# MODELED licensed PHY: geometry/timing assumptions, not silicon signoff
VERSION 5.8 ;
BUSBITCHARS "[]" ;
DIVIDERCHAR "/" ;
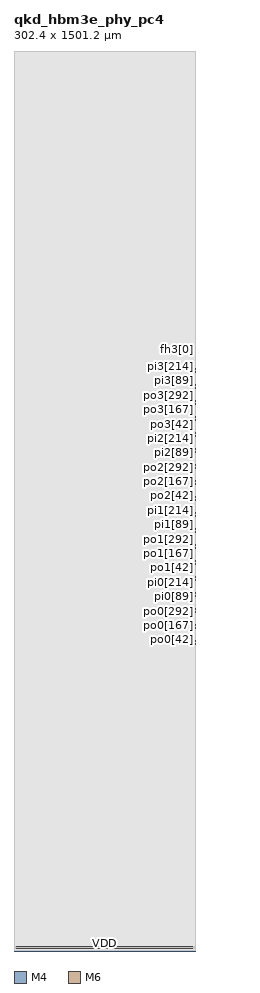
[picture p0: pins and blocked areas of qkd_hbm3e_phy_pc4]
MACRO qkd_hbm3e_phy_pc4
 CLASS BLOCK ;
 ORIGIN 0 0 ;
 SYMMETRY X Y ;
 SIZE 302.4 BY 1501.2 ;
 PIN clk
  DIRECTION INPUT ;
  USE CLOCK ;
  PORT
   LAYER M4 ;
   RECT 302.208000 510.540000 302.400000 510.564000 ;
  END
 END clk
 PIN rst_n
  DIRECTION INPUT ;
  USE SIGNAL ;
  PORT
   LAYER M4 ;
   RECT 302.208000 510.732000 302.400000 510.756000 ;
  END
 END rst_n
 PIN po0[0]
  DIRECTION INPUT ;
  USE SIGNAL ;
  PORT
   LAYER M4 ;
   RECT 302.208000 510.924000 302.400000 510.948000 ;
  END
 END po0[0]
 PIN po0[1]
  DIRECTION INPUT ;
  USE SIGNAL ;
  PORT
   LAYER M4 ;
   RECT 302.208000 511.116000 302.400000 511.140000 ;
  END
 END po0[1]
 PIN po0[2]
  DIRECTION INPUT ;
  USE SIGNAL ;
  PORT
   LAYER M4 ;
   RECT 302.208000 511.308000 302.400000 511.332000 ;
  END
 END po0[2]
 PIN po0[3]
  DIRECTION INPUT ;
  USE SIGNAL ;
  PORT
   LAYER M4 ;
   RECT 302.208000 511.500000 302.400000 511.524000 ;
  END
 END po0[3]
 PIN po0[4]
  DIRECTION INPUT ;
  USE SIGNAL ;
  PORT
   LAYER M4 ;
   RECT 302.208000 511.692000 302.400000 511.716000 ;
  END
 END po0[4]
 PIN po0[5]
  DIRECTION INPUT ;
  USE SIGNAL ;
  PORT
   LAYER M4 ;
   RECT 302.208000 511.884000 302.400000 511.908000 ;
  END
 END po0[5]
 PIN po0[6]
  DIRECTION INPUT ;
  USE SIGNAL ;
  PORT
   LAYER M4 ;
   RECT 302.208000 512.076000 302.400000 512.100000 ;
  END
 END po0[6]
 PIN po0[7]
  DIRECTION INPUT ;
  USE SIGNAL ;
  PORT
   LAYER M4 ;
   RECT 302.208000 512.268000 302.400000 512.292000 ;
  END
 END po0[7]
 PIN po0[8]
  DIRECTION INPUT ;
  USE SIGNAL ;
  PORT
   LAYER M4 ;
   RECT 302.208000 512.460000 302.400000 512.484000 ;
  END
 END po0[8]
 PIN po0[9]
  DIRECTION INPUT ;
  USE SIGNAL ;
  PORT
   LAYER M4 ;
   RECT 302.208000 512.652000 302.400000 512.676000 ;
  END
 END po0[9]
 PIN po0[10]
  DIRECTION INPUT ;
  USE SIGNAL ;
  PORT
   LAYER M4 ;
   RECT 302.208000 512.844000 302.400000 512.868000 ;
  END
 END po0[10]
 PIN po0[11]
  DIRECTION INPUT ;
  USE SIGNAL ;
  PORT
   LAYER M4 ;
   RECT 302.208000 513.036000 302.400000 513.060000 ;
  END
 END po0[11]
 PIN po0[12]
  DIRECTION INPUT ;
  USE SIGNAL ;
  PORT
   LAYER M4 ;
   RECT 302.208000 513.228000 302.400000 513.252000 ;
  END
 END po0[12]
 PIN po0[13]
  DIRECTION INPUT ;
  USE SIGNAL ;
  PORT
   LAYER M4 ;
   RECT 302.208000 513.420000 302.400000 513.444000 ;
  END
 END po0[13]
 PIN po0[14]
  DIRECTION INPUT ;
  USE SIGNAL ;
  PORT
   LAYER M4 ;
   RECT 302.208000 513.612000 302.400000 513.636000 ;
  END
 END po0[14]
 PIN po0[15]
  DIRECTION INPUT ;
  USE SIGNAL ;
  PORT
   LAYER M4 ;
   RECT 302.208000 513.804000 302.400000 513.828000 ;
  END
 END po0[15]
 PIN po0[16]
  DIRECTION INPUT ;
  USE SIGNAL ;
  PORT
   LAYER M4 ;
   RECT 302.208000 513.996000 302.400000 514.020000 ;
  END
 END po0[16]
 PIN po0[17]
  DIRECTION INPUT ;
  USE SIGNAL ;
  PORT
   LAYER M4 ;
   RECT 302.208000 514.188000 302.400000 514.212000 ;
  END
 END po0[17]
 PIN po0[18]
  DIRECTION INPUT ;
  USE SIGNAL ;
  PORT
   LAYER M4 ;
   RECT 302.208000 514.380000 302.400000 514.404000 ;
  END
 END po0[18]
 PIN po0[19]
  DIRECTION INPUT ;
  USE SIGNAL ;
  PORT
   LAYER M4 ;
   RECT 302.208000 514.572000 302.400000 514.596000 ;
  END
 END po0[19]
 PIN po0[20]
  DIRECTION INPUT ;
  USE SIGNAL ;
  PORT
   LAYER M4 ;
   RECT 302.208000 514.764000 302.400000 514.788000 ;
  END
 END po0[20]
 PIN po0[21]
  DIRECTION INPUT ;
  USE SIGNAL ;
  PORT
   LAYER M4 ;
   RECT 302.208000 514.956000 302.400000 514.980000 ;
  END
 END po0[21]
 PIN po0[22]
  DIRECTION INPUT ;
  USE SIGNAL ;
  PORT
   LAYER M4 ;
   RECT 302.208000 515.148000 302.400000 515.172000 ;
  END
 END po0[22]
 PIN po0[23]
  DIRECTION INPUT ;
  USE SIGNAL ;
  PORT
   LAYER M4 ;
   RECT 302.208000 515.340000 302.400000 515.364000 ;
  END
 END po0[23]
 PIN po0[24]
  DIRECTION INPUT ;
  USE SIGNAL ;
  PORT
   LAYER M4 ;
   RECT 302.208000 515.532000 302.400000 515.556000 ;
  END
 END po0[24]
 PIN po0[25]
  DIRECTION INPUT ;
  USE SIGNAL ;
  PORT
   LAYER M4 ;
   RECT 302.208000 515.724000 302.400000 515.748000 ;
  END
 END po0[25]
 PIN po0[26]
  DIRECTION INPUT ;
  USE SIGNAL ;
  PORT
   LAYER M4 ;
   RECT 302.208000 515.916000 302.400000 515.940000 ;
  END
 END po0[26]
 PIN po0[27]
  DIRECTION INPUT ;
  USE SIGNAL ;
  PORT
   LAYER M4 ;
   RECT 302.208000 516.108000 302.400000 516.132000 ;
  END
 END po0[27]
 PIN po0[28]
  DIRECTION INPUT ;
  USE SIGNAL ;
  PORT
   LAYER M4 ;
   RECT 302.208000 516.300000 302.400000 516.324000 ;
  END
 END po0[28]
 PIN po0[29]
  DIRECTION INPUT ;
  USE SIGNAL ;
  PORT
   LAYER M4 ;
   RECT 302.208000 516.492000 302.400000 516.516000 ;
  END
 END po0[29]
 PIN po0[30]
  DIRECTION INPUT ;
  USE SIGNAL ;
  PORT
   LAYER M4 ;
   RECT 302.208000 516.684000 302.400000 516.708000 ;
  END
 END po0[30]
 PIN po0[31]
  DIRECTION INPUT ;
  USE SIGNAL ;
  PORT
   LAYER M4 ;
   RECT 302.208000 516.876000 302.400000 516.900000 ;
  END
 END po0[31]
 PIN po0[32]
  DIRECTION INPUT ;
  USE SIGNAL ;
  PORT
   LAYER M4 ;
   RECT 302.208000 517.068000 302.400000 517.092000 ;
  END
 END po0[32]
 PIN po0[33]
  DIRECTION INPUT ;
  USE SIGNAL ;
  PORT
   LAYER M4 ;
   RECT 302.208000 517.260000 302.400000 517.284000 ;
  END
 END po0[33]
 PIN po0[34]
  DIRECTION INPUT ;
  USE SIGNAL ;
  PORT
   LAYER M4 ;
   RECT 302.208000 517.452000 302.400000 517.476000 ;
  END
 END po0[34]
 PIN po0[35]
  DIRECTION INPUT ;
  USE SIGNAL ;
  PORT
   LAYER M4 ;
   RECT 302.208000 517.644000 302.400000 517.668000 ;
  END
 END po0[35]
 PIN po0[36]
  DIRECTION INPUT ;
  USE SIGNAL ;
  PORT
   LAYER M4 ;
   RECT 302.208000 517.836000 302.400000 517.860000 ;
  END
 END po0[36]
 PIN po0[37]
  DIRECTION INPUT ;
  USE SIGNAL ;
  PORT
   LAYER M4 ;
   RECT 302.208000 518.028000 302.400000 518.052000 ;
  END
 END po0[37]
 PIN po0[38]
  DIRECTION INPUT ;
  USE SIGNAL ;
  PORT
   LAYER M4 ;
   RECT 302.208000 518.220000 302.400000 518.244000 ;
  END
 END po0[38]
 PIN po0[39]
  DIRECTION INPUT ;
  USE SIGNAL ;
  PORT
   LAYER M4 ;
   RECT 302.208000 518.412000 302.400000 518.436000 ;
  END
 END po0[39]
 PIN po0[40]
  DIRECTION INPUT ;
  USE SIGNAL ;
  PORT
   LAYER M4 ;
   RECT 302.208000 518.604000 302.400000 518.628000 ;
  END
 END po0[40]
 PIN po0[41]
  DIRECTION INPUT ;
  USE SIGNAL ;
  PORT
   LAYER M4 ;
   RECT 302.208000 518.796000 302.400000 518.820000 ;
  END
 END po0[41]
 PIN po0[42]
  DIRECTION INPUT ;
  USE SIGNAL ;
  PORT
   LAYER M4 ;
   RECT 302.208000 518.988000 302.400000 519.012000 ;
  END
 END po0[42]
 PIN po0[43]
  DIRECTION INPUT ;
  USE SIGNAL ;
  PORT
   LAYER M4 ;
   RECT 302.208000 519.180000 302.400000 519.204000 ;
  END
 END po0[43]
 PIN po0[44]
  DIRECTION INPUT ;
  USE SIGNAL ;
  PORT
   LAYER M4 ;
   RECT 302.208000 519.372000 302.400000 519.396000 ;
  END
 END po0[44]
 PIN po0[45]
  DIRECTION INPUT ;
  USE SIGNAL ;
  PORT
   LAYER M4 ;
   RECT 302.208000 519.564000 302.400000 519.588000 ;
  END
 END po0[45]
 PIN po0[46]
  DIRECTION INPUT ;
  USE SIGNAL ;
  PORT
   LAYER M4 ;
   RECT 302.208000 519.756000 302.400000 519.780000 ;
  END
 END po0[46]
 PIN po0[47]
  DIRECTION INPUT ;
  USE SIGNAL ;
  PORT
   LAYER M4 ;
   RECT 302.208000 519.948000 302.400000 519.972000 ;
  END
 END po0[47]
 PIN po0[48]
  DIRECTION INPUT ;
  USE SIGNAL ;
  PORT
   LAYER M4 ;
   RECT 302.208000 520.140000 302.400000 520.164000 ;
  END
 END po0[48]
 PIN po0[49]
  DIRECTION INPUT ;
  USE SIGNAL ;
  PORT
   LAYER M4 ;
   RECT 302.208000 520.332000 302.400000 520.356000 ;
  END
 END po0[49]
 PIN po0[50]
  DIRECTION INPUT ;
  USE SIGNAL ;
  PORT
   LAYER M4 ;
   RECT 302.208000 520.524000 302.400000 520.548000 ;
  END
 END po0[50]
 PIN po0[51]
  DIRECTION INPUT ;
  USE SIGNAL ;
  PORT
   LAYER M4 ;
   RECT 302.208000 520.716000 302.400000 520.740000 ;
  END
 END po0[51]
 PIN po0[52]
  DIRECTION INPUT ;
  USE SIGNAL ;
  PORT
   LAYER M4 ;
   RECT 302.208000 520.908000 302.400000 520.932000 ;
  END
 END po0[52]
 PIN po0[53]
  DIRECTION INPUT ;
  USE SIGNAL ;
  PORT
   LAYER M4 ;
   RECT 302.208000 521.100000 302.400000 521.124000 ;
  END
 END po0[53]
 PIN po0[54]
  DIRECTION INPUT ;
  USE SIGNAL ;
  PORT
   LAYER M4 ;
   RECT 302.208000 521.292000 302.400000 521.316000 ;
  END
 END po0[54]
 PIN po0[55]
  DIRECTION INPUT ;
  USE SIGNAL ;
  PORT
   LAYER M4 ;
   RECT 302.208000 521.484000 302.400000 521.508000 ;
  END
 END po0[55]
 PIN po0[56]
  DIRECTION INPUT ;
  USE SIGNAL ;
  PORT
   LAYER M4 ;
   RECT 302.208000 521.676000 302.400000 521.700000 ;
  END
 END po0[56]
 PIN po0[57]
  DIRECTION INPUT ;
  USE SIGNAL ;
  PORT
   LAYER M4 ;
   RECT 302.208000 521.868000 302.400000 521.892000 ;
  END
 END po0[57]
 PIN po0[58]
  DIRECTION INPUT ;
  USE SIGNAL ;
  PORT
   LAYER M4 ;
   RECT 302.208000 522.060000 302.400000 522.084000 ;
  END
 END po0[58]
 PIN po0[59]
  DIRECTION INPUT ;
  USE SIGNAL ;
  PORT
   LAYER M4 ;
   RECT 302.208000 522.252000 302.400000 522.276000 ;
  END
 END po0[59]
 PIN po0[60]
  DIRECTION INPUT ;
  USE SIGNAL ;
  PORT
   LAYER M4 ;
   RECT 302.208000 522.444000 302.400000 522.468000 ;
  END
 END po0[60]
 PIN po0[61]
  DIRECTION INPUT ;
  USE SIGNAL ;
  PORT
   LAYER M4 ;
   RECT 302.208000 522.636000 302.400000 522.660000 ;
  END
 END po0[61]
 PIN po0[62]
  DIRECTION INPUT ;
  USE SIGNAL ;
  PORT
   LAYER M4 ;
   RECT 302.208000 522.828000 302.400000 522.852000 ;
  END
 END po0[62]
 PIN po0[63]
  DIRECTION INPUT ;
  USE SIGNAL ;
  PORT
   LAYER M4 ;
   RECT 302.208000 523.020000 302.400000 523.044000 ;
  END
 END po0[63]
 PIN po0[64]
  DIRECTION INPUT ;
  USE SIGNAL ;
  PORT
   LAYER M4 ;
   RECT 302.208000 523.212000 302.400000 523.236000 ;
  END
 END po0[64]
 PIN po0[65]
  DIRECTION INPUT ;
  USE SIGNAL ;
  PORT
   LAYER M4 ;
   RECT 302.208000 523.404000 302.400000 523.428000 ;
  END
 END po0[65]
 PIN po0[66]
  DIRECTION INPUT ;
  USE SIGNAL ;
  PORT
   LAYER M4 ;
   RECT 302.208000 523.596000 302.400000 523.620000 ;
  END
 END po0[66]
 PIN po0[67]
  DIRECTION INPUT ;
  USE SIGNAL ;
  PORT
   LAYER M4 ;
   RECT 302.208000 523.788000 302.400000 523.812000 ;
  END
 END po0[67]
 PIN po0[68]
  DIRECTION INPUT ;
  USE SIGNAL ;
  PORT
   LAYER M4 ;
   RECT 302.208000 523.980000 302.400000 524.004000 ;
  END
 END po0[68]
 PIN po0[69]
  DIRECTION INPUT ;
  USE SIGNAL ;
  PORT
   LAYER M4 ;
   RECT 302.208000 524.172000 302.400000 524.196000 ;
  END
 END po0[69]
 PIN po0[70]
  DIRECTION INPUT ;
  USE SIGNAL ;
  PORT
   LAYER M4 ;
   RECT 302.208000 524.364000 302.400000 524.388000 ;
  END
 END po0[70]
 PIN po0[71]
  DIRECTION INPUT ;
  USE SIGNAL ;
  PORT
   LAYER M4 ;
   RECT 302.208000 524.556000 302.400000 524.580000 ;
  END
 END po0[71]
 PIN po0[72]
  DIRECTION INPUT ;
  USE SIGNAL ;
  PORT
   LAYER M4 ;
   RECT 302.208000 524.748000 302.400000 524.772000 ;
  END
 END po0[72]
 PIN po0[73]
  DIRECTION INPUT ;
  USE SIGNAL ;
  PORT
   LAYER M4 ;
   RECT 302.208000 524.940000 302.400000 524.964000 ;
  END
 END po0[73]
 PIN po0[74]
  DIRECTION INPUT ;
  USE SIGNAL ;
  PORT
   LAYER M4 ;
   RECT 302.208000 525.132000 302.400000 525.156000 ;
  END
 END po0[74]
 PIN po0[75]
  DIRECTION INPUT ;
  USE SIGNAL ;
  PORT
   LAYER M4 ;
   RECT 302.208000 525.324000 302.400000 525.348000 ;
  END
 END po0[75]
 PIN po0[76]
  DIRECTION INPUT ;
  USE SIGNAL ;
  PORT
   LAYER M4 ;
   RECT 302.208000 525.516000 302.400000 525.540000 ;
  END
 END po0[76]
 PIN po0[77]
  DIRECTION INPUT ;
  USE SIGNAL ;
  PORT
   LAYER M4 ;
   RECT 302.208000 525.708000 302.400000 525.732000 ;
  END
 END po0[77]
 PIN po0[78]
  DIRECTION INPUT ;
  USE SIGNAL ;
  PORT
   LAYER M4 ;
   RECT 302.208000 525.900000 302.400000 525.924000 ;
  END
 END po0[78]
 PIN po0[79]
  DIRECTION INPUT ;
  USE SIGNAL ;
  PORT
   LAYER M4 ;
   RECT 302.208000 526.092000 302.400000 526.116000 ;
  END
 END po0[79]
 PIN po0[80]
  DIRECTION INPUT ;
  USE SIGNAL ;
  PORT
   LAYER M4 ;
   RECT 302.208000 526.284000 302.400000 526.308000 ;
  END
 END po0[80]
 PIN po0[81]
  DIRECTION INPUT ;
  USE SIGNAL ;
  PORT
   LAYER M4 ;
   RECT 302.208000 526.476000 302.400000 526.500000 ;
  END
 END po0[81]
 PIN po0[82]
  DIRECTION INPUT ;
  USE SIGNAL ;
  PORT
   LAYER M4 ;
   RECT 302.208000 526.668000 302.400000 526.692000 ;
  END
 END po0[82]
 PIN po0[83]
  DIRECTION INPUT ;
  USE SIGNAL ;
  PORT
   LAYER M4 ;
   RECT 302.208000 526.860000 302.400000 526.884000 ;
  END
 END po0[83]
 PIN po0[84]
  DIRECTION INPUT ;
  USE SIGNAL ;
  PORT
   LAYER M4 ;
   RECT 302.208000 527.052000 302.400000 527.076000 ;
  END
 END po0[84]
 PIN po0[85]
  DIRECTION INPUT ;
  USE SIGNAL ;
  PORT
   LAYER M4 ;
   RECT 302.208000 527.244000 302.400000 527.268000 ;
  END
 END po0[85]
 PIN po0[86]
  DIRECTION INPUT ;
  USE SIGNAL ;
  PORT
   LAYER M4 ;
   RECT 302.208000 527.436000 302.400000 527.460000 ;
  END
 END po0[86]
 PIN po0[87]
  DIRECTION INPUT ;
  USE SIGNAL ;
  PORT
   LAYER M4 ;
   RECT 302.208000 527.628000 302.400000 527.652000 ;
  END
 END po0[87]
 PIN po0[88]
  DIRECTION INPUT ;
  USE SIGNAL ;
  PORT
   LAYER M4 ;
   RECT 302.208000 527.820000 302.400000 527.844000 ;
  END
 END po0[88]
 PIN po0[89]
  DIRECTION INPUT ;
  USE SIGNAL ;
  PORT
   LAYER M4 ;
   RECT 302.208000 528.012000 302.400000 528.036000 ;
  END
 END po0[89]
 PIN po0[90]
  DIRECTION INPUT ;
  USE SIGNAL ;
  PORT
   LAYER M4 ;
   RECT 302.208000 528.204000 302.400000 528.228000 ;
  END
 END po0[90]
 PIN po0[91]
  DIRECTION INPUT ;
  USE SIGNAL ;
  PORT
   LAYER M4 ;
   RECT 302.208000 528.396000 302.400000 528.420000 ;
  END
 END po0[91]
 PIN po0[92]
  DIRECTION INPUT ;
  USE SIGNAL ;
  PORT
   LAYER M4 ;
   RECT 302.208000 528.588000 302.400000 528.612000 ;
  END
 END po0[92]
 PIN po0[93]
  DIRECTION INPUT ;
  USE SIGNAL ;
  PORT
   LAYER M4 ;
   RECT 302.208000 528.780000 302.400000 528.804000 ;
  END
 END po0[93]
 PIN po0[94]
  DIRECTION INPUT ;
  USE SIGNAL ;
  PORT
   LAYER M4 ;
   RECT 302.208000 528.972000 302.400000 528.996000 ;
  END
 END po0[94]
 PIN po0[95]
  DIRECTION INPUT ;
  USE SIGNAL ;
  PORT
   LAYER M4 ;
   RECT 302.208000 529.164000 302.400000 529.188000 ;
  END
 END po0[95]
 PIN po0[96]
  DIRECTION INPUT ;
  USE SIGNAL ;
  PORT
   LAYER M4 ;
   RECT 302.208000 529.356000 302.400000 529.380000 ;
  END
 END po0[96]
 PIN po0[97]
  DIRECTION INPUT ;
  USE SIGNAL ;
  PORT
   LAYER M4 ;
   RECT 302.208000 529.548000 302.400000 529.572000 ;
  END
 END po0[97]
 PIN po0[98]
  DIRECTION INPUT ;
  USE SIGNAL ;
  PORT
   LAYER M4 ;
   RECT 302.208000 529.740000 302.400000 529.764000 ;
  END
 END po0[98]
 PIN po0[99]
  DIRECTION INPUT ;
  USE SIGNAL ;
  PORT
   LAYER M4 ;
   RECT 302.208000 529.932000 302.400000 529.956000 ;
  END
 END po0[99]
 PIN po0[100]
  DIRECTION INPUT ;
  USE SIGNAL ;
  PORT
   LAYER M4 ;
   RECT 302.208000 530.124000 302.400000 530.148000 ;
  END
 END po0[100]
 PIN po0[101]
  DIRECTION INPUT ;
  USE SIGNAL ;
  PORT
   LAYER M4 ;
   RECT 302.208000 530.316000 302.400000 530.340000 ;
  END
 END po0[101]
 PIN po0[102]
  DIRECTION INPUT ;
  USE SIGNAL ;
  PORT
   LAYER M4 ;
   RECT 302.208000 530.508000 302.400000 530.532000 ;
  END
 END po0[102]
 PIN po0[103]
  DIRECTION INPUT ;
  USE SIGNAL ;
  PORT
   LAYER M4 ;
   RECT 302.208000 530.700000 302.400000 530.724000 ;
  END
 END po0[103]
 PIN po0[104]
  DIRECTION INPUT ;
  USE SIGNAL ;
  PORT
   LAYER M4 ;
   RECT 302.208000 530.892000 302.400000 530.916000 ;
  END
 END po0[104]
 PIN po0[105]
  DIRECTION INPUT ;
  USE SIGNAL ;
  PORT
   LAYER M4 ;
   RECT 302.208000 531.084000 302.400000 531.108000 ;
  END
 END po0[105]
 PIN po0[106]
  DIRECTION INPUT ;
  USE SIGNAL ;
  PORT
   LAYER M4 ;
   RECT 302.208000 531.276000 302.400000 531.300000 ;
  END
 END po0[106]
 PIN po0[107]
  DIRECTION INPUT ;
  USE SIGNAL ;
  PORT
   LAYER M4 ;
   RECT 302.208000 531.468000 302.400000 531.492000 ;
  END
 END po0[107]
 PIN po0[108]
  DIRECTION INPUT ;
  USE SIGNAL ;
  PORT
   LAYER M4 ;
   RECT 302.208000 531.660000 302.400000 531.684000 ;
  END
 END po0[108]
 PIN po0[109]
  DIRECTION INPUT ;
  USE SIGNAL ;
  PORT
   LAYER M4 ;
   RECT 302.208000 531.852000 302.400000 531.876000 ;
  END
 END po0[109]
 PIN po0[110]
  DIRECTION INPUT ;
  USE SIGNAL ;
  PORT
   LAYER M4 ;
   RECT 302.208000 532.044000 302.400000 532.068000 ;
  END
 END po0[110]
 PIN po0[111]
  DIRECTION INPUT ;
  USE SIGNAL ;
  PORT
   LAYER M4 ;
   RECT 302.208000 532.236000 302.400000 532.260000 ;
  END
 END po0[111]
 PIN po0[112]
  DIRECTION INPUT ;
  USE SIGNAL ;
  PORT
   LAYER M4 ;
   RECT 302.208000 532.428000 302.400000 532.452000 ;
  END
 END po0[112]
 PIN po0[113]
  DIRECTION INPUT ;
  USE SIGNAL ;
  PORT
   LAYER M4 ;
   RECT 302.208000 532.620000 302.400000 532.644000 ;
  END
 END po0[113]
 PIN po0[114]
  DIRECTION INPUT ;
  USE SIGNAL ;
  PORT
   LAYER M4 ;
   RECT 302.208000 532.812000 302.400000 532.836000 ;
  END
 END po0[114]
 PIN po0[115]
  DIRECTION INPUT ;
  USE SIGNAL ;
  PORT
   LAYER M4 ;
   RECT 302.208000 533.004000 302.400000 533.028000 ;
  END
 END po0[115]
 PIN po0[116]
  DIRECTION INPUT ;
  USE SIGNAL ;
  PORT
   LAYER M4 ;
   RECT 302.208000 533.196000 302.400000 533.220000 ;
  END
 END po0[116]
 PIN po0[117]
  DIRECTION INPUT ;
  USE SIGNAL ;
  PORT
   LAYER M4 ;
   RECT 302.208000 533.388000 302.400000 533.412000 ;
  END
 END po0[117]
 PIN po0[118]
  DIRECTION INPUT ;
  USE SIGNAL ;
  PORT
   LAYER M4 ;
   RECT 302.208000 533.580000 302.400000 533.604000 ;
  END
 END po0[118]
 PIN po0[119]
  DIRECTION INPUT ;
  USE SIGNAL ;
  PORT
   LAYER M4 ;
   RECT 302.208000 533.772000 302.400000 533.796000 ;
  END
 END po0[119]
 PIN po0[120]
  DIRECTION INPUT ;
  USE SIGNAL ;
  PORT
   LAYER M4 ;
   RECT 302.208000 533.964000 302.400000 533.988000 ;
  END
 END po0[120]
 PIN po0[121]
  DIRECTION INPUT ;
  USE SIGNAL ;
  PORT
   LAYER M4 ;
   RECT 302.208000 534.156000 302.400000 534.180000 ;
  END
 END po0[121]
 PIN po0[122]
  DIRECTION INPUT ;
  USE SIGNAL ;
  PORT
   LAYER M4 ;
   RECT 302.208000 534.348000 302.400000 534.372000 ;
  END
 END po0[122]
 PIN po0[123]
  DIRECTION INPUT ;
  USE SIGNAL ;
  PORT
   LAYER M4 ;
   RECT 302.208000 534.540000 302.400000 534.564000 ;
  END
 END po0[123]
 PIN po0[124]
  DIRECTION INPUT ;
  USE SIGNAL ;
  PORT
   LAYER M4 ;
   RECT 302.208000 534.732000 302.400000 534.756000 ;
  END
 END po0[124]
 PIN po0[125]
  DIRECTION INPUT ;
  USE SIGNAL ;
  PORT
   LAYER M4 ;
   RECT 302.208000 534.924000 302.400000 534.948000 ;
  END
 END po0[125]
 PIN po0[126]
  DIRECTION INPUT ;
  USE SIGNAL ;
  PORT
   LAYER M4 ;
   RECT 302.208000 535.116000 302.400000 535.140000 ;
  END
 END po0[126]
 PIN po0[127]
  DIRECTION INPUT ;
  USE SIGNAL ;
  PORT
   LAYER M4 ;
   RECT 302.208000 535.308000 302.400000 535.332000 ;
  END
 END po0[127]
 PIN po0[128]
  DIRECTION INPUT ;
  USE SIGNAL ;
  PORT
   LAYER M4 ;
   RECT 302.208000 535.500000 302.400000 535.524000 ;
  END
 END po0[128]
 PIN po0[129]
  DIRECTION INPUT ;
  USE SIGNAL ;
  PORT
   LAYER M4 ;
   RECT 302.208000 535.692000 302.400000 535.716000 ;
  END
 END po0[129]
 PIN po0[130]
  DIRECTION INPUT ;
  USE SIGNAL ;
  PORT
   LAYER M4 ;
   RECT 302.208000 535.884000 302.400000 535.908000 ;
  END
 END po0[130]
 PIN po0[131]
  DIRECTION INPUT ;
  USE SIGNAL ;
  PORT
   LAYER M4 ;
   RECT 302.208000 536.076000 302.400000 536.100000 ;
  END
 END po0[131]
 PIN po0[132]
  DIRECTION INPUT ;
  USE SIGNAL ;
  PORT
   LAYER M4 ;
   RECT 302.208000 536.268000 302.400000 536.292000 ;
  END
 END po0[132]
 PIN po0[133]
  DIRECTION INPUT ;
  USE SIGNAL ;
  PORT
   LAYER M4 ;
   RECT 302.208000 536.460000 302.400000 536.484000 ;
  END
 END po0[133]
 PIN po0[134]
  DIRECTION INPUT ;
  USE SIGNAL ;
  PORT
   LAYER M4 ;
   RECT 302.208000 536.652000 302.400000 536.676000 ;
  END
 END po0[134]
 PIN po0[135]
  DIRECTION INPUT ;
  USE SIGNAL ;
  PORT
   LAYER M4 ;
   RECT 302.208000 536.844000 302.400000 536.868000 ;
  END
 END po0[135]
 PIN po0[136]
  DIRECTION INPUT ;
  USE SIGNAL ;
  PORT
   LAYER M4 ;
   RECT 302.208000 537.036000 302.400000 537.060000 ;
  END
 END po0[136]
 PIN po0[137]
  DIRECTION INPUT ;
  USE SIGNAL ;
  PORT
   LAYER M4 ;
   RECT 302.208000 537.228000 302.400000 537.252000 ;
  END
 END po0[137]
 PIN po0[138]
  DIRECTION INPUT ;
  USE SIGNAL ;
  PORT
   LAYER M4 ;
   RECT 302.208000 537.420000 302.400000 537.444000 ;
  END
 END po0[138]
 PIN po0[139]
  DIRECTION INPUT ;
  USE SIGNAL ;
  PORT
   LAYER M4 ;
   RECT 302.208000 537.612000 302.400000 537.636000 ;
  END
 END po0[139]
 PIN po0[140]
  DIRECTION INPUT ;
  USE SIGNAL ;
  PORT
   LAYER M4 ;
   RECT 302.208000 537.804000 302.400000 537.828000 ;
  END
 END po0[140]
 PIN po0[141]
  DIRECTION INPUT ;
  USE SIGNAL ;
  PORT
   LAYER M4 ;
   RECT 302.208000 537.996000 302.400000 538.020000 ;
  END
 END po0[141]
 PIN po0[142]
  DIRECTION INPUT ;
  USE SIGNAL ;
  PORT
   LAYER M4 ;
   RECT 302.208000 538.188000 302.400000 538.212000 ;
  END
 END po0[142]
 PIN po0[143]
  DIRECTION INPUT ;
  USE SIGNAL ;
  PORT
   LAYER M4 ;
   RECT 302.208000 538.380000 302.400000 538.404000 ;
  END
 END po0[143]
 PIN po0[144]
  DIRECTION INPUT ;
  USE SIGNAL ;
  PORT
   LAYER M4 ;
   RECT 302.208000 538.572000 302.400000 538.596000 ;
  END
 END po0[144]
 PIN po0[145]
  DIRECTION INPUT ;
  USE SIGNAL ;
  PORT
   LAYER M4 ;
   RECT 302.208000 538.764000 302.400000 538.788000 ;
  END
 END po0[145]
 PIN po0[146]
  DIRECTION INPUT ;
  USE SIGNAL ;
  PORT
   LAYER M4 ;
   RECT 302.208000 538.956000 302.400000 538.980000 ;
  END
 END po0[146]
 PIN po0[147]
  DIRECTION INPUT ;
  USE SIGNAL ;
  PORT
   LAYER M4 ;
   RECT 302.208000 539.148000 302.400000 539.172000 ;
  END
 END po0[147]
 PIN po0[148]
  DIRECTION INPUT ;
  USE SIGNAL ;
  PORT
   LAYER M4 ;
   RECT 302.208000 539.340000 302.400000 539.364000 ;
  END
 END po0[148]
 PIN po0[149]
  DIRECTION INPUT ;
  USE SIGNAL ;
  PORT
   LAYER M4 ;
   RECT 302.208000 539.532000 302.400000 539.556000 ;
  END
 END po0[149]
 PIN po0[150]
  DIRECTION INPUT ;
  USE SIGNAL ;
  PORT
   LAYER M4 ;
   RECT 302.208000 539.724000 302.400000 539.748000 ;
  END
 END po0[150]
 PIN po0[151]
  DIRECTION INPUT ;
  USE SIGNAL ;
  PORT
   LAYER M4 ;
   RECT 302.208000 539.916000 302.400000 539.940000 ;
  END
 END po0[151]
 PIN po0[152]
  DIRECTION INPUT ;
  USE SIGNAL ;
  PORT
   LAYER M4 ;
   RECT 302.208000 540.108000 302.400000 540.132000 ;
  END
 END po0[152]
 PIN po0[153]
  DIRECTION INPUT ;
  USE SIGNAL ;
  PORT
   LAYER M4 ;
   RECT 302.208000 540.300000 302.400000 540.324000 ;
  END
 END po0[153]
 PIN po0[154]
  DIRECTION INPUT ;
  USE SIGNAL ;
  PORT
   LAYER M4 ;
   RECT 302.208000 540.492000 302.400000 540.516000 ;
  END
 END po0[154]
 PIN po0[155]
  DIRECTION INPUT ;
  USE SIGNAL ;
  PORT
   LAYER M4 ;
   RECT 302.208000 540.684000 302.400000 540.708000 ;
  END
 END po0[155]
 PIN po0[156]
  DIRECTION INPUT ;
  USE SIGNAL ;
  PORT
   LAYER M4 ;
   RECT 302.208000 540.876000 302.400000 540.900000 ;
  END
 END po0[156]
 PIN po0[157]
  DIRECTION INPUT ;
  USE SIGNAL ;
  PORT
   LAYER M4 ;
   RECT 302.208000 541.068000 302.400000 541.092000 ;
  END
 END po0[157]
 PIN po0[158]
  DIRECTION INPUT ;
  USE SIGNAL ;
  PORT
   LAYER M4 ;
   RECT 302.208000 541.260000 302.400000 541.284000 ;
  END
 END po0[158]
 PIN po0[159]
  DIRECTION INPUT ;
  USE SIGNAL ;
  PORT
   LAYER M4 ;
   RECT 302.208000 541.452000 302.400000 541.476000 ;
  END
 END po0[159]
 PIN po0[160]
  DIRECTION INPUT ;
  USE SIGNAL ;
  PORT
   LAYER M4 ;
   RECT 302.208000 541.644000 302.400000 541.668000 ;
  END
 END po0[160]
 PIN po0[161]
  DIRECTION INPUT ;
  USE SIGNAL ;
  PORT
   LAYER M4 ;
   RECT 302.208000 541.836000 302.400000 541.860000 ;
  END
 END po0[161]
 PIN po0[162]
  DIRECTION INPUT ;
  USE SIGNAL ;
  PORT
   LAYER M4 ;
   RECT 302.208000 542.028000 302.400000 542.052000 ;
  END
 END po0[162]
 PIN po0[163]
  DIRECTION INPUT ;
  USE SIGNAL ;
  PORT
   LAYER M4 ;
   RECT 302.208000 542.220000 302.400000 542.244000 ;
  END
 END po0[163]
 PIN po0[164]
  DIRECTION INPUT ;
  USE SIGNAL ;
  PORT
   LAYER M4 ;
   RECT 302.208000 542.412000 302.400000 542.436000 ;
  END
 END po0[164]
 PIN po0[165]
  DIRECTION INPUT ;
  USE SIGNAL ;
  PORT
   LAYER M4 ;
   RECT 302.208000 542.604000 302.400000 542.628000 ;
  END
 END po0[165]
 PIN po0[166]
  DIRECTION INPUT ;
  USE SIGNAL ;
  PORT
   LAYER M4 ;
   RECT 302.208000 542.796000 302.400000 542.820000 ;
  END
 END po0[166]
 PIN po0[167]
  DIRECTION INPUT ;
  USE SIGNAL ;
  PORT
   LAYER M4 ;
   RECT 302.208000 542.988000 302.400000 543.012000 ;
  END
 END po0[167]
 PIN po0[168]
  DIRECTION INPUT ;
  USE SIGNAL ;
  PORT
   LAYER M4 ;
   RECT 302.208000 543.180000 302.400000 543.204000 ;
  END
 END po0[168]
 PIN po0[169]
  DIRECTION INPUT ;
  USE SIGNAL ;
  PORT
   LAYER M4 ;
   RECT 302.208000 543.372000 302.400000 543.396000 ;
  END
 END po0[169]
 PIN po0[170]
  DIRECTION INPUT ;
  USE SIGNAL ;
  PORT
   LAYER M4 ;
   RECT 302.208000 543.564000 302.400000 543.588000 ;
  END
 END po0[170]
 PIN po0[171]
  DIRECTION INPUT ;
  USE SIGNAL ;
  PORT
   LAYER M4 ;
   RECT 302.208000 543.756000 302.400000 543.780000 ;
  END
 END po0[171]
 PIN po0[172]
  DIRECTION INPUT ;
  USE SIGNAL ;
  PORT
   LAYER M4 ;
   RECT 302.208000 543.948000 302.400000 543.972000 ;
  END
 END po0[172]
 PIN po0[173]
  DIRECTION INPUT ;
  USE SIGNAL ;
  PORT
   LAYER M4 ;
   RECT 302.208000 544.140000 302.400000 544.164000 ;
  END
 END po0[173]
 PIN po0[174]
  DIRECTION INPUT ;
  USE SIGNAL ;
  PORT
   LAYER M4 ;
   RECT 302.208000 544.332000 302.400000 544.356000 ;
  END
 END po0[174]
 PIN po0[175]
  DIRECTION INPUT ;
  USE SIGNAL ;
  PORT
   LAYER M4 ;
   RECT 302.208000 544.524000 302.400000 544.548000 ;
  END
 END po0[175]
 PIN po0[176]
  DIRECTION INPUT ;
  USE SIGNAL ;
  PORT
   LAYER M4 ;
   RECT 302.208000 544.716000 302.400000 544.740000 ;
  END
 END po0[176]
 PIN po0[177]
  DIRECTION INPUT ;
  USE SIGNAL ;
  PORT
   LAYER M4 ;
   RECT 302.208000 544.908000 302.400000 544.932000 ;
  END
 END po0[177]
 PIN po0[178]
  DIRECTION INPUT ;
  USE SIGNAL ;
  PORT
   LAYER M4 ;
   RECT 302.208000 545.100000 302.400000 545.124000 ;
  END
 END po0[178]
 PIN po0[179]
  DIRECTION INPUT ;
  USE SIGNAL ;
  PORT
   LAYER M4 ;
   RECT 302.208000 545.292000 302.400000 545.316000 ;
  END
 END po0[179]
 PIN po0[180]
  DIRECTION INPUT ;
  USE SIGNAL ;
  PORT
   LAYER M4 ;
   RECT 302.208000 545.484000 302.400000 545.508000 ;
  END
 END po0[180]
 PIN po0[181]
  DIRECTION INPUT ;
  USE SIGNAL ;
  PORT
   LAYER M4 ;
   RECT 302.208000 545.676000 302.400000 545.700000 ;
  END
 END po0[181]
 PIN po0[182]
  DIRECTION INPUT ;
  USE SIGNAL ;
  PORT
   LAYER M4 ;
   RECT 302.208000 545.868000 302.400000 545.892000 ;
  END
 END po0[182]
 PIN po0[183]
  DIRECTION INPUT ;
  USE SIGNAL ;
  PORT
   LAYER M4 ;
   RECT 302.208000 546.060000 302.400000 546.084000 ;
  END
 END po0[183]
 PIN po0[184]
  DIRECTION INPUT ;
  USE SIGNAL ;
  PORT
   LAYER M4 ;
   RECT 302.208000 546.252000 302.400000 546.276000 ;
  END
 END po0[184]
 PIN po0[185]
  DIRECTION INPUT ;
  USE SIGNAL ;
  PORT
   LAYER M4 ;
   RECT 302.208000 546.444000 302.400000 546.468000 ;
  END
 END po0[185]
 PIN po0[186]
  DIRECTION INPUT ;
  USE SIGNAL ;
  PORT
   LAYER M4 ;
   RECT 302.208000 546.636000 302.400000 546.660000 ;
  END
 END po0[186]
 PIN po0[187]
  DIRECTION INPUT ;
  USE SIGNAL ;
  PORT
   LAYER M4 ;
   RECT 302.208000 546.828000 302.400000 546.852000 ;
  END
 END po0[187]
 PIN po0[188]
  DIRECTION INPUT ;
  USE SIGNAL ;
  PORT
   LAYER M4 ;
   RECT 302.208000 547.020000 302.400000 547.044000 ;
  END
 END po0[188]
 PIN po0[189]
  DIRECTION INPUT ;
  USE SIGNAL ;
  PORT
   LAYER M4 ;
   RECT 302.208000 547.212000 302.400000 547.236000 ;
  END
 END po0[189]
 PIN po0[190]
  DIRECTION INPUT ;
  USE SIGNAL ;
  PORT
   LAYER M4 ;
   RECT 302.208000 547.404000 302.400000 547.428000 ;
  END
 END po0[190]
 PIN po0[191]
  DIRECTION INPUT ;
  USE SIGNAL ;
  PORT
   LAYER M4 ;
   RECT 302.208000 547.596000 302.400000 547.620000 ;
  END
 END po0[191]
 PIN po0[192]
  DIRECTION INPUT ;
  USE SIGNAL ;
  PORT
   LAYER M4 ;
   RECT 302.208000 547.788000 302.400000 547.812000 ;
  END
 END po0[192]
 PIN po0[193]
  DIRECTION INPUT ;
  USE SIGNAL ;
  PORT
   LAYER M4 ;
   RECT 302.208000 547.980000 302.400000 548.004000 ;
  END
 END po0[193]
 PIN po0[194]
  DIRECTION INPUT ;
  USE SIGNAL ;
  PORT
   LAYER M4 ;
   RECT 302.208000 548.172000 302.400000 548.196000 ;
  END
 END po0[194]
 PIN po0[195]
  DIRECTION INPUT ;
  USE SIGNAL ;
  PORT
   LAYER M4 ;
   RECT 302.208000 548.364000 302.400000 548.388000 ;
  END
 END po0[195]
 PIN po0[196]
  DIRECTION INPUT ;
  USE SIGNAL ;
  PORT
   LAYER M4 ;
   RECT 302.208000 548.556000 302.400000 548.580000 ;
  END
 END po0[196]
 PIN po0[197]
  DIRECTION INPUT ;
  USE SIGNAL ;
  PORT
   LAYER M4 ;
   RECT 302.208000 548.748000 302.400000 548.772000 ;
  END
 END po0[197]
 PIN po0[198]
  DIRECTION INPUT ;
  USE SIGNAL ;
  PORT
   LAYER M4 ;
   RECT 302.208000 548.940000 302.400000 548.964000 ;
  END
 END po0[198]
 PIN po0[199]
  DIRECTION INPUT ;
  USE SIGNAL ;
  PORT
   LAYER M4 ;
   RECT 302.208000 549.132000 302.400000 549.156000 ;
  END
 END po0[199]
 PIN po0[200]
  DIRECTION INPUT ;
  USE SIGNAL ;
  PORT
   LAYER M4 ;
   RECT 302.208000 549.324000 302.400000 549.348000 ;
  END
 END po0[200]
 PIN po0[201]
  DIRECTION INPUT ;
  USE SIGNAL ;
  PORT
   LAYER M4 ;
   RECT 302.208000 549.516000 302.400000 549.540000 ;
  END
 END po0[201]
 PIN po0[202]
  DIRECTION INPUT ;
  USE SIGNAL ;
  PORT
   LAYER M4 ;
   RECT 302.208000 549.708000 302.400000 549.732000 ;
  END
 END po0[202]
 PIN po0[203]
  DIRECTION INPUT ;
  USE SIGNAL ;
  PORT
   LAYER M4 ;
   RECT 302.208000 549.900000 302.400000 549.924000 ;
  END
 END po0[203]
 PIN po0[204]
  DIRECTION INPUT ;
  USE SIGNAL ;
  PORT
   LAYER M4 ;
   RECT 302.208000 550.092000 302.400000 550.116000 ;
  END
 END po0[204]
 PIN po0[205]
  DIRECTION INPUT ;
  USE SIGNAL ;
  PORT
   LAYER M4 ;
   RECT 302.208000 550.284000 302.400000 550.308000 ;
  END
 END po0[205]
 PIN po0[206]
  DIRECTION INPUT ;
  USE SIGNAL ;
  PORT
   LAYER M4 ;
   RECT 302.208000 550.476000 302.400000 550.500000 ;
  END
 END po0[206]
 PIN po0[207]
  DIRECTION INPUT ;
  USE SIGNAL ;
  PORT
   LAYER M4 ;
   RECT 302.208000 550.668000 302.400000 550.692000 ;
  END
 END po0[207]
 PIN po0[208]
  DIRECTION INPUT ;
  USE SIGNAL ;
  PORT
   LAYER M4 ;
   RECT 302.208000 550.860000 302.400000 550.884000 ;
  END
 END po0[208]
 PIN po0[209]
  DIRECTION INPUT ;
  USE SIGNAL ;
  PORT
   LAYER M4 ;
   RECT 302.208000 551.052000 302.400000 551.076000 ;
  END
 END po0[209]
 PIN po0[210]
  DIRECTION INPUT ;
  USE SIGNAL ;
  PORT
   LAYER M4 ;
   RECT 302.208000 551.244000 302.400000 551.268000 ;
  END
 END po0[210]
 PIN po0[211]
  DIRECTION INPUT ;
  USE SIGNAL ;
  PORT
   LAYER M4 ;
   RECT 302.208000 551.436000 302.400000 551.460000 ;
  END
 END po0[211]
 PIN po0[212]
  DIRECTION INPUT ;
  USE SIGNAL ;
  PORT
   LAYER M4 ;
   RECT 302.208000 551.628000 302.400000 551.652000 ;
  END
 END po0[212]
 PIN po0[213]
  DIRECTION INPUT ;
  USE SIGNAL ;
  PORT
   LAYER M4 ;
   RECT 302.208000 551.820000 302.400000 551.844000 ;
  END
 END po0[213]
 PIN po0[214]
  DIRECTION INPUT ;
  USE SIGNAL ;
  PORT
   LAYER M4 ;
   RECT 302.208000 552.012000 302.400000 552.036000 ;
  END
 END po0[214]
 PIN po0[215]
  DIRECTION INPUT ;
  USE SIGNAL ;
  PORT
   LAYER M4 ;
   RECT 302.208000 552.204000 302.400000 552.228000 ;
  END
 END po0[215]
 PIN po0[216]
  DIRECTION INPUT ;
  USE SIGNAL ;
  PORT
   LAYER M4 ;
   RECT 302.208000 552.396000 302.400000 552.420000 ;
  END
 END po0[216]
 PIN po0[217]
  DIRECTION INPUT ;
  USE SIGNAL ;
  PORT
   LAYER M4 ;
   RECT 302.208000 552.588000 302.400000 552.612000 ;
  END
 END po0[217]
 PIN po0[218]
  DIRECTION INPUT ;
  USE SIGNAL ;
  PORT
   LAYER M4 ;
   RECT 302.208000 552.780000 302.400000 552.804000 ;
  END
 END po0[218]
 PIN po0[219]
  DIRECTION INPUT ;
  USE SIGNAL ;
  PORT
   LAYER M4 ;
   RECT 302.208000 552.972000 302.400000 552.996000 ;
  END
 END po0[219]
 PIN po0[220]
  DIRECTION INPUT ;
  USE SIGNAL ;
  PORT
   LAYER M4 ;
   RECT 302.208000 553.164000 302.400000 553.188000 ;
  END
 END po0[220]
 PIN po0[221]
  DIRECTION INPUT ;
  USE SIGNAL ;
  PORT
   LAYER M4 ;
   RECT 302.208000 553.356000 302.400000 553.380000 ;
  END
 END po0[221]
 PIN po0[222]
  DIRECTION INPUT ;
  USE SIGNAL ;
  PORT
   LAYER M4 ;
   RECT 302.208000 553.548000 302.400000 553.572000 ;
  END
 END po0[222]
 PIN po0[223]
  DIRECTION INPUT ;
  USE SIGNAL ;
  PORT
   LAYER M4 ;
   RECT 302.208000 553.740000 302.400000 553.764000 ;
  END
 END po0[223]
 PIN po0[224]
  DIRECTION INPUT ;
  USE SIGNAL ;
  PORT
   LAYER M4 ;
   RECT 302.208000 553.932000 302.400000 553.956000 ;
  END
 END po0[224]
 PIN po0[225]
  DIRECTION INPUT ;
  USE SIGNAL ;
  PORT
   LAYER M4 ;
   RECT 302.208000 554.124000 302.400000 554.148000 ;
  END
 END po0[225]
 PIN po0[226]
  DIRECTION INPUT ;
  USE SIGNAL ;
  PORT
   LAYER M4 ;
   RECT 302.208000 554.316000 302.400000 554.340000 ;
  END
 END po0[226]
 PIN po0[227]
  DIRECTION INPUT ;
  USE SIGNAL ;
  PORT
   LAYER M4 ;
   RECT 302.208000 554.508000 302.400000 554.532000 ;
  END
 END po0[227]
 PIN po0[228]
  DIRECTION INPUT ;
  USE SIGNAL ;
  PORT
   LAYER M4 ;
   RECT 302.208000 554.700000 302.400000 554.724000 ;
  END
 END po0[228]
 PIN po0[229]
  DIRECTION INPUT ;
  USE SIGNAL ;
  PORT
   LAYER M4 ;
   RECT 302.208000 554.892000 302.400000 554.916000 ;
  END
 END po0[229]
 PIN po0[230]
  DIRECTION INPUT ;
  USE SIGNAL ;
  PORT
   LAYER M4 ;
   RECT 302.208000 555.084000 302.400000 555.108000 ;
  END
 END po0[230]
 PIN po0[231]
  DIRECTION INPUT ;
  USE SIGNAL ;
  PORT
   LAYER M4 ;
   RECT 302.208000 555.276000 302.400000 555.300000 ;
  END
 END po0[231]
 PIN po0[232]
  DIRECTION INPUT ;
  USE SIGNAL ;
  PORT
   LAYER M4 ;
   RECT 302.208000 555.468000 302.400000 555.492000 ;
  END
 END po0[232]
 PIN po0[233]
  DIRECTION INPUT ;
  USE SIGNAL ;
  PORT
   LAYER M4 ;
   RECT 302.208000 555.660000 302.400000 555.684000 ;
  END
 END po0[233]
 PIN po0[234]
  DIRECTION INPUT ;
  USE SIGNAL ;
  PORT
   LAYER M4 ;
   RECT 302.208000 555.852000 302.400000 555.876000 ;
  END
 END po0[234]
 PIN po0[235]
  DIRECTION INPUT ;
  USE SIGNAL ;
  PORT
   LAYER M4 ;
   RECT 302.208000 556.044000 302.400000 556.068000 ;
  END
 END po0[235]
 PIN po0[236]
  DIRECTION INPUT ;
  USE SIGNAL ;
  PORT
   LAYER M4 ;
   RECT 302.208000 556.236000 302.400000 556.260000 ;
  END
 END po0[236]
 PIN po0[237]
  DIRECTION INPUT ;
  USE SIGNAL ;
  PORT
   LAYER M4 ;
   RECT 302.208000 556.428000 302.400000 556.452000 ;
  END
 END po0[237]
 PIN po0[238]
  DIRECTION INPUT ;
  USE SIGNAL ;
  PORT
   LAYER M4 ;
   RECT 302.208000 556.620000 302.400000 556.644000 ;
  END
 END po0[238]
 PIN po0[239]
  DIRECTION INPUT ;
  USE SIGNAL ;
  PORT
   LAYER M4 ;
   RECT 302.208000 556.812000 302.400000 556.836000 ;
  END
 END po0[239]
 PIN po0[240]
  DIRECTION INPUT ;
  USE SIGNAL ;
  PORT
   LAYER M4 ;
   RECT 302.208000 557.004000 302.400000 557.028000 ;
  END
 END po0[240]
 PIN po0[241]
  DIRECTION INPUT ;
  USE SIGNAL ;
  PORT
   LAYER M4 ;
   RECT 302.208000 557.196000 302.400000 557.220000 ;
  END
 END po0[241]
 PIN po0[242]
  DIRECTION INPUT ;
  USE SIGNAL ;
  PORT
   LAYER M4 ;
   RECT 302.208000 557.388000 302.400000 557.412000 ;
  END
 END po0[242]
 PIN po0[243]
  DIRECTION INPUT ;
  USE SIGNAL ;
  PORT
   LAYER M4 ;
   RECT 302.208000 557.580000 302.400000 557.604000 ;
  END
 END po0[243]
 PIN po0[244]
  DIRECTION INPUT ;
  USE SIGNAL ;
  PORT
   LAYER M4 ;
   RECT 302.208000 557.772000 302.400000 557.796000 ;
  END
 END po0[244]
 PIN po0[245]
  DIRECTION INPUT ;
  USE SIGNAL ;
  PORT
   LAYER M4 ;
   RECT 302.208000 557.964000 302.400000 557.988000 ;
  END
 END po0[245]
 PIN po0[246]
  DIRECTION INPUT ;
  USE SIGNAL ;
  PORT
   LAYER M4 ;
   RECT 302.208000 558.156000 302.400000 558.180000 ;
  END
 END po0[246]
 PIN po0[247]
  DIRECTION INPUT ;
  USE SIGNAL ;
  PORT
   LAYER M4 ;
   RECT 302.208000 558.348000 302.400000 558.372000 ;
  END
 END po0[247]
 PIN po0[248]
  DIRECTION INPUT ;
  USE SIGNAL ;
  PORT
   LAYER M4 ;
   RECT 302.208000 558.540000 302.400000 558.564000 ;
  END
 END po0[248]
 PIN po0[249]
  DIRECTION INPUT ;
  USE SIGNAL ;
  PORT
   LAYER M4 ;
   RECT 302.208000 558.732000 302.400000 558.756000 ;
  END
 END po0[249]
 PIN po0[250]
  DIRECTION INPUT ;
  USE SIGNAL ;
  PORT
   LAYER M4 ;
   RECT 302.208000 558.924000 302.400000 558.948000 ;
  END
 END po0[250]
 PIN po0[251]
  DIRECTION INPUT ;
  USE SIGNAL ;
  PORT
   LAYER M4 ;
   RECT 302.208000 559.116000 302.400000 559.140000 ;
  END
 END po0[251]
 PIN po0[252]
  DIRECTION INPUT ;
  USE SIGNAL ;
  PORT
   LAYER M4 ;
   RECT 302.208000 559.308000 302.400000 559.332000 ;
  END
 END po0[252]
 PIN po0[253]
  DIRECTION INPUT ;
  USE SIGNAL ;
  PORT
   LAYER M4 ;
   RECT 302.208000 559.500000 302.400000 559.524000 ;
  END
 END po0[253]
 PIN po0[254]
  DIRECTION INPUT ;
  USE SIGNAL ;
  PORT
   LAYER M4 ;
   RECT 302.208000 559.692000 302.400000 559.716000 ;
  END
 END po0[254]
 PIN po0[255]
  DIRECTION INPUT ;
  USE SIGNAL ;
  PORT
   LAYER M4 ;
   RECT 302.208000 559.884000 302.400000 559.908000 ;
  END
 END po0[255]
 PIN po0[256]
  DIRECTION INPUT ;
  USE SIGNAL ;
  PORT
   LAYER M4 ;
   RECT 302.208000 560.076000 302.400000 560.100000 ;
  END
 END po0[256]
 PIN po0[257]
  DIRECTION INPUT ;
  USE SIGNAL ;
  PORT
   LAYER M4 ;
   RECT 302.208000 560.268000 302.400000 560.292000 ;
  END
 END po0[257]
 PIN po0[258]
  DIRECTION INPUT ;
  USE SIGNAL ;
  PORT
   LAYER M4 ;
   RECT 302.208000 560.460000 302.400000 560.484000 ;
  END
 END po0[258]
 PIN po0[259]
  DIRECTION INPUT ;
  USE SIGNAL ;
  PORT
   LAYER M4 ;
   RECT 302.208000 560.652000 302.400000 560.676000 ;
  END
 END po0[259]
 PIN po0[260]
  DIRECTION INPUT ;
  USE SIGNAL ;
  PORT
   LAYER M4 ;
   RECT 302.208000 560.844000 302.400000 560.868000 ;
  END
 END po0[260]
 PIN po0[261]
  DIRECTION INPUT ;
  USE SIGNAL ;
  PORT
   LAYER M4 ;
   RECT 302.208000 561.036000 302.400000 561.060000 ;
  END
 END po0[261]
 PIN po0[262]
  DIRECTION INPUT ;
  USE SIGNAL ;
  PORT
   LAYER M4 ;
   RECT 302.208000 561.228000 302.400000 561.252000 ;
  END
 END po0[262]
 PIN po0[263]
  DIRECTION INPUT ;
  USE SIGNAL ;
  PORT
   LAYER M4 ;
   RECT 302.208000 561.420000 302.400000 561.444000 ;
  END
 END po0[263]
 PIN po0[264]
  DIRECTION INPUT ;
  USE SIGNAL ;
  PORT
   LAYER M4 ;
   RECT 302.208000 561.612000 302.400000 561.636000 ;
  END
 END po0[264]
 PIN po0[265]
  DIRECTION INPUT ;
  USE SIGNAL ;
  PORT
   LAYER M4 ;
   RECT 302.208000 561.804000 302.400000 561.828000 ;
  END
 END po0[265]
 PIN po0[266]
  DIRECTION INPUT ;
  USE SIGNAL ;
  PORT
   LAYER M4 ;
   RECT 302.208000 561.996000 302.400000 562.020000 ;
  END
 END po0[266]
 PIN po0[267]
  DIRECTION INPUT ;
  USE SIGNAL ;
  PORT
   LAYER M4 ;
   RECT 302.208000 562.188000 302.400000 562.212000 ;
  END
 END po0[267]
 PIN po0[268]
  DIRECTION INPUT ;
  USE SIGNAL ;
  PORT
   LAYER M4 ;
   RECT 302.208000 562.380000 302.400000 562.404000 ;
  END
 END po0[268]
 PIN po0[269]
  DIRECTION INPUT ;
  USE SIGNAL ;
  PORT
   LAYER M4 ;
   RECT 302.208000 562.572000 302.400000 562.596000 ;
  END
 END po0[269]
 PIN po0[270]
  DIRECTION INPUT ;
  USE SIGNAL ;
  PORT
   LAYER M4 ;
   RECT 302.208000 562.764000 302.400000 562.788000 ;
  END
 END po0[270]
 PIN po0[271]
  DIRECTION INPUT ;
  USE SIGNAL ;
  PORT
   LAYER M4 ;
   RECT 302.208000 562.956000 302.400000 562.980000 ;
  END
 END po0[271]
 PIN po0[272]
  DIRECTION INPUT ;
  USE SIGNAL ;
  PORT
   LAYER M4 ;
   RECT 302.208000 563.148000 302.400000 563.172000 ;
  END
 END po0[272]
 PIN po0[273]
  DIRECTION INPUT ;
  USE SIGNAL ;
  PORT
   LAYER M4 ;
   RECT 302.208000 563.340000 302.400000 563.364000 ;
  END
 END po0[273]
 PIN po0[274]
  DIRECTION INPUT ;
  USE SIGNAL ;
  PORT
   LAYER M4 ;
   RECT 302.208000 563.532000 302.400000 563.556000 ;
  END
 END po0[274]
 PIN po0[275]
  DIRECTION INPUT ;
  USE SIGNAL ;
  PORT
   LAYER M4 ;
   RECT 302.208000 563.724000 302.400000 563.748000 ;
  END
 END po0[275]
 PIN po0[276]
  DIRECTION INPUT ;
  USE SIGNAL ;
  PORT
   LAYER M4 ;
   RECT 302.208000 563.916000 302.400000 563.940000 ;
  END
 END po0[276]
 PIN po0[277]
  DIRECTION INPUT ;
  USE SIGNAL ;
  PORT
   LAYER M4 ;
   RECT 302.208000 564.108000 302.400000 564.132000 ;
  END
 END po0[277]
 PIN po0[278]
  DIRECTION INPUT ;
  USE SIGNAL ;
  PORT
   LAYER M4 ;
   RECT 302.208000 564.300000 302.400000 564.324000 ;
  END
 END po0[278]
 PIN po0[279]
  DIRECTION INPUT ;
  USE SIGNAL ;
  PORT
   LAYER M4 ;
   RECT 302.208000 564.492000 302.400000 564.516000 ;
  END
 END po0[279]
 PIN po0[280]
  DIRECTION INPUT ;
  USE SIGNAL ;
  PORT
   LAYER M4 ;
   RECT 302.208000 564.684000 302.400000 564.708000 ;
  END
 END po0[280]
 PIN po0[281]
  DIRECTION INPUT ;
  USE SIGNAL ;
  PORT
   LAYER M4 ;
   RECT 302.208000 564.876000 302.400000 564.900000 ;
  END
 END po0[281]
 PIN po0[282]
  DIRECTION INPUT ;
  USE SIGNAL ;
  PORT
   LAYER M4 ;
   RECT 302.208000 565.068000 302.400000 565.092000 ;
  END
 END po0[282]
 PIN po0[283]
  DIRECTION INPUT ;
  USE SIGNAL ;
  PORT
   LAYER M4 ;
   RECT 302.208000 565.260000 302.400000 565.284000 ;
  END
 END po0[283]
 PIN po0[284]
  DIRECTION INPUT ;
  USE SIGNAL ;
  PORT
   LAYER M4 ;
   RECT 302.208000 565.452000 302.400000 565.476000 ;
  END
 END po0[284]
 PIN po0[285]
  DIRECTION INPUT ;
  USE SIGNAL ;
  PORT
   LAYER M4 ;
   RECT 302.208000 565.644000 302.400000 565.668000 ;
  END
 END po0[285]
 PIN po0[286]
  DIRECTION INPUT ;
  USE SIGNAL ;
  PORT
   LAYER M4 ;
   RECT 302.208000 565.836000 302.400000 565.860000 ;
  END
 END po0[286]
 PIN po0[287]
  DIRECTION INPUT ;
  USE SIGNAL ;
  PORT
   LAYER M4 ;
   RECT 302.208000 566.028000 302.400000 566.052000 ;
  END
 END po0[287]
 PIN po0[288]
  DIRECTION INPUT ;
  USE SIGNAL ;
  PORT
   LAYER M4 ;
   RECT 302.208000 566.220000 302.400000 566.244000 ;
  END
 END po0[288]
 PIN po0[289]
  DIRECTION INPUT ;
  USE SIGNAL ;
  PORT
   LAYER M4 ;
   RECT 302.208000 566.412000 302.400000 566.436000 ;
  END
 END po0[289]
 PIN po0[290]
  DIRECTION INPUT ;
  USE SIGNAL ;
  PORT
   LAYER M4 ;
   RECT 302.208000 566.604000 302.400000 566.628000 ;
  END
 END po0[290]
 PIN po0[291]
  DIRECTION INPUT ;
  USE SIGNAL ;
  PORT
   LAYER M4 ;
   RECT 302.208000 566.796000 302.400000 566.820000 ;
  END
 END po0[291]
 PIN po0[292]
  DIRECTION INPUT ;
  USE SIGNAL ;
  PORT
   LAYER M4 ;
   RECT 302.208000 566.988000 302.400000 567.012000 ;
  END
 END po0[292]
 PIN po0[293]
  DIRECTION INPUT ;
  USE SIGNAL ;
  PORT
   LAYER M4 ;
   RECT 302.208000 567.180000 302.400000 567.204000 ;
  END
 END po0[293]
 PIN po0[294]
  DIRECTION INPUT ;
  USE SIGNAL ;
  PORT
   LAYER M4 ;
   RECT 302.208000 567.372000 302.400000 567.396000 ;
  END
 END po0[294]
 PIN po0[295]
  DIRECTION INPUT ;
  USE SIGNAL ;
  PORT
   LAYER M4 ;
   RECT 302.208000 567.564000 302.400000 567.588000 ;
  END
 END po0[295]
 PIN po0[296]
  DIRECTION INPUT ;
  USE SIGNAL ;
  PORT
   LAYER M4 ;
   RECT 302.208000 567.756000 302.400000 567.780000 ;
  END
 END po0[296]
 PIN po0[297]
  DIRECTION INPUT ;
  USE SIGNAL ;
  PORT
   LAYER M4 ;
   RECT 302.208000 567.948000 302.400000 567.972000 ;
  END
 END po0[297]
 PIN po0[298]
  DIRECTION INPUT ;
  USE SIGNAL ;
  PORT
   LAYER M4 ;
   RECT 302.208000 568.140000 302.400000 568.164000 ;
  END
 END po0[298]
 PIN po0[299]
  DIRECTION INPUT ;
  USE SIGNAL ;
  PORT
   LAYER M4 ;
   RECT 302.208000 568.332000 302.400000 568.356000 ;
  END
 END po0[299]
 PIN po0[300]
  DIRECTION INPUT ;
  USE SIGNAL ;
  PORT
   LAYER M4 ;
   RECT 302.208000 568.524000 302.400000 568.548000 ;
  END
 END po0[300]
 PIN po0[301]
  DIRECTION INPUT ;
  USE SIGNAL ;
  PORT
   LAYER M4 ;
   RECT 302.208000 568.716000 302.400000 568.740000 ;
  END
 END po0[301]
 PIN po0[302]
  DIRECTION INPUT ;
  USE SIGNAL ;
  PORT
   LAYER M4 ;
   RECT 302.208000 568.908000 302.400000 568.932000 ;
  END
 END po0[302]
 PIN po0[303]
  DIRECTION INPUT ;
  USE SIGNAL ;
  PORT
   LAYER M4 ;
   RECT 302.208000 569.100000 302.400000 569.124000 ;
  END
 END po0[303]
 PIN po0[304]
  DIRECTION INPUT ;
  USE SIGNAL ;
  PORT
   LAYER M4 ;
   RECT 302.208000 569.292000 302.400000 569.316000 ;
  END
 END po0[304]
 PIN po0[305]
  DIRECTION INPUT ;
  USE SIGNAL ;
  PORT
   LAYER M4 ;
   RECT 302.208000 569.484000 302.400000 569.508000 ;
  END
 END po0[305]
 PIN po0[306]
  DIRECTION INPUT ;
  USE SIGNAL ;
  PORT
   LAYER M4 ;
   RECT 302.208000 569.676000 302.400000 569.700000 ;
  END
 END po0[306]
 PIN po0[307]
  DIRECTION INPUT ;
  USE SIGNAL ;
  PORT
   LAYER M4 ;
   RECT 302.208000 569.868000 302.400000 569.892000 ;
  END
 END po0[307]
 PIN po0[308]
  DIRECTION INPUT ;
  USE SIGNAL ;
  PORT
   LAYER M4 ;
   RECT 302.208000 570.060000 302.400000 570.084000 ;
  END
 END po0[308]
 PIN po0[309]
  DIRECTION INPUT ;
  USE SIGNAL ;
  PORT
   LAYER M4 ;
   RECT 302.208000 570.252000 302.400000 570.276000 ;
  END
 END po0[309]
 PIN po0[310]
  DIRECTION INPUT ;
  USE SIGNAL ;
  PORT
   LAYER M4 ;
   RECT 302.208000 570.444000 302.400000 570.468000 ;
  END
 END po0[310]
 PIN po0[311]
  DIRECTION INPUT ;
  USE SIGNAL ;
  PORT
   LAYER M4 ;
   RECT 302.208000 570.636000 302.400000 570.660000 ;
  END
 END po0[311]
 PIN po0[312]
  DIRECTION INPUT ;
  USE SIGNAL ;
  PORT
   LAYER M4 ;
   RECT 302.208000 570.828000 302.400000 570.852000 ;
  END
 END po0[312]
 PIN po0[313]
  DIRECTION INPUT ;
  USE SIGNAL ;
  PORT
   LAYER M4 ;
   RECT 302.208000 571.020000 302.400000 571.044000 ;
  END
 END po0[313]
 PIN po0[314]
  DIRECTION INPUT ;
  USE SIGNAL ;
  PORT
   LAYER M4 ;
   RECT 302.208000 571.212000 302.400000 571.236000 ;
  END
 END po0[314]
 PIN po0[315]
  DIRECTION INPUT ;
  USE SIGNAL ;
  PORT
   LAYER M4 ;
   RECT 302.208000 571.404000 302.400000 571.428000 ;
  END
 END po0[315]
 PIN po0[316]
  DIRECTION INPUT ;
  USE SIGNAL ;
  PORT
   LAYER M4 ;
   RECT 302.208000 571.596000 302.400000 571.620000 ;
  END
 END po0[316]
 PIN po0[317]
  DIRECTION INPUT ;
  USE SIGNAL ;
  PORT
   LAYER M4 ;
   RECT 302.208000 571.788000 302.400000 571.812000 ;
  END
 END po0[317]
 PIN po0[318]
  DIRECTION INPUT ;
  USE SIGNAL ;
  PORT
   LAYER M4 ;
   RECT 302.208000 571.980000 302.400000 572.004000 ;
  END
 END po0[318]
 PIN po0[319]
  DIRECTION INPUT ;
  USE SIGNAL ;
  PORT
   LAYER M4 ;
   RECT 302.208000 572.172000 302.400000 572.196000 ;
  END
 END po0[319]
 PIN po0[320]
  DIRECTION INPUT ;
  USE SIGNAL ;
  PORT
   LAYER M4 ;
   RECT 302.208000 572.364000 302.400000 572.388000 ;
  END
 END po0[320]
 PIN po0[321]
  DIRECTION INPUT ;
  USE SIGNAL ;
  PORT
   LAYER M4 ;
   RECT 302.208000 572.556000 302.400000 572.580000 ;
  END
 END po0[321]
 PIN po0[322]
  DIRECTION INPUT ;
  USE SIGNAL ;
  PORT
   LAYER M4 ;
   RECT 302.208000 572.748000 302.400000 572.772000 ;
  END
 END po0[322]
 PIN po0[323]
  DIRECTION INPUT ;
  USE SIGNAL ;
  PORT
   LAYER M4 ;
   RECT 302.208000 572.940000 302.400000 572.964000 ;
  END
 END po0[323]
 PIN po0[324]
  DIRECTION INPUT ;
  USE SIGNAL ;
  PORT
   LAYER M4 ;
   RECT 302.208000 573.132000 302.400000 573.156000 ;
  END
 END po0[324]
 PIN po0[325]
  DIRECTION INPUT ;
  USE SIGNAL ;
  PORT
   LAYER M4 ;
   RECT 302.208000 573.324000 302.400000 573.348000 ;
  END
 END po0[325]
 PIN po0[326]
  DIRECTION INPUT ;
  USE SIGNAL ;
  PORT
   LAYER M4 ;
   RECT 302.208000 573.516000 302.400000 573.540000 ;
  END
 END po0[326]
 PIN po0[327]
  DIRECTION INPUT ;
  USE SIGNAL ;
  PORT
   LAYER M4 ;
   RECT 302.208000 573.708000 302.400000 573.732000 ;
  END
 END po0[327]
 PIN pi0[0]
  DIRECTION OUTPUT ;
  USE SIGNAL ;
  PORT
   LAYER M4 ;
   RECT 302.208000 573.900000 302.400000 573.924000 ;
  END
 END pi0[0]
 PIN pi0[1]
  DIRECTION OUTPUT ;
  USE SIGNAL ;
  PORT
   LAYER M4 ;
   RECT 302.208000 574.092000 302.400000 574.116000 ;
  END
 END pi0[1]
 PIN pi0[2]
  DIRECTION OUTPUT ;
  USE SIGNAL ;
  PORT
   LAYER M4 ;
   RECT 302.208000 574.284000 302.400000 574.308000 ;
  END
 END pi0[2]
 PIN pi0[3]
  DIRECTION OUTPUT ;
  USE SIGNAL ;
  PORT
   LAYER M4 ;
   RECT 302.208000 574.476000 302.400000 574.500000 ;
  END
 END pi0[3]
 PIN pi0[4]
  DIRECTION OUTPUT ;
  USE SIGNAL ;
  PORT
   LAYER M4 ;
   RECT 302.208000 574.668000 302.400000 574.692000 ;
  END
 END pi0[4]
 PIN pi0[5]
  DIRECTION OUTPUT ;
  USE SIGNAL ;
  PORT
   LAYER M4 ;
   RECT 302.208000 574.860000 302.400000 574.884000 ;
  END
 END pi0[5]
 PIN pi0[6]
  DIRECTION OUTPUT ;
  USE SIGNAL ;
  PORT
   LAYER M4 ;
   RECT 302.208000 575.052000 302.400000 575.076000 ;
  END
 END pi0[6]
 PIN pi0[7]
  DIRECTION OUTPUT ;
  USE SIGNAL ;
  PORT
   LAYER M4 ;
   RECT 302.208000 575.244000 302.400000 575.268000 ;
  END
 END pi0[7]
 PIN pi0[8]
  DIRECTION OUTPUT ;
  USE SIGNAL ;
  PORT
   LAYER M4 ;
   RECT 302.208000 575.436000 302.400000 575.460000 ;
  END
 END pi0[8]
 PIN pi0[9]
  DIRECTION OUTPUT ;
  USE SIGNAL ;
  PORT
   LAYER M4 ;
   RECT 302.208000 575.628000 302.400000 575.652000 ;
  END
 END pi0[9]
 PIN pi0[10]
  DIRECTION OUTPUT ;
  USE SIGNAL ;
  PORT
   LAYER M4 ;
   RECT 302.208000 575.820000 302.400000 575.844000 ;
  END
 END pi0[10]
 PIN pi0[11]
  DIRECTION OUTPUT ;
  USE SIGNAL ;
  PORT
   LAYER M4 ;
   RECT 302.208000 576.012000 302.400000 576.036000 ;
  END
 END pi0[11]
 PIN pi0[12]
  DIRECTION OUTPUT ;
  USE SIGNAL ;
  PORT
   LAYER M4 ;
   RECT 302.208000 576.204000 302.400000 576.228000 ;
  END
 END pi0[12]
 PIN pi0[13]
  DIRECTION OUTPUT ;
  USE SIGNAL ;
  PORT
   LAYER M4 ;
   RECT 302.208000 576.396000 302.400000 576.420000 ;
  END
 END pi0[13]
 PIN pi0[14]
  DIRECTION OUTPUT ;
  USE SIGNAL ;
  PORT
   LAYER M4 ;
   RECT 302.208000 576.588000 302.400000 576.612000 ;
  END
 END pi0[14]
 PIN pi0[15]
  DIRECTION OUTPUT ;
  USE SIGNAL ;
  PORT
   LAYER M4 ;
   RECT 302.208000 576.780000 302.400000 576.804000 ;
  END
 END pi0[15]
 PIN pi0[16]
  DIRECTION OUTPUT ;
  USE SIGNAL ;
  PORT
   LAYER M4 ;
   RECT 302.208000 576.972000 302.400000 576.996000 ;
  END
 END pi0[16]
 PIN pi0[17]
  DIRECTION OUTPUT ;
  USE SIGNAL ;
  PORT
   LAYER M4 ;
   RECT 302.208000 577.164000 302.400000 577.188000 ;
  END
 END pi0[17]
 PIN pi0[18]
  DIRECTION OUTPUT ;
  USE SIGNAL ;
  PORT
   LAYER M4 ;
   RECT 302.208000 577.356000 302.400000 577.380000 ;
  END
 END pi0[18]
 PIN pi0[19]
  DIRECTION OUTPUT ;
  USE SIGNAL ;
  PORT
   LAYER M4 ;
   RECT 302.208000 577.548000 302.400000 577.572000 ;
  END
 END pi0[19]
 PIN pi0[20]
  DIRECTION OUTPUT ;
  USE SIGNAL ;
  PORT
   LAYER M4 ;
   RECT 302.208000 577.740000 302.400000 577.764000 ;
  END
 END pi0[20]
 PIN pi0[21]
  DIRECTION OUTPUT ;
  USE SIGNAL ;
  PORT
   LAYER M4 ;
   RECT 302.208000 577.932000 302.400000 577.956000 ;
  END
 END pi0[21]
 PIN pi0[22]
  DIRECTION OUTPUT ;
  USE SIGNAL ;
  PORT
   LAYER M4 ;
   RECT 302.208000 578.124000 302.400000 578.148000 ;
  END
 END pi0[22]
 PIN pi0[23]
  DIRECTION OUTPUT ;
  USE SIGNAL ;
  PORT
   LAYER M4 ;
   RECT 302.208000 578.316000 302.400000 578.340000 ;
  END
 END pi0[23]
 PIN pi0[24]
  DIRECTION OUTPUT ;
  USE SIGNAL ;
  PORT
   LAYER M4 ;
   RECT 302.208000 578.508000 302.400000 578.532000 ;
  END
 END pi0[24]
 PIN pi0[25]
  DIRECTION OUTPUT ;
  USE SIGNAL ;
  PORT
   LAYER M4 ;
   RECT 302.208000 578.700000 302.400000 578.724000 ;
  END
 END pi0[25]
 PIN pi0[26]
  DIRECTION OUTPUT ;
  USE SIGNAL ;
  PORT
   LAYER M4 ;
   RECT 302.208000 578.892000 302.400000 578.916000 ;
  END
 END pi0[26]
 PIN pi0[27]
  DIRECTION OUTPUT ;
  USE SIGNAL ;
  PORT
   LAYER M4 ;
   RECT 302.208000 579.084000 302.400000 579.108000 ;
  END
 END pi0[27]
 PIN pi0[28]
  DIRECTION OUTPUT ;
  USE SIGNAL ;
  PORT
   LAYER M4 ;
   RECT 302.208000 579.276000 302.400000 579.300000 ;
  END
 END pi0[28]
 PIN pi0[29]
  DIRECTION OUTPUT ;
  USE SIGNAL ;
  PORT
   LAYER M4 ;
   RECT 302.208000 579.468000 302.400000 579.492000 ;
  END
 END pi0[29]
 PIN pi0[30]
  DIRECTION OUTPUT ;
  USE SIGNAL ;
  PORT
   LAYER M4 ;
   RECT 302.208000 579.660000 302.400000 579.684000 ;
  END
 END pi0[30]
 PIN pi0[31]
  DIRECTION OUTPUT ;
  USE SIGNAL ;
  PORT
   LAYER M4 ;
   RECT 302.208000 579.852000 302.400000 579.876000 ;
  END
 END pi0[31]
 PIN pi0[32]
  DIRECTION OUTPUT ;
  USE SIGNAL ;
  PORT
   LAYER M4 ;
   RECT 302.208000 580.044000 302.400000 580.068000 ;
  END
 END pi0[32]
 PIN pi0[33]
  DIRECTION OUTPUT ;
  USE SIGNAL ;
  PORT
   LAYER M4 ;
   RECT 302.208000 580.236000 302.400000 580.260000 ;
  END
 END pi0[33]
 PIN pi0[34]
  DIRECTION OUTPUT ;
  USE SIGNAL ;
  PORT
   LAYER M4 ;
   RECT 302.208000 580.428000 302.400000 580.452000 ;
  END
 END pi0[34]
 PIN pi0[35]
  DIRECTION OUTPUT ;
  USE SIGNAL ;
  PORT
   LAYER M4 ;
   RECT 302.208000 580.620000 302.400000 580.644000 ;
  END
 END pi0[35]
 PIN pi0[36]
  DIRECTION OUTPUT ;
  USE SIGNAL ;
  PORT
   LAYER M4 ;
   RECT 302.208000 580.812000 302.400000 580.836000 ;
  END
 END pi0[36]
 PIN pi0[37]
  DIRECTION OUTPUT ;
  USE SIGNAL ;
  PORT
   LAYER M4 ;
   RECT 302.208000 581.004000 302.400000 581.028000 ;
  END
 END pi0[37]
 PIN pi0[38]
  DIRECTION OUTPUT ;
  USE SIGNAL ;
  PORT
   LAYER M4 ;
   RECT 302.208000 581.196000 302.400000 581.220000 ;
  END
 END pi0[38]
 PIN pi0[39]
  DIRECTION OUTPUT ;
  USE SIGNAL ;
  PORT
   LAYER M4 ;
   RECT 302.208000 581.388000 302.400000 581.412000 ;
  END
 END pi0[39]
 PIN pi0[40]
  DIRECTION OUTPUT ;
  USE SIGNAL ;
  PORT
   LAYER M4 ;
   RECT 302.208000 581.580000 302.400000 581.604000 ;
  END
 END pi0[40]
 PIN pi0[41]
  DIRECTION OUTPUT ;
  USE SIGNAL ;
  PORT
   LAYER M4 ;
   RECT 302.208000 581.772000 302.400000 581.796000 ;
  END
 END pi0[41]
 PIN pi0[42]
  DIRECTION OUTPUT ;
  USE SIGNAL ;
  PORT
   LAYER M4 ;
   RECT 302.208000 581.964000 302.400000 581.988000 ;
  END
 END pi0[42]
 PIN pi0[43]
  DIRECTION OUTPUT ;
  USE SIGNAL ;
  PORT
   LAYER M4 ;
   RECT 302.208000 582.156000 302.400000 582.180000 ;
  END
 END pi0[43]
 PIN pi0[44]
  DIRECTION OUTPUT ;
  USE SIGNAL ;
  PORT
   LAYER M4 ;
   RECT 302.208000 582.348000 302.400000 582.372000 ;
  END
 END pi0[44]
 PIN pi0[45]
  DIRECTION OUTPUT ;
  USE SIGNAL ;
  PORT
   LAYER M4 ;
   RECT 302.208000 582.540000 302.400000 582.564000 ;
  END
 END pi0[45]
 PIN pi0[46]
  DIRECTION OUTPUT ;
  USE SIGNAL ;
  PORT
   LAYER M4 ;
   RECT 302.208000 582.732000 302.400000 582.756000 ;
  END
 END pi0[46]
 PIN pi0[47]
  DIRECTION OUTPUT ;
  USE SIGNAL ;
  PORT
   LAYER M4 ;
   RECT 302.208000 582.924000 302.400000 582.948000 ;
  END
 END pi0[47]
 PIN pi0[48]
  DIRECTION OUTPUT ;
  USE SIGNAL ;
  PORT
   LAYER M4 ;
   RECT 302.208000 583.116000 302.400000 583.140000 ;
  END
 END pi0[48]
 PIN pi0[49]
  DIRECTION OUTPUT ;
  USE SIGNAL ;
  PORT
   LAYER M4 ;
   RECT 302.208000 583.308000 302.400000 583.332000 ;
  END
 END pi0[49]
 PIN pi0[50]
  DIRECTION OUTPUT ;
  USE SIGNAL ;
  PORT
   LAYER M4 ;
   RECT 302.208000 583.500000 302.400000 583.524000 ;
  END
 END pi0[50]
 PIN pi0[51]
  DIRECTION OUTPUT ;
  USE SIGNAL ;
  PORT
   LAYER M4 ;
   RECT 302.208000 583.692000 302.400000 583.716000 ;
  END
 END pi0[51]
 PIN pi0[52]
  DIRECTION OUTPUT ;
  USE SIGNAL ;
  PORT
   LAYER M4 ;
   RECT 302.208000 583.884000 302.400000 583.908000 ;
  END
 END pi0[52]
 PIN pi0[53]
  DIRECTION OUTPUT ;
  USE SIGNAL ;
  PORT
   LAYER M4 ;
   RECT 302.208000 584.076000 302.400000 584.100000 ;
  END
 END pi0[53]
 PIN pi0[54]
  DIRECTION OUTPUT ;
  USE SIGNAL ;
  PORT
   LAYER M4 ;
   RECT 302.208000 584.268000 302.400000 584.292000 ;
  END
 END pi0[54]
 PIN pi0[55]
  DIRECTION OUTPUT ;
  USE SIGNAL ;
  PORT
   LAYER M4 ;
   RECT 302.208000 584.460000 302.400000 584.484000 ;
  END
 END pi0[55]
 PIN pi0[56]
  DIRECTION OUTPUT ;
  USE SIGNAL ;
  PORT
   LAYER M4 ;
   RECT 302.208000 584.652000 302.400000 584.676000 ;
  END
 END pi0[56]
 PIN pi0[57]
  DIRECTION OUTPUT ;
  USE SIGNAL ;
  PORT
   LAYER M4 ;
   RECT 302.208000 584.844000 302.400000 584.868000 ;
  END
 END pi0[57]
 PIN pi0[58]
  DIRECTION OUTPUT ;
  USE SIGNAL ;
  PORT
   LAYER M4 ;
   RECT 302.208000 585.036000 302.400000 585.060000 ;
  END
 END pi0[58]
 PIN pi0[59]
  DIRECTION OUTPUT ;
  USE SIGNAL ;
  PORT
   LAYER M4 ;
   RECT 302.208000 585.228000 302.400000 585.252000 ;
  END
 END pi0[59]
 PIN pi0[60]
  DIRECTION OUTPUT ;
  USE SIGNAL ;
  PORT
   LAYER M4 ;
   RECT 302.208000 585.420000 302.400000 585.444000 ;
  END
 END pi0[60]
 PIN pi0[61]
  DIRECTION OUTPUT ;
  USE SIGNAL ;
  PORT
   LAYER M4 ;
   RECT 302.208000 585.612000 302.400000 585.636000 ;
  END
 END pi0[61]
 PIN pi0[62]
  DIRECTION OUTPUT ;
  USE SIGNAL ;
  PORT
   LAYER M4 ;
   RECT 302.208000 585.804000 302.400000 585.828000 ;
  END
 END pi0[62]
 PIN pi0[63]
  DIRECTION OUTPUT ;
  USE SIGNAL ;
  PORT
   LAYER M4 ;
   RECT 302.208000 585.996000 302.400000 586.020000 ;
  END
 END pi0[63]
 PIN pi0[64]
  DIRECTION OUTPUT ;
  USE SIGNAL ;
  PORT
   LAYER M4 ;
   RECT 302.208000 586.188000 302.400000 586.212000 ;
  END
 END pi0[64]
 PIN pi0[65]
  DIRECTION OUTPUT ;
  USE SIGNAL ;
  PORT
   LAYER M4 ;
   RECT 302.208000 586.380000 302.400000 586.404000 ;
  END
 END pi0[65]
 PIN pi0[66]
  DIRECTION OUTPUT ;
  USE SIGNAL ;
  PORT
   LAYER M4 ;
   RECT 302.208000 586.572000 302.400000 586.596000 ;
  END
 END pi0[66]
 PIN pi0[67]
  DIRECTION OUTPUT ;
  USE SIGNAL ;
  PORT
   LAYER M4 ;
   RECT 302.208000 586.764000 302.400000 586.788000 ;
  END
 END pi0[67]
 PIN pi0[68]
  DIRECTION OUTPUT ;
  USE SIGNAL ;
  PORT
   LAYER M4 ;
   RECT 302.208000 586.956000 302.400000 586.980000 ;
  END
 END pi0[68]
 PIN pi0[69]
  DIRECTION OUTPUT ;
  USE SIGNAL ;
  PORT
   LAYER M4 ;
   RECT 302.208000 587.148000 302.400000 587.172000 ;
  END
 END pi0[69]
 PIN pi0[70]
  DIRECTION OUTPUT ;
  USE SIGNAL ;
  PORT
   LAYER M4 ;
   RECT 302.208000 587.340000 302.400000 587.364000 ;
  END
 END pi0[70]
 PIN pi0[71]
  DIRECTION OUTPUT ;
  USE SIGNAL ;
  PORT
   LAYER M4 ;
   RECT 302.208000 587.532000 302.400000 587.556000 ;
  END
 END pi0[71]
 PIN pi0[72]
  DIRECTION OUTPUT ;
  USE SIGNAL ;
  PORT
   LAYER M4 ;
   RECT 302.208000 587.724000 302.400000 587.748000 ;
  END
 END pi0[72]
 PIN pi0[73]
  DIRECTION OUTPUT ;
  USE SIGNAL ;
  PORT
   LAYER M4 ;
   RECT 302.208000 587.916000 302.400000 587.940000 ;
  END
 END pi0[73]
 PIN pi0[74]
  DIRECTION OUTPUT ;
  USE SIGNAL ;
  PORT
   LAYER M4 ;
   RECT 302.208000 588.108000 302.400000 588.132000 ;
  END
 END pi0[74]
 PIN pi0[75]
  DIRECTION OUTPUT ;
  USE SIGNAL ;
  PORT
   LAYER M4 ;
   RECT 302.208000 588.300000 302.400000 588.324000 ;
  END
 END pi0[75]
 PIN pi0[76]
  DIRECTION OUTPUT ;
  USE SIGNAL ;
  PORT
   LAYER M4 ;
   RECT 302.208000 588.492000 302.400000 588.516000 ;
  END
 END pi0[76]
 PIN pi0[77]
  DIRECTION OUTPUT ;
  USE SIGNAL ;
  PORT
   LAYER M4 ;
   RECT 302.208000 588.684000 302.400000 588.708000 ;
  END
 END pi0[77]
 PIN pi0[78]
  DIRECTION OUTPUT ;
  USE SIGNAL ;
  PORT
   LAYER M4 ;
   RECT 302.208000 588.876000 302.400000 588.900000 ;
  END
 END pi0[78]
 PIN pi0[79]
  DIRECTION OUTPUT ;
  USE SIGNAL ;
  PORT
   LAYER M4 ;
   RECT 302.208000 589.068000 302.400000 589.092000 ;
  END
 END pi0[79]
 PIN pi0[80]
  DIRECTION OUTPUT ;
  USE SIGNAL ;
  PORT
   LAYER M4 ;
   RECT 302.208000 589.260000 302.400000 589.284000 ;
  END
 END pi0[80]
 PIN pi0[81]
  DIRECTION OUTPUT ;
  USE SIGNAL ;
  PORT
   LAYER M4 ;
   RECT 302.208000 589.452000 302.400000 589.476000 ;
  END
 END pi0[81]
 PIN pi0[82]
  DIRECTION OUTPUT ;
  USE SIGNAL ;
  PORT
   LAYER M4 ;
   RECT 302.208000 589.644000 302.400000 589.668000 ;
  END
 END pi0[82]
 PIN pi0[83]
  DIRECTION OUTPUT ;
  USE SIGNAL ;
  PORT
   LAYER M4 ;
   RECT 302.208000 589.836000 302.400000 589.860000 ;
  END
 END pi0[83]
 PIN pi0[84]
  DIRECTION OUTPUT ;
  USE SIGNAL ;
  PORT
   LAYER M4 ;
   RECT 302.208000 590.028000 302.400000 590.052000 ;
  END
 END pi0[84]
 PIN pi0[85]
  DIRECTION OUTPUT ;
  USE SIGNAL ;
  PORT
   LAYER M4 ;
   RECT 302.208000 590.220000 302.400000 590.244000 ;
  END
 END pi0[85]
 PIN pi0[86]
  DIRECTION OUTPUT ;
  USE SIGNAL ;
  PORT
   LAYER M4 ;
   RECT 302.208000 590.412000 302.400000 590.436000 ;
  END
 END pi0[86]
 PIN pi0[87]
  DIRECTION OUTPUT ;
  USE SIGNAL ;
  PORT
   LAYER M4 ;
   RECT 302.208000 590.604000 302.400000 590.628000 ;
  END
 END pi0[87]
 PIN pi0[88]
  DIRECTION OUTPUT ;
  USE SIGNAL ;
  PORT
   LAYER M4 ;
   RECT 302.208000 590.796000 302.400000 590.820000 ;
  END
 END pi0[88]
 PIN pi0[89]
  DIRECTION OUTPUT ;
  USE SIGNAL ;
  PORT
   LAYER M4 ;
   RECT 302.208000 590.988000 302.400000 591.012000 ;
  END
 END pi0[89]
 PIN pi0[90]
  DIRECTION OUTPUT ;
  USE SIGNAL ;
  PORT
   LAYER M4 ;
   RECT 302.208000 591.180000 302.400000 591.204000 ;
  END
 END pi0[90]
 PIN pi0[91]
  DIRECTION OUTPUT ;
  USE SIGNAL ;
  PORT
   LAYER M4 ;
   RECT 302.208000 591.372000 302.400000 591.396000 ;
  END
 END pi0[91]
 PIN pi0[92]
  DIRECTION OUTPUT ;
  USE SIGNAL ;
  PORT
   LAYER M4 ;
   RECT 302.208000 591.564000 302.400000 591.588000 ;
  END
 END pi0[92]
 PIN pi0[93]
  DIRECTION OUTPUT ;
  USE SIGNAL ;
  PORT
   LAYER M4 ;
   RECT 302.208000 591.756000 302.400000 591.780000 ;
  END
 END pi0[93]
 PIN pi0[94]
  DIRECTION OUTPUT ;
  USE SIGNAL ;
  PORT
   LAYER M4 ;
   RECT 302.208000 591.948000 302.400000 591.972000 ;
  END
 END pi0[94]
 PIN pi0[95]
  DIRECTION OUTPUT ;
  USE SIGNAL ;
  PORT
   LAYER M4 ;
   RECT 302.208000 592.140000 302.400000 592.164000 ;
  END
 END pi0[95]
 PIN pi0[96]
  DIRECTION OUTPUT ;
  USE SIGNAL ;
  PORT
   LAYER M4 ;
   RECT 302.208000 592.332000 302.400000 592.356000 ;
  END
 END pi0[96]
 PIN pi0[97]
  DIRECTION OUTPUT ;
  USE SIGNAL ;
  PORT
   LAYER M4 ;
   RECT 302.208000 592.524000 302.400000 592.548000 ;
  END
 END pi0[97]
 PIN pi0[98]
  DIRECTION OUTPUT ;
  USE SIGNAL ;
  PORT
   LAYER M4 ;
   RECT 302.208000 592.716000 302.400000 592.740000 ;
  END
 END pi0[98]
 PIN pi0[99]
  DIRECTION OUTPUT ;
  USE SIGNAL ;
  PORT
   LAYER M4 ;
   RECT 302.208000 592.908000 302.400000 592.932000 ;
  END
 END pi0[99]
 PIN pi0[100]
  DIRECTION OUTPUT ;
  USE SIGNAL ;
  PORT
   LAYER M4 ;
   RECT 302.208000 593.100000 302.400000 593.124000 ;
  END
 END pi0[100]
 PIN pi0[101]
  DIRECTION OUTPUT ;
  USE SIGNAL ;
  PORT
   LAYER M4 ;
   RECT 302.208000 593.292000 302.400000 593.316000 ;
  END
 END pi0[101]
 PIN pi0[102]
  DIRECTION OUTPUT ;
  USE SIGNAL ;
  PORT
   LAYER M4 ;
   RECT 302.208000 593.484000 302.400000 593.508000 ;
  END
 END pi0[102]
 PIN pi0[103]
  DIRECTION OUTPUT ;
  USE SIGNAL ;
  PORT
   LAYER M4 ;
   RECT 302.208000 593.676000 302.400000 593.700000 ;
  END
 END pi0[103]
 PIN pi0[104]
  DIRECTION OUTPUT ;
  USE SIGNAL ;
  PORT
   LAYER M4 ;
   RECT 302.208000 593.868000 302.400000 593.892000 ;
  END
 END pi0[104]
 PIN pi0[105]
  DIRECTION OUTPUT ;
  USE SIGNAL ;
  PORT
   LAYER M4 ;
   RECT 302.208000 594.060000 302.400000 594.084000 ;
  END
 END pi0[105]
 PIN pi0[106]
  DIRECTION OUTPUT ;
  USE SIGNAL ;
  PORT
   LAYER M4 ;
   RECT 302.208000 594.252000 302.400000 594.276000 ;
  END
 END pi0[106]
 PIN pi0[107]
  DIRECTION OUTPUT ;
  USE SIGNAL ;
  PORT
   LAYER M4 ;
   RECT 302.208000 594.444000 302.400000 594.468000 ;
  END
 END pi0[107]
 PIN pi0[108]
  DIRECTION OUTPUT ;
  USE SIGNAL ;
  PORT
   LAYER M4 ;
   RECT 302.208000 594.636000 302.400000 594.660000 ;
  END
 END pi0[108]
 PIN pi0[109]
  DIRECTION OUTPUT ;
  USE SIGNAL ;
  PORT
   LAYER M4 ;
   RECT 302.208000 594.828000 302.400000 594.852000 ;
  END
 END pi0[109]
 PIN pi0[110]
  DIRECTION OUTPUT ;
  USE SIGNAL ;
  PORT
   LAYER M4 ;
   RECT 302.208000 595.020000 302.400000 595.044000 ;
  END
 END pi0[110]
 PIN pi0[111]
  DIRECTION OUTPUT ;
  USE SIGNAL ;
  PORT
   LAYER M4 ;
   RECT 302.208000 595.212000 302.400000 595.236000 ;
  END
 END pi0[111]
 PIN pi0[112]
  DIRECTION OUTPUT ;
  USE SIGNAL ;
  PORT
   LAYER M4 ;
   RECT 302.208000 595.404000 302.400000 595.428000 ;
  END
 END pi0[112]
 PIN pi0[113]
  DIRECTION OUTPUT ;
  USE SIGNAL ;
  PORT
   LAYER M4 ;
   RECT 302.208000 595.596000 302.400000 595.620000 ;
  END
 END pi0[113]
 PIN pi0[114]
  DIRECTION OUTPUT ;
  USE SIGNAL ;
  PORT
   LAYER M4 ;
   RECT 302.208000 595.788000 302.400000 595.812000 ;
  END
 END pi0[114]
 PIN pi0[115]
  DIRECTION OUTPUT ;
  USE SIGNAL ;
  PORT
   LAYER M4 ;
   RECT 302.208000 595.980000 302.400000 596.004000 ;
  END
 END pi0[115]
 PIN pi0[116]
  DIRECTION OUTPUT ;
  USE SIGNAL ;
  PORT
   LAYER M4 ;
   RECT 302.208000 596.172000 302.400000 596.196000 ;
  END
 END pi0[116]
 PIN pi0[117]
  DIRECTION OUTPUT ;
  USE SIGNAL ;
  PORT
   LAYER M4 ;
   RECT 302.208000 596.364000 302.400000 596.388000 ;
  END
 END pi0[117]
 PIN pi0[118]
  DIRECTION OUTPUT ;
  USE SIGNAL ;
  PORT
   LAYER M4 ;
   RECT 302.208000 596.556000 302.400000 596.580000 ;
  END
 END pi0[118]
 PIN pi0[119]
  DIRECTION OUTPUT ;
  USE SIGNAL ;
  PORT
   LAYER M4 ;
   RECT 302.208000 596.748000 302.400000 596.772000 ;
  END
 END pi0[119]
 PIN pi0[120]
  DIRECTION OUTPUT ;
  USE SIGNAL ;
  PORT
   LAYER M4 ;
   RECT 302.208000 596.940000 302.400000 596.964000 ;
  END
 END pi0[120]
 PIN pi0[121]
  DIRECTION OUTPUT ;
  USE SIGNAL ;
  PORT
   LAYER M4 ;
   RECT 302.208000 597.132000 302.400000 597.156000 ;
  END
 END pi0[121]
 PIN pi0[122]
  DIRECTION OUTPUT ;
  USE SIGNAL ;
  PORT
   LAYER M4 ;
   RECT 302.208000 597.324000 302.400000 597.348000 ;
  END
 END pi0[122]
 PIN pi0[123]
  DIRECTION OUTPUT ;
  USE SIGNAL ;
  PORT
   LAYER M4 ;
   RECT 302.208000 597.516000 302.400000 597.540000 ;
  END
 END pi0[123]
 PIN pi0[124]
  DIRECTION OUTPUT ;
  USE SIGNAL ;
  PORT
   LAYER M4 ;
   RECT 302.208000 597.708000 302.400000 597.732000 ;
  END
 END pi0[124]
 PIN pi0[125]
  DIRECTION OUTPUT ;
  USE SIGNAL ;
  PORT
   LAYER M4 ;
   RECT 302.208000 597.900000 302.400000 597.924000 ;
  END
 END pi0[125]
 PIN pi0[126]
  DIRECTION OUTPUT ;
  USE SIGNAL ;
  PORT
   LAYER M4 ;
   RECT 302.208000 598.092000 302.400000 598.116000 ;
  END
 END pi0[126]
 PIN pi0[127]
  DIRECTION OUTPUT ;
  USE SIGNAL ;
  PORT
   LAYER M4 ;
   RECT 302.208000 598.284000 302.400000 598.308000 ;
  END
 END pi0[127]
 PIN pi0[128]
  DIRECTION OUTPUT ;
  USE SIGNAL ;
  PORT
   LAYER M4 ;
   RECT 302.208000 598.476000 302.400000 598.500000 ;
  END
 END pi0[128]
 PIN pi0[129]
  DIRECTION OUTPUT ;
  USE SIGNAL ;
  PORT
   LAYER M4 ;
   RECT 302.208000 598.668000 302.400000 598.692000 ;
  END
 END pi0[129]
 PIN pi0[130]
  DIRECTION OUTPUT ;
  USE SIGNAL ;
  PORT
   LAYER M4 ;
   RECT 302.208000 598.860000 302.400000 598.884000 ;
  END
 END pi0[130]
 PIN pi0[131]
  DIRECTION OUTPUT ;
  USE SIGNAL ;
  PORT
   LAYER M4 ;
   RECT 302.208000 599.052000 302.400000 599.076000 ;
  END
 END pi0[131]
 PIN pi0[132]
  DIRECTION OUTPUT ;
  USE SIGNAL ;
  PORT
   LAYER M4 ;
   RECT 302.208000 599.244000 302.400000 599.268000 ;
  END
 END pi0[132]
 PIN pi0[133]
  DIRECTION OUTPUT ;
  USE SIGNAL ;
  PORT
   LAYER M4 ;
   RECT 302.208000 599.436000 302.400000 599.460000 ;
  END
 END pi0[133]
 PIN pi0[134]
  DIRECTION OUTPUT ;
  USE SIGNAL ;
  PORT
   LAYER M4 ;
   RECT 302.208000 599.628000 302.400000 599.652000 ;
  END
 END pi0[134]
 PIN pi0[135]
  DIRECTION OUTPUT ;
  USE SIGNAL ;
  PORT
   LAYER M4 ;
   RECT 302.208000 599.820000 302.400000 599.844000 ;
  END
 END pi0[135]
 PIN pi0[136]
  DIRECTION OUTPUT ;
  USE SIGNAL ;
  PORT
   LAYER M4 ;
   RECT 302.208000 600.012000 302.400000 600.036000 ;
  END
 END pi0[136]
 PIN pi0[137]
  DIRECTION OUTPUT ;
  USE SIGNAL ;
  PORT
   LAYER M4 ;
   RECT 302.208000 600.204000 302.400000 600.228000 ;
  END
 END pi0[137]
 PIN pi0[138]
  DIRECTION OUTPUT ;
  USE SIGNAL ;
  PORT
   LAYER M4 ;
   RECT 302.208000 600.396000 302.400000 600.420000 ;
  END
 END pi0[138]
 PIN pi0[139]
  DIRECTION OUTPUT ;
  USE SIGNAL ;
  PORT
   LAYER M4 ;
   RECT 302.208000 600.588000 302.400000 600.612000 ;
  END
 END pi0[139]
 PIN pi0[140]
  DIRECTION OUTPUT ;
  USE SIGNAL ;
  PORT
   LAYER M4 ;
   RECT 302.208000 600.780000 302.400000 600.804000 ;
  END
 END pi0[140]
 PIN pi0[141]
  DIRECTION OUTPUT ;
  USE SIGNAL ;
  PORT
   LAYER M4 ;
   RECT 302.208000 600.972000 302.400000 600.996000 ;
  END
 END pi0[141]
 PIN pi0[142]
  DIRECTION OUTPUT ;
  USE SIGNAL ;
  PORT
   LAYER M4 ;
   RECT 302.208000 601.164000 302.400000 601.188000 ;
  END
 END pi0[142]
 PIN pi0[143]
  DIRECTION OUTPUT ;
  USE SIGNAL ;
  PORT
   LAYER M4 ;
   RECT 302.208000 601.356000 302.400000 601.380000 ;
  END
 END pi0[143]
 PIN pi0[144]
  DIRECTION OUTPUT ;
  USE SIGNAL ;
  PORT
   LAYER M4 ;
   RECT 302.208000 601.548000 302.400000 601.572000 ;
  END
 END pi0[144]
 PIN pi0[145]
  DIRECTION OUTPUT ;
  USE SIGNAL ;
  PORT
   LAYER M4 ;
   RECT 302.208000 601.740000 302.400000 601.764000 ;
  END
 END pi0[145]
 PIN pi0[146]
  DIRECTION OUTPUT ;
  USE SIGNAL ;
  PORT
   LAYER M4 ;
   RECT 302.208000 601.932000 302.400000 601.956000 ;
  END
 END pi0[146]
 PIN pi0[147]
  DIRECTION OUTPUT ;
  USE SIGNAL ;
  PORT
   LAYER M4 ;
   RECT 302.208000 602.124000 302.400000 602.148000 ;
  END
 END pi0[147]
 PIN pi0[148]
  DIRECTION OUTPUT ;
  USE SIGNAL ;
  PORT
   LAYER M4 ;
   RECT 302.208000 602.316000 302.400000 602.340000 ;
  END
 END pi0[148]
 PIN pi0[149]
  DIRECTION OUTPUT ;
  USE SIGNAL ;
  PORT
   LAYER M4 ;
   RECT 302.208000 602.508000 302.400000 602.532000 ;
  END
 END pi0[149]
 PIN pi0[150]
  DIRECTION OUTPUT ;
  USE SIGNAL ;
  PORT
   LAYER M4 ;
   RECT 302.208000 602.700000 302.400000 602.724000 ;
  END
 END pi0[150]
 PIN pi0[151]
  DIRECTION OUTPUT ;
  USE SIGNAL ;
  PORT
   LAYER M4 ;
   RECT 302.208000 602.892000 302.400000 602.916000 ;
  END
 END pi0[151]
 PIN pi0[152]
  DIRECTION OUTPUT ;
  USE SIGNAL ;
  PORT
   LAYER M4 ;
   RECT 302.208000 603.084000 302.400000 603.108000 ;
  END
 END pi0[152]
 PIN pi0[153]
  DIRECTION OUTPUT ;
  USE SIGNAL ;
  PORT
   LAYER M4 ;
   RECT 302.208000 603.276000 302.400000 603.300000 ;
  END
 END pi0[153]
 PIN pi0[154]
  DIRECTION OUTPUT ;
  USE SIGNAL ;
  PORT
   LAYER M4 ;
   RECT 302.208000 603.468000 302.400000 603.492000 ;
  END
 END pi0[154]
 PIN pi0[155]
  DIRECTION OUTPUT ;
  USE SIGNAL ;
  PORT
   LAYER M4 ;
   RECT 302.208000 603.660000 302.400000 603.684000 ;
  END
 END pi0[155]
 PIN pi0[156]
  DIRECTION OUTPUT ;
  USE SIGNAL ;
  PORT
   LAYER M4 ;
   RECT 302.208000 603.852000 302.400000 603.876000 ;
  END
 END pi0[156]
 PIN pi0[157]
  DIRECTION OUTPUT ;
  USE SIGNAL ;
  PORT
   LAYER M4 ;
   RECT 302.208000 604.044000 302.400000 604.068000 ;
  END
 END pi0[157]
 PIN pi0[158]
  DIRECTION OUTPUT ;
  USE SIGNAL ;
  PORT
   LAYER M4 ;
   RECT 302.208000 604.236000 302.400000 604.260000 ;
  END
 END pi0[158]
 PIN pi0[159]
  DIRECTION OUTPUT ;
  USE SIGNAL ;
  PORT
   LAYER M4 ;
   RECT 302.208000 604.428000 302.400000 604.452000 ;
  END
 END pi0[159]
 PIN pi0[160]
  DIRECTION OUTPUT ;
  USE SIGNAL ;
  PORT
   LAYER M4 ;
   RECT 302.208000 604.620000 302.400000 604.644000 ;
  END
 END pi0[160]
 PIN pi0[161]
  DIRECTION OUTPUT ;
  USE SIGNAL ;
  PORT
   LAYER M4 ;
   RECT 302.208000 604.812000 302.400000 604.836000 ;
  END
 END pi0[161]
 PIN pi0[162]
  DIRECTION OUTPUT ;
  USE SIGNAL ;
  PORT
   LAYER M4 ;
   RECT 302.208000 605.004000 302.400000 605.028000 ;
  END
 END pi0[162]
 PIN pi0[163]
  DIRECTION OUTPUT ;
  USE SIGNAL ;
  PORT
   LAYER M4 ;
   RECT 302.208000 605.196000 302.400000 605.220000 ;
  END
 END pi0[163]
 PIN pi0[164]
  DIRECTION OUTPUT ;
  USE SIGNAL ;
  PORT
   LAYER M4 ;
   RECT 302.208000 605.388000 302.400000 605.412000 ;
  END
 END pi0[164]
 PIN pi0[165]
  DIRECTION OUTPUT ;
  USE SIGNAL ;
  PORT
   LAYER M4 ;
   RECT 302.208000 605.580000 302.400000 605.604000 ;
  END
 END pi0[165]
 PIN pi0[166]
  DIRECTION OUTPUT ;
  USE SIGNAL ;
  PORT
   LAYER M4 ;
   RECT 302.208000 605.772000 302.400000 605.796000 ;
  END
 END pi0[166]
 PIN pi0[167]
  DIRECTION OUTPUT ;
  USE SIGNAL ;
  PORT
   LAYER M4 ;
   RECT 302.208000 605.964000 302.400000 605.988000 ;
  END
 END pi0[167]
 PIN pi0[168]
  DIRECTION OUTPUT ;
  USE SIGNAL ;
  PORT
   LAYER M4 ;
   RECT 302.208000 606.156000 302.400000 606.180000 ;
  END
 END pi0[168]
 PIN pi0[169]
  DIRECTION OUTPUT ;
  USE SIGNAL ;
  PORT
   LAYER M4 ;
   RECT 302.208000 606.348000 302.400000 606.372000 ;
  END
 END pi0[169]
 PIN pi0[170]
  DIRECTION OUTPUT ;
  USE SIGNAL ;
  PORT
   LAYER M4 ;
   RECT 302.208000 606.540000 302.400000 606.564000 ;
  END
 END pi0[170]
 PIN pi0[171]
  DIRECTION OUTPUT ;
  USE SIGNAL ;
  PORT
   LAYER M4 ;
   RECT 302.208000 606.732000 302.400000 606.756000 ;
  END
 END pi0[171]
 PIN pi0[172]
  DIRECTION OUTPUT ;
  USE SIGNAL ;
  PORT
   LAYER M4 ;
   RECT 302.208000 606.924000 302.400000 606.948000 ;
  END
 END pi0[172]
 PIN pi0[173]
  DIRECTION OUTPUT ;
  USE SIGNAL ;
  PORT
   LAYER M4 ;
   RECT 302.208000 607.116000 302.400000 607.140000 ;
  END
 END pi0[173]
 PIN pi0[174]
  DIRECTION OUTPUT ;
  USE SIGNAL ;
  PORT
   LAYER M4 ;
   RECT 302.208000 607.308000 302.400000 607.332000 ;
  END
 END pi0[174]
 PIN pi0[175]
  DIRECTION OUTPUT ;
  USE SIGNAL ;
  PORT
   LAYER M4 ;
   RECT 302.208000 607.500000 302.400000 607.524000 ;
  END
 END pi0[175]
 PIN pi0[176]
  DIRECTION OUTPUT ;
  USE SIGNAL ;
  PORT
   LAYER M4 ;
   RECT 302.208000 607.692000 302.400000 607.716000 ;
  END
 END pi0[176]
 PIN pi0[177]
  DIRECTION OUTPUT ;
  USE SIGNAL ;
  PORT
   LAYER M4 ;
   RECT 302.208000 607.884000 302.400000 607.908000 ;
  END
 END pi0[177]
 PIN pi0[178]
  DIRECTION OUTPUT ;
  USE SIGNAL ;
  PORT
   LAYER M4 ;
   RECT 302.208000 608.076000 302.400000 608.100000 ;
  END
 END pi0[178]
 PIN pi0[179]
  DIRECTION OUTPUT ;
  USE SIGNAL ;
  PORT
   LAYER M4 ;
   RECT 302.208000 608.268000 302.400000 608.292000 ;
  END
 END pi0[179]
 PIN pi0[180]
  DIRECTION OUTPUT ;
  USE SIGNAL ;
  PORT
   LAYER M4 ;
   RECT 302.208000 608.460000 302.400000 608.484000 ;
  END
 END pi0[180]
 PIN pi0[181]
  DIRECTION OUTPUT ;
  USE SIGNAL ;
  PORT
   LAYER M4 ;
   RECT 302.208000 608.652000 302.400000 608.676000 ;
  END
 END pi0[181]
 PIN pi0[182]
  DIRECTION OUTPUT ;
  USE SIGNAL ;
  PORT
   LAYER M4 ;
   RECT 302.208000 608.844000 302.400000 608.868000 ;
  END
 END pi0[182]
 PIN pi0[183]
  DIRECTION OUTPUT ;
  USE SIGNAL ;
  PORT
   LAYER M4 ;
   RECT 302.208000 609.036000 302.400000 609.060000 ;
  END
 END pi0[183]
 PIN pi0[184]
  DIRECTION OUTPUT ;
  USE SIGNAL ;
  PORT
   LAYER M4 ;
   RECT 302.208000 609.228000 302.400000 609.252000 ;
  END
 END pi0[184]
 PIN pi0[185]
  DIRECTION OUTPUT ;
  USE SIGNAL ;
  PORT
   LAYER M4 ;
   RECT 302.208000 609.420000 302.400000 609.444000 ;
  END
 END pi0[185]
 PIN pi0[186]
  DIRECTION OUTPUT ;
  USE SIGNAL ;
  PORT
   LAYER M4 ;
   RECT 302.208000 609.612000 302.400000 609.636000 ;
  END
 END pi0[186]
 PIN pi0[187]
  DIRECTION OUTPUT ;
  USE SIGNAL ;
  PORT
   LAYER M4 ;
   RECT 302.208000 609.804000 302.400000 609.828000 ;
  END
 END pi0[187]
 PIN pi0[188]
  DIRECTION OUTPUT ;
  USE SIGNAL ;
  PORT
   LAYER M4 ;
   RECT 302.208000 609.996000 302.400000 610.020000 ;
  END
 END pi0[188]
 PIN pi0[189]
  DIRECTION OUTPUT ;
  USE SIGNAL ;
  PORT
   LAYER M4 ;
   RECT 302.208000 610.188000 302.400000 610.212000 ;
  END
 END pi0[189]
 PIN pi0[190]
  DIRECTION OUTPUT ;
  USE SIGNAL ;
  PORT
   LAYER M4 ;
   RECT 302.208000 610.380000 302.400000 610.404000 ;
  END
 END pi0[190]
 PIN pi0[191]
  DIRECTION OUTPUT ;
  USE SIGNAL ;
  PORT
   LAYER M4 ;
   RECT 302.208000 610.572000 302.400000 610.596000 ;
  END
 END pi0[191]
 PIN pi0[192]
  DIRECTION OUTPUT ;
  USE SIGNAL ;
  PORT
   LAYER M4 ;
   RECT 302.208000 610.764000 302.400000 610.788000 ;
  END
 END pi0[192]
 PIN pi0[193]
  DIRECTION OUTPUT ;
  USE SIGNAL ;
  PORT
   LAYER M4 ;
   RECT 302.208000 610.956000 302.400000 610.980000 ;
  END
 END pi0[193]
 PIN pi0[194]
  DIRECTION OUTPUT ;
  USE SIGNAL ;
  PORT
   LAYER M4 ;
   RECT 302.208000 611.148000 302.400000 611.172000 ;
  END
 END pi0[194]
 PIN pi0[195]
  DIRECTION OUTPUT ;
  USE SIGNAL ;
  PORT
   LAYER M4 ;
   RECT 302.208000 611.340000 302.400000 611.364000 ;
  END
 END pi0[195]
 PIN pi0[196]
  DIRECTION OUTPUT ;
  USE SIGNAL ;
  PORT
   LAYER M4 ;
   RECT 302.208000 611.532000 302.400000 611.556000 ;
  END
 END pi0[196]
 PIN pi0[197]
  DIRECTION OUTPUT ;
  USE SIGNAL ;
  PORT
   LAYER M4 ;
   RECT 302.208000 611.724000 302.400000 611.748000 ;
  END
 END pi0[197]
 PIN pi0[198]
  DIRECTION OUTPUT ;
  USE SIGNAL ;
  PORT
   LAYER M4 ;
   RECT 302.208000 611.916000 302.400000 611.940000 ;
  END
 END pi0[198]
 PIN pi0[199]
  DIRECTION OUTPUT ;
  USE SIGNAL ;
  PORT
   LAYER M4 ;
   RECT 302.208000 612.108000 302.400000 612.132000 ;
  END
 END pi0[199]
 PIN pi0[200]
  DIRECTION OUTPUT ;
  USE SIGNAL ;
  PORT
   LAYER M4 ;
   RECT 302.208000 612.300000 302.400000 612.324000 ;
  END
 END pi0[200]
 PIN pi0[201]
  DIRECTION OUTPUT ;
  USE SIGNAL ;
  PORT
   LAYER M4 ;
   RECT 302.208000 612.492000 302.400000 612.516000 ;
  END
 END pi0[201]
 PIN pi0[202]
  DIRECTION OUTPUT ;
  USE SIGNAL ;
  PORT
   LAYER M4 ;
   RECT 302.208000 612.684000 302.400000 612.708000 ;
  END
 END pi0[202]
 PIN pi0[203]
  DIRECTION OUTPUT ;
  USE SIGNAL ;
  PORT
   LAYER M4 ;
   RECT 302.208000 612.876000 302.400000 612.900000 ;
  END
 END pi0[203]
 PIN pi0[204]
  DIRECTION OUTPUT ;
  USE SIGNAL ;
  PORT
   LAYER M4 ;
   RECT 302.208000 613.068000 302.400000 613.092000 ;
  END
 END pi0[204]
 PIN pi0[205]
  DIRECTION OUTPUT ;
  USE SIGNAL ;
  PORT
   LAYER M4 ;
   RECT 302.208000 613.260000 302.400000 613.284000 ;
  END
 END pi0[205]
 PIN pi0[206]
  DIRECTION OUTPUT ;
  USE SIGNAL ;
  PORT
   LAYER M4 ;
   RECT 302.208000 613.452000 302.400000 613.476000 ;
  END
 END pi0[206]
 PIN pi0[207]
  DIRECTION OUTPUT ;
  USE SIGNAL ;
  PORT
   LAYER M4 ;
   RECT 302.208000 613.644000 302.400000 613.668000 ;
  END
 END pi0[207]
 PIN pi0[208]
  DIRECTION OUTPUT ;
  USE SIGNAL ;
  PORT
   LAYER M4 ;
   RECT 302.208000 613.836000 302.400000 613.860000 ;
  END
 END pi0[208]
 PIN pi0[209]
  DIRECTION OUTPUT ;
  USE SIGNAL ;
  PORT
   LAYER M4 ;
   RECT 302.208000 614.028000 302.400000 614.052000 ;
  END
 END pi0[209]
 PIN pi0[210]
  DIRECTION OUTPUT ;
  USE SIGNAL ;
  PORT
   LAYER M4 ;
   RECT 302.208000 614.220000 302.400000 614.244000 ;
  END
 END pi0[210]
 PIN pi0[211]
  DIRECTION OUTPUT ;
  USE SIGNAL ;
  PORT
   LAYER M4 ;
   RECT 302.208000 614.412000 302.400000 614.436000 ;
  END
 END pi0[211]
 PIN pi0[212]
  DIRECTION OUTPUT ;
  USE SIGNAL ;
  PORT
   LAYER M4 ;
   RECT 302.208000 614.604000 302.400000 614.628000 ;
  END
 END pi0[212]
 PIN pi0[213]
  DIRECTION OUTPUT ;
  USE SIGNAL ;
  PORT
   LAYER M4 ;
   RECT 302.208000 614.796000 302.400000 614.820000 ;
  END
 END pi0[213]
 PIN pi0[214]
  DIRECTION OUTPUT ;
  USE SIGNAL ;
  PORT
   LAYER M4 ;
   RECT 302.208000 614.988000 302.400000 615.012000 ;
  END
 END pi0[214]
 PIN pi0[215]
  DIRECTION OUTPUT ;
  USE SIGNAL ;
  PORT
   LAYER M4 ;
   RECT 302.208000 615.180000 302.400000 615.204000 ;
  END
 END pi0[215]
 PIN pi0[216]
  DIRECTION OUTPUT ;
  USE SIGNAL ;
  PORT
   LAYER M4 ;
   RECT 302.208000 615.372000 302.400000 615.396000 ;
  END
 END pi0[216]
 PIN pi0[217]
  DIRECTION OUTPUT ;
  USE SIGNAL ;
  PORT
   LAYER M4 ;
   RECT 302.208000 615.564000 302.400000 615.588000 ;
  END
 END pi0[217]
 PIN pi0[218]
  DIRECTION OUTPUT ;
  USE SIGNAL ;
  PORT
   LAYER M4 ;
   RECT 302.208000 615.756000 302.400000 615.780000 ;
  END
 END pi0[218]
 PIN pi0[219]
  DIRECTION OUTPUT ;
  USE SIGNAL ;
  PORT
   LAYER M4 ;
   RECT 302.208000 615.948000 302.400000 615.972000 ;
  END
 END pi0[219]
 PIN pi0[220]
  DIRECTION OUTPUT ;
  USE SIGNAL ;
  PORT
   LAYER M4 ;
   RECT 302.208000 616.140000 302.400000 616.164000 ;
  END
 END pi0[220]
 PIN pi0[221]
  DIRECTION OUTPUT ;
  USE SIGNAL ;
  PORT
   LAYER M4 ;
   RECT 302.208000 616.332000 302.400000 616.356000 ;
  END
 END pi0[221]
 PIN pi0[222]
  DIRECTION OUTPUT ;
  USE SIGNAL ;
  PORT
   LAYER M4 ;
   RECT 302.208000 616.524000 302.400000 616.548000 ;
  END
 END pi0[222]
 PIN pi0[223]
  DIRECTION OUTPUT ;
  USE SIGNAL ;
  PORT
   LAYER M4 ;
   RECT 302.208000 616.716000 302.400000 616.740000 ;
  END
 END pi0[223]
 PIN pi0[224]
  DIRECTION OUTPUT ;
  USE SIGNAL ;
  PORT
   LAYER M4 ;
   RECT 302.208000 616.908000 302.400000 616.932000 ;
  END
 END pi0[224]
 PIN pi0[225]
  DIRECTION OUTPUT ;
  USE SIGNAL ;
  PORT
   LAYER M4 ;
   RECT 302.208000 617.100000 302.400000 617.124000 ;
  END
 END pi0[225]
 PIN pi0[226]
  DIRECTION OUTPUT ;
  USE SIGNAL ;
  PORT
   LAYER M4 ;
   RECT 302.208000 617.292000 302.400000 617.316000 ;
  END
 END pi0[226]
 PIN pi0[227]
  DIRECTION OUTPUT ;
  USE SIGNAL ;
  PORT
   LAYER M4 ;
   RECT 302.208000 617.484000 302.400000 617.508000 ;
  END
 END pi0[227]
 PIN pi0[228]
  DIRECTION OUTPUT ;
  USE SIGNAL ;
  PORT
   LAYER M4 ;
   RECT 302.208000 617.676000 302.400000 617.700000 ;
  END
 END pi0[228]
 PIN pi0[229]
  DIRECTION OUTPUT ;
  USE SIGNAL ;
  PORT
   LAYER M4 ;
   RECT 302.208000 617.868000 302.400000 617.892000 ;
  END
 END pi0[229]
 PIN pi0[230]
  DIRECTION OUTPUT ;
  USE SIGNAL ;
  PORT
   LAYER M4 ;
   RECT 302.208000 618.060000 302.400000 618.084000 ;
  END
 END pi0[230]
 PIN pi0[231]
  DIRECTION OUTPUT ;
  USE SIGNAL ;
  PORT
   LAYER M4 ;
   RECT 302.208000 618.252000 302.400000 618.276000 ;
  END
 END pi0[231]
 PIN pi0[232]
  DIRECTION OUTPUT ;
  USE SIGNAL ;
  PORT
   LAYER M4 ;
   RECT 302.208000 618.444000 302.400000 618.468000 ;
  END
 END pi0[232]
 PIN pi0[233]
  DIRECTION OUTPUT ;
  USE SIGNAL ;
  PORT
   LAYER M4 ;
   RECT 302.208000 618.636000 302.400000 618.660000 ;
  END
 END pi0[233]
 PIN pi0[234]
  DIRECTION OUTPUT ;
  USE SIGNAL ;
  PORT
   LAYER M4 ;
   RECT 302.208000 618.828000 302.400000 618.852000 ;
  END
 END pi0[234]
 PIN pi0[235]
  DIRECTION OUTPUT ;
  USE SIGNAL ;
  PORT
   LAYER M4 ;
   RECT 302.208000 619.020000 302.400000 619.044000 ;
  END
 END pi0[235]
 PIN pi0[236]
  DIRECTION OUTPUT ;
  USE SIGNAL ;
  PORT
   LAYER M4 ;
   RECT 302.208000 619.212000 302.400000 619.236000 ;
  END
 END pi0[236]
 PIN pi0[237]
  DIRECTION OUTPUT ;
  USE SIGNAL ;
  PORT
   LAYER M4 ;
   RECT 302.208000 619.404000 302.400000 619.428000 ;
  END
 END pi0[237]
 PIN pi0[238]
  DIRECTION OUTPUT ;
  USE SIGNAL ;
  PORT
   LAYER M4 ;
   RECT 302.208000 619.596000 302.400000 619.620000 ;
  END
 END pi0[238]
 PIN pi0[239]
  DIRECTION OUTPUT ;
  USE SIGNAL ;
  PORT
   LAYER M4 ;
   RECT 302.208000 619.788000 302.400000 619.812000 ;
  END
 END pi0[239]
 PIN pi0[240]
  DIRECTION OUTPUT ;
  USE SIGNAL ;
  PORT
   LAYER M4 ;
   RECT 302.208000 619.980000 302.400000 620.004000 ;
  END
 END pi0[240]
 PIN pi0[241]
  DIRECTION OUTPUT ;
  USE SIGNAL ;
  PORT
   LAYER M4 ;
   RECT 302.208000 620.172000 302.400000 620.196000 ;
  END
 END pi0[241]
 PIN pi0[242]
  DIRECTION OUTPUT ;
  USE SIGNAL ;
  PORT
   LAYER M4 ;
   RECT 302.208000 620.364000 302.400000 620.388000 ;
  END
 END pi0[242]
 PIN pi0[243]
  DIRECTION OUTPUT ;
  USE SIGNAL ;
  PORT
   LAYER M4 ;
   RECT 302.208000 620.556000 302.400000 620.580000 ;
  END
 END pi0[243]
 PIN pi0[244]
  DIRECTION OUTPUT ;
  USE SIGNAL ;
  PORT
   LAYER M4 ;
   RECT 302.208000 620.748000 302.400000 620.772000 ;
  END
 END pi0[244]
 PIN pi0[245]
  DIRECTION OUTPUT ;
  USE SIGNAL ;
  PORT
   LAYER M4 ;
   RECT 302.208000 620.940000 302.400000 620.964000 ;
  END
 END pi0[245]
 PIN pi0[246]
  DIRECTION OUTPUT ;
  USE SIGNAL ;
  PORT
   LAYER M4 ;
   RECT 302.208000 621.132000 302.400000 621.156000 ;
  END
 END pi0[246]
 PIN pi0[247]
  DIRECTION OUTPUT ;
  USE SIGNAL ;
  PORT
   LAYER M4 ;
   RECT 302.208000 621.324000 302.400000 621.348000 ;
  END
 END pi0[247]
 PIN pi0[248]
  DIRECTION OUTPUT ;
  USE SIGNAL ;
  PORT
   LAYER M4 ;
   RECT 302.208000 621.516000 302.400000 621.540000 ;
  END
 END pi0[248]
 PIN pi0[249]
  DIRECTION OUTPUT ;
  USE SIGNAL ;
  PORT
   LAYER M4 ;
   RECT 302.208000 621.708000 302.400000 621.732000 ;
  END
 END pi0[249]
 PIN pi0[250]
  DIRECTION OUTPUT ;
  USE SIGNAL ;
  PORT
   LAYER M4 ;
   RECT 302.208000 621.900000 302.400000 621.924000 ;
  END
 END pi0[250]
 PIN pi0[251]
  DIRECTION OUTPUT ;
  USE SIGNAL ;
  PORT
   LAYER M4 ;
   RECT 302.208000 622.092000 302.400000 622.116000 ;
  END
 END pi0[251]
 PIN pi0[252]
  DIRECTION OUTPUT ;
  USE SIGNAL ;
  PORT
   LAYER M4 ;
   RECT 302.208000 622.284000 302.400000 622.308000 ;
  END
 END pi0[252]
 PIN pi0[253]
  DIRECTION OUTPUT ;
  USE SIGNAL ;
  PORT
   LAYER M4 ;
   RECT 302.208000 622.476000 302.400000 622.500000 ;
  END
 END pi0[253]
 PIN pi0[254]
  DIRECTION OUTPUT ;
  USE SIGNAL ;
  PORT
   LAYER M4 ;
   RECT 302.208000 622.668000 302.400000 622.692000 ;
  END
 END pi0[254]
 PIN pi0[255]
  DIRECTION OUTPUT ;
  USE SIGNAL ;
  PORT
   LAYER M4 ;
   RECT 302.208000 622.860000 302.400000 622.884000 ;
  END
 END pi0[255]
 PIN pi0[256]
  DIRECTION OUTPUT ;
  USE SIGNAL ;
  PORT
   LAYER M4 ;
   RECT 302.208000 623.052000 302.400000 623.076000 ;
  END
 END pi0[256]
 PIN pi0[257]
  DIRECTION OUTPUT ;
  USE SIGNAL ;
  PORT
   LAYER M4 ;
   RECT 302.208000 623.244000 302.400000 623.268000 ;
  END
 END pi0[257]
 PIN pi0[258]
  DIRECTION OUTPUT ;
  USE SIGNAL ;
  PORT
   LAYER M4 ;
   RECT 302.208000 623.436000 302.400000 623.460000 ;
  END
 END pi0[258]
 PIN pi0[259]
  DIRECTION OUTPUT ;
  USE SIGNAL ;
  PORT
   LAYER M4 ;
   RECT 302.208000 623.628000 302.400000 623.652000 ;
  END
 END pi0[259]
 PIN pi0[260]
  DIRECTION OUTPUT ;
  USE SIGNAL ;
  PORT
   LAYER M4 ;
   RECT 302.208000 623.820000 302.400000 623.844000 ;
  END
 END pi0[260]
 PIN pi0[261]
  DIRECTION OUTPUT ;
  USE SIGNAL ;
  PORT
   LAYER M4 ;
   RECT 302.208000 624.012000 302.400000 624.036000 ;
  END
 END pi0[261]
 PIN pi0[262]
  DIRECTION OUTPUT ;
  USE SIGNAL ;
  PORT
   LAYER M4 ;
   RECT 302.208000 624.204000 302.400000 624.228000 ;
  END
 END pi0[262]
 PIN pi0[263]
  DIRECTION OUTPUT ;
  USE SIGNAL ;
  PORT
   LAYER M4 ;
   RECT 302.208000 624.396000 302.400000 624.420000 ;
  END
 END pi0[263]
 PIN pi0[264]
  DIRECTION OUTPUT ;
  USE SIGNAL ;
  PORT
   LAYER M4 ;
   RECT 302.208000 624.588000 302.400000 624.612000 ;
  END
 END pi0[264]
 PIN pi0[265]
  DIRECTION OUTPUT ;
  USE SIGNAL ;
  PORT
   LAYER M4 ;
   RECT 302.208000 624.780000 302.400000 624.804000 ;
  END
 END pi0[265]
 PIN pi0[266]
  DIRECTION OUTPUT ;
  USE SIGNAL ;
  PORT
   LAYER M4 ;
   RECT 302.208000 624.972000 302.400000 624.996000 ;
  END
 END pi0[266]
 PIN pi0[267]
  DIRECTION OUTPUT ;
  USE SIGNAL ;
  PORT
   LAYER M4 ;
   RECT 302.208000 625.164000 302.400000 625.188000 ;
  END
 END pi0[267]
 PIN pi0[268]
  DIRECTION OUTPUT ;
  USE SIGNAL ;
  PORT
   LAYER M4 ;
   RECT 302.208000 625.356000 302.400000 625.380000 ;
  END
 END pi0[268]
 PIN pi0[269]
  DIRECTION OUTPUT ;
  USE SIGNAL ;
  PORT
   LAYER M4 ;
   RECT 302.208000 625.548000 302.400000 625.572000 ;
  END
 END pi0[269]
 PIN pi0[270]
  DIRECTION OUTPUT ;
  USE SIGNAL ;
  PORT
   LAYER M4 ;
   RECT 302.208000 625.740000 302.400000 625.764000 ;
  END
 END pi0[270]
 PIN pi0[271]
  DIRECTION OUTPUT ;
  USE SIGNAL ;
  PORT
   LAYER M4 ;
   RECT 302.208000 625.932000 302.400000 625.956000 ;
  END
 END pi0[271]
 PIN pi0[272]
  DIRECTION OUTPUT ;
  USE SIGNAL ;
  PORT
   LAYER M4 ;
   RECT 302.208000 626.124000 302.400000 626.148000 ;
  END
 END pi0[272]
 PIN pi0[273]
  DIRECTION OUTPUT ;
  USE SIGNAL ;
  PORT
   LAYER M4 ;
   RECT 302.208000 626.316000 302.400000 626.340000 ;
  END
 END pi0[273]
 PIN pi0[274]
  DIRECTION OUTPUT ;
  USE SIGNAL ;
  PORT
   LAYER M4 ;
   RECT 302.208000 626.508000 302.400000 626.532000 ;
  END
 END pi0[274]
 PIN pi0[275]
  DIRECTION OUTPUT ;
  USE SIGNAL ;
  PORT
   LAYER M4 ;
   RECT 302.208000 626.700000 302.400000 626.724000 ;
  END
 END pi0[275]
 PIN pi0[276]
  DIRECTION OUTPUT ;
  USE SIGNAL ;
  PORT
   LAYER M4 ;
   RECT 302.208000 626.892000 302.400000 626.916000 ;
  END
 END pi0[276]
 PIN pi0[277]
  DIRECTION OUTPUT ;
  USE SIGNAL ;
  PORT
   LAYER M4 ;
   RECT 302.208000 627.084000 302.400000 627.108000 ;
  END
 END pi0[277]
 PIN pi0[278]
  DIRECTION OUTPUT ;
  USE SIGNAL ;
  PORT
   LAYER M4 ;
   RECT 302.208000 627.276000 302.400000 627.300000 ;
  END
 END pi0[278]
 PIN pi0[279]
  DIRECTION OUTPUT ;
  USE SIGNAL ;
  PORT
   LAYER M4 ;
   RECT 302.208000 627.468000 302.400000 627.492000 ;
  END
 END pi0[279]
 PIN pi0[280]
  DIRECTION OUTPUT ;
  USE SIGNAL ;
  PORT
   LAYER M4 ;
   RECT 302.208000 627.660000 302.400000 627.684000 ;
  END
 END pi0[280]
 PIN pi0[281]
  DIRECTION OUTPUT ;
  USE SIGNAL ;
  PORT
   LAYER M4 ;
   RECT 302.208000 627.852000 302.400000 627.876000 ;
  END
 END pi0[281]
 PIN pi0[282]
  DIRECTION OUTPUT ;
  USE SIGNAL ;
  PORT
   LAYER M4 ;
   RECT 302.208000 628.044000 302.400000 628.068000 ;
  END
 END pi0[282]
 PIN pi0[283]
  DIRECTION OUTPUT ;
  USE SIGNAL ;
  PORT
   LAYER M4 ;
   RECT 302.208000 628.236000 302.400000 628.260000 ;
  END
 END pi0[283]
 PIN pi0[284]
  DIRECTION OUTPUT ;
  USE SIGNAL ;
  PORT
   LAYER M4 ;
   RECT 302.208000 628.428000 302.400000 628.452000 ;
  END
 END pi0[284]
 PIN pi0[285]
  DIRECTION OUTPUT ;
  USE SIGNAL ;
  PORT
   LAYER M4 ;
   RECT 302.208000 628.620000 302.400000 628.644000 ;
  END
 END pi0[285]
 PIN pi0[286]
  DIRECTION OUTPUT ;
  USE SIGNAL ;
  PORT
   LAYER M4 ;
   RECT 302.208000 628.812000 302.400000 628.836000 ;
  END
 END pi0[286]
 PIN pi0[287]
  DIRECTION OUTPUT ;
  USE SIGNAL ;
  PORT
   LAYER M4 ;
   RECT 302.208000 629.004000 302.400000 629.028000 ;
  END
 END pi0[287]
 PIN pi0[288]
  DIRECTION OUTPUT ;
  USE SIGNAL ;
  PORT
   LAYER M4 ;
   RECT 302.208000 629.196000 302.400000 629.220000 ;
  END
 END pi0[288]
 PIN fh0[0]
  DIRECTION OUTPUT ;
  USE SIGNAL ;
  PORT
   LAYER M4 ;
   RECT 302.208000 629.388000 302.400000 629.412000 ;
  END
 END fh0[0]
 PIN fh0[1]
  DIRECTION OUTPUT ;
  USE SIGNAL ;
  PORT
   LAYER M4 ;
   RECT 302.208000 629.580000 302.400000 629.604000 ;
  END
 END fh0[1]
 PIN fh0[2]
  DIRECTION OUTPUT ;
  USE SIGNAL ;
  PORT
   LAYER M4 ;
   RECT 302.208000 629.772000 302.400000 629.796000 ;
  END
 END fh0[2]
 PIN fh0[3]
  DIRECTION OUTPUT ;
  USE SIGNAL ;
  PORT
   LAYER M4 ;
   RECT 302.208000 629.964000 302.400000 629.988000 ;
  END
 END fh0[3]
 PIN rh0[0]
  DIRECTION OUTPUT ;
  USE SIGNAL ;
  PORT
   LAYER M4 ;
   RECT 302.208000 630.156000 302.400000 630.180000 ;
  END
 END rh0[0]
 PIN rh0[1]
  DIRECTION OUTPUT ;
  USE SIGNAL ;
  PORT
   LAYER M4 ;
   RECT 302.208000 630.348000 302.400000 630.372000 ;
  END
 END rh0[1]
 PIN rh0[2]
  DIRECTION OUTPUT ;
  USE SIGNAL ;
  PORT
   LAYER M4 ;
   RECT 302.208000 630.540000 302.400000 630.564000 ;
  END
 END rh0[2]
 PIN rh0[3]
  DIRECTION OUTPUT ;
  USE SIGNAL ;
  PORT
   LAYER M4 ;
   RECT 302.208000 630.732000 302.400000 630.756000 ;
  END
 END rh0[3]
 PIN po1[0]
  DIRECTION INPUT ;
  USE SIGNAL ;
  PORT
   LAYER M4 ;
   RECT 302.208000 630.924000 302.400000 630.948000 ;
  END
 END po1[0]
 PIN po1[1]
  DIRECTION INPUT ;
  USE SIGNAL ;
  PORT
   LAYER M4 ;
   RECT 302.208000 631.116000 302.400000 631.140000 ;
  END
 END po1[1]
 PIN po1[2]
  DIRECTION INPUT ;
  USE SIGNAL ;
  PORT
   LAYER M4 ;
   RECT 302.208000 631.308000 302.400000 631.332000 ;
  END
 END po1[2]
 PIN po1[3]
  DIRECTION INPUT ;
  USE SIGNAL ;
  PORT
   LAYER M4 ;
   RECT 302.208000 631.500000 302.400000 631.524000 ;
  END
 END po1[3]
 PIN po1[4]
  DIRECTION INPUT ;
  USE SIGNAL ;
  PORT
   LAYER M4 ;
   RECT 302.208000 631.692000 302.400000 631.716000 ;
  END
 END po1[4]
 PIN po1[5]
  DIRECTION INPUT ;
  USE SIGNAL ;
  PORT
   LAYER M4 ;
   RECT 302.208000 631.884000 302.400000 631.908000 ;
  END
 END po1[5]
 PIN po1[6]
  DIRECTION INPUT ;
  USE SIGNAL ;
  PORT
   LAYER M4 ;
   RECT 302.208000 632.076000 302.400000 632.100000 ;
  END
 END po1[6]
 PIN po1[7]
  DIRECTION INPUT ;
  USE SIGNAL ;
  PORT
   LAYER M4 ;
   RECT 302.208000 632.268000 302.400000 632.292000 ;
  END
 END po1[7]
 PIN po1[8]
  DIRECTION INPUT ;
  USE SIGNAL ;
  PORT
   LAYER M4 ;
   RECT 302.208000 632.460000 302.400000 632.484000 ;
  END
 END po1[8]
 PIN po1[9]
  DIRECTION INPUT ;
  USE SIGNAL ;
  PORT
   LAYER M4 ;
   RECT 302.208000 632.652000 302.400000 632.676000 ;
  END
 END po1[9]
 PIN po1[10]
  DIRECTION INPUT ;
  USE SIGNAL ;
  PORT
   LAYER M4 ;
   RECT 302.208000 632.844000 302.400000 632.868000 ;
  END
 END po1[10]
 PIN po1[11]
  DIRECTION INPUT ;
  USE SIGNAL ;
  PORT
   LAYER M4 ;
   RECT 302.208000 633.036000 302.400000 633.060000 ;
  END
 END po1[11]
 PIN po1[12]
  DIRECTION INPUT ;
  USE SIGNAL ;
  PORT
   LAYER M4 ;
   RECT 302.208000 633.228000 302.400000 633.252000 ;
  END
 END po1[12]
 PIN po1[13]
  DIRECTION INPUT ;
  USE SIGNAL ;
  PORT
   LAYER M4 ;
   RECT 302.208000 633.420000 302.400000 633.444000 ;
  END
 END po1[13]
 PIN po1[14]
  DIRECTION INPUT ;
  USE SIGNAL ;
  PORT
   LAYER M4 ;
   RECT 302.208000 633.612000 302.400000 633.636000 ;
  END
 END po1[14]
 PIN po1[15]
  DIRECTION INPUT ;
  USE SIGNAL ;
  PORT
   LAYER M4 ;
   RECT 302.208000 633.804000 302.400000 633.828000 ;
  END
 END po1[15]
 PIN po1[16]
  DIRECTION INPUT ;
  USE SIGNAL ;
  PORT
   LAYER M4 ;
   RECT 302.208000 633.996000 302.400000 634.020000 ;
  END
 END po1[16]
 PIN po1[17]
  DIRECTION INPUT ;
  USE SIGNAL ;
  PORT
   LAYER M4 ;
   RECT 302.208000 634.188000 302.400000 634.212000 ;
  END
 END po1[17]
 PIN po1[18]
  DIRECTION INPUT ;
  USE SIGNAL ;
  PORT
   LAYER M4 ;
   RECT 302.208000 634.380000 302.400000 634.404000 ;
  END
 END po1[18]
 PIN po1[19]
  DIRECTION INPUT ;
  USE SIGNAL ;
  PORT
   LAYER M4 ;
   RECT 302.208000 634.572000 302.400000 634.596000 ;
  END
 END po1[19]
 PIN po1[20]
  DIRECTION INPUT ;
  USE SIGNAL ;
  PORT
   LAYER M4 ;
   RECT 302.208000 634.764000 302.400000 634.788000 ;
  END
 END po1[20]
 PIN po1[21]
  DIRECTION INPUT ;
  USE SIGNAL ;
  PORT
   LAYER M4 ;
   RECT 302.208000 634.956000 302.400000 634.980000 ;
  END
 END po1[21]
 PIN po1[22]
  DIRECTION INPUT ;
  USE SIGNAL ;
  PORT
   LAYER M4 ;
   RECT 302.208000 635.148000 302.400000 635.172000 ;
  END
 END po1[22]
 PIN po1[23]
  DIRECTION INPUT ;
  USE SIGNAL ;
  PORT
   LAYER M4 ;
   RECT 302.208000 635.340000 302.400000 635.364000 ;
  END
 END po1[23]
 PIN po1[24]
  DIRECTION INPUT ;
  USE SIGNAL ;
  PORT
   LAYER M4 ;
   RECT 302.208000 635.532000 302.400000 635.556000 ;
  END
 END po1[24]
 PIN po1[25]
  DIRECTION INPUT ;
  USE SIGNAL ;
  PORT
   LAYER M4 ;
   RECT 302.208000 635.724000 302.400000 635.748000 ;
  END
 END po1[25]
 PIN po1[26]
  DIRECTION INPUT ;
  USE SIGNAL ;
  PORT
   LAYER M4 ;
   RECT 302.208000 635.916000 302.400000 635.940000 ;
  END
 END po1[26]
 PIN po1[27]
  DIRECTION INPUT ;
  USE SIGNAL ;
  PORT
   LAYER M4 ;
   RECT 302.208000 636.108000 302.400000 636.132000 ;
  END
 END po1[27]
 PIN po1[28]
  DIRECTION INPUT ;
  USE SIGNAL ;
  PORT
   LAYER M4 ;
   RECT 302.208000 636.300000 302.400000 636.324000 ;
  END
 END po1[28]
 PIN po1[29]
  DIRECTION INPUT ;
  USE SIGNAL ;
  PORT
   LAYER M4 ;
   RECT 302.208000 636.492000 302.400000 636.516000 ;
  END
 END po1[29]
 PIN po1[30]
  DIRECTION INPUT ;
  USE SIGNAL ;
  PORT
   LAYER M4 ;
   RECT 302.208000 636.684000 302.400000 636.708000 ;
  END
 END po1[30]
 PIN po1[31]
  DIRECTION INPUT ;
  USE SIGNAL ;
  PORT
   LAYER M4 ;
   RECT 302.208000 636.876000 302.400000 636.900000 ;
  END
 END po1[31]
 PIN po1[32]
  DIRECTION INPUT ;
  USE SIGNAL ;
  PORT
   LAYER M4 ;
   RECT 302.208000 637.068000 302.400000 637.092000 ;
  END
 END po1[32]
 PIN po1[33]
  DIRECTION INPUT ;
  USE SIGNAL ;
  PORT
   LAYER M4 ;
   RECT 302.208000 637.260000 302.400000 637.284000 ;
  END
 END po1[33]
 PIN po1[34]
  DIRECTION INPUT ;
  USE SIGNAL ;
  PORT
   LAYER M4 ;
   RECT 302.208000 637.452000 302.400000 637.476000 ;
  END
 END po1[34]
 PIN po1[35]
  DIRECTION INPUT ;
  USE SIGNAL ;
  PORT
   LAYER M4 ;
   RECT 302.208000 637.644000 302.400000 637.668000 ;
  END
 END po1[35]
 PIN po1[36]
  DIRECTION INPUT ;
  USE SIGNAL ;
  PORT
   LAYER M4 ;
   RECT 302.208000 637.836000 302.400000 637.860000 ;
  END
 END po1[36]
 PIN po1[37]
  DIRECTION INPUT ;
  USE SIGNAL ;
  PORT
   LAYER M4 ;
   RECT 302.208000 638.028000 302.400000 638.052000 ;
  END
 END po1[37]
 PIN po1[38]
  DIRECTION INPUT ;
  USE SIGNAL ;
  PORT
   LAYER M4 ;
   RECT 302.208000 638.220000 302.400000 638.244000 ;
  END
 END po1[38]
 PIN po1[39]
  DIRECTION INPUT ;
  USE SIGNAL ;
  PORT
   LAYER M4 ;
   RECT 302.208000 638.412000 302.400000 638.436000 ;
  END
 END po1[39]
 PIN po1[40]
  DIRECTION INPUT ;
  USE SIGNAL ;
  PORT
   LAYER M4 ;
   RECT 302.208000 638.604000 302.400000 638.628000 ;
  END
 END po1[40]
 PIN po1[41]
  DIRECTION INPUT ;
  USE SIGNAL ;
  PORT
   LAYER M4 ;
   RECT 302.208000 638.796000 302.400000 638.820000 ;
  END
 END po1[41]
 PIN po1[42]
  DIRECTION INPUT ;
  USE SIGNAL ;
  PORT
   LAYER M4 ;
   RECT 302.208000 638.988000 302.400000 639.012000 ;
  END
 END po1[42]
 PIN po1[43]
  DIRECTION INPUT ;
  USE SIGNAL ;
  PORT
   LAYER M4 ;
   RECT 302.208000 639.180000 302.400000 639.204000 ;
  END
 END po1[43]
 PIN po1[44]
  DIRECTION INPUT ;
  USE SIGNAL ;
  PORT
   LAYER M4 ;
   RECT 302.208000 639.372000 302.400000 639.396000 ;
  END
 END po1[44]
 PIN po1[45]
  DIRECTION INPUT ;
  USE SIGNAL ;
  PORT
   LAYER M4 ;
   RECT 302.208000 639.564000 302.400000 639.588000 ;
  END
 END po1[45]
 PIN po1[46]
  DIRECTION INPUT ;
  USE SIGNAL ;
  PORT
   LAYER M4 ;
   RECT 302.208000 639.756000 302.400000 639.780000 ;
  END
 END po1[46]
 PIN po1[47]
  DIRECTION INPUT ;
  USE SIGNAL ;
  PORT
   LAYER M4 ;
   RECT 302.208000 639.948000 302.400000 639.972000 ;
  END
 END po1[47]
 PIN po1[48]
  DIRECTION INPUT ;
  USE SIGNAL ;
  PORT
   LAYER M4 ;
   RECT 302.208000 640.140000 302.400000 640.164000 ;
  END
 END po1[48]
 PIN po1[49]
  DIRECTION INPUT ;
  USE SIGNAL ;
  PORT
   LAYER M4 ;
   RECT 302.208000 640.332000 302.400000 640.356000 ;
  END
 END po1[49]
 PIN po1[50]
  DIRECTION INPUT ;
  USE SIGNAL ;
  PORT
   LAYER M4 ;
   RECT 302.208000 640.524000 302.400000 640.548000 ;
  END
 END po1[50]
 PIN po1[51]
  DIRECTION INPUT ;
  USE SIGNAL ;
  PORT
   LAYER M4 ;
   RECT 302.208000 640.716000 302.400000 640.740000 ;
  END
 END po1[51]
 PIN po1[52]
  DIRECTION INPUT ;
  USE SIGNAL ;
  PORT
   LAYER M4 ;
   RECT 302.208000 640.908000 302.400000 640.932000 ;
  END
 END po1[52]
 PIN po1[53]
  DIRECTION INPUT ;
  USE SIGNAL ;
  PORT
   LAYER M4 ;
   RECT 302.208000 641.100000 302.400000 641.124000 ;
  END
 END po1[53]
 PIN po1[54]
  DIRECTION INPUT ;
  USE SIGNAL ;
  PORT
   LAYER M4 ;
   RECT 302.208000 641.292000 302.400000 641.316000 ;
  END
 END po1[54]
 PIN po1[55]
  DIRECTION INPUT ;
  USE SIGNAL ;
  PORT
   LAYER M4 ;
   RECT 302.208000 641.484000 302.400000 641.508000 ;
  END
 END po1[55]
 PIN po1[56]
  DIRECTION INPUT ;
  USE SIGNAL ;
  PORT
   LAYER M4 ;
   RECT 302.208000 641.676000 302.400000 641.700000 ;
  END
 END po1[56]
 PIN po1[57]
  DIRECTION INPUT ;
  USE SIGNAL ;
  PORT
   LAYER M4 ;
   RECT 302.208000 641.868000 302.400000 641.892000 ;
  END
 END po1[57]
 PIN po1[58]
  DIRECTION INPUT ;
  USE SIGNAL ;
  PORT
   LAYER M4 ;
   RECT 302.208000 642.060000 302.400000 642.084000 ;
  END
 END po1[58]
 PIN po1[59]
  DIRECTION INPUT ;
  USE SIGNAL ;
  PORT
   LAYER M4 ;
   RECT 302.208000 642.252000 302.400000 642.276000 ;
  END
 END po1[59]
 PIN po1[60]
  DIRECTION INPUT ;
  USE SIGNAL ;
  PORT
   LAYER M4 ;
   RECT 302.208000 642.444000 302.400000 642.468000 ;
  END
 END po1[60]
 PIN po1[61]
  DIRECTION INPUT ;
  USE SIGNAL ;
  PORT
   LAYER M4 ;
   RECT 302.208000 642.636000 302.400000 642.660000 ;
  END
 END po1[61]
 PIN po1[62]
  DIRECTION INPUT ;
  USE SIGNAL ;
  PORT
   LAYER M4 ;
   RECT 302.208000 642.828000 302.400000 642.852000 ;
  END
 END po1[62]
 PIN po1[63]
  DIRECTION INPUT ;
  USE SIGNAL ;
  PORT
   LAYER M4 ;
   RECT 302.208000 643.020000 302.400000 643.044000 ;
  END
 END po1[63]
 PIN po1[64]
  DIRECTION INPUT ;
  USE SIGNAL ;
  PORT
   LAYER M4 ;
   RECT 302.208000 643.212000 302.400000 643.236000 ;
  END
 END po1[64]
 PIN po1[65]
  DIRECTION INPUT ;
  USE SIGNAL ;
  PORT
   LAYER M4 ;
   RECT 302.208000 643.404000 302.400000 643.428000 ;
  END
 END po1[65]
 PIN po1[66]
  DIRECTION INPUT ;
  USE SIGNAL ;
  PORT
   LAYER M4 ;
   RECT 302.208000 643.596000 302.400000 643.620000 ;
  END
 END po1[66]
 PIN po1[67]
  DIRECTION INPUT ;
  USE SIGNAL ;
  PORT
   LAYER M4 ;
   RECT 302.208000 643.788000 302.400000 643.812000 ;
  END
 END po1[67]
 PIN po1[68]
  DIRECTION INPUT ;
  USE SIGNAL ;
  PORT
   LAYER M4 ;
   RECT 302.208000 643.980000 302.400000 644.004000 ;
  END
 END po1[68]
 PIN po1[69]
  DIRECTION INPUT ;
  USE SIGNAL ;
  PORT
   LAYER M4 ;
   RECT 302.208000 644.172000 302.400000 644.196000 ;
  END
 END po1[69]
 PIN po1[70]
  DIRECTION INPUT ;
  USE SIGNAL ;
  PORT
   LAYER M4 ;
   RECT 302.208000 644.364000 302.400000 644.388000 ;
  END
 END po1[70]
 PIN po1[71]
  DIRECTION INPUT ;
  USE SIGNAL ;
  PORT
   LAYER M4 ;
   RECT 302.208000 644.556000 302.400000 644.580000 ;
  END
 END po1[71]
 PIN po1[72]
  DIRECTION INPUT ;
  USE SIGNAL ;
  PORT
   LAYER M4 ;
   RECT 302.208000 644.748000 302.400000 644.772000 ;
  END
 END po1[72]
 PIN po1[73]
  DIRECTION INPUT ;
  USE SIGNAL ;
  PORT
   LAYER M4 ;
   RECT 302.208000 644.940000 302.400000 644.964000 ;
  END
 END po1[73]
 PIN po1[74]
  DIRECTION INPUT ;
  USE SIGNAL ;
  PORT
   LAYER M4 ;
   RECT 302.208000 645.132000 302.400000 645.156000 ;
  END
 END po1[74]
 PIN po1[75]
  DIRECTION INPUT ;
  USE SIGNAL ;
  PORT
   LAYER M4 ;
   RECT 302.208000 645.324000 302.400000 645.348000 ;
  END
 END po1[75]
 PIN po1[76]
  DIRECTION INPUT ;
  USE SIGNAL ;
  PORT
   LAYER M4 ;
   RECT 302.208000 645.516000 302.400000 645.540000 ;
  END
 END po1[76]
 PIN po1[77]
  DIRECTION INPUT ;
  USE SIGNAL ;
  PORT
   LAYER M4 ;
   RECT 302.208000 645.708000 302.400000 645.732000 ;
  END
 END po1[77]
 PIN po1[78]
  DIRECTION INPUT ;
  USE SIGNAL ;
  PORT
   LAYER M4 ;
   RECT 302.208000 645.900000 302.400000 645.924000 ;
  END
 END po1[78]
 PIN po1[79]
  DIRECTION INPUT ;
  USE SIGNAL ;
  PORT
   LAYER M4 ;
   RECT 302.208000 646.092000 302.400000 646.116000 ;
  END
 END po1[79]
 PIN po1[80]
  DIRECTION INPUT ;
  USE SIGNAL ;
  PORT
   LAYER M4 ;
   RECT 302.208000 646.284000 302.400000 646.308000 ;
  END
 END po1[80]
 PIN po1[81]
  DIRECTION INPUT ;
  USE SIGNAL ;
  PORT
   LAYER M4 ;
   RECT 302.208000 646.476000 302.400000 646.500000 ;
  END
 END po1[81]
 PIN po1[82]
  DIRECTION INPUT ;
  USE SIGNAL ;
  PORT
   LAYER M4 ;
   RECT 302.208000 646.668000 302.400000 646.692000 ;
  END
 END po1[82]
 PIN po1[83]
  DIRECTION INPUT ;
  USE SIGNAL ;
  PORT
   LAYER M4 ;
   RECT 302.208000 646.860000 302.400000 646.884000 ;
  END
 END po1[83]
 PIN po1[84]
  DIRECTION INPUT ;
  USE SIGNAL ;
  PORT
   LAYER M4 ;
   RECT 302.208000 647.052000 302.400000 647.076000 ;
  END
 END po1[84]
 PIN po1[85]
  DIRECTION INPUT ;
  USE SIGNAL ;
  PORT
   LAYER M4 ;
   RECT 302.208000 647.244000 302.400000 647.268000 ;
  END
 END po1[85]
 PIN po1[86]
  DIRECTION INPUT ;
  USE SIGNAL ;
  PORT
   LAYER M4 ;
   RECT 302.208000 647.436000 302.400000 647.460000 ;
  END
 END po1[86]
 PIN po1[87]
  DIRECTION INPUT ;
  USE SIGNAL ;
  PORT
   LAYER M4 ;
   RECT 302.208000 647.628000 302.400000 647.652000 ;
  END
 END po1[87]
 PIN po1[88]
  DIRECTION INPUT ;
  USE SIGNAL ;
  PORT
   LAYER M4 ;
   RECT 302.208000 647.820000 302.400000 647.844000 ;
  END
 END po1[88]
 PIN po1[89]
  DIRECTION INPUT ;
  USE SIGNAL ;
  PORT
   LAYER M4 ;
   RECT 302.208000 648.012000 302.400000 648.036000 ;
  END
 END po1[89]
 PIN po1[90]
  DIRECTION INPUT ;
  USE SIGNAL ;
  PORT
   LAYER M4 ;
   RECT 302.208000 648.204000 302.400000 648.228000 ;
  END
 END po1[90]
 PIN po1[91]
  DIRECTION INPUT ;
  USE SIGNAL ;
  PORT
   LAYER M4 ;
   RECT 302.208000 648.396000 302.400000 648.420000 ;
  END
 END po1[91]
 PIN po1[92]
  DIRECTION INPUT ;
  USE SIGNAL ;
  PORT
   LAYER M4 ;
   RECT 302.208000 648.588000 302.400000 648.612000 ;
  END
 END po1[92]
 PIN po1[93]
  DIRECTION INPUT ;
  USE SIGNAL ;
  PORT
   LAYER M4 ;
   RECT 302.208000 648.780000 302.400000 648.804000 ;
  END
 END po1[93]
 PIN po1[94]
  DIRECTION INPUT ;
  USE SIGNAL ;
  PORT
   LAYER M4 ;
   RECT 302.208000 648.972000 302.400000 648.996000 ;
  END
 END po1[94]
 PIN po1[95]
  DIRECTION INPUT ;
  USE SIGNAL ;
  PORT
   LAYER M4 ;
   RECT 302.208000 649.164000 302.400000 649.188000 ;
  END
 END po1[95]
 PIN po1[96]
  DIRECTION INPUT ;
  USE SIGNAL ;
  PORT
   LAYER M4 ;
   RECT 302.208000 649.356000 302.400000 649.380000 ;
  END
 END po1[96]
 PIN po1[97]
  DIRECTION INPUT ;
  USE SIGNAL ;
  PORT
   LAYER M4 ;
   RECT 302.208000 649.548000 302.400000 649.572000 ;
  END
 END po1[97]
 PIN po1[98]
  DIRECTION INPUT ;
  USE SIGNAL ;
  PORT
   LAYER M4 ;
   RECT 302.208000 649.740000 302.400000 649.764000 ;
  END
 END po1[98]
 PIN po1[99]
  DIRECTION INPUT ;
  USE SIGNAL ;
  PORT
   LAYER M4 ;
   RECT 302.208000 649.932000 302.400000 649.956000 ;
  END
 END po1[99]
 PIN po1[100]
  DIRECTION INPUT ;
  USE SIGNAL ;
  PORT
   LAYER M4 ;
   RECT 302.208000 650.124000 302.400000 650.148000 ;
  END
 END po1[100]
 PIN po1[101]
  DIRECTION INPUT ;
  USE SIGNAL ;
  PORT
   LAYER M4 ;
   RECT 302.208000 650.316000 302.400000 650.340000 ;
  END
 END po1[101]
 PIN po1[102]
  DIRECTION INPUT ;
  USE SIGNAL ;
  PORT
   LAYER M4 ;
   RECT 302.208000 650.508000 302.400000 650.532000 ;
  END
 END po1[102]
 PIN po1[103]
  DIRECTION INPUT ;
  USE SIGNAL ;
  PORT
   LAYER M4 ;
   RECT 302.208000 650.700000 302.400000 650.724000 ;
  END
 END po1[103]
 PIN po1[104]
  DIRECTION INPUT ;
  USE SIGNAL ;
  PORT
   LAYER M4 ;
   RECT 302.208000 650.892000 302.400000 650.916000 ;
  END
 END po1[104]
 PIN po1[105]
  DIRECTION INPUT ;
  USE SIGNAL ;
  PORT
   LAYER M4 ;
   RECT 302.208000 651.084000 302.400000 651.108000 ;
  END
 END po1[105]
 PIN po1[106]
  DIRECTION INPUT ;
  USE SIGNAL ;
  PORT
   LAYER M4 ;
   RECT 302.208000 651.276000 302.400000 651.300000 ;
  END
 END po1[106]
 PIN po1[107]
  DIRECTION INPUT ;
  USE SIGNAL ;
  PORT
   LAYER M4 ;
   RECT 302.208000 651.468000 302.400000 651.492000 ;
  END
 END po1[107]
 PIN po1[108]
  DIRECTION INPUT ;
  USE SIGNAL ;
  PORT
   LAYER M4 ;
   RECT 302.208000 651.660000 302.400000 651.684000 ;
  END
 END po1[108]
 PIN po1[109]
  DIRECTION INPUT ;
  USE SIGNAL ;
  PORT
   LAYER M4 ;
   RECT 302.208000 651.852000 302.400000 651.876000 ;
  END
 END po1[109]
 PIN po1[110]
  DIRECTION INPUT ;
  USE SIGNAL ;
  PORT
   LAYER M4 ;
   RECT 302.208000 652.044000 302.400000 652.068000 ;
  END
 END po1[110]
 PIN po1[111]
  DIRECTION INPUT ;
  USE SIGNAL ;
  PORT
   LAYER M4 ;
   RECT 302.208000 652.236000 302.400000 652.260000 ;
  END
 END po1[111]
 PIN po1[112]
  DIRECTION INPUT ;
  USE SIGNAL ;
  PORT
   LAYER M4 ;
   RECT 302.208000 652.428000 302.400000 652.452000 ;
  END
 END po1[112]
 PIN po1[113]
  DIRECTION INPUT ;
  USE SIGNAL ;
  PORT
   LAYER M4 ;
   RECT 302.208000 652.620000 302.400000 652.644000 ;
  END
 END po1[113]
 PIN po1[114]
  DIRECTION INPUT ;
  USE SIGNAL ;
  PORT
   LAYER M4 ;
   RECT 302.208000 652.812000 302.400000 652.836000 ;
  END
 END po1[114]
 PIN po1[115]
  DIRECTION INPUT ;
  USE SIGNAL ;
  PORT
   LAYER M4 ;
   RECT 302.208000 653.004000 302.400000 653.028000 ;
  END
 END po1[115]
 PIN po1[116]
  DIRECTION INPUT ;
  USE SIGNAL ;
  PORT
   LAYER M4 ;
   RECT 302.208000 653.196000 302.400000 653.220000 ;
  END
 END po1[116]
 PIN po1[117]
  DIRECTION INPUT ;
  USE SIGNAL ;
  PORT
   LAYER M4 ;
   RECT 302.208000 653.388000 302.400000 653.412000 ;
  END
 END po1[117]
 PIN po1[118]
  DIRECTION INPUT ;
  USE SIGNAL ;
  PORT
   LAYER M4 ;
   RECT 302.208000 653.580000 302.400000 653.604000 ;
  END
 END po1[118]
 PIN po1[119]
  DIRECTION INPUT ;
  USE SIGNAL ;
  PORT
   LAYER M4 ;
   RECT 302.208000 653.772000 302.400000 653.796000 ;
  END
 END po1[119]
 PIN po1[120]
  DIRECTION INPUT ;
  USE SIGNAL ;
  PORT
   LAYER M4 ;
   RECT 302.208000 653.964000 302.400000 653.988000 ;
  END
 END po1[120]
 PIN po1[121]
  DIRECTION INPUT ;
  USE SIGNAL ;
  PORT
   LAYER M4 ;
   RECT 302.208000 654.156000 302.400000 654.180000 ;
  END
 END po1[121]
 PIN po1[122]
  DIRECTION INPUT ;
  USE SIGNAL ;
  PORT
   LAYER M4 ;
   RECT 302.208000 654.348000 302.400000 654.372000 ;
  END
 END po1[122]
 PIN po1[123]
  DIRECTION INPUT ;
  USE SIGNAL ;
  PORT
   LAYER M4 ;
   RECT 302.208000 654.540000 302.400000 654.564000 ;
  END
 END po1[123]
 PIN po1[124]
  DIRECTION INPUT ;
  USE SIGNAL ;
  PORT
   LAYER M4 ;
   RECT 302.208000 654.732000 302.400000 654.756000 ;
  END
 END po1[124]
 PIN po1[125]
  DIRECTION INPUT ;
  USE SIGNAL ;
  PORT
   LAYER M4 ;
   RECT 302.208000 654.924000 302.400000 654.948000 ;
  END
 END po1[125]
 PIN po1[126]
  DIRECTION INPUT ;
  USE SIGNAL ;
  PORT
   LAYER M4 ;
   RECT 302.208000 655.116000 302.400000 655.140000 ;
  END
 END po1[126]
 PIN po1[127]
  DIRECTION INPUT ;
  USE SIGNAL ;
  PORT
   LAYER M4 ;
   RECT 302.208000 655.308000 302.400000 655.332000 ;
  END
 END po1[127]
 PIN po1[128]
  DIRECTION INPUT ;
  USE SIGNAL ;
  PORT
   LAYER M4 ;
   RECT 302.208000 655.500000 302.400000 655.524000 ;
  END
 END po1[128]
 PIN po1[129]
  DIRECTION INPUT ;
  USE SIGNAL ;
  PORT
   LAYER M4 ;
   RECT 302.208000 655.692000 302.400000 655.716000 ;
  END
 END po1[129]
 PIN po1[130]
  DIRECTION INPUT ;
  USE SIGNAL ;
  PORT
   LAYER M4 ;
   RECT 302.208000 655.884000 302.400000 655.908000 ;
  END
 END po1[130]
 PIN po1[131]
  DIRECTION INPUT ;
  USE SIGNAL ;
  PORT
   LAYER M4 ;
   RECT 302.208000 656.076000 302.400000 656.100000 ;
  END
 END po1[131]
 PIN po1[132]
  DIRECTION INPUT ;
  USE SIGNAL ;
  PORT
   LAYER M4 ;
   RECT 302.208000 656.268000 302.400000 656.292000 ;
  END
 END po1[132]
 PIN po1[133]
  DIRECTION INPUT ;
  USE SIGNAL ;
  PORT
   LAYER M4 ;
   RECT 302.208000 656.460000 302.400000 656.484000 ;
  END
 END po1[133]
 PIN po1[134]
  DIRECTION INPUT ;
  USE SIGNAL ;
  PORT
   LAYER M4 ;
   RECT 302.208000 656.652000 302.400000 656.676000 ;
  END
 END po1[134]
 PIN po1[135]
  DIRECTION INPUT ;
  USE SIGNAL ;
  PORT
   LAYER M4 ;
   RECT 302.208000 656.844000 302.400000 656.868000 ;
  END
 END po1[135]
 PIN po1[136]
  DIRECTION INPUT ;
  USE SIGNAL ;
  PORT
   LAYER M4 ;
   RECT 302.208000 657.036000 302.400000 657.060000 ;
  END
 END po1[136]
 PIN po1[137]
  DIRECTION INPUT ;
  USE SIGNAL ;
  PORT
   LAYER M4 ;
   RECT 302.208000 657.228000 302.400000 657.252000 ;
  END
 END po1[137]
 PIN po1[138]
  DIRECTION INPUT ;
  USE SIGNAL ;
  PORT
   LAYER M4 ;
   RECT 302.208000 657.420000 302.400000 657.444000 ;
  END
 END po1[138]
 PIN po1[139]
  DIRECTION INPUT ;
  USE SIGNAL ;
  PORT
   LAYER M4 ;
   RECT 302.208000 657.612000 302.400000 657.636000 ;
  END
 END po1[139]
 PIN po1[140]
  DIRECTION INPUT ;
  USE SIGNAL ;
  PORT
   LAYER M4 ;
   RECT 302.208000 657.804000 302.400000 657.828000 ;
  END
 END po1[140]
 PIN po1[141]
  DIRECTION INPUT ;
  USE SIGNAL ;
  PORT
   LAYER M4 ;
   RECT 302.208000 657.996000 302.400000 658.020000 ;
  END
 END po1[141]
 PIN po1[142]
  DIRECTION INPUT ;
  USE SIGNAL ;
  PORT
   LAYER M4 ;
   RECT 302.208000 658.188000 302.400000 658.212000 ;
  END
 END po1[142]
 PIN po1[143]
  DIRECTION INPUT ;
  USE SIGNAL ;
  PORT
   LAYER M4 ;
   RECT 302.208000 658.380000 302.400000 658.404000 ;
  END
 END po1[143]
 PIN po1[144]
  DIRECTION INPUT ;
  USE SIGNAL ;
  PORT
   LAYER M4 ;
   RECT 302.208000 658.572000 302.400000 658.596000 ;
  END
 END po1[144]
 PIN po1[145]
  DIRECTION INPUT ;
  USE SIGNAL ;
  PORT
   LAYER M4 ;
   RECT 302.208000 658.764000 302.400000 658.788000 ;
  END
 END po1[145]
 PIN po1[146]
  DIRECTION INPUT ;
  USE SIGNAL ;
  PORT
   LAYER M4 ;
   RECT 302.208000 658.956000 302.400000 658.980000 ;
  END
 END po1[146]
 PIN po1[147]
  DIRECTION INPUT ;
  USE SIGNAL ;
  PORT
   LAYER M4 ;
   RECT 302.208000 659.148000 302.400000 659.172000 ;
  END
 END po1[147]
 PIN po1[148]
  DIRECTION INPUT ;
  USE SIGNAL ;
  PORT
   LAYER M4 ;
   RECT 302.208000 659.340000 302.400000 659.364000 ;
  END
 END po1[148]
 PIN po1[149]
  DIRECTION INPUT ;
  USE SIGNAL ;
  PORT
   LAYER M4 ;
   RECT 302.208000 659.532000 302.400000 659.556000 ;
  END
 END po1[149]
 PIN po1[150]
  DIRECTION INPUT ;
  USE SIGNAL ;
  PORT
   LAYER M4 ;
   RECT 302.208000 659.724000 302.400000 659.748000 ;
  END
 END po1[150]
 PIN po1[151]
  DIRECTION INPUT ;
  USE SIGNAL ;
  PORT
   LAYER M4 ;
   RECT 302.208000 659.916000 302.400000 659.940000 ;
  END
 END po1[151]
 PIN po1[152]
  DIRECTION INPUT ;
  USE SIGNAL ;
  PORT
   LAYER M4 ;
   RECT 302.208000 660.108000 302.400000 660.132000 ;
  END
 END po1[152]
 PIN po1[153]
  DIRECTION INPUT ;
  USE SIGNAL ;
  PORT
   LAYER M4 ;
   RECT 302.208000 660.300000 302.400000 660.324000 ;
  END
 END po1[153]
 PIN po1[154]
  DIRECTION INPUT ;
  USE SIGNAL ;
  PORT
   LAYER M4 ;
   RECT 302.208000 660.492000 302.400000 660.516000 ;
  END
 END po1[154]
 PIN po1[155]
  DIRECTION INPUT ;
  USE SIGNAL ;
  PORT
   LAYER M4 ;
   RECT 302.208000 660.684000 302.400000 660.708000 ;
  END
 END po1[155]
 PIN po1[156]
  DIRECTION INPUT ;
  USE SIGNAL ;
  PORT
   LAYER M4 ;
   RECT 302.208000 660.876000 302.400000 660.900000 ;
  END
 END po1[156]
 PIN po1[157]
  DIRECTION INPUT ;
  USE SIGNAL ;
  PORT
   LAYER M4 ;
   RECT 302.208000 661.068000 302.400000 661.092000 ;
  END
 END po1[157]
 PIN po1[158]
  DIRECTION INPUT ;
  USE SIGNAL ;
  PORT
   LAYER M4 ;
   RECT 302.208000 661.260000 302.400000 661.284000 ;
  END
 END po1[158]
 PIN po1[159]
  DIRECTION INPUT ;
  USE SIGNAL ;
  PORT
   LAYER M4 ;
   RECT 302.208000 661.452000 302.400000 661.476000 ;
  END
 END po1[159]
 PIN po1[160]
  DIRECTION INPUT ;
  USE SIGNAL ;
  PORT
   LAYER M4 ;
   RECT 302.208000 661.644000 302.400000 661.668000 ;
  END
 END po1[160]
 PIN po1[161]
  DIRECTION INPUT ;
  USE SIGNAL ;
  PORT
   LAYER M4 ;
   RECT 302.208000 661.836000 302.400000 661.860000 ;
  END
 END po1[161]
 PIN po1[162]
  DIRECTION INPUT ;
  USE SIGNAL ;
  PORT
   LAYER M4 ;
   RECT 302.208000 662.028000 302.400000 662.052000 ;
  END
 END po1[162]
 PIN po1[163]
  DIRECTION INPUT ;
  USE SIGNAL ;
  PORT
   LAYER M4 ;
   RECT 302.208000 662.220000 302.400000 662.244000 ;
  END
 END po1[163]
 PIN po1[164]
  DIRECTION INPUT ;
  USE SIGNAL ;
  PORT
   LAYER M4 ;
   RECT 302.208000 662.412000 302.400000 662.436000 ;
  END
 END po1[164]
 PIN po1[165]
  DIRECTION INPUT ;
  USE SIGNAL ;
  PORT
   LAYER M4 ;
   RECT 302.208000 662.604000 302.400000 662.628000 ;
  END
 END po1[165]
 PIN po1[166]
  DIRECTION INPUT ;
  USE SIGNAL ;
  PORT
   LAYER M4 ;
   RECT 302.208000 662.796000 302.400000 662.820000 ;
  END
 END po1[166]
 PIN po1[167]
  DIRECTION INPUT ;
  USE SIGNAL ;
  PORT
   LAYER M4 ;
   RECT 302.208000 662.988000 302.400000 663.012000 ;
  END
 END po1[167]
 PIN po1[168]
  DIRECTION INPUT ;
  USE SIGNAL ;
  PORT
   LAYER M4 ;
   RECT 302.208000 663.180000 302.400000 663.204000 ;
  END
 END po1[168]
 PIN po1[169]
  DIRECTION INPUT ;
  USE SIGNAL ;
  PORT
   LAYER M4 ;
   RECT 302.208000 663.372000 302.400000 663.396000 ;
  END
 END po1[169]
 PIN po1[170]
  DIRECTION INPUT ;
  USE SIGNAL ;
  PORT
   LAYER M4 ;
   RECT 302.208000 663.564000 302.400000 663.588000 ;
  END
 END po1[170]
 PIN po1[171]
  DIRECTION INPUT ;
  USE SIGNAL ;
  PORT
   LAYER M4 ;
   RECT 302.208000 663.756000 302.400000 663.780000 ;
  END
 END po1[171]
 PIN po1[172]
  DIRECTION INPUT ;
  USE SIGNAL ;
  PORT
   LAYER M4 ;
   RECT 302.208000 663.948000 302.400000 663.972000 ;
  END
 END po1[172]
 PIN po1[173]
  DIRECTION INPUT ;
  USE SIGNAL ;
  PORT
   LAYER M4 ;
   RECT 302.208000 664.140000 302.400000 664.164000 ;
  END
 END po1[173]
 PIN po1[174]
  DIRECTION INPUT ;
  USE SIGNAL ;
  PORT
   LAYER M4 ;
   RECT 302.208000 664.332000 302.400000 664.356000 ;
  END
 END po1[174]
 PIN po1[175]
  DIRECTION INPUT ;
  USE SIGNAL ;
  PORT
   LAYER M4 ;
   RECT 302.208000 664.524000 302.400000 664.548000 ;
  END
 END po1[175]
 PIN po1[176]
  DIRECTION INPUT ;
  USE SIGNAL ;
  PORT
   LAYER M4 ;
   RECT 302.208000 664.716000 302.400000 664.740000 ;
  END
 END po1[176]
 PIN po1[177]
  DIRECTION INPUT ;
  USE SIGNAL ;
  PORT
   LAYER M4 ;
   RECT 302.208000 664.908000 302.400000 664.932000 ;
  END
 END po1[177]
 PIN po1[178]
  DIRECTION INPUT ;
  USE SIGNAL ;
  PORT
   LAYER M4 ;
   RECT 302.208000 665.100000 302.400000 665.124000 ;
  END
 END po1[178]
 PIN po1[179]
  DIRECTION INPUT ;
  USE SIGNAL ;
  PORT
   LAYER M4 ;
   RECT 302.208000 665.292000 302.400000 665.316000 ;
  END
 END po1[179]
 PIN po1[180]
  DIRECTION INPUT ;
  USE SIGNAL ;
  PORT
   LAYER M4 ;
   RECT 302.208000 665.484000 302.400000 665.508000 ;
  END
 END po1[180]
 PIN po1[181]
  DIRECTION INPUT ;
  USE SIGNAL ;
  PORT
   LAYER M4 ;
   RECT 302.208000 665.676000 302.400000 665.700000 ;
  END
 END po1[181]
 PIN po1[182]
  DIRECTION INPUT ;
  USE SIGNAL ;
  PORT
   LAYER M4 ;
   RECT 302.208000 665.868000 302.400000 665.892000 ;
  END
 END po1[182]
 PIN po1[183]
  DIRECTION INPUT ;
  USE SIGNAL ;
  PORT
   LAYER M4 ;
   RECT 302.208000 666.060000 302.400000 666.084000 ;
  END
 END po1[183]
 PIN po1[184]
  DIRECTION INPUT ;
  USE SIGNAL ;
  PORT
   LAYER M4 ;
   RECT 302.208000 666.252000 302.400000 666.276000 ;
  END
 END po1[184]
 PIN po1[185]
  DIRECTION INPUT ;
  USE SIGNAL ;
  PORT
   LAYER M4 ;
   RECT 302.208000 666.444000 302.400000 666.468000 ;
  END
 END po1[185]
 PIN po1[186]
  DIRECTION INPUT ;
  USE SIGNAL ;
  PORT
   LAYER M4 ;
   RECT 302.208000 666.636000 302.400000 666.660000 ;
  END
 END po1[186]
 PIN po1[187]
  DIRECTION INPUT ;
  USE SIGNAL ;
  PORT
   LAYER M4 ;
   RECT 302.208000 666.828000 302.400000 666.852000 ;
  END
 END po1[187]
 PIN po1[188]
  DIRECTION INPUT ;
  USE SIGNAL ;
  PORT
   LAYER M4 ;
   RECT 302.208000 667.020000 302.400000 667.044000 ;
  END
 END po1[188]
 PIN po1[189]
  DIRECTION INPUT ;
  USE SIGNAL ;
  PORT
   LAYER M4 ;
   RECT 302.208000 667.212000 302.400000 667.236000 ;
  END
 END po1[189]
 PIN po1[190]
  DIRECTION INPUT ;
  USE SIGNAL ;
  PORT
   LAYER M4 ;
   RECT 302.208000 667.404000 302.400000 667.428000 ;
  END
 END po1[190]
 PIN po1[191]
  DIRECTION INPUT ;
  USE SIGNAL ;
  PORT
   LAYER M4 ;
   RECT 302.208000 667.596000 302.400000 667.620000 ;
  END
 END po1[191]
 PIN po1[192]
  DIRECTION INPUT ;
  USE SIGNAL ;
  PORT
   LAYER M4 ;
   RECT 302.208000 667.788000 302.400000 667.812000 ;
  END
 END po1[192]
 PIN po1[193]
  DIRECTION INPUT ;
  USE SIGNAL ;
  PORT
   LAYER M4 ;
   RECT 302.208000 667.980000 302.400000 668.004000 ;
  END
 END po1[193]
 PIN po1[194]
  DIRECTION INPUT ;
  USE SIGNAL ;
  PORT
   LAYER M4 ;
   RECT 302.208000 668.172000 302.400000 668.196000 ;
  END
 END po1[194]
 PIN po1[195]
  DIRECTION INPUT ;
  USE SIGNAL ;
  PORT
   LAYER M4 ;
   RECT 302.208000 668.364000 302.400000 668.388000 ;
  END
 END po1[195]
 PIN po1[196]
  DIRECTION INPUT ;
  USE SIGNAL ;
  PORT
   LAYER M4 ;
   RECT 302.208000 668.556000 302.400000 668.580000 ;
  END
 END po1[196]
 PIN po1[197]
  DIRECTION INPUT ;
  USE SIGNAL ;
  PORT
   LAYER M4 ;
   RECT 302.208000 668.748000 302.400000 668.772000 ;
  END
 END po1[197]
 PIN po1[198]
  DIRECTION INPUT ;
  USE SIGNAL ;
  PORT
   LAYER M4 ;
   RECT 302.208000 668.940000 302.400000 668.964000 ;
  END
 END po1[198]
 PIN po1[199]
  DIRECTION INPUT ;
  USE SIGNAL ;
  PORT
   LAYER M4 ;
   RECT 302.208000 669.132000 302.400000 669.156000 ;
  END
 END po1[199]
 PIN po1[200]
  DIRECTION INPUT ;
  USE SIGNAL ;
  PORT
   LAYER M4 ;
   RECT 302.208000 669.324000 302.400000 669.348000 ;
  END
 END po1[200]
 PIN po1[201]
  DIRECTION INPUT ;
  USE SIGNAL ;
  PORT
   LAYER M4 ;
   RECT 302.208000 669.516000 302.400000 669.540000 ;
  END
 END po1[201]
 PIN po1[202]
  DIRECTION INPUT ;
  USE SIGNAL ;
  PORT
   LAYER M4 ;
   RECT 302.208000 669.708000 302.400000 669.732000 ;
  END
 END po1[202]
 PIN po1[203]
  DIRECTION INPUT ;
  USE SIGNAL ;
  PORT
   LAYER M4 ;
   RECT 302.208000 669.900000 302.400000 669.924000 ;
  END
 END po1[203]
 PIN po1[204]
  DIRECTION INPUT ;
  USE SIGNAL ;
  PORT
   LAYER M4 ;
   RECT 302.208000 670.092000 302.400000 670.116000 ;
  END
 END po1[204]
 PIN po1[205]
  DIRECTION INPUT ;
  USE SIGNAL ;
  PORT
   LAYER M4 ;
   RECT 302.208000 670.284000 302.400000 670.308000 ;
  END
 END po1[205]
 PIN po1[206]
  DIRECTION INPUT ;
  USE SIGNAL ;
  PORT
   LAYER M4 ;
   RECT 302.208000 670.476000 302.400000 670.500000 ;
  END
 END po1[206]
 PIN po1[207]
  DIRECTION INPUT ;
  USE SIGNAL ;
  PORT
   LAYER M4 ;
   RECT 302.208000 670.668000 302.400000 670.692000 ;
  END
 END po1[207]
 PIN po1[208]
  DIRECTION INPUT ;
  USE SIGNAL ;
  PORT
   LAYER M4 ;
   RECT 302.208000 670.860000 302.400000 670.884000 ;
  END
 END po1[208]
 PIN po1[209]
  DIRECTION INPUT ;
  USE SIGNAL ;
  PORT
   LAYER M4 ;
   RECT 302.208000 671.052000 302.400000 671.076000 ;
  END
 END po1[209]
 PIN po1[210]
  DIRECTION INPUT ;
  USE SIGNAL ;
  PORT
   LAYER M4 ;
   RECT 302.208000 671.244000 302.400000 671.268000 ;
  END
 END po1[210]
 PIN po1[211]
  DIRECTION INPUT ;
  USE SIGNAL ;
  PORT
   LAYER M4 ;
   RECT 302.208000 671.436000 302.400000 671.460000 ;
  END
 END po1[211]
 PIN po1[212]
  DIRECTION INPUT ;
  USE SIGNAL ;
  PORT
   LAYER M4 ;
   RECT 302.208000 671.628000 302.400000 671.652000 ;
  END
 END po1[212]
 PIN po1[213]
  DIRECTION INPUT ;
  USE SIGNAL ;
  PORT
   LAYER M4 ;
   RECT 302.208000 671.820000 302.400000 671.844000 ;
  END
 END po1[213]
 PIN po1[214]
  DIRECTION INPUT ;
  USE SIGNAL ;
  PORT
   LAYER M4 ;
   RECT 302.208000 672.012000 302.400000 672.036000 ;
  END
 END po1[214]
 PIN po1[215]
  DIRECTION INPUT ;
  USE SIGNAL ;
  PORT
   LAYER M4 ;
   RECT 302.208000 672.204000 302.400000 672.228000 ;
  END
 END po1[215]
 PIN po1[216]
  DIRECTION INPUT ;
  USE SIGNAL ;
  PORT
   LAYER M4 ;
   RECT 302.208000 672.396000 302.400000 672.420000 ;
  END
 END po1[216]
 PIN po1[217]
  DIRECTION INPUT ;
  USE SIGNAL ;
  PORT
   LAYER M4 ;
   RECT 302.208000 672.588000 302.400000 672.612000 ;
  END
 END po1[217]
 PIN po1[218]
  DIRECTION INPUT ;
  USE SIGNAL ;
  PORT
   LAYER M4 ;
   RECT 302.208000 672.780000 302.400000 672.804000 ;
  END
 END po1[218]
 PIN po1[219]
  DIRECTION INPUT ;
  USE SIGNAL ;
  PORT
   LAYER M4 ;
   RECT 302.208000 672.972000 302.400000 672.996000 ;
  END
 END po1[219]
 PIN po1[220]
  DIRECTION INPUT ;
  USE SIGNAL ;
  PORT
   LAYER M4 ;
   RECT 302.208000 673.164000 302.400000 673.188000 ;
  END
 END po1[220]
 PIN po1[221]
  DIRECTION INPUT ;
  USE SIGNAL ;
  PORT
   LAYER M4 ;
   RECT 302.208000 673.356000 302.400000 673.380000 ;
  END
 END po1[221]
 PIN po1[222]
  DIRECTION INPUT ;
  USE SIGNAL ;
  PORT
   LAYER M4 ;
   RECT 302.208000 673.548000 302.400000 673.572000 ;
  END
 END po1[222]
 PIN po1[223]
  DIRECTION INPUT ;
  USE SIGNAL ;
  PORT
   LAYER M4 ;
   RECT 302.208000 673.740000 302.400000 673.764000 ;
  END
 END po1[223]
 PIN po1[224]
  DIRECTION INPUT ;
  USE SIGNAL ;
  PORT
   LAYER M4 ;
   RECT 302.208000 673.932000 302.400000 673.956000 ;
  END
 END po1[224]
 PIN po1[225]
  DIRECTION INPUT ;
  USE SIGNAL ;
  PORT
   LAYER M4 ;
   RECT 302.208000 674.124000 302.400000 674.148000 ;
  END
 END po1[225]
 PIN po1[226]
  DIRECTION INPUT ;
  USE SIGNAL ;
  PORT
   LAYER M4 ;
   RECT 302.208000 674.316000 302.400000 674.340000 ;
  END
 END po1[226]
 PIN po1[227]
  DIRECTION INPUT ;
  USE SIGNAL ;
  PORT
   LAYER M4 ;
   RECT 302.208000 674.508000 302.400000 674.532000 ;
  END
 END po1[227]
 PIN po1[228]
  DIRECTION INPUT ;
  USE SIGNAL ;
  PORT
   LAYER M4 ;
   RECT 302.208000 674.700000 302.400000 674.724000 ;
  END
 END po1[228]
 PIN po1[229]
  DIRECTION INPUT ;
  USE SIGNAL ;
  PORT
   LAYER M4 ;
   RECT 302.208000 674.892000 302.400000 674.916000 ;
  END
 END po1[229]
 PIN po1[230]
  DIRECTION INPUT ;
  USE SIGNAL ;
  PORT
   LAYER M4 ;
   RECT 302.208000 675.084000 302.400000 675.108000 ;
  END
 END po1[230]
 PIN po1[231]
  DIRECTION INPUT ;
  USE SIGNAL ;
  PORT
   LAYER M4 ;
   RECT 302.208000 675.276000 302.400000 675.300000 ;
  END
 END po1[231]
 PIN po1[232]
  DIRECTION INPUT ;
  USE SIGNAL ;
  PORT
   LAYER M4 ;
   RECT 302.208000 675.468000 302.400000 675.492000 ;
  END
 END po1[232]
 PIN po1[233]
  DIRECTION INPUT ;
  USE SIGNAL ;
  PORT
   LAYER M4 ;
   RECT 302.208000 675.660000 302.400000 675.684000 ;
  END
 END po1[233]
 PIN po1[234]
  DIRECTION INPUT ;
  USE SIGNAL ;
  PORT
   LAYER M4 ;
   RECT 302.208000 675.852000 302.400000 675.876000 ;
  END
 END po1[234]
 PIN po1[235]
  DIRECTION INPUT ;
  USE SIGNAL ;
  PORT
   LAYER M4 ;
   RECT 302.208000 676.044000 302.400000 676.068000 ;
  END
 END po1[235]
 PIN po1[236]
  DIRECTION INPUT ;
  USE SIGNAL ;
  PORT
   LAYER M4 ;
   RECT 302.208000 676.236000 302.400000 676.260000 ;
  END
 END po1[236]
 PIN po1[237]
  DIRECTION INPUT ;
  USE SIGNAL ;
  PORT
   LAYER M4 ;
   RECT 302.208000 676.428000 302.400000 676.452000 ;
  END
 END po1[237]
 PIN po1[238]
  DIRECTION INPUT ;
  USE SIGNAL ;
  PORT
   LAYER M4 ;
   RECT 302.208000 676.620000 302.400000 676.644000 ;
  END
 END po1[238]
 PIN po1[239]
  DIRECTION INPUT ;
  USE SIGNAL ;
  PORT
   LAYER M4 ;
   RECT 302.208000 676.812000 302.400000 676.836000 ;
  END
 END po1[239]
 PIN po1[240]
  DIRECTION INPUT ;
  USE SIGNAL ;
  PORT
   LAYER M4 ;
   RECT 302.208000 677.004000 302.400000 677.028000 ;
  END
 END po1[240]
 PIN po1[241]
  DIRECTION INPUT ;
  USE SIGNAL ;
  PORT
   LAYER M4 ;
   RECT 302.208000 677.196000 302.400000 677.220000 ;
  END
 END po1[241]
 PIN po1[242]
  DIRECTION INPUT ;
  USE SIGNAL ;
  PORT
   LAYER M4 ;
   RECT 302.208000 677.388000 302.400000 677.412000 ;
  END
 END po1[242]
 PIN po1[243]
  DIRECTION INPUT ;
  USE SIGNAL ;
  PORT
   LAYER M4 ;
   RECT 302.208000 677.580000 302.400000 677.604000 ;
  END
 END po1[243]
 PIN po1[244]
  DIRECTION INPUT ;
  USE SIGNAL ;
  PORT
   LAYER M4 ;
   RECT 302.208000 677.772000 302.400000 677.796000 ;
  END
 END po1[244]
 PIN po1[245]
  DIRECTION INPUT ;
  USE SIGNAL ;
  PORT
   LAYER M4 ;
   RECT 302.208000 677.964000 302.400000 677.988000 ;
  END
 END po1[245]
 PIN po1[246]
  DIRECTION INPUT ;
  USE SIGNAL ;
  PORT
   LAYER M4 ;
   RECT 302.208000 678.156000 302.400000 678.180000 ;
  END
 END po1[246]
 PIN po1[247]
  DIRECTION INPUT ;
  USE SIGNAL ;
  PORT
   LAYER M4 ;
   RECT 302.208000 678.348000 302.400000 678.372000 ;
  END
 END po1[247]
 PIN po1[248]
  DIRECTION INPUT ;
  USE SIGNAL ;
  PORT
   LAYER M4 ;
   RECT 302.208000 678.540000 302.400000 678.564000 ;
  END
 END po1[248]
 PIN po1[249]
  DIRECTION INPUT ;
  USE SIGNAL ;
  PORT
   LAYER M4 ;
   RECT 302.208000 678.732000 302.400000 678.756000 ;
  END
 END po1[249]
 PIN po1[250]
  DIRECTION INPUT ;
  USE SIGNAL ;
  PORT
   LAYER M4 ;
   RECT 302.208000 678.924000 302.400000 678.948000 ;
  END
 END po1[250]
 PIN po1[251]
  DIRECTION INPUT ;
  USE SIGNAL ;
  PORT
   LAYER M4 ;
   RECT 302.208000 679.116000 302.400000 679.140000 ;
  END
 END po1[251]
 PIN po1[252]
  DIRECTION INPUT ;
  USE SIGNAL ;
  PORT
   LAYER M4 ;
   RECT 302.208000 679.308000 302.400000 679.332000 ;
  END
 END po1[252]
 PIN po1[253]
  DIRECTION INPUT ;
  USE SIGNAL ;
  PORT
   LAYER M4 ;
   RECT 302.208000 679.500000 302.400000 679.524000 ;
  END
 END po1[253]
 PIN po1[254]
  DIRECTION INPUT ;
  USE SIGNAL ;
  PORT
   LAYER M4 ;
   RECT 302.208000 679.692000 302.400000 679.716000 ;
  END
 END po1[254]
 PIN po1[255]
  DIRECTION INPUT ;
  USE SIGNAL ;
  PORT
   LAYER M4 ;
   RECT 302.208000 679.884000 302.400000 679.908000 ;
  END
 END po1[255]
 PIN po1[256]
  DIRECTION INPUT ;
  USE SIGNAL ;
  PORT
   LAYER M4 ;
   RECT 302.208000 680.076000 302.400000 680.100000 ;
  END
 END po1[256]
 PIN po1[257]
  DIRECTION INPUT ;
  USE SIGNAL ;
  PORT
   LAYER M4 ;
   RECT 302.208000 680.268000 302.400000 680.292000 ;
  END
 END po1[257]
 PIN po1[258]
  DIRECTION INPUT ;
  USE SIGNAL ;
  PORT
   LAYER M4 ;
   RECT 302.208000 680.460000 302.400000 680.484000 ;
  END
 END po1[258]
 PIN po1[259]
  DIRECTION INPUT ;
  USE SIGNAL ;
  PORT
   LAYER M4 ;
   RECT 302.208000 680.652000 302.400000 680.676000 ;
  END
 END po1[259]
 PIN po1[260]
  DIRECTION INPUT ;
  USE SIGNAL ;
  PORT
   LAYER M4 ;
   RECT 302.208000 680.844000 302.400000 680.868000 ;
  END
 END po1[260]
 PIN po1[261]
  DIRECTION INPUT ;
  USE SIGNAL ;
  PORT
   LAYER M4 ;
   RECT 302.208000 681.036000 302.400000 681.060000 ;
  END
 END po1[261]
 PIN po1[262]
  DIRECTION INPUT ;
  USE SIGNAL ;
  PORT
   LAYER M4 ;
   RECT 302.208000 681.228000 302.400000 681.252000 ;
  END
 END po1[262]
 PIN po1[263]
  DIRECTION INPUT ;
  USE SIGNAL ;
  PORT
   LAYER M4 ;
   RECT 302.208000 681.420000 302.400000 681.444000 ;
  END
 END po1[263]
 PIN po1[264]
  DIRECTION INPUT ;
  USE SIGNAL ;
  PORT
   LAYER M4 ;
   RECT 302.208000 681.612000 302.400000 681.636000 ;
  END
 END po1[264]
 PIN po1[265]
  DIRECTION INPUT ;
  USE SIGNAL ;
  PORT
   LAYER M4 ;
   RECT 302.208000 681.804000 302.400000 681.828000 ;
  END
 END po1[265]
 PIN po1[266]
  DIRECTION INPUT ;
  USE SIGNAL ;
  PORT
   LAYER M4 ;
   RECT 302.208000 681.996000 302.400000 682.020000 ;
  END
 END po1[266]
 PIN po1[267]
  DIRECTION INPUT ;
  USE SIGNAL ;
  PORT
   LAYER M4 ;
   RECT 302.208000 682.188000 302.400000 682.212000 ;
  END
 END po1[267]
 PIN po1[268]
  DIRECTION INPUT ;
  USE SIGNAL ;
  PORT
   LAYER M4 ;
   RECT 302.208000 682.380000 302.400000 682.404000 ;
  END
 END po1[268]
 PIN po1[269]
  DIRECTION INPUT ;
  USE SIGNAL ;
  PORT
   LAYER M4 ;
   RECT 302.208000 682.572000 302.400000 682.596000 ;
  END
 END po1[269]
 PIN po1[270]
  DIRECTION INPUT ;
  USE SIGNAL ;
  PORT
   LAYER M4 ;
   RECT 302.208000 682.764000 302.400000 682.788000 ;
  END
 END po1[270]
 PIN po1[271]
  DIRECTION INPUT ;
  USE SIGNAL ;
  PORT
   LAYER M4 ;
   RECT 302.208000 682.956000 302.400000 682.980000 ;
  END
 END po1[271]
 PIN po1[272]
  DIRECTION INPUT ;
  USE SIGNAL ;
  PORT
   LAYER M4 ;
   RECT 302.208000 683.148000 302.400000 683.172000 ;
  END
 END po1[272]
 PIN po1[273]
  DIRECTION INPUT ;
  USE SIGNAL ;
  PORT
   LAYER M4 ;
   RECT 302.208000 683.340000 302.400000 683.364000 ;
  END
 END po1[273]
 PIN po1[274]
  DIRECTION INPUT ;
  USE SIGNAL ;
  PORT
   LAYER M4 ;
   RECT 302.208000 683.532000 302.400000 683.556000 ;
  END
 END po1[274]
 PIN po1[275]
  DIRECTION INPUT ;
  USE SIGNAL ;
  PORT
   LAYER M4 ;
   RECT 302.208000 683.724000 302.400000 683.748000 ;
  END
 END po1[275]
 PIN po1[276]
  DIRECTION INPUT ;
  USE SIGNAL ;
  PORT
   LAYER M4 ;
   RECT 302.208000 683.916000 302.400000 683.940000 ;
  END
 END po1[276]
 PIN po1[277]
  DIRECTION INPUT ;
  USE SIGNAL ;
  PORT
   LAYER M4 ;
   RECT 302.208000 684.108000 302.400000 684.132000 ;
  END
 END po1[277]
 PIN po1[278]
  DIRECTION INPUT ;
  USE SIGNAL ;
  PORT
   LAYER M4 ;
   RECT 302.208000 684.300000 302.400000 684.324000 ;
  END
 END po1[278]
 PIN po1[279]
  DIRECTION INPUT ;
  USE SIGNAL ;
  PORT
   LAYER M4 ;
   RECT 302.208000 684.492000 302.400000 684.516000 ;
  END
 END po1[279]
 PIN po1[280]
  DIRECTION INPUT ;
  USE SIGNAL ;
  PORT
   LAYER M4 ;
   RECT 302.208000 684.684000 302.400000 684.708000 ;
  END
 END po1[280]
 PIN po1[281]
  DIRECTION INPUT ;
  USE SIGNAL ;
  PORT
   LAYER M4 ;
   RECT 302.208000 684.876000 302.400000 684.900000 ;
  END
 END po1[281]
 PIN po1[282]
  DIRECTION INPUT ;
  USE SIGNAL ;
  PORT
   LAYER M4 ;
   RECT 302.208000 685.068000 302.400000 685.092000 ;
  END
 END po1[282]
 PIN po1[283]
  DIRECTION INPUT ;
  USE SIGNAL ;
  PORT
   LAYER M4 ;
   RECT 302.208000 685.260000 302.400000 685.284000 ;
  END
 END po1[283]
 PIN po1[284]
  DIRECTION INPUT ;
  USE SIGNAL ;
  PORT
   LAYER M4 ;
   RECT 302.208000 685.452000 302.400000 685.476000 ;
  END
 END po1[284]
 PIN po1[285]
  DIRECTION INPUT ;
  USE SIGNAL ;
  PORT
   LAYER M4 ;
   RECT 302.208000 685.644000 302.400000 685.668000 ;
  END
 END po1[285]
 PIN po1[286]
  DIRECTION INPUT ;
  USE SIGNAL ;
  PORT
   LAYER M4 ;
   RECT 302.208000 685.836000 302.400000 685.860000 ;
  END
 END po1[286]
 PIN po1[287]
  DIRECTION INPUT ;
  USE SIGNAL ;
  PORT
   LAYER M4 ;
   RECT 302.208000 686.028000 302.400000 686.052000 ;
  END
 END po1[287]
 PIN po1[288]
  DIRECTION INPUT ;
  USE SIGNAL ;
  PORT
   LAYER M4 ;
   RECT 302.208000 686.220000 302.400000 686.244000 ;
  END
 END po1[288]
 PIN po1[289]
  DIRECTION INPUT ;
  USE SIGNAL ;
  PORT
   LAYER M4 ;
   RECT 302.208000 686.412000 302.400000 686.436000 ;
  END
 END po1[289]
 PIN po1[290]
  DIRECTION INPUT ;
  USE SIGNAL ;
  PORT
   LAYER M4 ;
   RECT 302.208000 686.604000 302.400000 686.628000 ;
  END
 END po1[290]
 PIN po1[291]
  DIRECTION INPUT ;
  USE SIGNAL ;
  PORT
   LAYER M4 ;
   RECT 302.208000 686.796000 302.400000 686.820000 ;
  END
 END po1[291]
 PIN po1[292]
  DIRECTION INPUT ;
  USE SIGNAL ;
  PORT
   LAYER M4 ;
   RECT 302.208000 686.988000 302.400000 687.012000 ;
  END
 END po1[292]
 PIN po1[293]
  DIRECTION INPUT ;
  USE SIGNAL ;
  PORT
   LAYER M4 ;
   RECT 302.208000 687.180000 302.400000 687.204000 ;
  END
 END po1[293]
 PIN po1[294]
  DIRECTION INPUT ;
  USE SIGNAL ;
  PORT
   LAYER M4 ;
   RECT 302.208000 687.372000 302.400000 687.396000 ;
  END
 END po1[294]
 PIN po1[295]
  DIRECTION INPUT ;
  USE SIGNAL ;
  PORT
   LAYER M4 ;
   RECT 302.208000 687.564000 302.400000 687.588000 ;
  END
 END po1[295]
 PIN po1[296]
  DIRECTION INPUT ;
  USE SIGNAL ;
  PORT
   LAYER M4 ;
   RECT 302.208000 687.756000 302.400000 687.780000 ;
  END
 END po1[296]
 PIN po1[297]
  DIRECTION INPUT ;
  USE SIGNAL ;
  PORT
   LAYER M4 ;
   RECT 302.208000 687.948000 302.400000 687.972000 ;
  END
 END po1[297]
 PIN po1[298]
  DIRECTION INPUT ;
  USE SIGNAL ;
  PORT
   LAYER M4 ;
   RECT 302.208000 688.140000 302.400000 688.164000 ;
  END
 END po1[298]
 PIN po1[299]
  DIRECTION INPUT ;
  USE SIGNAL ;
  PORT
   LAYER M4 ;
   RECT 302.208000 688.332000 302.400000 688.356000 ;
  END
 END po1[299]
 PIN po1[300]
  DIRECTION INPUT ;
  USE SIGNAL ;
  PORT
   LAYER M4 ;
   RECT 302.208000 688.524000 302.400000 688.548000 ;
  END
 END po1[300]
 PIN po1[301]
  DIRECTION INPUT ;
  USE SIGNAL ;
  PORT
   LAYER M4 ;
   RECT 302.208000 688.716000 302.400000 688.740000 ;
  END
 END po1[301]
 PIN po1[302]
  DIRECTION INPUT ;
  USE SIGNAL ;
  PORT
   LAYER M4 ;
   RECT 302.208000 688.908000 302.400000 688.932000 ;
  END
 END po1[302]
 PIN po1[303]
  DIRECTION INPUT ;
  USE SIGNAL ;
  PORT
   LAYER M4 ;
   RECT 302.208000 689.100000 302.400000 689.124000 ;
  END
 END po1[303]
 PIN po1[304]
  DIRECTION INPUT ;
  USE SIGNAL ;
  PORT
   LAYER M4 ;
   RECT 302.208000 689.292000 302.400000 689.316000 ;
  END
 END po1[304]
 PIN po1[305]
  DIRECTION INPUT ;
  USE SIGNAL ;
  PORT
   LAYER M4 ;
   RECT 302.208000 689.484000 302.400000 689.508000 ;
  END
 END po1[305]
 PIN po1[306]
  DIRECTION INPUT ;
  USE SIGNAL ;
  PORT
   LAYER M4 ;
   RECT 302.208000 689.676000 302.400000 689.700000 ;
  END
 END po1[306]
 PIN po1[307]
  DIRECTION INPUT ;
  USE SIGNAL ;
  PORT
   LAYER M4 ;
   RECT 302.208000 689.868000 302.400000 689.892000 ;
  END
 END po1[307]
 PIN po1[308]
  DIRECTION INPUT ;
  USE SIGNAL ;
  PORT
   LAYER M4 ;
   RECT 302.208000 690.060000 302.400000 690.084000 ;
  END
 END po1[308]
 PIN po1[309]
  DIRECTION INPUT ;
  USE SIGNAL ;
  PORT
   LAYER M4 ;
   RECT 302.208000 690.252000 302.400000 690.276000 ;
  END
 END po1[309]
 PIN po1[310]
  DIRECTION INPUT ;
  USE SIGNAL ;
  PORT
   LAYER M4 ;
   RECT 302.208000 690.444000 302.400000 690.468000 ;
  END
 END po1[310]
 PIN po1[311]
  DIRECTION INPUT ;
  USE SIGNAL ;
  PORT
   LAYER M4 ;
   RECT 302.208000 690.636000 302.400000 690.660000 ;
  END
 END po1[311]
 PIN po1[312]
  DIRECTION INPUT ;
  USE SIGNAL ;
  PORT
   LAYER M4 ;
   RECT 302.208000 690.828000 302.400000 690.852000 ;
  END
 END po1[312]
 PIN po1[313]
  DIRECTION INPUT ;
  USE SIGNAL ;
  PORT
   LAYER M4 ;
   RECT 302.208000 691.020000 302.400000 691.044000 ;
  END
 END po1[313]
 PIN po1[314]
  DIRECTION INPUT ;
  USE SIGNAL ;
  PORT
   LAYER M4 ;
   RECT 302.208000 691.212000 302.400000 691.236000 ;
  END
 END po1[314]
 PIN po1[315]
  DIRECTION INPUT ;
  USE SIGNAL ;
  PORT
   LAYER M4 ;
   RECT 302.208000 691.404000 302.400000 691.428000 ;
  END
 END po1[315]
 PIN po1[316]
  DIRECTION INPUT ;
  USE SIGNAL ;
  PORT
   LAYER M4 ;
   RECT 302.208000 691.596000 302.400000 691.620000 ;
  END
 END po1[316]
 PIN po1[317]
  DIRECTION INPUT ;
  USE SIGNAL ;
  PORT
   LAYER M4 ;
   RECT 302.208000 691.788000 302.400000 691.812000 ;
  END
 END po1[317]
 PIN po1[318]
  DIRECTION INPUT ;
  USE SIGNAL ;
  PORT
   LAYER M4 ;
   RECT 302.208000 691.980000 302.400000 692.004000 ;
  END
 END po1[318]
 PIN po1[319]
  DIRECTION INPUT ;
  USE SIGNAL ;
  PORT
   LAYER M4 ;
   RECT 302.208000 692.172000 302.400000 692.196000 ;
  END
 END po1[319]
 PIN po1[320]
  DIRECTION INPUT ;
  USE SIGNAL ;
  PORT
   LAYER M4 ;
   RECT 302.208000 692.364000 302.400000 692.388000 ;
  END
 END po1[320]
 PIN po1[321]
  DIRECTION INPUT ;
  USE SIGNAL ;
  PORT
   LAYER M4 ;
   RECT 302.208000 692.556000 302.400000 692.580000 ;
  END
 END po1[321]
 PIN po1[322]
  DIRECTION INPUT ;
  USE SIGNAL ;
  PORT
   LAYER M4 ;
   RECT 302.208000 692.748000 302.400000 692.772000 ;
  END
 END po1[322]
 PIN po1[323]
  DIRECTION INPUT ;
  USE SIGNAL ;
  PORT
   LAYER M4 ;
   RECT 302.208000 692.940000 302.400000 692.964000 ;
  END
 END po1[323]
 PIN po1[324]
  DIRECTION INPUT ;
  USE SIGNAL ;
  PORT
   LAYER M4 ;
   RECT 302.208000 693.132000 302.400000 693.156000 ;
  END
 END po1[324]
 PIN po1[325]
  DIRECTION INPUT ;
  USE SIGNAL ;
  PORT
   LAYER M4 ;
   RECT 302.208000 693.324000 302.400000 693.348000 ;
  END
 END po1[325]
 PIN po1[326]
  DIRECTION INPUT ;
  USE SIGNAL ;
  PORT
   LAYER M4 ;
   RECT 302.208000 693.516000 302.400000 693.540000 ;
  END
 END po1[326]
 PIN po1[327]
  DIRECTION INPUT ;
  USE SIGNAL ;
  PORT
   LAYER M4 ;
   RECT 302.208000 693.708000 302.400000 693.732000 ;
  END
 END po1[327]
 PIN pi1[0]
  DIRECTION OUTPUT ;
  USE SIGNAL ;
  PORT
   LAYER M4 ;
   RECT 302.208000 693.900000 302.400000 693.924000 ;
  END
 END pi1[0]
 PIN pi1[1]
  DIRECTION OUTPUT ;
  USE SIGNAL ;
  PORT
   LAYER M4 ;
   RECT 302.208000 694.092000 302.400000 694.116000 ;
  END
 END pi1[1]
 PIN pi1[2]
  DIRECTION OUTPUT ;
  USE SIGNAL ;
  PORT
   LAYER M4 ;
   RECT 302.208000 694.284000 302.400000 694.308000 ;
  END
 END pi1[2]
 PIN pi1[3]
  DIRECTION OUTPUT ;
  USE SIGNAL ;
  PORT
   LAYER M4 ;
   RECT 302.208000 694.476000 302.400000 694.500000 ;
  END
 END pi1[3]
 PIN pi1[4]
  DIRECTION OUTPUT ;
  USE SIGNAL ;
  PORT
   LAYER M4 ;
   RECT 302.208000 694.668000 302.400000 694.692000 ;
  END
 END pi1[4]
 PIN pi1[5]
  DIRECTION OUTPUT ;
  USE SIGNAL ;
  PORT
   LAYER M4 ;
   RECT 302.208000 694.860000 302.400000 694.884000 ;
  END
 END pi1[5]
 PIN pi1[6]
  DIRECTION OUTPUT ;
  USE SIGNAL ;
  PORT
   LAYER M4 ;
   RECT 302.208000 695.052000 302.400000 695.076000 ;
  END
 END pi1[6]
 PIN pi1[7]
  DIRECTION OUTPUT ;
  USE SIGNAL ;
  PORT
   LAYER M4 ;
   RECT 302.208000 695.244000 302.400000 695.268000 ;
  END
 END pi1[7]
 PIN pi1[8]
  DIRECTION OUTPUT ;
  USE SIGNAL ;
  PORT
   LAYER M4 ;
   RECT 302.208000 695.436000 302.400000 695.460000 ;
  END
 END pi1[8]
 PIN pi1[9]
  DIRECTION OUTPUT ;
  USE SIGNAL ;
  PORT
   LAYER M4 ;
   RECT 302.208000 695.628000 302.400000 695.652000 ;
  END
 END pi1[9]
 PIN pi1[10]
  DIRECTION OUTPUT ;
  USE SIGNAL ;
  PORT
   LAYER M4 ;
   RECT 302.208000 695.820000 302.400000 695.844000 ;
  END
 END pi1[10]
 PIN pi1[11]
  DIRECTION OUTPUT ;
  USE SIGNAL ;
  PORT
   LAYER M4 ;
   RECT 302.208000 696.012000 302.400000 696.036000 ;
  END
 END pi1[11]
 PIN pi1[12]
  DIRECTION OUTPUT ;
  USE SIGNAL ;
  PORT
   LAYER M4 ;
   RECT 302.208000 696.204000 302.400000 696.228000 ;
  END
 END pi1[12]
 PIN pi1[13]
  DIRECTION OUTPUT ;
  USE SIGNAL ;
  PORT
   LAYER M4 ;
   RECT 302.208000 696.396000 302.400000 696.420000 ;
  END
 END pi1[13]
 PIN pi1[14]
  DIRECTION OUTPUT ;
  USE SIGNAL ;
  PORT
   LAYER M4 ;
   RECT 302.208000 696.588000 302.400000 696.612000 ;
  END
 END pi1[14]
 PIN pi1[15]
  DIRECTION OUTPUT ;
  USE SIGNAL ;
  PORT
   LAYER M4 ;
   RECT 302.208000 696.780000 302.400000 696.804000 ;
  END
 END pi1[15]
 PIN pi1[16]
  DIRECTION OUTPUT ;
  USE SIGNAL ;
  PORT
   LAYER M4 ;
   RECT 302.208000 696.972000 302.400000 696.996000 ;
  END
 END pi1[16]
 PIN pi1[17]
  DIRECTION OUTPUT ;
  USE SIGNAL ;
  PORT
   LAYER M4 ;
   RECT 302.208000 697.164000 302.400000 697.188000 ;
  END
 END pi1[17]
 PIN pi1[18]
  DIRECTION OUTPUT ;
  USE SIGNAL ;
  PORT
   LAYER M4 ;
   RECT 302.208000 697.356000 302.400000 697.380000 ;
  END
 END pi1[18]
 PIN pi1[19]
  DIRECTION OUTPUT ;
  USE SIGNAL ;
  PORT
   LAYER M4 ;
   RECT 302.208000 697.548000 302.400000 697.572000 ;
  END
 END pi1[19]
 PIN pi1[20]
  DIRECTION OUTPUT ;
  USE SIGNAL ;
  PORT
   LAYER M4 ;
   RECT 302.208000 697.740000 302.400000 697.764000 ;
  END
 END pi1[20]
 PIN pi1[21]
  DIRECTION OUTPUT ;
  USE SIGNAL ;
  PORT
   LAYER M4 ;
   RECT 302.208000 697.932000 302.400000 697.956000 ;
  END
 END pi1[21]
 PIN pi1[22]
  DIRECTION OUTPUT ;
  USE SIGNAL ;
  PORT
   LAYER M4 ;
   RECT 302.208000 698.124000 302.400000 698.148000 ;
  END
 END pi1[22]
 PIN pi1[23]
  DIRECTION OUTPUT ;
  USE SIGNAL ;
  PORT
   LAYER M4 ;
   RECT 302.208000 698.316000 302.400000 698.340000 ;
  END
 END pi1[23]
 PIN pi1[24]
  DIRECTION OUTPUT ;
  USE SIGNAL ;
  PORT
   LAYER M4 ;
   RECT 302.208000 698.508000 302.400000 698.532000 ;
  END
 END pi1[24]
 PIN pi1[25]
  DIRECTION OUTPUT ;
  USE SIGNAL ;
  PORT
   LAYER M4 ;
   RECT 302.208000 698.700000 302.400000 698.724000 ;
  END
 END pi1[25]
 PIN pi1[26]
  DIRECTION OUTPUT ;
  USE SIGNAL ;
  PORT
   LAYER M4 ;
   RECT 302.208000 698.892000 302.400000 698.916000 ;
  END
 END pi1[26]
 PIN pi1[27]
  DIRECTION OUTPUT ;
  USE SIGNAL ;
  PORT
   LAYER M4 ;
   RECT 302.208000 699.084000 302.400000 699.108000 ;
  END
 END pi1[27]
 PIN pi1[28]
  DIRECTION OUTPUT ;
  USE SIGNAL ;
  PORT
   LAYER M4 ;
   RECT 302.208000 699.276000 302.400000 699.300000 ;
  END
 END pi1[28]
 PIN pi1[29]
  DIRECTION OUTPUT ;
  USE SIGNAL ;
  PORT
   LAYER M4 ;
   RECT 302.208000 699.468000 302.400000 699.492000 ;
  END
 END pi1[29]
 PIN pi1[30]
  DIRECTION OUTPUT ;
  USE SIGNAL ;
  PORT
   LAYER M4 ;
   RECT 302.208000 699.660000 302.400000 699.684000 ;
  END
 END pi1[30]
 PIN pi1[31]
  DIRECTION OUTPUT ;
  USE SIGNAL ;
  PORT
   LAYER M4 ;
   RECT 302.208000 699.852000 302.400000 699.876000 ;
  END
 END pi1[31]
 PIN pi1[32]
  DIRECTION OUTPUT ;
  USE SIGNAL ;
  PORT
   LAYER M4 ;
   RECT 302.208000 700.044000 302.400000 700.068000 ;
  END
 END pi1[32]
 PIN pi1[33]
  DIRECTION OUTPUT ;
  USE SIGNAL ;
  PORT
   LAYER M4 ;
   RECT 302.208000 700.236000 302.400000 700.260000 ;
  END
 END pi1[33]
 PIN pi1[34]
  DIRECTION OUTPUT ;
  USE SIGNAL ;
  PORT
   LAYER M4 ;
   RECT 302.208000 700.428000 302.400000 700.452000 ;
  END
 END pi1[34]
 PIN pi1[35]
  DIRECTION OUTPUT ;
  USE SIGNAL ;
  PORT
   LAYER M4 ;
   RECT 302.208000 700.620000 302.400000 700.644000 ;
  END
 END pi1[35]
 PIN pi1[36]
  DIRECTION OUTPUT ;
  USE SIGNAL ;
  PORT
   LAYER M4 ;
   RECT 302.208000 700.812000 302.400000 700.836000 ;
  END
 END pi1[36]
 PIN pi1[37]
  DIRECTION OUTPUT ;
  USE SIGNAL ;
  PORT
   LAYER M4 ;
   RECT 302.208000 701.004000 302.400000 701.028000 ;
  END
 END pi1[37]
 PIN pi1[38]
  DIRECTION OUTPUT ;
  USE SIGNAL ;
  PORT
   LAYER M4 ;
   RECT 302.208000 701.196000 302.400000 701.220000 ;
  END
 END pi1[38]
 PIN pi1[39]
  DIRECTION OUTPUT ;
  USE SIGNAL ;
  PORT
   LAYER M4 ;
   RECT 302.208000 701.388000 302.400000 701.412000 ;
  END
 END pi1[39]
 PIN pi1[40]
  DIRECTION OUTPUT ;
  USE SIGNAL ;
  PORT
   LAYER M4 ;
   RECT 302.208000 701.580000 302.400000 701.604000 ;
  END
 END pi1[40]
 PIN pi1[41]
  DIRECTION OUTPUT ;
  USE SIGNAL ;
  PORT
   LAYER M4 ;
   RECT 302.208000 701.772000 302.400000 701.796000 ;
  END
 END pi1[41]
 PIN pi1[42]
  DIRECTION OUTPUT ;
  USE SIGNAL ;
  PORT
   LAYER M4 ;
   RECT 302.208000 701.964000 302.400000 701.988000 ;
  END
 END pi1[42]
 PIN pi1[43]
  DIRECTION OUTPUT ;
  USE SIGNAL ;
  PORT
   LAYER M4 ;
   RECT 302.208000 702.156000 302.400000 702.180000 ;
  END
 END pi1[43]
 PIN pi1[44]
  DIRECTION OUTPUT ;
  USE SIGNAL ;
  PORT
   LAYER M4 ;
   RECT 302.208000 702.348000 302.400000 702.372000 ;
  END
 END pi1[44]
 PIN pi1[45]
  DIRECTION OUTPUT ;
  USE SIGNAL ;
  PORT
   LAYER M4 ;
   RECT 302.208000 702.540000 302.400000 702.564000 ;
  END
 END pi1[45]
 PIN pi1[46]
  DIRECTION OUTPUT ;
  USE SIGNAL ;
  PORT
   LAYER M4 ;
   RECT 302.208000 702.732000 302.400000 702.756000 ;
  END
 END pi1[46]
 PIN pi1[47]
  DIRECTION OUTPUT ;
  USE SIGNAL ;
  PORT
   LAYER M4 ;
   RECT 302.208000 702.924000 302.400000 702.948000 ;
  END
 END pi1[47]
 PIN pi1[48]
  DIRECTION OUTPUT ;
  USE SIGNAL ;
  PORT
   LAYER M4 ;
   RECT 302.208000 703.116000 302.400000 703.140000 ;
  END
 END pi1[48]
 PIN pi1[49]
  DIRECTION OUTPUT ;
  USE SIGNAL ;
  PORT
   LAYER M4 ;
   RECT 302.208000 703.308000 302.400000 703.332000 ;
  END
 END pi1[49]
 PIN pi1[50]
  DIRECTION OUTPUT ;
  USE SIGNAL ;
  PORT
   LAYER M4 ;
   RECT 302.208000 703.500000 302.400000 703.524000 ;
  END
 END pi1[50]
 PIN pi1[51]
  DIRECTION OUTPUT ;
  USE SIGNAL ;
  PORT
   LAYER M4 ;
   RECT 302.208000 703.692000 302.400000 703.716000 ;
  END
 END pi1[51]
 PIN pi1[52]
  DIRECTION OUTPUT ;
  USE SIGNAL ;
  PORT
   LAYER M4 ;
   RECT 302.208000 703.884000 302.400000 703.908000 ;
  END
 END pi1[52]
 PIN pi1[53]
  DIRECTION OUTPUT ;
  USE SIGNAL ;
  PORT
   LAYER M4 ;
   RECT 302.208000 704.076000 302.400000 704.100000 ;
  END
 END pi1[53]
 PIN pi1[54]
  DIRECTION OUTPUT ;
  USE SIGNAL ;
  PORT
   LAYER M4 ;
   RECT 302.208000 704.268000 302.400000 704.292000 ;
  END
 END pi1[54]
 PIN pi1[55]
  DIRECTION OUTPUT ;
  USE SIGNAL ;
  PORT
   LAYER M4 ;
   RECT 302.208000 704.460000 302.400000 704.484000 ;
  END
 END pi1[55]
 PIN pi1[56]
  DIRECTION OUTPUT ;
  USE SIGNAL ;
  PORT
   LAYER M4 ;
   RECT 302.208000 704.652000 302.400000 704.676000 ;
  END
 END pi1[56]
 PIN pi1[57]
  DIRECTION OUTPUT ;
  USE SIGNAL ;
  PORT
   LAYER M4 ;
   RECT 302.208000 704.844000 302.400000 704.868000 ;
  END
 END pi1[57]
 PIN pi1[58]
  DIRECTION OUTPUT ;
  USE SIGNAL ;
  PORT
   LAYER M4 ;
   RECT 302.208000 705.036000 302.400000 705.060000 ;
  END
 END pi1[58]
 PIN pi1[59]
  DIRECTION OUTPUT ;
  USE SIGNAL ;
  PORT
   LAYER M4 ;
   RECT 302.208000 705.228000 302.400000 705.252000 ;
  END
 END pi1[59]
 PIN pi1[60]
  DIRECTION OUTPUT ;
  USE SIGNAL ;
  PORT
   LAYER M4 ;
   RECT 302.208000 705.420000 302.400000 705.444000 ;
  END
 END pi1[60]
 PIN pi1[61]
  DIRECTION OUTPUT ;
  USE SIGNAL ;
  PORT
   LAYER M4 ;
   RECT 302.208000 705.612000 302.400000 705.636000 ;
  END
 END pi1[61]
 PIN pi1[62]
  DIRECTION OUTPUT ;
  USE SIGNAL ;
  PORT
   LAYER M4 ;
   RECT 302.208000 705.804000 302.400000 705.828000 ;
  END
 END pi1[62]
 PIN pi1[63]
  DIRECTION OUTPUT ;
  USE SIGNAL ;
  PORT
   LAYER M4 ;
   RECT 302.208000 705.996000 302.400000 706.020000 ;
  END
 END pi1[63]
 PIN pi1[64]
  DIRECTION OUTPUT ;
  USE SIGNAL ;
  PORT
   LAYER M4 ;
   RECT 302.208000 706.188000 302.400000 706.212000 ;
  END
 END pi1[64]
 PIN pi1[65]
  DIRECTION OUTPUT ;
  USE SIGNAL ;
  PORT
   LAYER M4 ;
   RECT 302.208000 706.380000 302.400000 706.404000 ;
  END
 END pi1[65]
 PIN pi1[66]
  DIRECTION OUTPUT ;
  USE SIGNAL ;
  PORT
   LAYER M4 ;
   RECT 302.208000 706.572000 302.400000 706.596000 ;
  END
 END pi1[66]
 PIN pi1[67]
  DIRECTION OUTPUT ;
  USE SIGNAL ;
  PORT
   LAYER M4 ;
   RECT 302.208000 706.764000 302.400000 706.788000 ;
  END
 END pi1[67]
 PIN pi1[68]
  DIRECTION OUTPUT ;
  USE SIGNAL ;
  PORT
   LAYER M4 ;
   RECT 302.208000 706.956000 302.400000 706.980000 ;
  END
 END pi1[68]
 PIN pi1[69]
  DIRECTION OUTPUT ;
  USE SIGNAL ;
  PORT
   LAYER M4 ;
   RECT 302.208000 707.148000 302.400000 707.172000 ;
  END
 END pi1[69]
 PIN pi1[70]
  DIRECTION OUTPUT ;
  USE SIGNAL ;
  PORT
   LAYER M4 ;
   RECT 302.208000 707.340000 302.400000 707.364000 ;
  END
 END pi1[70]
 PIN pi1[71]
  DIRECTION OUTPUT ;
  USE SIGNAL ;
  PORT
   LAYER M4 ;
   RECT 302.208000 707.532000 302.400000 707.556000 ;
  END
 END pi1[71]
 PIN pi1[72]
  DIRECTION OUTPUT ;
  USE SIGNAL ;
  PORT
   LAYER M4 ;
   RECT 302.208000 707.724000 302.400000 707.748000 ;
  END
 END pi1[72]
 PIN pi1[73]
  DIRECTION OUTPUT ;
  USE SIGNAL ;
  PORT
   LAYER M4 ;
   RECT 302.208000 707.916000 302.400000 707.940000 ;
  END
 END pi1[73]
 PIN pi1[74]
  DIRECTION OUTPUT ;
  USE SIGNAL ;
  PORT
   LAYER M4 ;
   RECT 302.208000 708.108000 302.400000 708.132000 ;
  END
 END pi1[74]
 PIN pi1[75]
  DIRECTION OUTPUT ;
  USE SIGNAL ;
  PORT
   LAYER M4 ;
   RECT 302.208000 708.300000 302.400000 708.324000 ;
  END
 END pi1[75]
 PIN pi1[76]
  DIRECTION OUTPUT ;
  USE SIGNAL ;
  PORT
   LAYER M4 ;
   RECT 302.208000 708.492000 302.400000 708.516000 ;
  END
 END pi1[76]
 PIN pi1[77]
  DIRECTION OUTPUT ;
  USE SIGNAL ;
  PORT
   LAYER M4 ;
   RECT 302.208000 708.684000 302.400000 708.708000 ;
  END
 END pi1[77]
 PIN pi1[78]
  DIRECTION OUTPUT ;
  USE SIGNAL ;
  PORT
   LAYER M4 ;
   RECT 302.208000 708.876000 302.400000 708.900000 ;
  END
 END pi1[78]
 PIN pi1[79]
  DIRECTION OUTPUT ;
  USE SIGNAL ;
  PORT
   LAYER M4 ;
   RECT 302.208000 709.068000 302.400000 709.092000 ;
  END
 END pi1[79]
 PIN pi1[80]
  DIRECTION OUTPUT ;
  USE SIGNAL ;
  PORT
   LAYER M4 ;
   RECT 302.208000 709.260000 302.400000 709.284000 ;
  END
 END pi1[80]
 PIN pi1[81]
  DIRECTION OUTPUT ;
  USE SIGNAL ;
  PORT
   LAYER M4 ;
   RECT 302.208000 709.452000 302.400000 709.476000 ;
  END
 END pi1[81]
 PIN pi1[82]
  DIRECTION OUTPUT ;
  USE SIGNAL ;
  PORT
   LAYER M4 ;
   RECT 302.208000 709.644000 302.400000 709.668000 ;
  END
 END pi1[82]
 PIN pi1[83]
  DIRECTION OUTPUT ;
  USE SIGNAL ;
  PORT
   LAYER M4 ;
   RECT 302.208000 709.836000 302.400000 709.860000 ;
  END
 END pi1[83]
 PIN pi1[84]
  DIRECTION OUTPUT ;
  USE SIGNAL ;
  PORT
   LAYER M4 ;
   RECT 302.208000 710.028000 302.400000 710.052000 ;
  END
 END pi1[84]
 PIN pi1[85]
  DIRECTION OUTPUT ;
  USE SIGNAL ;
  PORT
   LAYER M4 ;
   RECT 302.208000 710.220000 302.400000 710.244000 ;
  END
 END pi1[85]
 PIN pi1[86]
  DIRECTION OUTPUT ;
  USE SIGNAL ;
  PORT
   LAYER M4 ;
   RECT 302.208000 710.412000 302.400000 710.436000 ;
  END
 END pi1[86]
 PIN pi1[87]
  DIRECTION OUTPUT ;
  USE SIGNAL ;
  PORT
   LAYER M4 ;
   RECT 302.208000 710.604000 302.400000 710.628000 ;
  END
 END pi1[87]
 PIN pi1[88]
  DIRECTION OUTPUT ;
  USE SIGNAL ;
  PORT
   LAYER M4 ;
   RECT 302.208000 710.796000 302.400000 710.820000 ;
  END
 END pi1[88]
 PIN pi1[89]
  DIRECTION OUTPUT ;
  USE SIGNAL ;
  PORT
   LAYER M4 ;
   RECT 302.208000 710.988000 302.400000 711.012000 ;
  END
 END pi1[89]
 PIN pi1[90]
  DIRECTION OUTPUT ;
  USE SIGNAL ;
  PORT
   LAYER M4 ;
   RECT 302.208000 711.180000 302.400000 711.204000 ;
  END
 END pi1[90]
 PIN pi1[91]
  DIRECTION OUTPUT ;
  USE SIGNAL ;
  PORT
   LAYER M4 ;
   RECT 302.208000 711.372000 302.400000 711.396000 ;
  END
 END pi1[91]
 PIN pi1[92]
  DIRECTION OUTPUT ;
  USE SIGNAL ;
  PORT
   LAYER M4 ;
   RECT 302.208000 711.564000 302.400000 711.588000 ;
  END
 END pi1[92]
 PIN pi1[93]
  DIRECTION OUTPUT ;
  USE SIGNAL ;
  PORT
   LAYER M4 ;
   RECT 302.208000 711.756000 302.400000 711.780000 ;
  END
 END pi1[93]
 PIN pi1[94]
  DIRECTION OUTPUT ;
  USE SIGNAL ;
  PORT
   LAYER M4 ;
   RECT 302.208000 711.948000 302.400000 711.972000 ;
  END
 END pi1[94]
 PIN pi1[95]
  DIRECTION OUTPUT ;
  USE SIGNAL ;
  PORT
   LAYER M4 ;
   RECT 302.208000 712.140000 302.400000 712.164000 ;
  END
 END pi1[95]
 PIN pi1[96]
  DIRECTION OUTPUT ;
  USE SIGNAL ;
  PORT
   LAYER M4 ;
   RECT 302.208000 712.332000 302.400000 712.356000 ;
  END
 END pi1[96]
 PIN pi1[97]
  DIRECTION OUTPUT ;
  USE SIGNAL ;
  PORT
   LAYER M4 ;
   RECT 302.208000 712.524000 302.400000 712.548000 ;
  END
 END pi1[97]
 PIN pi1[98]
  DIRECTION OUTPUT ;
  USE SIGNAL ;
  PORT
   LAYER M4 ;
   RECT 302.208000 712.716000 302.400000 712.740000 ;
  END
 END pi1[98]
 PIN pi1[99]
  DIRECTION OUTPUT ;
  USE SIGNAL ;
  PORT
   LAYER M4 ;
   RECT 302.208000 712.908000 302.400000 712.932000 ;
  END
 END pi1[99]
 PIN pi1[100]
  DIRECTION OUTPUT ;
  USE SIGNAL ;
  PORT
   LAYER M4 ;
   RECT 302.208000 713.100000 302.400000 713.124000 ;
  END
 END pi1[100]
 PIN pi1[101]
  DIRECTION OUTPUT ;
  USE SIGNAL ;
  PORT
   LAYER M4 ;
   RECT 302.208000 713.292000 302.400000 713.316000 ;
  END
 END pi1[101]
 PIN pi1[102]
  DIRECTION OUTPUT ;
  USE SIGNAL ;
  PORT
   LAYER M4 ;
   RECT 302.208000 713.484000 302.400000 713.508000 ;
  END
 END pi1[102]
 PIN pi1[103]
  DIRECTION OUTPUT ;
  USE SIGNAL ;
  PORT
   LAYER M4 ;
   RECT 302.208000 713.676000 302.400000 713.700000 ;
  END
 END pi1[103]
 PIN pi1[104]
  DIRECTION OUTPUT ;
  USE SIGNAL ;
  PORT
   LAYER M4 ;
   RECT 302.208000 713.868000 302.400000 713.892000 ;
  END
 END pi1[104]
 PIN pi1[105]
  DIRECTION OUTPUT ;
  USE SIGNAL ;
  PORT
   LAYER M4 ;
   RECT 302.208000 714.060000 302.400000 714.084000 ;
  END
 END pi1[105]
 PIN pi1[106]
  DIRECTION OUTPUT ;
  USE SIGNAL ;
  PORT
   LAYER M4 ;
   RECT 302.208000 714.252000 302.400000 714.276000 ;
  END
 END pi1[106]
 PIN pi1[107]
  DIRECTION OUTPUT ;
  USE SIGNAL ;
  PORT
   LAYER M4 ;
   RECT 302.208000 714.444000 302.400000 714.468000 ;
  END
 END pi1[107]
 PIN pi1[108]
  DIRECTION OUTPUT ;
  USE SIGNAL ;
  PORT
   LAYER M4 ;
   RECT 302.208000 714.636000 302.400000 714.660000 ;
  END
 END pi1[108]
 PIN pi1[109]
  DIRECTION OUTPUT ;
  USE SIGNAL ;
  PORT
   LAYER M4 ;
   RECT 302.208000 714.828000 302.400000 714.852000 ;
  END
 END pi1[109]
 PIN pi1[110]
  DIRECTION OUTPUT ;
  USE SIGNAL ;
  PORT
   LAYER M4 ;
   RECT 302.208000 715.020000 302.400000 715.044000 ;
  END
 END pi1[110]
 PIN pi1[111]
  DIRECTION OUTPUT ;
  USE SIGNAL ;
  PORT
   LAYER M4 ;
   RECT 302.208000 715.212000 302.400000 715.236000 ;
  END
 END pi1[111]
 PIN pi1[112]
  DIRECTION OUTPUT ;
  USE SIGNAL ;
  PORT
   LAYER M4 ;
   RECT 302.208000 715.404000 302.400000 715.428000 ;
  END
 END pi1[112]
 PIN pi1[113]
  DIRECTION OUTPUT ;
  USE SIGNAL ;
  PORT
   LAYER M4 ;
   RECT 302.208000 715.596000 302.400000 715.620000 ;
  END
 END pi1[113]
 PIN pi1[114]
  DIRECTION OUTPUT ;
  USE SIGNAL ;
  PORT
   LAYER M4 ;
   RECT 302.208000 715.788000 302.400000 715.812000 ;
  END
 END pi1[114]
 PIN pi1[115]
  DIRECTION OUTPUT ;
  USE SIGNAL ;
  PORT
   LAYER M4 ;
   RECT 302.208000 715.980000 302.400000 716.004000 ;
  END
 END pi1[115]
 PIN pi1[116]
  DIRECTION OUTPUT ;
  USE SIGNAL ;
  PORT
   LAYER M4 ;
   RECT 302.208000 716.172000 302.400000 716.196000 ;
  END
 END pi1[116]
 PIN pi1[117]
  DIRECTION OUTPUT ;
  USE SIGNAL ;
  PORT
   LAYER M4 ;
   RECT 302.208000 716.364000 302.400000 716.388000 ;
  END
 END pi1[117]
 PIN pi1[118]
  DIRECTION OUTPUT ;
  USE SIGNAL ;
  PORT
   LAYER M4 ;
   RECT 302.208000 716.556000 302.400000 716.580000 ;
  END
 END pi1[118]
 PIN pi1[119]
  DIRECTION OUTPUT ;
  USE SIGNAL ;
  PORT
   LAYER M4 ;
   RECT 302.208000 716.748000 302.400000 716.772000 ;
  END
 END pi1[119]
 PIN pi1[120]
  DIRECTION OUTPUT ;
  USE SIGNAL ;
  PORT
   LAYER M4 ;
   RECT 302.208000 716.940000 302.400000 716.964000 ;
  END
 END pi1[120]
 PIN pi1[121]
  DIRECTION OUTPUT ;
  USE SIGNAL ;
  PORT
   LAYER M4 ;
   RECT 302.208000 717.132000 302.400000 717.156000 ;
  END
 END pi1[121]
 PIN pi1[122]
  DIRECTION OUTPUT ;
  USE SIGNAL ;
  PORT
   LAYER M4 ;
   RECT 302.208000 717.324000 302.400000 717.348000 ;
  END
 END pi1[122]
 PIN pi1[123]
  DIRECTION OUTPUT ;
  USE SIGNAL ;
  PORT
   LAYER M4 ;
   RECT 302.208000 717.516000 302.400000 717.540000 ;
  END
 END pi1[123]
 PIN pi1[124]
  DIRECTION OUTPUT ;
  USE SIGNAL ;
  PORT
   LAYER M4 ;
   RECT 302.208000 717.708000 302.400000 717.732000 ;
  END
 END pi1[124]
 PIN pi1[125]
  DIRECTION OUTPUT ;
  USE SIGNAL ;
  PORT
   LAYER M4 ;
   RECT 302.208000 717.900000 302.400000 717.924000 ;
  END
 END pi1[125]
 PIN pi1[126]
  DIRECTION OUTPUT ;
  USE SIGNAL ;
  PORT
   LAYER M4 ;
   RECT 302.208000 718.092000 302.400000 718.116000 ;
  END
 END pi1[126]
 PIN pi1[127]
  DIRECTION OUTPUT ;
  USE SIGNAL ;
  PORT
   LAYER M4 ;
   RECT 302.208000 718.284000 302.400000 718.308000 ;
  END
 END pi1[127]
 PIN pi1[128]
  DIRECTION OUTPUT ;
  USE SIGNAL ;
  PORT
   LAYER M4 ;
   RECT 302.208000 718.476000 302.400000 718.500000 ;
  END
 END pi1[128]
 PIN pi1[129]
  DIRECTION OUTPUT ;
  USE SIGNAL ;
  PORT
   LAYER M4 ;
   RECT 302.208000 718.668000 302.400000 718.692000 ;
  END
 END pi1[129]
 PIN pi1[130]
  DIRECTION OUTPUT ;
  USE SIGNAL ;
  PORT
   LAYER M4 ;
   RECT 302.208000 718.860000 302.400000 718.884000 ;
  END
 END pi1[130]
 PIN pi1[131]
  DIRECTION OUTPUT ;
  USE SIGNAL ;
  PORT
   LAYER M4 ;
   RECT 302.208000 719.052000 302.400000 719.076000 ;
  END
 END pi1[131]
 PIN pi1[132]
  DIRECTION OUTPUT ;
  USE SIGNAL ;
  PORT
   LAYER M4 ;
   RECT 302.208000 719.244000 302.400000 719.268000 ;
  END
 END pi1[132]
 PIN pi1[133]
  DIRECTION OUTPUT ;
  USE SIGNAL ;
  PORT
   LAYER M4 ;
   RECT 302.208000 719.436000 302.400000 719.460000 ;
  END
 END pi1[133]
 PIN pi1[134]
  DIRECTION OUTPUT ;
  USE SIGNAL ;
  PORT
   LAYER M4 ;
   RECT 302.208000 719.628000 302.400000 719.652000 ;
  END
 END pi1[134]
 PIN pi1[135]
  DIRECTION OUTPUT ;
  USE SIGNAL ;
  PORT
   LAYER M4 ;
   RECT 302.208000 719.820000 302.400000 719.844000 ;
  END
 END pi1[135]
 PIN pi1[136]
  DIRECTION OUTPUT ;
  USE SIGNAL ;
  PORT
   LAYER M4 ;
   RECT 302.208000 720.012000 302.400000 720.036000 ;
  END
 END pi1[136]
 PIN pi1[137]
  DIRECTION OUTPUT ;
  USE SIGNAL ;
  PORT
   LAYER M4 ;
   RECT 302.208000 720.204000 302.400000 720.228000 ;
  END
 END pi1[137]
 PIN pi1[138]
  DIRECTION OUTPUT ;
  USE SIGNAL ;
  PORT
   LAYER M4 ;
   RECT 302.208000 720.396000 302.400000 720.420000 ;
  END
 END pi1[138]
 PIN pi1[139]
  DIRECTION OUTPUT ;
  USE SIGNAL ;
  PORT
   LAYER M4 ;
   RECT 302.208000 720.588000 302.400000 720.612000 ;
  END
 END pi1[139]
 PIN pi1[140]
  DIRECTION OUTPUT ;
  USE SIGNAL ;
  PORT
   LAYER M4 ;
   RECT 302.208000 720.780000 302.400000 720.804000 ;
  END
 END pi1[140]
 PIN pi1[141]
  DIRECTION OUTPUT ;
  USE SIGNAL ;
  PORT
   LAYER M4 ;
   RECT 302.208000 720.972000 302.400000 720.996000 ;
  END
 END pi1[141]
 PIN pi1[142]
  DIRECTION OUTPUT ;
  USE SIGNAL ;
  PORT
   LAYER M4 ;
   RECT 302.208000 721.164000 302.400000 721.188000 ;
  END
 END pi1[142]
 PIN pi1[143]
  DIRECTION OUTPUT ;
  USE SIGNAL ;
  PORT
   LAYER M4 ;
   RECT 302.208000 721.356000 302.400000 721.380000 ;
  END
 END pi1[143]
 PIN pi1[144]
  DIRECTION OUTPUT ;
  USE SIGNAL ;
  PORT
   LAYER M4 ;
   RECT 302.208000 721.548000 302.400000 721.572000 ;
  END
 END pi1[144]
 PIN pi1[145]
  DIRECTION OUTPUT ;
  USE SIGNAL ;
  PORT
   LAYER M4 ;
   RECT 302.208000 721.740000 302.400000 721.764000 ;
  END
 END pi1[145]
 PIN pi1[146]
  DIRECTION OUTPUT ;
  USE SIGNAL ;
  PORT
   LAYER M4 ;
   RECT 302.208000 721.932000 302.400000 721.956000 ;
  END
 END pi1[146]
 PIN pi1[147]
  DIRECTION OUTPUT ;
  USE SIGNAL ;
  PORT
   LAYER M4 ;
   RECT 302.208000 722.124000 302.400000 722.148000 ;
  END
 END pi1[147]
 PIN pi1[148]
  DIRECTION OUTPUT ;
  USE SIGNAL ;
  PORT
   LAYER M4 ;
   RECT 302.208000 722.316000 302.400000 722.340000 ;
  END
 END pi1[148]
 PIN pi1[149]
  DIRECTION OUTPUT ;
  USE SIGNAL ;
  PORT
   LAYER M4 ;
   RECT 302.208000 722.508000 302.400000 722.532000 ;
  END
 END pi1[149]
 PIN pi1[150]
  DIRECTION OUTPUT ;
  USE SIGNAL ;
  PORT
   LAYER M4 ;
   RECT 302.208000 722.700000 302.400000 722.724000 ;
  END
 END pi1[150]
 PIN pi1[151]
  DIRECTION OUTPUT ;
  USE SIGNAL ;
  PORT
   LAYER M4 ;
   RECT 302.208000 722.892000 302.400000 722.916000 ;
  END
 END pi1[151]
 PIN pi1[152]
  DIRECTION OUTPUT ;
  USE SIGNAL ;
  PORT
   LAYER M4 ;
   RECT 302.208000 723.084000 302.400000 723.108000 ;
  END
 END pi1[152]
 PIN pi1[153]
  DIRECTION OUTPUT ;
  USE SIGNAL ;
  PORT
   LAYER M4 ;
   RECT 302.208000 723.276000 302.400000 723.300000 ;
  END
 END pi1[153]
 PIN pi1[154]
  DIRECTION OUTPUT ;
  USE SIGNAL ;
  PORT
   LAYER M4 ;
   RECT 302.208000 723.468000 302.400000 723.492000 ;
  END
 END pi1[154]
 PIN pi1[155]
  DIRECTION OUTPUT ;
  USE SIGNAL ;
  PORT
   LAYER M4 ;
   RECT 302.208000 723.660000 302.400000 723.684000 ;
  END
 END pi1[155]
 PIN pi1[156]
  DIRECTION OUTPUT ;
  USE SIGNAL ;
  PORT
   LAYER M4 ;
   RECT 302.208000 723.852000 302.400000 723.876000 ;
  END
 END pi1[156]
 PIN pi1[157]
  DIRECTION OUTPUT ;
  USE SIGNAL ;
  PORT
   LAYER M4 ;
   RECT 302.208000 724.044000 302.400000 724.068000 ;
  END
 END pi1[157]
 PIN pi1[158]
  DIRECTION OUTPUT ;
  USE SIGNAL ;
  PORT
   LAYER M4 ;
   RECT 302.208000 724.236000 302.400000 724.260000 ;
  END
 END pi1[158]
 PIN pi1[159]
  DIRECTION OUTPUT ;
  USE SIGNAL ;
  PORT
   LAYER M4 ;
   RECT 302.208000 724.428000 302.400000 724.452000 ;
  END
 END pi1[159]
 PIN pi1[160]
  DIRECTION OUTPUT ;
  USE SIGNAL ;
  PORT
   LAYER M4 ;
   RECT 302.208000 724.620000 302.400000 724.644000 ;
  END
 END pi1[160]
 PIN pi1[161]
  DIRECTION OUTPUT ;
  USE SIGNAL ;
  PORT
   LAYER M4 ;
   RECT 302.208000 724.812000 302.400000 724.836000 ;
  END
 END pi1[161]
 PIN pi1[162]
  DIRECTION OUTPUT ;
  USE SIGNAL ;
  PORT
   LAYER M4 ;
   RECT 302.208000 725.004000 302.400000 725.028000 ;
  END
 END pi1[162]
 PIN pi1[163]
  DIRECTION OUTPUT ;
  USE SIGNAL ;
  PORT
   LAYER M4 ;
   RECT 302.208000 725.196000 302.400000 725.220000 ;
  END
 END pi1[163]
 PIN pi1[164]
  DIRECTION OUTPUT ;
  USE SIGNAL ;
  PORT
   LAYER M4 ;
   RECT 302.208000 725.388000 302.400000 725.412000 ;
  END
 END pi1[164]
 PIN pi1[165]
  DIRECTION OUTPUT ;
  USE SIGNAL ;
  PORT
   LAYER M4 ;
   RECT 302.208000 725.580000 302.400000 725.604000 ;
  END
 END pi1[165]
 PIN pi1[166]
  DIRECTION OUTPUT ;
  USE SIGNAL ;
  PORT
   LAYER M4 ;
   RECT 302.208000 725.772000 302.400000 725.796000 ;
  END
 END pi1[166]
 PIN pi1[167]
  DIRECTION OUTPUT ;
  USE SIGNAL ;
  PORT
   LAYER M4 ;
   RECT 302.208000 725.964000 302.400000 725.988000 ;
  END
 END pi1[167]
 PIN pi1[168]
  DIRECTION OUTPUT ;
  USE SIGNAL ;
  PORT
   LAYER M4 ;
   RECT 302.208000 726.156000 302.400000 726.180000 ;
  END
 END pi1[168]
 PIN pi1[169]
  DIRECTION OUTPUT ;
  USE SIGNAL ;
  PORT
   LAYER M4 ;
   RECT 302.208000 726.348000 302.400000 726.372000 ;
  END
 END pi1[169]
 PIN pi1[170]
  DIRECTION OUTPUT ;
  USE SIGNAL ;
  PORT
   LAYER M4 ;
   RECT 302.208000 726.540000 302.400000 726.564000 ;
  END
 END pi1[170]
 PIN pi1[171]
  DIRECTION OUTPUT ;
  USE SIGNAL ;
  PORT
   LAYER M4 ;
   RECT 302.208000 726.732000 302.400000 726.756000 ;
  END
 END pi1[171]
 PIN pi1[172]
  DIRECTION OUTPUT ;
  USE SIGNAL ;
  PORT
   LAYER M4 ;
   RECT 302.208000 726.924000 302.400000 726.948000 ;
  END
 END pi1[172]
 PIN pi1[173]
  DIRECTION OUTPUT ;
  USE SIGNAL ;
  PORT
   LAYER M4 ;
   RECT 302.208000 727.116000 302.400000 727.140000 ;
  END
 END pi1[173]
 PIN pi1[174]
  DIRECTION OUTPUT ;
  USE SIGNAL ;
  PORT
   LAYER M4 ;
   RECT 302.208000 727.308000 302.400000 727.332000 ;
  END
 END pi1[174]
 PIN pi1[175]
  DIRECTION OUTPUT ;
  USE SIGNAL ;
  PORT
   LAYER M4 ;
   RECT 302.208000 727.500000 302.400000 727.524000 ;
  END
 END pi1[175]
 PIN pi1[176]
  DIRECTION OUTPUT ;
  USE SIGNAL ;
  PORT
   LAYER M4 ;
   RECT 302.208000 727.692000 302.400000 727.716000 ;
  END
 END pi1[176]
 PIN pi1[177]
  DIRECTION OUTPUT ;
  USE SIGNAL ;
  PORT
   LAYER M4 ;
   RECT 302.208000 727.884000 302.400000 727.908000 ;
  END
 END pi1[177]
 PIN pi1[178]
  DIRECTION OUTPUT ;
  USE SIGNAL ;
  PORT
   LAYER M4 ;
   RECT 302.208000 728.076000 302.400000 728.100000 ;
  END
 END pi1[178]
 PIN pi1[179]
  DIRECTION OUTPUT ;
  USE SIGNAL ;
  PORT
   LAYER M4 ;
   RECT 302.208000 728.268000 302.400000 728.292000 ;
  END
 END pi1[179]
 PIN pi1[180]
  DIRECTION OUTPUT ;
  USE SIGNAL ;
  PORT
   LAYER M4 ;
   RECT 302.208000 728.460000 302.400000 728.484000 ;
  END
 END pi1[180]
 PIN pi1[181]
  DIRECTION OUTPUT ;
  USE SIGNAL ;
  PORT
   LAYER M4 ;
   RECT 302.208000 728.652000 302.400000 728.676000 ;
  END
 END pi1[181]
 PIN pi1[182]
  DIRECTION OUTPUT ;
  USE SIGNAL ;
  PORT
   LAYER M4 ;
   RECT 302.208000 728.844000 302.400000 728.868000 ;
  END
 END pi1[182]
 PIN pi1[183]
  DIRECTION OUTPUT ;
  USE SIGNAL ;
  PORT
   LAYER M4 ;
   RECT 302.208000 729.036000 302.400000 729.060000 ;
  END
 END pi1[183]
 PIN pi1[184]
  DIRECTION OUTPUT ;
  USE SIGNAL ;
  PORT
   LAYER M4 ;
   RECT 302.208000 729.228000 302.400000 729.252000 ;
  END
 END pi1[184]
 PIN pi1[185]
  DIRECTION OUTPUT ;
  USE SIGNAL ;
  PORT
   LAYER M4 ;
   RECT 302.208000 729.420000 302.400000 729.444000 ;
  END
 END pi1[185]
 PIN pi1[186]
  DIRECTION OUTPUT ;
  USE SIGNAL ;
  PORT
   LAYER M4 ;
   RECT 302.208000 729.612000 302.400000 729.636000 ;
  END
 END pi1[186]
 PIN pi1[187]
  DIRECTION OUTPUT ;
  USE SIGNAL ;
  PORT
   LAYER M4 ;
   RECT 302.208000 729.804000 302.400000 729.828000 ;
  END
 END pi1[187]
 PIN pi1[188]
  DIRECTION OUTPUT ;
  USE SIGNAL ;
  PORT
   LAYER M4 ;
   RECT 302.208000 729.996000 302.400000 730.020000 ;
  END
 END pi1[188]
 PIN pi1[189]
  DIRECTION OUTPUT ;
  USE SIGNAL ;
  PORT
   LAYER M4 ;
   RECT 302.208000 730.188000 302.400000 730.212000 ;
  END
 END pi1[189]
 PIN pi1[190]
  DIRECTION OUTPUT ;
  USE SIGNAL ;
  PORT
   LAYER M4 ;
   RECT 302.208000 730.380000 302.400000 730.404000 ;
  END
 END pi1[190]
 PIN pi1[191]
  DIRECTION OUTPUT ;
  USE SIGNAL ;
  PORT
   LAYER M4 ;
   RECT 302.208000 730.572000 302.400000 730.596000 ;
  END
 END pi1[191]
 PIN pi1[192]
  DIRECTION OUTPUT ;
  USE SIGNAL ;
  PORT
   LAYER M4 ;
   RECT 302.208000 730.764000 302.400000 730.788000 ;
  END
 END pi1[192]
 PIN pi1[193]
  DIRECTION OUTPUT ;
  USE SIGNAL ;
  PORT
   LAYER M4 ;
   RECT 302.208000 730.956000 302.400000 730.980000 ;
  END
 END pi1[193]
 PIN pi1[194]
  DIRECTION OUTPUT ;
  USE SIGNAL ;
  PORT
   LAYER M4 ;
   RECT 302.208000 731.148000 302.400000 731.172000 ;
  END
 END pi1[194]
 PIN pi1[195]
  DIRECTION OUTPUT ;
  USE SIGNAL ;
  PORT
   LAYER M4 ;
   RECT 302.208000 731.340000 302.400000 731.364000 ;
  END
 END pi1[195]
 PIN pi1[196]
  DIRECTION OUTPUT ;
  USE SIGNAL ;
  PORT
   LAYER M4 ;
   RECT 302.208000 731.532000 302.400000 731.556000 ;
  END
 END pi1[196]
 PIN pi1[197]
  DIRECTION OUTPUT ;
  USE SIGNAL ;
  PORT
   LAYER M4 ;
   RECT 302.208000 731.724000 302.400000 731.748000 ;
  END
 END pi1[197]
 PIN pi1[198]
  DIRECTION OUTPUT ;
  USE SIGNAL ;
  PORT
   LAYER M4 ;
   RECT 302.208000 731.916000 302.400000 731.940000 ;
  END
 END pi1[198]
 PIN pi1[199]
  DIRECTION OUTPUT ;
  USE SIGNAL ;
  PORT
   LAYER M4 ;
   RECT 302.208000 732.108000 302.400000 732.132000 ;
  END
 END pi1[199]
 PIN pi1[200]
  DIRECTION OUTPUT ;
  USE SIGNAL ;
  PORT
   LAYER M4 ;
   RECT 302.208000 732.300000 302.400000 732.324000 ;
  END
 END pi1[200]
 PIN pi1[201]
  DIRECTION OUTPUT ;
  USE SIGNAL ;
  PORT
   LAYER M4 ;
   RECT 302.208000 732.492000 302.400000 732.516000 ;
  END
 END pi1[201]
 PIN pi1[202]
  DIRECTION OUTPUT ;
  USE SIGNAL ;
  PORT
   LAYER M4 ;
   RECT 302.208000 732.684000 302.400000 732.708000 ;
  END
 END pi1[202]
 PIN pi1[203]
  DIRECTION OUTPUT ;
  USE SIGNAL ;
  PORT
   LAYER M4 ;
   RECT 302.208000 732.876000 302.400000 732.900000 ;
  END
 END pi1[203]
 PIN pi1[204]
  DIRECTION OUTPUT ;
  USE SIGNAL ;
  PORT
   LAYER M4 ;
   RECT 302.208000 733.068000 302.400000 733.092000 ;
  END
 END pi1[204]
 PIN pi1[205]
  DIRECTION OUTPUT ;
  USE SIGNAL ;
  PORT
   LAYER M4 ;
   RECT 302.208000 733.260000 302.400000 733.284000 ;
  END
 END pi1[205]
 PIN pi1[206]
  DIRECTION OUTPUT ;
  USE SIGNAL ;
  PORT
   LAYER M4 ;
   RECT 302.208000 733.452000 302.400000 733.476000 ;
  END
 END pi1[206]
 PIN pi1[207]
  DIRECTION OUTPUT ;
  USE SIGNAL ;
  PORT
   LAYER M4 ;
   RECT 302.208000 733.644000 302.400000 733.668000 ;
  END
 END pi1[207]
 PIN pi1[208]
  DIRECTION OUTPUT ;
  USE SIGNAL ;
  PORT
   LAYER M4 ;
   RECT 302.208000 733.836000 302.400000 733.860000 ;
  END
 END pi1[208]
 PIN pi1[209]
  DIRECTION OUTPUT ;
  USE SIGNAL ;
  PORT
   LAYER M4 ;
   RECT 302.208000 734.028000 302.400000 734.052000 ;
  END
 END pi1[209]
 PIN pi1[210]
  DIRECTION OUTPUT ;
  USE SIGNAL ;
  PORT
   LAYER M4 ;
   RECT 302.208000 734.220000 302.400000 734.244000 ;
  END
 END pi1[210]
 PIN pi1[211]
  DIRECTION OUTPUT ;
  USE SIGNAL ;
  PORT
   LAYER M4 ;
   RECT 302.208000 734.412000 302.400000 734.436000 ;
  END
 END pi1[211]
 PIN pi1[212]
  DIRECTION OUTPUT ;
  USE SIGNAL ;
  PORT
   LAYER M4 ;
   RECT 302.208000 734.604000 302.400000 734.628000 ;
  END
 END pi1[212]
 PIN pi1[213]
  DIRECTION OUTPUT ;
  USE SIGNAL ;
  PORT
   LAYER M4 ;
   RECT 302.208000 734.796000 302.400000 734.820000 ;
  END
 END pi1[213]
 PIN pi1[214]
  DIRECTION OUTPUT ;
  USE SIGNAL ;
  PORT
   LAYER M4 ;
   RECT 302.208000 734.988000 302.400000 735.012000 ;
  END
 END pi1[214]
 PIN pi1[215]
  DIRECTION OUTPUT ;
  USE SIGNAL ;
  PORT
   LAYER M4 ;
   RECT 302.208000 735.180000 302.400000 735.204000 ;
  END
 END pi1[215]
 PIN pi1[216]
  DIRECTION OUTPUT ;
  USE SIGNAL ;
  PORT
   LAYER M4 ;
   RECT 302.208000 735.372000 302.400000 735.396000 ;
  END
 END pi1[216]
 PIN pi1[217]
  DIRECTION OUTPUT ;
  USE SIGNAL ;
  PORT
   LAYER M4 ;
   RECT 302.208000 735.564000 302.400000 735.588000 ;
  END
 END pi1[217]
 PIN pi1[218]
  DIRECTION OUTPUT ;
  USE SIGNAL ;
  PORT
   LAYER M4 ;
   RECT 302.208000 735.756000 302.400000 735.780000 ;
  END
 END pi1[218]
 PIN pi1[219]
  DIRECTION OUTPUT ;
  USE SIGNAL ;
  PORT
   LAYER M4 ;
   RECT 302.208000 735.948000 302.400000 735.972000 ;
  END
 END pi1[219]
 PIN pi1[220]
  DIRECTION OUTPUT ;
  USE SIGNAL ;
  PORT
   LAYER M4 ;
   RECT 302.208000 736.140000 302.400000 736.164000 ;
  END
 END pi1[220]
 PIN pi1[221]
  DIRECTION OUTPUT ;
  USE SIGNAL ;
  PORT
   LAYER M4 ;
   RECT 302.208000 736.332000 302.400000 736.356000 ;
  END
 END pi1[221]
 PIN pi1[222]
  DIRECTION OUTPUT ;
  USE SIGNAL ;
  PORT
   LAYER M4 ;
   RECT 302.208000 736.524000 302.400000 736.548000 ;
  END
 END pi1[222]
 PIN pi1[223]
  DIRECTION OUTPUT ;
  USE SIGNAL ;
  PORT
   LAYER M4 ;
   RECT 302.208000 736.716000 302.400000 736.740000 ;
  END
 END pi1[223]
 PIN pi1[224]
  DIRECTION OUTPUT ;
  USE SIGNAL ;
  PORT
   LAYER M4 ;
   RECT 302.208000 736.908000 302.400000 736.932000 ;
  END
 END pi1[224]
 PIN pi1[225]
  DIRECTION OUTPUT ;
  USE SIGNAL ;
  PORT
   LAYER M4 ;
   RECT 302.208000 737.100000 302.400000 737.124000 ;
  END
 END pi1[225]
 PIN pi1[226]
  DIRECTION OUTPUT ;
  USE SIGNAL ;
  PORT
   LAYER M4 ;
   RECT 302.208000 737.292000 302.400000 737.316000 ;
  END
 END pi1[226]
 PIN pi1[227]
  DIRECTION OUTPUT ;
  USE SIGNAL ;
  PORT
   LAYER M4 ;
   RECT 302.208000 737.484000 302.400000 737.508000 ;
  END
 END pi1[227]
 PIN pi1[228]
  DIRECTION OUTPUT ;
  USE SIGNAL ;
  PORT
   LAYER M4 ;
   RECT 302.208000 737.676000 302.400000 737.700000 ;
  END
 END pi1[228]
 PIN pi1[229]
  DIRECTION OUTPUT ;
  USE SIGNAL ;
  PORT
   LAYER M4 ;
   RECT 302.208000 737.868000 302.400000 737.892000 ;
  END
 END pi1[229]
 PIN pi1[230]
  DIRECTION OUTPUT ;
  USE SIGNAL ;
  PORT
   LAYER M4 ;
   RECT 302.208000 738.060000 302.400000 738.084000 ;
  END
 END pi1[230]
 PIN pi1[231]
  DIRECTION OUTPUT ;
  USE SIGNAL ;
  PORT
   LAYER M4 ;
   RECT 302.208000 738.252000 302.400000 738.276000 ;
  END
 END pi1[231]
 PIN pi1[232]
  DIRECTION OUTPUT ;
  USE SIGNAL ;
  PORT
   LAYER M4 ;
   RECT 302.208000 738.444000 302.400000 738.468000 ;
  END
 END pi1[232]
 PIN pi1[233]
  DIRECTION OUTPUT ;
  USE SIGNAL ;
  PORT
   LAYER M4 ;
   RECT 302.208000 738.636000 302.400000 738.660000 ;
  END
 END pi1[233]
 PIN pi1[234]
  DIRECTION OUTPUT ;
  USE SIGNAL ;
  PORT
   LAYER M4 ;
   RECT 302.208000 738.828000 302.400000 738.852000 ;
  END
 END pi1[234]
 PIN pi1[235]
  DIRECTION OUTPUT ;
  USE SIGNAL ;
  PORT
   LAYER M4 ;
   RECT 302.208000 739.020000 302.400000 739.044000 ;
  END
 END pi1[235]
 PIN pi1[236]
  DIRECTION OUTPUT ;
  USE SIGNAL ;
  PORT
   LAYER M4 ;
   RECT 302.208000 739.212000 302.400000 739.236000 ;
  END
 END pi1[236]
 PIN pi1[237]
  DIRECTION OUTPUT ;
  USE SIGNAL ;
  PORT
   LAYER M4 ;
   RECT 302.208000 739.404000 302.400000 739.428000 ;
  END
 END pi1[237]
 PIN pi1[238]
  DIRECTION OUTPUT ;
  USE SIGNAL ;
  PORT
   LAYER M4 ;
   RECT 302.208000 739.596000 302.400000 739.620000 ;
  END
 END pi1[238]
 PIN pi1[239]
  DIRECTION OUTPUT ;
  USE SIGNAL ;
  PORT
   LAYER M4 ;
   RECT 302.208000 739.788000 302.400000 739.812000 ;
  END
 END pi1[239]
 PIN pi1[240]
  DIRECTION OUTPUT ;
  USE SIGNAL ;
  PORT
   LAYER M4 ;
   RECT 302.208000 739.980000 302.400000 740.004000 ;
  END
 END pi1[240]
 PIN pi1[241]
  DIRECTION OUTPUT ;
  USE SIGNAL ;
  PORT
   LAYER M4 ;
   RECT 302.208000 740.172000 302.400000 740.196000 ;
  END
 END pi1[241]
 PIN pi1[242]
  DIRECTION OUTPUT ;
  USE SIGNAL ;
  PORT
   LAYER M4 ;
   RECT 302.208000 740.364000 302.400000 740.388000 ;
  END
 END pi1[242]
 PIN pi1[243]
  DIRECTION OUTPUT ;
  USE SIGNAL ;
  PORT
   LAYER M4 ;
   RECT 302.208000 740.556000 302.400000 740.580000 ;
  END
 END pi1[243]
 PIN pi1[244]
  DIRECTION OUTPUT ;
  USE SIGNAL ;
  PORT
   LAYER M4 ;
   RECT 302.208000 740.748000 302.400000 740.772000 ;
  END
 END pi1[244]
 PIN pi1[245]
  DIRECTION OUTPUT ;
  USE SIGNAL ;
  PORT
   LAYER M4 ;
   RECT 302.208000 740.940000 302.400000 740.964000 ;
  END
 END pi1[245]
 PIN pi1[246]
  DIRECTION OUTPUT ;
  USE SIGNAL ;
  PORT
   LAYER M4 ;
   RECT 302.208000 741.132000 302.400000 741.156000 ;
  END
 END pi1[246]
 PIN pi1[247]
  DIRECTION OUTPUT ;
  USE SIGNAL ;
  PORT
   LAYER M4 ;
   RECT 302.208000 741.324000 302.400000 741.348000 ;
  END
 END pi1[247]
 PIN pi1[248]
  DIRECTION OUTPUT ;
  USE SIGNAL ;
  PORT
   LAYER M4 ;
   RECT 302.208000 741.516000 302.400000 741.540000 ;
  END
 END pi1[248]
 PIN pi1[249]
  DIRECTION OUTPUT ;
  USE SIGNAL ;
  PORT
   LAYER M4 ;
   RECT 302.208000 741.708000 302.400000 741.732000 ;
  END
 END pi1[249]
 PIN pi1[250]
  DIRECTION OUTPUT ;
  USE SIGNAL ;
  PORT
   LAYER M4 ;
   RECT 302.208000 741.900000 302.400000 741.924000 ;
  END
 END pi1[250]
 PIN pi1[251]
  DIRECTION OUTPUT ;
  USE SIGNAL ;
  PORT
   LAYER M4 ;
   RECT 302.208000 742.092000 302.400000 742.116000 ;
  END
 END pi1[251]
 PIN pi1[252]
  DIRECTION OUTPUT ;
  USE SIGNAL ;
  PORT
   LAYER M4 ;
   RECT 302.208000 742.284000 302.400000 742.308000 ;
  END
 END pi1[252]
 PIN pi1[253]
  DIRECTION OUTPUT ;
  USE SIGNAL ;
  PORT
   LAYER M4 ;
   RECT 302.208000 742.476000 302.400000 742.500000 ;
  END
 END pi1[253]
 PIN pi1[254]
  DIRECTION OUTPUT ;
  USE SIGNAL ;
  PORT
   LAYER M4 ;
   RECT 302.208000 742.668000 302.400000 742.692000 ;
  END
 END pi1[254]
 PIN pi1[255]
  DIRECTION OUTPUT ;
  USE SIGNAL ;
  PORT
   LAYER M4 ;
   RECT 302.208000 742.860000 302.400000 742.884000 ;
  END
 END pi1[255]
 PIN pi1[256]
  DIRECTION OUTPUT ;
  USE SIGNAL ;
  PORT
   LAYER M4 ;
   RECT 302.208000 743.052000 302.400000 743.076000 ;
  END
 END pi1[256]
 PIN pi1[257]
  DIRECTION OUTPUT ;
  USE SIGNAL ;
  PORT
   LAYER M4 ;
   RECT 302.208000 743.244000 302.400000 743.268000 ;
  END
 END pi1[257]
 PIN pi1[258]
  DIRECTION OUTPUT ;
  USE SIGNAL ;
  PORT
   LAYER M4 ;
   RECT 302.208000 743.436000 302.400000 743.460000 ;
  END
 END pi1[258]
 PIN pi1[259]
  DIRECTION OUTPUT ;
  USE SIGNAL ;
  PORT
   LAYER M4 ;
   RECT 302.208000 743.628000 302.400000 743.652000 ;
  END
 END pi1[259]
 PIN pi1[260]
  DIRECTION OUTPUT ;
  USE SIGNAL ;
  PORT
   LAYER M4 ;
   RECT 302.208000 743.820000 302.400000 743.844000 ;
  END
 END pi1[260]
 PIN pi1[261]
  DIRECTION OUTPUT ;
  USE SIGNAL ;
  PORT
   LAYER M4 ;
   RECT 302.208000 744.012000 302.400000 744.036000 ;
  END
 END pi1[261]
 PIN pi1[262]
  DIRECTION OUTPUT ;
  USE SIGNAL ;
  PORT
   LAYER M4 ;
   RECT 302.208000 744.204000 302.400000 744.228000 ;
  END
 END pi1[262]
 PIN pi1[263]
  DIRECTION OUTPUT ;
  USE SIGNAL ;
  PORT
   LAYER M4 ;
   RECT 302.208000 744.396000 302.400000 744.420000 ;
  END
 END pi1[263]
 PIN pi1[264]
  DIRECTION OUTPUT ;
  USE SIGNAL ;
  PORT
   LAYER M4 ;
   RECT 302.208000 744.588000 302.400000 744.612000 ;
  END
 END pi1[264]
 PIN pi1[265]
  DIRECTION OUTPUT ;
  USE SIGNAL ;
  PORT
   LAYER M4 ;
   RECT 302.208000 744.780000 302.400000 744.804000 ;
  END
 END pi1[265]
 PIN pi1[266]
  DIRECTION OUTPUT ;
  USE SIGNAL ;
  PORT
   LAYER M4 ;
   RECT 302.208000 744.972000 302.400000 744.996000 ;
  END
 END pi1[266]
 PIN pi1[267]
  DIRECTION OUTPUT ;
  USE SIGNAL ;
  PORT
   LAYER M4 ;
   RECT 302.208000 745.164000 302.400000 745.188000 ;
  END
 END pi1[267]
 PIN pi1[268]
  DIRECTION OUTPUT ;
  USE SIGNAL ;
  PORT
   LAYER M4 ;
   RECT 302.208000 745.356000 302.400000 745.380000 ;
  END
 END pi1[268]
 PIN pi1[269]
  DIRECTION OUTPUT ;
  USE SIGNAL ;
  PORT
   LAYER M4 ;
   RECT 302.208000 745.548000 302.400000 745.572000 ;
  END
 END pi1[269]
 PIN pi1[270]
  DIRECTION OUTPUT ;
  USE SIGNAL ;
  PORT
   LAYER M4 ;
   RECT 302.208000 745.740000 302.400000 745.764000 ;
  END
 END pi1[270]
 PIN pi1[271]
  DIRECTION OUTPUT ;
  USE SIGNAL ;
  PORT
   LAYER M4 ;
   RECT 302.208000 745.932000 302.400000 745.956000 ;
  END
 END pi1[271]
 PIN pi1[272]
  DIRECTION OUTPUT ;
  USE SIGNAL ;
  PORT
   LAYER M4 ;
   RECT 302.208000 746.124000 302.400000 746.148000 ;
  END
 END pi1[272]
 PIN pi1[273]
  DIRECTION OUTPUT ;
  USE SIGNAL ;
  PORT
   LAYER M4 ;
   RECT 302.208000 746.316000 302.400000 746.340000 ;
  END
 END pi1[273]
 PIN pi1[274]
  DIRECTION OUTPUT ;
  USE SIGNAL ;
  PORT
   LAYER M4 ;
   RECT 302.208000 746.508000 302.400000 746.532000 ;
  END
 END pi1[274]
 PIN pi1[275]
  DIRECTION OUTPUT ;
  USE SIGNAL ;
  PORT
   LAYER M4 ;
   RECT 302.208000 746.700000 302.400000 746.724000 ;
  END
 END pi1[275]
 PIN pi1[276]
  DIRECTION OUTPUT ;
  USE SIGNAL ;
  PORT
   LAYER M4 ;
   RECT 302.208000 746.892000 302.400000 746.916000 ;
  END
 END pi1[276]
 PIN pi1[277]
  DIRECTION OUTPUT ;
  USE SIGNAL ;
  PORT
   LAYER M4 ;
   RECT 302.208000 747.084000 302.400000 747.108000 ;
  END
 END pi1[277]
 PIN pi1[278]
  DIRECTION OUTPUT ;
  USE SIGNAL ;
  PORT
   LAYER M4 ;
   RECT 302.208000 747.276000 302.400000 747.300000 ;
  END
 END pi1[278]
 PIN pi1[279]
  DIRECTION OUTPUT ;
  USE SIGNAL ;
  PORT
   LAYER M4 ;
   RECT 302.208000 747.468000 302.400000 747.492000 ;
  END
 END pi1[279]
 PIN pi1[280]
  DIRECTION OUTPUT ;
  USE SIGNAL ;
  PORT
   LAYER M4 ;
   RECT 302.208000 747.660000 302.400000 747.684000 ;
  END
 END pi1[280]
 PIN pi1[281]
  DIRECTION OUTPUT ;
  USE SIGNAL ;
  PORT
   LAYER M4 ;
   RECT 302.208000 747.852000 302.400000 747.876000 ;
  END
 END pi1[281]
 PIN pi1[282]
  DIRECTION OUTPUT ;
  USE SIGNAL ;
  PORT
   LAYER M4 ;
   RECT 302.208000 748.044000 302.400000 748.068000 ;
  END
 END pi1[282]
 PIN pi1[283]
  DIRECTION OUTPUT ;
  USE SIGNAL ;
  PORT
   LAYER M4 ;
   RECT 302.208000 748.236000 302.400000 748.260000 ;
  END
 END pi1[283]
 PIN pi1[284]
  DIRECTION OUTPUT ;
  USE SIGNAL ;
  PORT
   LAYER M4 ;
   RECT 302.208000 748.428000 302.400000 748.452000 ;
  END
 END pi1[284]
 PIN pi1[285]
  DIRECTION OUTPUT ;
  USE SIGNAL ;
  PORT
   LAYER M4 ;
   RECT 302.208000 748.620000 302.400000 748.644000 ;
  END
 END pi1[285]
 PIN pi1[286]
  DIRECTION OUTPUT ;
  USE SIGNAL ;
  PORT
   LAYER M4 ;
   RECT 302.208000 748.812000 302.400000 748.836000 ;
  END
 END pi1[286]
 PIN pi1[287]
  DIRECTION OUTPUT ;
  USE SIGNAL ;
  PORT
   LAYER M4 ;
   RECT 302.208000 749.004000 302.400000 749.028000 ;
  END
 END pi1[287]
 PIN pi1[288]
  DIRECTION OUTPUT ;
  USE SIGNAL ;
  PORT
   LAYER M4 ;
   RECT 302.208000 749.196000 302.400000 749.220000 ;
  END
 END pi1[288]
 PIN fh1[0]
  DIRECTION OUTPUT ;
  USE SIGNAL ;
  PORT
   LAYER M4 ;
   RECT 302.208000 749.388000 302.400000 749.412000 ;
  END
 END fh1[0]
 PIN fh1[1]
  DIRECTION OUTPUT ;
  USE SIGNAL ;
  PORT
   LAYER M4 ;
   RECT 302.208000 749.580000 302.400000 749.604000 ;
  END
 END fh1[1]
 PIN fh1[2]
  DIRECTION OUTPUT ;
  USE SIGNAL ;
  PORT
   LAYER M4 ;
   RECT 302.208000 749.772000 302.400000 749.796000 ;
  END
 END fh1[2]
 PIN fh1[3]
  DIRECTION OUTPUT ;
  USE SIGNAL ;
  PORT
   LAYER M4 ;
   RECT 302.208000 749.964000 302.400000 749.988000 ;
  END
 END fh1[3]
 PIN rh1[0]
  DIRECTION OUTPUT ;
  USE SIGNAL ;
  PORT
   LAYER M4 ;
   RECT 302.208000 750.156000 302.400000 750.180000 ;
  END
 END rh1[0]
 PIN rh1[1]
  DIRECTION OUTPUT ;
  USE SIGNAL ;
  PORT
   LAYER M4 ;
   RECT 302.208000 750.348000 302.400000 750.372000 ;
  END
 END rh1[1]
 PIN rh1[2]
  DIRECTION OUTPUT ;
  USE SIGNAL ;
  PORT
   LAYER M4 ;
   RECT 302.208000 750.540000 302.400000 750.564000 ;
  END
 END rh1[2]
 PIN rh1[3]
  DIRECTION OUTPUT ;
  USE SIGNAL ;
  PORT
   LAYER M4 ;
   RECT 302.208000 750.732000 302.400000 750.756000 ;
  END
 END rh1[3]
 PIN po2[0]
  DIRECTION INPUT ;
  USE SIGNAL ;
  PORT
   LAYER M4 ;
   RECT 302.208000 750.924000 302.400000 750.948000 ;
  END
 END po2[0]
 PIN po2[1]
  DIRECTION INPUT ;
  USE SIGNAL ;
  PORT
   LAYER M4 ;
   RECT 302.208000 751.116000 302.400000 751.140000 ;
  END
 END po2[1]
 PIN po2[2]
  DIRECTION INPUT ;
  USE SIGNAL ;
  PORT
   LAYER M4 ;
   RECT 302.208000 751.308000 302.400000 751.332000 ;
  END
 END po2[2]
 PIN po2[3]
  DIRECTION INPUT ;
  USE SIGNAL ;
  PORT
   LAYER M4 ;
   RECT 302.208000 751.500000 302.400000 751.524000 ;
  END
 END po2[3]
 PIN po2[4]
  DIRECTION INPUT ;
  USE SIGNAL ;
  PORT
   LAYER M4 ;
   RECT 302.208000 751.692000 302.400000 751.716000 ;
  END
 END po2[4]
 PIN po2[5]
  DIRECTION INPUT ;
  USE SIGNAL ;
  PORT
   LAYER M4 ;
   RECT 302.208000 751.884000 302.400000 751.908000 ;
  END
 END po2[5]
 PIN po2[6]
  DIRECTION INPUT ;
  USE SIGNAL ;
  PORT
   LAYER M4 ;
   RECT 302.208000 752.076000 302.400000 752.100000 ;
  END
 END po2[6]
 PIN po2[7]
  DIRECTION INPUT ;
  USE SIGNAL ;
  PORT
   LAYER M4 ;
   RECT 302.208000 752.268000 302.400000 752.292000 ;
  END
 END po2[7]
 PIN po2[8]
  DIRECTION INPUT ;
  USE SIGNAL ;
  PORT
   LAYER M4 ;
   RECT 302.208000 752.460000 302.400000 752.484000 ;
  END
 END po2[8]
 PIN po2[9]
  DIRECTION INPUT ;
  USE SIGNAL ;
  PORT
   LAYER M4 ;
   RECT 302.208000 752.652000 302.400000 752.676000 ;
  END
 END po2[9]
 PIN po2[10]
  DIRECTION INPUT ;
  USE SIGNAL ;
  PORT
   LAYER M4 ;
   RECT 302.208000 752.844000 302.400000 752.868000 ;
  END
 END po2[10]
 PIN po2[11]
  DIRECTION INPUT ;
  USE SIGNAL ;
  PORT
   LAYER M4 ;
   RECT 302.208000 753.036000 302.400000 753.060000 ;
  END
 END po2[11]
 PIN po2[12]
  DIRECTION INPUT ;
  USE SIGNAL ;
  PORT
   LAYER M4 ;
   RECT 302.208000 753.228000 302.400000 753.252000 ;
  END
 END po2[12]
 PIN po2[13]
  DIRECTION INPUT ;
  USE SIGNAL ;
  PORT
   LAYER M4 ;
   RECT 302.208000 753.420000 302.400000 753.444000 ;
  END
 END po2[13]
 PIN po2[14]
  DIRECTION INPUT ;
  USE SIGNAL ;
  PORT
   LAYER M4 ;
   RECT 302.208000 753.612000 302.400000 753.636000 ;
  END
 END po2[14]
 PIN po2[15]
  DIRECTION INPUT ;
  USE SIGNAL ;
  PORT
   LAYER M4 ;
   RECT 302.208000 753.804000 302.400000 753.828000 ;
  END
 END po2[15]
 PIN po2[16]
  DIRECTION INPUT ;
  USE SIGNAL ;
  PORT
   LAYER M4 ;
   RECT 302.208000 753.996000 302.400000 754.020000 ;
  END
 END po2[16]
 PIN po2[17]
  DIRECTION INPUT ;
  USE SIGNAL ;
  PORT
   LAYER M4 ;
   RECT 302.208000 754.188000 302.400000 754.212000 ;
  END
 END po2[17]
 PIN po2[18]
  DIRECTION INPUT ;
  USE SIGNAL ;
  PORT
   LAYER M4 ;
   RECT 302.208000 754.380000 302.400000 754.404000 ;
  END
 END po2[18]
 PIN po2[19]
  DIRECTION INPUT ;
  USE SIGNAL ;
  PORT
   LAYER M4 ;
   RECT 302.208000 754.572000 302.400000 754.596000 ;
  END
 END po2[19]
 PIN po2[20]
  DIRECTION INPUT ;
  USE SIGNAL ;
  PORT
   LAYER M4 ;
   RECT 302.208000 754.764000 302.400000 754.788000 ;
  END
 END po2[20]
 PIN po2[21]
  DIRECTION INPUT ;
  USE SIGNAL ;
  PORT
   LAYER M4 ;
   RECT 302.208000 754.956000 302.400000 754.980000 ;
  END
 END po2[21]
 PIN po2[22]
  DIRECTION INPUT ;
  USE SIGNAL ;
  PORT
   LAYER M4 ;
   RECT 302.208000 755.148000 302.400000 755.172000 ;
  END
 END po2[22]
 PIN po2[23]
  DIRECTION INPUT ;
  USE SIGNAL ;
  PORT
   LAYER M4 ;
   RECT 302.208000 755.340000 302.400000 755.364000 ;
  END
 END po2[23]
 PIN po2[24]
  DIRECTION INPUT ;
  USE SIGNAL ;
  PORT
   LAYER M4 ;
   RECT 302.208000 755.532000 302.400000 755.556000 ;
  END
 END po2[24]
 PIN po2[25]
  DIRECTION INPUT ;
  USE SIGNAL ;
  PORT
   LAYER M4 ;
   RECT 302.208000 755.724000 302.400000 755.748000 ;
  END
 END po2[25]
 PIN po2[26]
  DIRECTION INPUT ;
  USE SIGNAL ;
  PORT
   LAYER M4 ;
   RECT 302.208000 755.916000 302.400000 755.940000 ;
  END
 END po2[26]
 PIN po2[27]
  DIRECTION INPUT ;
  USE SIGNAL ;
  PORT
   LAYER M4 ;
   RECT 302.208000 756.108000 302.400000 756.132000 ;
  END
 END po2[27]
 PIN po2[28]
  DIRECTION INPUT ;
  USE SIGNAL ;
  PORT
   LAYER M4 ;
   RECT 302.208000 756.300000 302.400000 756.324000 ;
  END
 END po2[28]
 PIN po2[29]
  DIRECTION INPUT ;
  USE SIGNAL ;
  PORT
   LAYER M4 ;
   RECT 302.208000 756.492000 302.400000 756.516000 ;
  END
 END po2[29]
 PIN po2[30]
  DIRECTION INPUT ;
  USE SIGNAL ;
  PORT
   LAYER M4 ;
   RECT 302.208000 756.684000 302.400000 756.708000 ;
  END
 END po2[30]
 PIN po2[31]
  DIRECTION INPUT ;
  USE SIGNAL ;
  PORT
   LAYER M4 ;
   RECT 302.208000 756.876000 302.400000 756.900000 ;
  END
 END po2[31]
 PIN po2[32]
  DIRECTION INPUT ;
  USE SIGNAL ;
  PORT
   LAYER M4 ;
   RECT 302.208000 757.068000 302.400000 757.092000 ;
  END
 END po2[32]
 PIN po2[33]
  DIRECTION INPUT ;
  USE SIGNAL ;
  PORT
   LAYER M4 ;
   RECT 302.208000 757.260000 302.400000 757.284000 ;
  END
 END po2[33]
 PIN po2[34]
  DIRECTION INPUT ;
  USE SIGNAL ;
  PORT
   LAYER M4 ;
   RECT 302.208000 757.452000 302.400000 757.476000 ;
  END
 END po2[34]
 PIN po2[35]
  DIRECTION INPUT ;
  USE SIGNAL ;
  PORT
   LAYER M4 ;
   RECT 302.208000 757.644000 302.400000 757.668000 ;
  END
 END po2[35]
 PIN po2[36]
  DIRECTION INPUT ;
  USE SIGNAL ;
  PORT
   LAYER M4 ;
   RECT 302.208000 757.836000 302.400000 757.860000 ;
  END
 END po2[36]
 PIN po2[37]
  DIRECTION INPUT ;
  USE SIGNAL ;
  PORT
   LAYER M4 ;
   RECT 302.208000 758.028000 302.400000 758.052000 ;
  END
 END po2[37]
 PIN po2[38]
  DIRECTION INPUT ;
  USE SIGNAL ;
  PORT
   LAYER M4 ;
   RECT 302.208000 758.220000 302.400000 758.244000 ;
  END
 END po2[38]
 PIN po2[39]
  DIRECTION INPUT ;
  USE SIGNAL ;
  PORT
   LAYER M4 ;
   RECT 302.208000 758.412000 302.400000 758.436000 ;
  END
 END po2[39]
 PIN po2[40]
  DIRECTION INPUT ;
  USE SIGNAL ;
  PORT
   LAYER M4 ;
   RECT 302.208000 758.604000 302.400000 758.628000 ;
  END
 END po2[40]
 PIN po2[41]
  DIRECTION INPUT ;
  USE SIGNAL ;
  PORT
   LAYER M4 ;
   RECT 302.208000 758.796000 302.400000 758.820000 ;
  END
 END po2[41]
 PIN po2[42]
  DIRECTION INPUT ;
  USE SIGNAL ;
  PORT
   LAYER M4 ;
   RECT 302.208000 758.988000 302.400000 759.012000 ;
  END
 END po2[42]
 PIN po2[43]
  DIRECTION INPUT ;
  USE SIGNAL ;
  PORT
   LAYER M4 ;
   RECT 302.208000 759.180000 302.400000 759.204000 ;
  END
 END po2[43]
 PIN po2[44]
  DIRECTION INPUT ;
  USE SIGNAL ;
  PORT
   LAYER M4 ;
   RECT 302.208000 759.372000 302.400000 759.396000 ;
  END
 END po2[44]
 PIN po2[45]
  DIRECTION INPUT ;
  USE SIGNAL ;
  PORT
   LAYER M4 ;
   RECT 302.208000 759.564000 302.400000 759.588000 ;
  END
 END po2[45]
 PIN po2[46]
  DIRECTION INPUT ;
  USE SIGNAL ;
  PORT
   LAYER M4 ;
   RECT 302.208000 759.756000 302.400000 759.780000 ;
  END
 END po2[46]
 PIN po2[47]
  DIRECTION INPUT ;
  USE SIGNAL ;
  PORT
   LAYER M4 ;
   RECT 302.208000 759.948000 302.400000 759.972000 ;
  END
 END po2[47]
 PIN po2[48]
  DIRECTION INPUT ;
  USE SIGNAL ;
  PORT
   LAYER M4 ;
   RECT 302.208000 760.140000 302.400000 760.164000 ;
  END
 END po2[48]
 PIN po2[49]
  DIRECTION INPUT ;
  USE SIGNAL ;
  PORT
   LAYER M4 ;
   RECT 302.208000 760.332000 302.400000 760.356000 ;
  END
 END po2[49]
 PIN po2[50]
  DIRECTION INPUT ;
  USE SIGNAL ;
  PORT
   LAYER M4 ;
   RECT 302.208000 760.524000 302.400000 760.548000 ;
  END
 END po2[50]
 PIN po2[51]
  DIRECTION INPUT ;
  USE SIGNAL ;
  PORT
   LAYER M4 ;
   RECT 302.208000 760.716000 302.400000 760.740000 ;
  END
 END po2[51]
 PIN po2[52]
  DIRECTION INPUT ;
  USE SIGNAL ;
  PORT
   LAYER M4 ;
   RECT 302.208000 760.908000 302.400000 760.932000 ;
  END
 END po2[52]
 PIN po2[53]
  DIRECTION INPUT ;
  USE SIGNAL ;
  PORT
   LAYER M4 ;
   RECT 302.208000 761.100000 302.400000 761.124000 ;
  END
 END po2[53]
 PIN po2[54]
  DIRECTION INPUT ;
  USE SIGNAL ;
  PORT
   LAYER M4 ;
   RECT 302.208000 761.292000 302.400000 761.316000 ;
  END
 END po2[54]
 PIN po2[55]
  DIRECTION INPUT ;
  USE SIGNAL ;
  PORT
   LAYER M4 ;
   RECT 302.208000 761.484000 302.400000 761.508000 ;
  END
 END po2[55]
 PIN po2[56]
  DIRECTION INPUT ;
  USE SIGNAL ;
  PORT
   LAYER M4 ;
   RECT 302.208000 761.676000 302.400000 761.700000 ;
  END
 END po2[56]
 PIN po2[57]
  DIRECTION INPUT ;
  USE SIGNAL ;
  PORT
   LAYER M4 ;
   RECT 302.208000 761.868000 302.400000 761.892000 ;
  END
 END po2[57]
 PIN po2[58]
  DIRECTION INPUT ;
  USE SIGNAL ;
  PORT
   LAYER M4 ;
   RECT 302.208000 762.060000 302.400000 762.084000 ;
  END
 END po2[58]
 PIN po2[59]
  DIRECTION INPUT ;
  USE SIGNAL ;
  PORT
   LAYER M4 ;
   RECT 302.208000 762.252000 302.400000 762.276000 ;
  END
 END po2[59]
 PIN po2[60]
  DIRECTION INPUT ;
  USE SIGNAL ;
  PORT
   LAYER M4 ;
   RECT 302.208000 762.444000 302.400000 762.468000 ;
  END
 END po2[60]
 PIN po2[61]
  DIRECTION INPUT ;
  USE SIGNAL ;
  PORT
   LAYER M4 ;
   RECT 302.208000 762.636000 302.400000 762.660000 ;
  END
 END po2[61]
 PIN po2[62]
  DIRECTION INPUT ;
  USE SIGNAL ;
  PORT
   LAYER M4 ;
   RECT 302.208000 762.828000 302.400000 762.852000 ;
  END
 END po2[62]
 PIN po2[63]
  DIRECTION INPUT ;
  USE SIGNAL ;
  PORT
   LAYER M4 ;
   RECT 302.208000 763.020000 302.400000 763.044000 ;
  END
 END po2[63]
 PIN po2[64]
  DIRECTION INPUT ;
  USE SIGNAL ;
  PORT
   LAYER M4 ;
   RECT 302.208000 763.212000 302.400000 763.236000 ;
  END
 END po2[64]
 PIN po2[65]
  DIRECTION INPUT ;
  USE SIGNAL ;
  PORT
   LAYER M4 ;
   RECT 302.208000 763.404000 302.400000 763.428000 ;
  END
 END po2[65]
 PIN po2[66]
  DIRECTION INPUT ;
  USE SIGNAL ;
  PORT
   LAYER M4 ;
   RECT 302.208000 763.596000 302.400000 763.620000 ;
  END
 END po2[66]
 PIN po2[67]
  DIRECTION INPUT ;
  USE SIGNAL ;
  PORT
   LAYER M4 ;
   RECT 302.208000 763.788000 302.400000 763.812000 ;
  END
 END po2[67]
 PIN po2[68]
  DIRECTION INPUT ;
  USE SIGNAL ;
  PORT
   LAYER M4 ;
   RECT 302.208000 763.980000 302.400000 764.004000 ;
  END
 END po2[68]
 PIN po2[69]
  DIRECTION INPUT ;
  USE SIGNAL ;
  PORT
   LAYER M4 ;
   RECT 302.208000 764.172000 302.400000 764.196000 ;
  END
 END po2[69]
 PIN po2[70]
  DIRECTION INPUT ;
  USE SIGNAL ;
  PORT
   LAYER M4 ;
   RECT 302.208000 764.364000 302.400000 764.388000 ;
  END
 END po2[70]
 PIN po2[71]
  DIRECTION INPUT ;
  USE SIGNAL ;
  PORT
   LAYER M4 ;
   RECT 302.208000 764.556000 302.400000 764.580000 ;
  END
 END po2[71]
 PIN po2[72]
  DIRECTION INPUT ;
  USE SIGNAL ;
  PORT
   LAYER M4 ;
   RECT 302.208000 764.748000 302.400000 764.772000 ;
  END
 END po2[72]
 PIN po2[73]
  DIRECTION INPUT ;
  USE SIGNAL ;
  PORT
   LAYER M4 ;
   RECT 302.208000 764.940000 302.400000 764.964000 ;
  END
 END po2[73]
 PIN po2[74]
  DIRECTION INPUT ;
  USE SIGNAL ;
  PORT
   LAYER M4 ;
   RECT 302.208000 765.132000 302.400000 765.156000 ;
  END
 END po2[74]
 PIN po2[75]
  DIRECTION INPUT ;
  USE SIGNAL ;
  PORT
   LAYER M4 ;
   RECT 302.208000 765.324000 302.400000 765.348000 ;
  END
 END po2[75]
 PIN po2[76]
  DIRECTION INPUT ;
  USE SIGNAL ;
  PORT
   LAYER M4 ;
   RECT 302.208000 765.516000 302.400000 765.540000 ;
  END
 END po2[76]
 PIN po2[77]
  DIRECTION INPUT ;
  USE SIGNAL ;
  PORT
   LAYER M4 ;
   RECT 302.208000 765.708000 302.400000 765.732000 ;
  END
 END po2[77]
 PIN po2[78]
  DIRECTION INPUT ;
  USE SIGNAL ;
  PORT
   LAYER M4 ;
   RECT 302.208000 765.900000 302.400000 765.924000 ;
  END
 END po2[78]
 PIN po2[79]
  DIRECTION INPUT ;
  USE SIGNAL ;
  PORT
   LAYER M4 ;
   RECT 302.208000 766.092000 302.400000 766.116000 ;
  END
 END po2[79]
 PIN po2[80]
  DIRECTION INPUT ;
  USE SIGNAL ;
  PORT
   LAYER M4 ;
   RECT 302.208000 766.284000 302.400000 766.308000 ;
  END
 END po2[80]
 PIN po2[81]
  DIRECTION INPUT ;
  USE SIGNAL ;
  PORT
   LAYER M4 ;
   RECT 302.208000 766.476000 302.400000 766.500000 ;
  END
 END po2[81]
 PIN po2[82]
  DIRECTION INPUT ;
  USE SIGNAL ;
  PORT
   LAYER M4 ;
   RECT 302.208000 766.668000 302.400000 766.692000 ;
  END
 END po2[82]
 PIN po2[83]
  DIRECTION INPUT ;
  USE SIGNAL ;
  PORT
   LAYER M4 ;
   RECT 302.208000 766.860000 302.400000 766.884000 ;
  END
 END po2[83]
 PIN po2[84]
  DIRECTION INPUT ;
  USE SIGNAL ;
  PORT
   LAYER M4 ;
   RECT 302.208000 767.052000 302.400000 767.076000 ;
  END
 END po2[84]
 PIN po2[85]
  DIRECTION INPUT ;
  USE SIGNAL ;
  PORT
   LAYER M4 ;
   RECT 302.208000 767.244000 302.400000 767.268000 ;
  END
 END po2[85]
 PIN po2[86]
  DIRECTION INPUT ;
  USE SIGNAL ;
  PORT
   LAYER M4 ;
   RECT 302.208000 767.436000 302.400000 767.460000 ;
  END
 END po2[86]
 PIN po2[87]
  DIRECTION INPUT ;
  USE SIGNAL ;
  PORT
   LAYER M4 ;
   RECT 302.208000 767.628000 302.400000 767.652000 ;
  END
 END po2[87]
 PIN po2[88]
  DIRECTION INPUT ;
  USE SIGNAL ;
  PORT
   LAYER M4 ;
   RECT 302.208000 767.820000 302.400000 767.844000 ;
  END
 END po2[88]
 PIN po2[89]
  DIRECTION INPUT ;
  USE SIGNAL ;
  PORT
   LAYER M4 ;
   RECT 302.208000 768.012000 302.400000 768.036000 ;
  END
 END po2[89]
 PIN po2[90]
  DIRECTION INPUT ;
  USE SIGNAL ;
  PORT
   LAYER M4 ;
   RECT 302.208000 768.204000 302.400000 768.228000 ;
  END
 END po2[90]
 PIN po2[91]
  DIRECTION INPUT ;
  USE SIGNAL ;
  PORT
   LAYER M4 ;
   RECT 302.208000 768.396000 302.400000 768.420000 ;
  END
 END po2[91]
 PIN po2[92]
  DIRECTION INPUT ;
  USE SIGNAL ;
  PORT
   LAYER M4 ;
   RECT 302.208000 768.588000 302.400000 768.612000 ;
  END
 END po2[92]
 PIN po2[93]
  DIRECTION INPUT ;
  USE SIGNAL ;
  PORT
   LAYER M4 ;
   RECT 302.208000 768.780000 302.400000 768.804000 ;
  END
 END po2[93]
 PIN po2[94]
  DIRECTION INPUT ;
  USE SIGNAL ;
  PORT
   LAYER M4 ;
   RECT 302.208000 768.972000 302.400000 768.996000 ;
  END
 END po2[94]
 PIN po2[95]
  DIRECTION INPUT ;
  USE SIGNAL ;
  PORT
   LAYER M4 ;
   RECT 302.208000 769.164000 302.400000 769.188000 ;
  END
 END po2[95]
 PIN po2[96]
  DIRECTION INPUT ;
  USE SIGNAL ;
  PORT
   LAYER M4 ;
   RECT 302.208000 769.356000 302.400000 769.380000 ;
  END
 END po2[96]
 PIN po2[97]
  DIRECTION INPUT ;
  USE SIGNAL ;
  PORT
   LAYER M4 ;
   RECT 302.208000 769.548000 302.400000 769.572000 ;
  END
 END po2[97]
 PIN po2[98]
  DIRECTION INPUT ;
  USE SIGNAL ;
  PORT
   LAYER M4 ;
   RECT 302.208000 769.740000 302.400000 769.764000 ;
  END
 END po2[98]
 PIN po2[99]
  DIRECTION INPUT ;
  USE SIGNAL ;
  PORT
   LAYER M4 ;
   RECT 302.208000 769.932000 302.400000 769.956000 ;
  END
 END po2[99]
 PIN po2[100]
  DIRECTION INPUT ;
  USE SIGNAL ;
  PORT
   LAYER M4 ;
   RECT 302.208000 770.124000 302.400000 770.148000 ;
  END
 END po2[100]
 PIN po2[101]
  DIRECTION INPUT ;
  USE SIGNAL ;
  PORT
   LAYER M4 ;
   RECT 302.208000 770.316000 302.400000 770.340000 ;
  END
 END po2[101]
 PIN po2[102]
  DIRECTION INPUT ;
  USE SIGNAL ;
  PORT
   LAYER M4 ;
   RECT 302.208000 770.508000 302.400000 770.532000 ;
  END
 END po2[102]
 PIN po2[103]
  DIRECTION INPUT ;
  USE SIGNAL ;
  PORT
   LAYER M4 ;
   RECT 302.208000 770.700000 302.400000 770.724000 ;
  END
 END po2[103]
 PIN po2[104]
  DIRECTION INPUT ;
  USE SIGNAL ;
  PORT
   LAYER M4 ;
   RECT 302.208000 770.892000 302.400000 770.916000 ;
  END
 END po2[104]
 PIN po2[105]
  DIRECTION INPUT ;
  USE SIGNAL ;
  PORT
   LAYER M4 ;
   RECT 302.208000 771.084000 302.400000 771.108000 ;
  END
 END po2[105]
 PIN po2[106]
  DIRECTION INPUT ;
  USE SIGNAL ;
  PORT
   LAYER M4 ;
   RECT 302.208000 771.276000 302.400000 771.300000 ;
  END
 END po2[106]
 PIN po2[107]
  DIRECTION INPUT ;
  USE SIGNAL ;
  PORT
   LAYER M4 ;
   RECT 302.208000 771.468000 302.400000 771.492000 ;
  END
 END po2[107]
 PIN po2[108]
  DIRECTION INPUT ;
  USE SIGNAL ;
  PORT
   LAYER M4 ;
   RECT 302.208000 771.660000 302.400000 771.684000 ;
  END
 END po2[108]
 PIN po2[109]
  DIRECTION INPUT ;
  USE SIGNAL ;
  PORT
   LAYER M4 ;
   RECT 302.208000 771.852000 302.400000 771.876000 ;
  END
 END po2[109]
 PIN po2[110]
  DIRECTION INPUT ;
  USE SIGNAL ;
  PORT
   LAYER M4 ;
   RECT 302.208000 772.044000 302.400000 772.068000 ;
  END
 END po2[110]
 PIN po2[111]
  DIRECTION INPUT ;
  USE SIGNAL ;
  PORT
   LAYER M4 ;
   RECT 302.208000 772.236000 302.400000 772.260000 ;
  END
 END po2[111]
 PIN po2[112]
  DIRECTION INPUT ;
  USE SIGNAL ;
  PORT
   LAYER M4 ;
   RECT 302.208000 772.428000 302.400000 772.452000 ;
  END
 END po2[112]
 PIN po2[113]
  DIRECTION INPUT ;
  USE SIGNAL ;
  PORT
   LAYER M4 ;
   RECT 302.208000 772.620000 302.400000 772.644000 ;
  END
 END po2[113]
 PIN po2[114]
  DIRECTION INPUT ;
  USE SIGNAL ;
  PORT
   LAYER M4 ;
   RECT 302.208000 772.812000 302.400000 772.836000 ;
  END
 END po2[114]
 PIN po2[115]
  DIRECTION INPUT ;
  USE SIGNAL ;
  PORT
   LAYER M4 ;
   RECT 302.208000 773.004000 302.400000 773.028000 ;
  END
 END po2[115]
 PIN po2[116]
  DIRECTION INPUT ;
  USE SIGNAL ;
  PORT
   LAYER M4 ;
   RECT 302.208000 773.196000 302.400000 773.220000 ;
  END
 END po2[116]
 PIN po2[117]
  DIRECTION INPUT ;
  USE SIGNAL ;
  PORT
   LAYER M4 ;
   RECT 302.208000 773.388000 302.400000 773.412000 ;
  END
 END po2[117]
 PIN po2[118]
  DIRECTION INPUT ;
  USE SIGNAL ;
  PORT
   LAYER M4 ;
   RECT 302.208000 773.580000 302.400000 773.604000 ;
  END
 END po2[118]
 PIN po2[119]
  DIRECTION INPUT ;
  USE SIGNAL ;
  PORT
   LAYER M4 ;
   RECT 302.208000 773.772000 302.400000 773.796000 ;
  END
 END po2[119]
 PIN po2[120]
  DIRECTION INPUT ;
  USE SIGNAL ;
  PORT
   LAYER M4 ;
   RECT 302.208000 773.964000 302.400000 773.988000 ;
  END
 END po2[120]
 PIN po2[121]
  DIRECTION INPUT ;
  USE SIGNAL ;
  PORT
   LAYER M4 ;
   RECT 302.208000 774.156000 302.400000 774.180000 ;
  END
 END po2[121]
 PIN po2[122]
  DIRECTION INPUT ;
  USE SIGNAL ;
  PORT
   LAYER M4 ;
   RECT 302.208000 774.348000 302.400000 774.372000 ;
  END
 END po2[122]
 PIN po2[123]
  DIRECTION INPUT ;
  USE SIGNAL ;
  PORT
   LAYER M4 ;
   RECT 302.208000 774.540000 302.400000 774.564000 ;
  END
 END po2[123]
 PIN po2[124]
  DIRECTION INPUT ;
  USE SIGNAL ;
  PORT
   LAYER M4 ;
   RECT 302.208000 774.732000 302.400000 774.756000 ;
  END
 END po2[124]
 PIN po2[125]
  DIRECTION INPUT ;
  USE SIGNAL ;
  PORT
   LAYER M4 ;
   RECT 302.208000 774.924000 302.400000 774.948000 ;
  END
 END po2[125]
 PIN po2[126]
  DIRECTION INPUT ;
  USE SIGNAL ;
  PORT
   LAYER M4 ;
   RECT 302.208000 775.116000 302.400000 775.140000 ;
  END
 END po2[126]
 PIN po2[127]
  DIRECTION INPUT ;
  USE SIGNAL ;
  PORT
   LAYER M4 ;
   RECT 302.208000 775.308000 302.400000 775.332000 ;
  END
 END po2[127]
 PIN po2[128]
  DIRECTION INPUT ;
  USE SIGNAL ;
  PORT
   LAYER M4 ;
   RECT 302.208000 775.500000 302.400000 775.524000 ;
  END
 END po2[128]
 PIN po2[129]
  DIRECTION INPUT ;
  USE SIGNAL ;
  PORT
   LAYER M4 ;
   RECT 302.208000 775.692000 302.400000 775.716000 ;
  END
 END po2[129]
 PIN po2[130]
  DIRECTION INPUT ;
  USE SIGNAL ;
  PORT
   LAYER M4 ;
   RECT 302.208000 775.884000 302.400000 775.908000 ;
  END
 END po2[130]
 PIN po2[131]
  DIRECTION INPUT ;
  USE SIGNAL ;
  PORT
   LAYER M4 ;
   RECT 302.208000 776.076000 302.400000 776.100000 ;
  END
 END po2[131]
 PIN po2[132]
  DIRECTION INPUT ;
  USE SIGNAL ;
  PORT
   LAYER M4 ;
   RECT 302.208000 776.268000 302.400000 776.292000 ;
  END
 END po2[132]
 PIN po2[133]
  DIRECTION INPUT ;
  USE SIGNAL ;
  PORT
   LAYER M4 ;
   RECT 302.208000 776.460000 302.400000 776.484000 ;
  END
 END po2[133]
 PIN po2[134]
  DIRECTION INPUT ;
  USE SIGNAL ;
  PORT
   LAYER M4 ;
   RECT 302.208000 776.652000 302.400000 776.676000 ;
  END
 END po2[134]
 PIN po2[135]
  DIRECTION INPUT ;
  USE SIGNAL ;
  PORT
   LAYER M4 ;
   RECT 302.208000 776.844000 302.400000 776.868000 ;
  END
 END po2[135]
 PIN po2[136]
  DIRECTION INPUT ;
  USE SIGNAL ;
  PORT
   LAYER M4 ;
   RECT 302.208000 777.036000 302.400000 777.060000 ;
  END
 END po2[136]
 PIN po2[137]
  DIRECTION INPUT ;
  USE SIGNAL ;
  PORT
   LAYER M4 ;
   RECT 302.208000 777.228000 302.400000 777.252000 ;
  END
 END po2[137]
 PIN po2[138]
  DIRECTION INPUT ;
  USE SIGNAL ;
  PORT
   LAYER M4 ;
   RECT 302.208000 777.420000 302.400000 777.444000 ;
  END
 END po2[138]
 PIN po2[139]
  DIRECTION INPUT ;
  USE SIGNAL ;
  PORT
   LAYER M4 ;
   RECT 302.208000 777.612000 302.400000 777.636000 ;
  END
 END po2[139]
 PIN po2[140]
  DIRECTION INPUT ;
  USE SIGNAL ;
  PORT
   LAYER M4 ;
   RECT 302.208000 777.804000 302.400000 777.828000 ;
  END
 END po2[140]
 PIN po2[141]
  DIRECTION INPUT ;
  USE SIGNAL ;
  PORT
   LAYER M4 ;
   RECT 302.208000 777.996000 302.400000 778.020000 ;
  END
 END po2[141]
 PIN po2[142]
  DIRECTION INPUT ;
  USE SIGNAL ;
  PORT
   LAYER M4 ;
   RECT 302.208000 778.188000 302.400000 778.212000 ;
  END
 END po2[142]
 PIN po2[143]
  DIRECTION INPUT ;
  USE SIGNAL ;
  PORT
   LAYER M4 ;
   RECT 302.208000 778.380000 302.400000 778.404000 ;
  END
 END po2[143]
 PIN po2[144]
  DIRECTION INPUT ;
  USE SIGNAL ;
  PORT
   LAYER M4 ;
   RECT 302.208000 778.572000 302.400000 778.596000 ;
  END
 END po2[144]
 PIN po2[145]
  DIRECTION INPUT ;
  USE SIGNAL ;
  PORT
   LAYER M4 ;
   RECT 302.208000 778.764000 302.400000 778.788000 ;
  END
 END po2[145]
 PIN po2[146]
  DIRECTION INPUT ;
  USE SIGNAL ;
  PORT
   LAYER M4 ;
   RECT 302.208000 778.956000 302.400000 778.980000 ;
  END
 END po2[146]
 PIN po2[147]
  DIRECTION INPUT ;
  USE SIGNAL ;
  PORT
   LAYER M4 ;
   RECT 302.208000 779.148000 302.400000 779.172000 ;
  END
 END po2[147]
 PIN po2[148]
  DIRECTION INPUT ;
  USE SIGNAL ;
  PORT
   LAYER M4 ;
   RECT 302.208000 779.340000 302.400000 779.364000 ;
  END
 END po2[148]
 PIN po2[149]
  DIRECTION INPUT ;
  USE SIGNAL ;
  PORT
   LAYER M4 ;
   RECT 302.208000 779.532000 302.400000 779.556000 ;
  END
 END po2[149]
 PIN po2[150]
  DIRECTION INPUT ;
  USE SIGNAL ;
  PORT
   LAYER M4 ;
   RECT 302.208000 779.724000 302.400000 779.748000 ;
  END
 END po2[150]
 PIN po2[151]
  DIRECTION INPUT ;
  USE SIGNAL ;
  PORT
   LAYER M4 ;
   RECT 302.208000 779.916000 302.400000 779.940000 ;
  END
 END po2[151]
 PIN po2[152]
  DIRECTION INPUT ;
  USE SIGNAL ;
  PORT
   LAYER M4 ;
   RECT 302.208000 780.108000 302.400000 780.132000 ;
  END
 END po2[152]
 PIN po2[153]
  DIRECTION INPUT ;
  USE SIGNAL ;
  PORT
   LAYER M4 ;
   RECT 302.208000 780.300000 302.400000 780.324000 ;
  END
 END po2[153]
 PIN po2[154]
  DIRECTION INPUT ;
  USE SIGNAL ;
  PORT
   LAYER M4 ;
   RECT 302.208000 780.492000 302.400000 780.516000 ;
  END
 END po2[154]
 PIN po2[155]
  DIRECTION INPUT ;
  USE SIGNAL ;
  PORT
   LAYER M4 ;
   RECT 302.208000 780.684000 302.400000 780.708000 ;
  END
 END po2[155]
 PIN po2[156]
  DIRECTION INPUT ;
  USE SIGNAL ;
  PORT
   LAYER M4 ;
   RECT 302.208000 780.876000 302.400000 780.900000 ;
  END
 END po2[156]
 PIN po2[157]
  DIRECTION INPUT ;
  USE SIGNAL ;
  PORT
   LAYER M4 ;
   RECT 302.208000 781.068000 302.400000 781.092000 ;
  END
 END po2[157]
 PIN po2[158]
  DIRECTION INPUT ;
  USE SIGNAL ;
  PORT
   LAYER M4 ;
   RECT 302.208000 781.260000 302.400000 781.284000 ;
  END
 END po2[158]
 PIN po2[159]
  DIRECTION INPUT ;
  USE SIGNAL ;
  PORT
   LAYER M4 ;
   RECT 302.208000 781.452000 302.400000 781.476000 ;
  END
 END po2[159]
 PIN po2[160]
  DIRECTION INPUT ;
  USE SIGNAL ;
  PORT
   LAYER M4 ;
   RECT 302.208000 781.644000 302.400000 781.668000 ;
  END
 END po2[160]
 PIN po2[161]
  DIRECTION INPUT ;
  USE SIGNAL ;
  PORT
   LAYER M4 ;
   RECT 302.208000 781.836000 302.400000 781.860000 ;
  END
 END po2[161]
 PIN po2[162]
  DIRECTION INPUT ;
  USE SIGNAL ;
  PORT
   LAYER M4 ;
   RECT 302.208000 782.028000 302.400000 782.052000 ;
  END
 END po2[162]
 PIN po2[163]
  DIRECTION INPUT ;
  USE SIGNAL ;
  PORT
   LAYER M4 ;
   RECT 302.208000 782.220000 302.400000 782.244000 ;
  END
 END po2[163]
 PIN po2[164]
  DIRECTION INPUT ;
  USE SIGNAL ;
  PORT
   LAYER M4 ;
   RECT 302.208000 782.412000 302.400000 782.436000 ;
  END
 END po2[164]
 PIN po2[165]
  DIRECTION INPUT ;
  USE SIGNAL ;
  PORT
   LAYER M4 ;
   RECT 302.208000 782.604000 302.400000 782.628000 ;
  END
 END po2[165]
 PIN po2[166]
  DIRECTION INPUT ;
  USE SIGNAL ;
  PORT
   LAYER M4 ;
   RECT 302.208000 782.796000 302.400000 782.820000 ;
  END
 END po2[166]
 PIN po2[167]
  DIRECTION INPUT ;
  USE SIGNAL ;
  PORT
   LAYER M4 ;
   RECT 302.208000 782.988000 302.400000 783.012000 ;
  END
 END po2[167]
 PIN po2[168]
  DIRECTION INPUT ;
  USE SIGNAL ;
  PORT
   LAYER M4 ;
   RECT 302.208000 783.180000 302.400000 783.204000 ;
  END
 END po2[168]
 PIN po2[169]
  DIRECTION INPUT ;
  USE SIGNAL ;
  PORT
   LAYER M4 ;
   RECT 302.208000 783.372000 302.400000 783.396000 ;
  END
 END po2[169]
 PIN po2[170]
  DIRECTION INPUT ;
  USE SIGNAL ;
  PORT
   LAYER M4 ;
   RECT 302.208000 783.564000 302.400000 783.588000 ;
  END
 END po2[170]
 PIN po2[171]
  DIRECTION INPUT ;
  USE SIGNAL ;
  PORT
   LAYER M4 ;
   RECT 302.208000 783.756000 302.400000 783.780000 ;
  END
 END po2[171]
 PIN po2[172]
  DIRECTION INPUT ;
  USE SIGNAL ;
  PORT
   LAYER M4 ;
   RECT 302.208000 783.948000 302.400000 783.972000 ;
  END
 END po2[172]
 PIN po2[173]
  DIRECTION INPUT ;
  USE SIGNAL ;
  PORT
   LAYER M4 ;
   RECT 302.208000 784.140000 302.400000 784.164000 ;
  END
 END po2[173]
 PIN po2[174]
  DIRECTION INPUT ;
  USE SIGNAL ;
  PORT
   LAYER M4 ;
   RECT 302.208000 784.332000 302.400000 784.356000 ;
  END
 END po2[174]
 PIN po2[175]
  DIRECTION INPUT ;
  USE SIGNAL ;
  PORT
   LAYER M4 ;
   RECT 302.208000 784.524000 302.400000 784.548000 ;
  END
 END po2[175]
 PIN po2[176]
  DIRECTION INPUT ;
  USE SIGNAL ;
  PORT
   LAYER M4 ;
   RECT 302.208000 784.716000 302.400000 784.740000 ;
  END
 END po2[176]
 PIN po2[177]
  DIRECTION INPUT ;
  USE SIGNAL ;
  PORT
   LAYER M4 ;
   RECT 302.208000 784.908000 302.400000 784.932000 ;
  END
 END po2[177]
 PIN po2[178]
  DIRECTION INPUT ;
  USE SIGNAL ;
  PORT
   LAYER M4 ;
   RECT 302.208000 785.100000 302.400000 785.124000 ;
  END
 END po2[178]
 PIN po2[179]
  DIRECTION INPUT ;
  USE SIGNAL ;
  PORT
   LAYER M4 ;
   RECT 302.208000 785.292000 302.400000 785.316000 ;
  END
 END po2[179]
 PIN po2[180]
  DIRECTION INPUT ;
  USE SIGNAL ;
  PORT
   LAYER M4 ;
   RECT 302.208000 785.484000 302.400000 785.508000 ;
  END
 END po2[180]
 PIN po2[181]
  DIRECTION INPUT ;
  USE SIGNAL ;
  PORT
   LAYER M4 ;
   RECT 302.208000 785.676000 302.400000 785.700000 ;
  END
 END po2[181]
 PIN po2[182]
  DIRECTION INPUT ;
  USE SIGNAL ;
  PORT
   LAYER M4 ;
   RECT 302.208000 785.868000 302.400000 785.892000 ;
  END
 END po2[182]
 PIN po2[183]
  DIRECTION INPUT ;
  USE SIGNAL ;
  PORT
   LAYER M4 ;
   RECT 302.208000 786.060000 302.400000 786.084000 ;
  END
 END po2[183]
 PIN po2[184]
  DIRECTION INPUT ;
  USE SIGNAL ;
  PORT
   LAYER M4 ;
   RECT 302.208000 786.252000 302.400000 786.276000 ;
  END
 END po2[184]
 PIN po2[185]
  DIRECTION INPUT ;
  USE SIGNAL ;
  PORT
   LAYER M4 ;
   RECT 302.208000 786.444000 302.400000 786.468000 ;
  END
 END po2[185]
 PIN po2[186]
  DIRECTION INPUT ;
  USE SIGNAL ;
  PORT
   LAYER M4 ;
   RECT 302.208000 786.636000 302.400000 786.660000 ;
  END
 END po2[186]
 PIN po2[187]
  DIRECTION INPUT ;
  USE SIGNAL ;
  PORT
   LAYER M4 ;
   RECT 302.208000 786.828000 302.400000 786.852000 ;
  END
 END po2[187]
 PIN po2[188]
  DIRECTION INPUT ;
  USE SIGNAL ;
  PORT
   LAYER M4 ;
   RECT 302.208000 787.020000 302.400000 787.044000 ;
  END
 END po2[188]
 PIN po2[189]
  DIRECTION INPUT ;
  USE SIGNAL ;
  PORT
   LAYER M4 ;
   RECT 302.208000 787.212000 302.400000 787.236000 ;
  END
 END po2[189]
 PIN po2[190]
  DIRECTION INPUT ;
  USE SIGNAL ;
  PORT
   LAYER M4 ;
   RECT 302.208000 787.404000 302.400000 787.428000 ;
  END
 END po2[190]
 PIN po2[191]
  DIRECTION INPUT ;
  USE SIGNAL ;
  PORT
   LAYER M4 ;
   RECT 302.208000 787.596000 302.400000 787.620000 ;
  END
 END po2[191]
 PIN po2[192]
  DIRECTION INPUT ;
  USE SIGNAL ;
  PORT
   LAYER M4 ;
   RECT 302.208000 787.788000 302.400000 787.812000 ;
  END
 END po2[192]
 PIN po2[193]
  DIRECTION INPUT ;
  USE SIGNAL ;
  PORT
   LAYER M4 ;
   RECT 302.208000 787.980000 302.400000 788.004000 ;
  END
 END po2[193]
 PIN po2[194]
  DIRECTION INPUT ;
  USE SIGNAL ;
  PORT
   LAYER M4 ;
   RECT 302.208000 788.172000 302.400000 788.196000 ;
  END
 END po2[194]
 PIN po2[195]
  DIRECTION INPUT ;
  USE SIGNAL ;
  PORT
   LAYER M4 ;
   RECT 302.208000 788.364000 302.400000 788.388000 ;
  END
 END po2[195]
 PIN po2[196]
  DIRECTION INPUT ;
  USE SIGNAL ;
  PORT
   LAYER M4 ;
   RECT 302.208000 788.556000 302.400000 788.580000 ;
  END
 END po2[196]
 PIN po2[197]
  DIRECTION INPUT ;
  USE SIGNAL ;
  PORT
   LAYER M4 ;
   RECT 302.208000 788.748000 302.400000 788.772000 ;
  END
 END po2[197]
 PIN po2[198]
  DIRECTION INPUT ;
  USE SIGNAL ;
  PORT
   LAYER M4 ;
   RECT 302.208000 788.940000 302.400000 788.964000 ;
  END
 END po2[198]
 PIN po2[199]
  DIRECTION INPUT ;
  USE SIGNAL ;
  PORT
   LAYER M4 ;
   RECT 302.208000 789.132000 302.400000 789.156000 ;
  END
 END po2[199]
 PIN po2[200]
  DIRECTION INPUT ;
  USE SIGNAL ;
  PORT
   LAYER M4 ;
   RECT 302.208000 789.324000 302.400000 789.348000 ;
  END
 END po2[200]
 PIN po2[201]
  DIRECTION INPUT ;
  USE SIGNAL ;
  PORT
   LAYER M4 ;
   RECT 302.208000 789.516000 302.400000 789.540000 ;
  END
 END po2[201]
 PIN po2[202]
  DIRECTION INPUT ;
  USE SIGNAL ;
  PORT
   LAYER M4 ;
   RECT 302.208000 789.708000 302.400000 789.732000 ;
  END
 END po2[202]
 PIN po2[203]
  DIRECTION INPUT ;
  USE SIGNAL ;
  PORT
   LAYER M4 ;
   RECT 302.208000 789.900000 302.400000 789.924000 ;
  END
 END po2[203]
 PIN po2[204]
  DIRECTION INPUT ;
  USE SIGNAL ;
  PORT
   LAYER M4 ;
   RECT 302.208000 790.092000 302.400000 790.116000 ;
  END
 END po2[204]
 PIN po2[205]
  DIRECTION INPUT ;
  USE SIGNAL ;
  PORT
   LAYER M4 ;
   RECT 302.208000 790.284000 302.400000 790.308000 ;
  END
 END po2[205]
 PIN po2[206]
  DIRECTION INPUT ;
  USE SIGNAL ;
  PORT
   LAYER M4 ;
   RECT 302.208000 790.476000 302.400000 790.500000 ;
  END
 END po2[206]
 PIN po2[207]
  DIRECTION INPUT ;
  USE SIGNAL ;
  PORT
   LAYER M4 ;
   RECT 302.208000 790.668000 302.400000 790.692000 ;
  END
 END po2[207]
 PIN po2[208]
  DIRECTION INPUT ;
  USE SIGNAL ;
  PORT
   LAYER M4 ;
   RECT 302.208000 790.860000 302.400000 790.884000 ;
  END
 END po2[208]
 PIN po2[209]
  DIRECTION INPUT ;
  USE SIGNAL ;
  PORT
   LAYER M4 ;
   RECT 302.208000 791.052000 302.400000 791.076000 ;
  END
 END po2[209]
 PIN po2[210]
  DIRECTION INPUT ;
  USE SIGNAL ;
  PORT
   LAYER M4 ;
   RECT 302.208000 791.244000 302.400000 791.268000 ;
  END
 END po2[210]
 PIN po2[211]
  DIRECTION INPUT ;
  USE SIGNAL ;
  PORT
   LAYER M4 ;
   RECT 302.208000 791.436000 302.400000 791.460000 ;
  END
 END po2[211]
 PIN po2[212]
  DIRECTION INPUT ;
  USE SIGNAL ;
  PORT
   LAYER M4 ;
   RECT 302.208000 791.628000 302.400000 791.652000 ;
  END
 END po2[212]
 PIN po2[213]
  DIRECTION INPUT ;
  USE SIGNAL ;
  PORT
   LAYER M4 ;
   RECT 302.208000 791.820000 302.400000 791.844000 ;
  END
 END po2[213]
 PIN po2[214]
  DIRECTION INPUT ;
  USE SIGNAL ;
  PORT
   LAYER M4 ;
   RECT 302.208000 792.012000 302.400000 792.036000 ;
  END
 END po2[214]
 PIN po2[215]
  DIRECTION INPUT ;
  USE SIGNAL ;
  PORT
   LAYER M4 ;
   RECT 302.208000 792.204000 302.400000 792.228000 ;
  END
 END po2[215]
 PIN po2[216]
  DIRECTION INPUT ;
  USE SIGNAL ;
  PORT
   LAYER M4 ;
   RECT 302.208000 792.396000 302.400000 792.420000 ;
  END
 END po2[216]
 PIN po2[217]
  DIRECTION INPUT ;
  USE SIGNAL ;
  PORT
   LAYER M4 ;
   RECT 302.208000 792.588000 302.400000 792.612000 ;
  END
 END po2[217]
 PIN po2[218]
  DIRECTION INPUT ;
  USE SIGNAL ;
  PORT
   LAYER M4 ;
   RECT 302.208000 792.780000 302.400000 792.804000 ;
  END
 END po2[218]
 PIN po2[219]
  DIRECTION INPUT ;
  USE SIGNAL ;
  PORT
   LAYER M4 ;
   RECT 302.208000 792.972000 302.400000 792.996000 ;
  END
 END po2[219]
 PIN po2[220]
  DIRECTION INPUT ;
  USE SIGNAL ;
  PORT
   LAYER M4 ;
   RECT 302.208000 793.164000 302.400000 793.188000 ;
  END
 END po2[220]
 PIN po2[221]
  DIRECTION INPUT ;
  USE SIGNAL ;
  PORT
   LAYER M4 ;
   RECT 302.208000 793.356000 302.400000 793.380000 ;
  END
 END po2[221]
 PIN po2[222]
  DIRECTION INPUT ;
  USE SIGNAL ;
  PORT
   LAYER M4 ;
   RECT 302.208000 793.548000 302.400000 793.572000 ;
  END
 END po2[222]
 PIN po2[223]
  DIRECTION INPUT ;
  USE SIGNAL ;
  PORT
   LAYER M4 ;
   RECT 302.208000 793.740000 302.400000 793.764000 ;
  END
 END po2[223]
 PIN po2[224]
  DIRECTION INPUT ;
  USE SIGNAL ;
  PORT
   LAYER M4 ;
   RECT 302.208000 793.932000 302.400000 793.956000 ;
  END
 END po2[224]
 PIN po2[225]
  DIRECTION INPUT ;
  USE SIGNAL ;
  PORT
   LAYER M4 ;
   RECT 302.208000 794.124000 302.400000 794.148000 ;
  END
 END po2[225]
 PIN po2[226]
  DIRECTION INPUT ;
  USE SIGNAL ;
  PORT
   LAYER M4 ;
   RECT 302.208000 794.316000 302.400000 794.340000 ;
  END
 END po2[226]
 PIN po2[227]
  DIRECTION INPUT ;
  USE SIGNAL ;
  PORT
   LAYER M4 ;
   RECT 302.208000 794.508000 302.400000 794.532000 ;
  END
 END po2[227]
 PIN po2[228]
  DIRECTION INPUT ;
  USE SIGNAL ;
  PORT
   LAYER M4 ;
   RECT 302.208000 794.700000 302.400000 794.724000 ;
  END
 END po2[228]
 PIN po2[229]
  DIRECTION INPUT ;
  USE SIGNAL ;
  PORT
   LAYER M4 ;
   RECT 302.208000 794.892000 302.400000 794.916000 ;
  END
 END po2[229]
 PIN po2[230]
  DIRECTION INPUT ;
  USE SIGNAL ;
  PORT
   LAYER M4 ;
   RECT 302.208000 795.084000 302.400000 795.108000 ;
  END
 END po2[230]
 PIN po2[231]
  DIRECTION INPUT ;
  USE SIGNAL ;
  PORT
   LAYER M4 ;
   RECT 302.208000 795.276000 302.400000 795.300000 ;
  END
 END po2[231]
 PIN po2[232]
  DIRECTION INPUT ;
  USE SIGNAL ;
  PORT
   LAYER M4 ;
   RECT 302.208000 795.468000 302.400000 795.492000 ;
  END
 END po2[232]
 PIN po2[233]
  DIRECTION INPUT ;
  USE SIGNAL ;
  PORT
   LAYER M4 ;
   RECT 302.208000 795.660000 302.400000 795.684000 ;
  END
 END po2[233]
 PIN po2[234]
  DIRECTION INPUT ;
  USE SIGNAL ;
  PORT
   LAYER M4 ;
   RECT 302.208000 795.852000 302.400000 795.876000 ;
  END
 END po2[234]
 PIN po2[235]
  DIRECTION INPUT ;
  USE SIGNAL ;
  PORT
   LAYER M4 ;
   RECT 302.208000 796.044000 302.400000 796.068000 ;
  END
 END po2[235]
 PIN po2[236]
  DIRECTION INPUT ;
  USE SIGNAL ;
  PORT
   LAYER M4 ;
   RECT 302.208000 796.236000 302.400000 796.260000 ;
  END
 END po2[236]
 PIN po2[237]
  DIRECTION INPUT ;
  USE SIGNAL ;
  PORT
   LAYER M4 ;
   RECT 302.208000 796.428000 302.400000 796.452000 ;
  END
 END po2[237]
 PIN po2[238]
  DIRECTION INPUT ;
  USE SIGNAL ;
  PORT
   LAYER M4 ;
   RECT 302.208000 796.620000 302.400000 796.644000 ;
  END
 END po2[238]
 PIN po2[239]
  DIRECTION INPUT ;
  USE SIGNAL ;
  PORT
   LAYER M4 ;
   RECT 302.208000 796.812000 302.400000 796.836000 ;
  END
 END po2[239]
 PIN po2[240]
  DIRECTION INPUT ;
  USE SIGNAL ;
  PORT
   LAYER M4 ;
   RECT 302.208000 797.004000 302.400000 797.028000 ;
  END
 END po2[240]
 PIN po2[241]
  DIRECTION INPUT ;
  USE SIGNAL ;
  PORT
   LAYER M4 ;
   RECT 302.208000 797.196000 302.400000 797.220000 ;
  END
 END po2[241]
 PIN po2[242]
  DIRECTION INPUT ;
  USE SIGNAL ;
  PORT
   LAYER M4 ;
   RECT 302.208000 797.388000 302.400000 797.412000 ;
  END
 END po2[242]
 PIN po2[243]
  DIRECTION INPUT ;
  USE SIGNAL ;
  PORT
   LAYER M4 ;
   RECT 302.208000 797.580000 302.400000 797.604000 ;
  END
 END po2[243]
 PIN po2[244]
  DIRECTION INPUT ;
  USE SIGNAL ;
  PORT
   LAYER M4 ;
   RECT 302.208000 797.772000 302.400000 797.796000 ;
  END
 END po2[244]
 PIN po2[245]
  DIRECTION INPUT ;
  USE SIGNAL ;
  PORT
   LAYER M4 ;
   RECT 302.208000 797.964000 302.400000 797.988000 ;
  END
 END po2[245]
 PIN po2[246]
  DIRECTION INPUT ;
  USE SIGNAL ;
  PORT
   LAYER M4 ;
   RECT 302.208000 798.156000 302.400000 798.180000 ;
  END
 END po2[246]
 PIN po2[247]
  DIRECTION INPUT ;
  USE SIGNAL ;
  PORT
   LAYER M4 ;
   RECT 302.208000 798.348000 302.400000 798.372000 ;
  END
 END po2[247]
 PIN po2[248]
  DIRECTION INPUT ;
  USE SIGNAL ;
  PORT
   LAYER M4 ;
   RECT 302.208000 798.540000 302.400000 798.564000 ;
  END
 END po2[248]
 PIN po2[249]
  DIRECTION INPUT ;
  USE SIGNAL ;
  PORT
   LAYER M4 ;
   RECT 302.208000 798.732000 302.400000 798.756000 ;
  END
 END po2[249]
 PIN po2[250]
  DIRECTION INPUT ;
  USE SIGNAL ;
  PORT
   LAYER M4 ;
   RECT 302.208000 798.924000 302.400000 798.948000 ;
  END
 END po2[250]
 PIN po2[251]
  DIRECTION INPUT ;
  USE SIGNAL ;
  PORT
   LAYER M4 ;
   RECT 302.208000 799.116000 302.400000 799.140000 ;
  END
 END po2[251]
 PIN po2[252]
  DIRECTION INPUT ;
  USE SIGNAL ;
  PORT
   LAYER M4 ;
   RECT 302.208000 799.308000 302.400000 799.332000 ;
  END
 END po2[252]
 PIN po2[253]
  DIRECTION INPUT ;
  USE SIGNAL ;
  PORT
   LAYER M4 ;
   RECT 302.208000 799.500000 302.400000 799.524000 ;
  END
 END po2[253]
 PIN po2[254]
  DIRECTION INPUT ;
  USE SIGNAL ;
  PORT
   LAYER M4 ;
   RECT 302.208000 799.692000 302.400000 799.716000 ;
  END
 END po2[254]
 PIN po2[255]
  DIRECTION INPUT ;
  USE SIGNAL ;
  PORT
   LAYER M4 ;
   RECT 302.208000 799.884000 302.400000 799.908000 ;
  END
 END po2[255]
 PIN po2[256]
  DIRECTION INPUT ;
  USE SIGNAL ;
  PORT
   LAYER M4 ;
   RECT 302.208000 800.076000 302.400000 800.100000 ;
  END
 END po2[256]
 PIN po2[257]
  DIRECTION INPUT ;
  USE SIGNAL ;
  PORT
   LAYER M4 ;
   RECT 302.208000 800.268000 302.400000 800.292000 ;
  END
 END po2[257]
 PIN po2[258]
  DIRECTION INPUT ;
  USE SIGNAL ;
  PORT
   LAYER M4 ;
   RECT 302.208000 800.460000 302.400000 800.484000 ;
  END
 END po2[258]
 PIN po2[259]
  DIRECTION INPUT ;
  USE SIGNAL ;
  PORT
   LAYER M4 ;
   RECT 302.208000 800.652000 302.400000 800.676000 ;
  END
 END po2[259]
 PIN po2[260]
  DIRECTION INPUT ;
  USE SIGNAL ;
  PORT
   LAYER M4 ;
   RECT 302.208000 800.844000 302.400000 800.868000 ;
  END
 END po2[260]
 PIN po2[261]
  DIRECTION INPUT ;
  USE SIGNAL ;
  PORT
   LAYER M4 ;
   RECT 302.208000 801.036000 302.400000 801.060000 ;
  END
 END po2[261]
 PIN po2[262]
  DIRECTION INPUT ;
  USE SIGNAL ;
  PORT
   LAYER M4 ;
   RECT 302.208000 801.228000 302.400000 801.252000 ;
  END
 END po2[262]
 PIN po2[263]
  DIRECTION INPUT ;
  USE SIGNAL ;
  PORT
   LAYER M4 ;
   RECT 302.208000 801.420000 302.400000 801.444000 ;
  END
 END po2[263]
 PIN po2[264]
  DIRECTION INPUT ;
  USE SIGNAL ;
  PORT
   LAYER M4 ;
   RECT 302.208000 801.612000 302.400000 801.636000 ;
  END
 END po2[264]
 PIN po2[265]
  DIRECTION INPUT ;
  USE SIGNAL ;
  PORT
   LAYER M4 ;
   RECT 302.208000 801.804000 302.400000 801.828000 ;
  END
 END po2[265]
 PIN po2[266]
  DIRECTION INPUT ;
  USE SIGNAL ;
  PORT
   LAYER M4 ;
   RECT 302.208000 801.996000 302.400000 802.020000 ;
  END
 END po2[266]
 PIN po2[267]
  DIRECTION INPUT ;
  USE SIGNAL ;
  PORT
   LAYER M4 ;
   RECT 302.208000 802.188000 302.400000 802.212000 ;
  END
 END po2[267]
 PIN po2[268]
  DIRECTION INPUT ;
  USE SIGNAL ;
  PORT
   LAYER M4 ;
   RECT 302.208000 802.380000 302.400000 802.404000 ;
  END
 END po2[268]
 PIN po2[269]
  DIRECTION INPUT ;
  USE SIGNAL ;
  PORT
   LAYER M4 ;
   RECT 302.208000 802.572000 302.400000 802.596000 ;
  END
 END po2[269]
 PIN po2[270]
  DIRECTION INPUT ;
  USE SIGNAL ;
  PORT
   LAYER M4 ;
   RECT 302.208000 802.764000 302.400000 802.788000 ;
  END
 END po2[270]
 PIN po2[271]
  DIRECTION INPUT ;
  USE SIGNAL ;
  PORT
   LAYER M4 ;
   RECT 302.208000 802.956000 302.400000 802.980000 ;
  END
 END po2[271]
 PIN po2[272]
  DIRECTION INPUT ;
  USE SIGNAL ;
  PORT
   LAYER M4 ;
   RECT 302.208000 803.148000 302.400000 803.172000 ;
  END
 END po2[272]
 PIN po2[273]
  DIRECTION INPUT ;
  USE SIGNAL ;
  PORT
   LAYER M4 ;
   RECT 302.208000 803.340000 302.400000 803.364000 ;
  END
 END po2[273]
 PIN po2[274]
  DIRECTION INPUT ;
  USE SIGNAL ;
  PORT
   LAYER M4 ;
   RECT 302.208000 803.532000 302.400000 803.556000 ;
  END
 END po2[274]
 PIN po2[275]
  DIRECTION INPUT ;
  USE SIGNAL ;
  PORT
   LAYER M4 ;
   RECT 302.208000 803.724000 302.400000 803.748000 ;
  END
 END po2[275]
 PIN po2[276]
  DIRECTION INPUT ;
  USE SIGNAL ;
  PORT
   LAYER M4 ;
   RECT 302.208000 803.916000 302.400000 803.940000 ;
  END
 END po2[276]
 PIN po2[277]
  DIRECTION INPUT ;
  USE SIGNAL ;
  PORT
   LAYER M4 ;
   RECT 302.208000 804.108000 302.400000 804.132000 ;
  END
 END po2[277]
 PIN po2[278]
  DIRECTION INPUT ;
  USE SIGNAL ;
  PORT
   LAYER M4 ;
   RECT 302.208000 804.300000 302.400000 804.324000 ;
  END
 END po2[278]
 PIN po2[279]
  DIRECTION INPUT ;
  USE SIGNAL ;
  PORT
   LAYER M4 ;
   RECT 302.208000 804.492000 302.400000 804.516000 ;
  END
 END po2[279]
 PIN po2[280]
  DIRECTION INPUT ;
  USE SIGNAL ;
  PORT
   LAYER M4 ;
   RECT 302.208000 804.684000 302.400000 804.708000 ;
  END
 END po2[280]
 PIN po2[281]
  DIRECTION INPUT ;
  USE SIGNAL ;
  PORT
   LAYER M4 ;
   RECT 302.208000 804.876000 302.400000 804.900000 ;
  END
 END po2[281]
 PIN po2[282]
  DIRECTION INPUT ;
  USE SIGNAL ;
  PORT
   LAYER M4 ;
   RECT 302.208000 805.068000 302.400000 805.092000 ;
  END
 END po2[282]
 PIN po2[283]
  DIRECTION INPUT ;
  USE SIGNAL ;
  PORT
   LAYER M4 ;
   RECT 302.208000 805.260000 302.400000 805.284000 ;
  END
 END po2[283]
 PIN po2[284]
  DIRECTION INPUT ;
  USE SIGNAL ;
  PORT
   LAYER M4 ;
   RECT 302.208000 805.452000 302.400000 805.476000 ;
  END
 END po2[284]
 PIN po2[285]
  DIRECTION INPUT ;
  USE SIGNAL ;
  PORT
   LAYER M4 ;
   RECT 302.208000 805.644000 302.400000 805.668000 ;
  END
 END po2[285]
 PIN po2[286]
  DIRECTION INPUT ;
  USE SIGNAL ;
  PORT
   LAYER M4 ;
   RECT 302.208000 805.836000 302.400000 805.860000 ;
  END
 END po2[286]
 PIN po2[287]
  DIRECTION INPUT ;
  USE SIGNAL ;
  PORT
   LAYER M4 ;
   RECT 302.208000 806.028000 302.400000 806.052000 ;
  END
 END po2[287]
 PIN po2[288]
  DIRECTION INPUT ;
  USE SIGNAL ;
  PORT
   LAYER M4 ;
   RECT 302.208000 806.220000 302.400000 806.244000 ;
  END
 END po2[288]
 PIN po2[289]
  DIRECTION INPUT ;
  USE SIGNAL ;
  PORT
   LAYER M4 ;
   RECT 302.208000 806.412000 302.400000 806.436000 ;
  END
 END po2[289]
 PIN po2[290]
  DIRECTION INPUT ;
  USE SIGNAL ;
  PORT
   LAYER M4 ;
   RECT 302.208000 806.604000 302.400000 806.628000 ;
  END
 END po2[290]
 PIN po2[291]
  DIRECTION INPUT ;
  USE SIGNAL ;
  PORT
   LAYER M4 ;
   RECT 302.208000 806.796000 302.400000 806.820000 ;
  END
 END po2[291]
 PIN po2[292]
  DIRECTION INPUT ;
  USE SIGNAL ;
  PORT
   LAYER M4 ;
   RECT 302.208000 806.988000 302.400000 807.012000 ;
  END
 END po2[292]
 PIN po2[293]
  DIRECTION INPUT ;
  USE SIGNAL ;
  PORT
   LAYER M4 ;
   RECT 302.208000 807.180000 302.400000 807.204000 ;
  END
 END po2[293]
 PIN po2[294]
  DIRECTION INPUT ;
  USE SIGNAL ;
  PORT
   LAYER M4 ;
   RECT 302.208000 807.372000 302.400000 807.396000 ;
  END
 END po2[294]
 PIN po2[295]
  DIRECTION INPUT ;
  USE SIGNAL ;
  PORT
   LAYER M4 ;
   RECT 302.208000 807.564000 302.400000 807.588000 ;
  END
 END po2[295]
 PIN po2[296]
  DIRECTION INPUT ;
  USE SIGNAL ;
  PORT
   LAYER M4 ;
   RECT 302.208000 807.756000 302.400000 807.780000 ;
  END
 END po2[296]
 PIN po2[297]
  DIRECTION INPUT ;
  USE SIGNAL ;
  PORT
   LAYER M4 ;
   RECT 302.208000 807.948000 302.400000 807.972000 ;
  END
 END po2[297]
 PIN po2[298]
  DIRECTION INPUT ;
  USE SIGNAL ;
  PORT
   LAYER M4 ;
   RECT 302.208000 808.140000 302.400000 808.164000 ;
  END
 END po2[298]
 PIN po2[299]
  DIRECTION INPUT ;
  USE SIGNAL ;
  PORT
   LAYER M4 ;
   RECT 302.208000 808.332000 302.400000 808.356000 ;
  END
 END po2[299]
 PIN po2[300]
  DIRECTION INPUT ;
  USE SIGNAL ;
  PORT
   LAYER M4 ;
   RECT 302.208000 808.524000 302.400000 808.548000 ;
  END
 END po2[300]
 PIN po2[301]
  DIRECTION INPUT ;
  USE SIGNAL ;
  PORT
   LAYER M4 ;
   RECT 302.208000 808.716000 302.400000 808.740000 ;
  END
 END po2[301]
 PIN po2[302]
  DIRECTION INPUT ;
  USE SIGNAL ;
  PORT
   LAYER M4 ;
   RECT 302.208000 808.908000 302.400000 808.932000 ;
  END
 END po2[302]
 PIN po2[303]
  DIRECTION INPUT ;
  USE SIGNAL ;
  PORT
   LAYER M4 ;
   RECT 302.208000 809.100000 302.400000 809.124000 ;
  END
 END po2[303]
 PIN po2[304]
  DIRECTION INPUT ;
  USE SIGNAL ;
  PORT
   LAYER M4 ;
   RECT 302.208000 809.292000 302.400000 809.316000 ;
  END
 END po2[304]
 PIN po2[305]
  DIRECTION INPUT ;
  USE SIGNAL ;
  PORT
   LAYER M4 ;
   RECT 302.208000 809.484000 302.400000 809.508000 ;
  END
 END po2[305]
 PIN po2[306]
  DIRECTION INPUT ;
  USE SIGNAL ;
  PORT
   LAYER M4 ;
   RECT 302.208000 809.676000 302.400000 809.700000 ;
  END
 END po2[306]
 PIN po2[307]
  DIRECTION INPUT ;
  USE SIGNAL ;
  PORT
   LAYER M4 ;
   RECT 302.208000 809.868000 302.400000 809.892000 ;
  END
 END po2[307]
 PIN po2[308]
  DIRECTION INPUT ;
  USE SIGNAL ;
  PORT
   LAYER M4 ;
   RECT 302.208000 810.060000 302.400000 810.084000 ;
  END
 END po2[308]
 PIN po2[309]
  DIRECTION INPUT ;
  USE SIGNAL ;
  PORT
   LAYER M4 ;
   RECT 302.208000 810.252000 302.400000 810.276000 ;
  END
 END po2[309]
 PIN po2[310]
  DIRECTION INPUT ;
  USE SIGNAL ;
  PORT
   LAYER M4 ;
   RECT 302.208000 810.444000 302.400000 810.468000 ;
  END
 END po2[310]
 PIN po2[311]
  DIRECTION INPUT ;
  USE SIGNAL ;
  PORT
   LAYER M4 ;
   RECT 302.208000 810.636000 302.400000 810.660000 ;
  END
 END po2[311]
 PIN po2[312]
  DIRECTION INPUT ;
  USE SIGNAL ;
  PORT
   LAYER M4 ;
   RECT 302.208000 810.828000 302.400000 810.852000 ;
  END
 END po2[312]
 PIN po2[313]
  DIRECTION INPUT ;
  USE SIGNAL ;
  PORT
   LAYER M4 ;
   RECT 302.208000 811.020000 302.400000 811.044000 ;
  END
 END po2[313]
 PIN po2[314]
  DIRECTION INPUT ;
  USE SIGNAL ;
  PORT
   LAYER M4 ;
   RECT 302.208000 811.212000 302.400000 811.236000 ;
  END
 END po2[314]
 PIN po2[315]
  DIRECTION INPUT ;
  USE SIGNAL ;
  PORT
   LAYER M4 ;
   RECT 302.208000 811.404000 302.400000 811.428000 ;
  END
 END po2[315]
 PIN po2[316]
  DIRECTION INPUT ;
  USE SIGNAL ;
  PORT
   LAYER M4 ;
   RECT 302.208000 811.596000 302.400000 811.620000 ;
  END
 END po2[316]
 PIN po2[317]
  DIRECTION INPUT ;
  USE SIGNAL ;
  PORT
   LAYER M4 ;
   RECT 302.208000 811.788000 302.400000 811.812000 ;
  END
 END po2[317]
 PIN po2[318]
  DIRECTION INPUT ;
  USE SIGNAL ;
  PORT
   LAYER M4 ;
   RECT 302.208000 811.980000 302.400000 812.004000 ;
  END
 END po2[318]
 PIN po2[319]
  DIRECTION INPUT ;
  USE SIGNAL ;
  PORT
   LAYER M4 ;
   RECT 302.208000 812.172000 302.400000 812.196000 ;
  END
 END po2[319]
 PIN po2[320]
  DIRECTION INPUT ;
  USE SIGNAL ;
  PORT
   LAYER M4 ;
   RECT 302.208000 812.364000 302.400000 812.388000 ;
  END
 END po2[320]
 PIN po2[321]
  DIRECTION INPUT ;
  USE SIGNAL ;
  PORT
   LAYER M4 ;
   RECT 302.208000 812.556000 302.400000 812.580000 ;
  END
 END po2[321]
 PIN po2[322]
  DIRECTION INPUT ;
  USE SIGNAL ;
  PORT
   LAYER M4 ;
   RECT 302.208000 812.748000 302.400000 812.772000 ;
  END
 END po2[322]
 PIN po2[323]
  DIRECTION INPUT ;
  USE SIGNAL ;
  PORT
   LAYER M4 ;
   RECT 302.208000 812.940000 302.400000 812.964000 ;
  END
 END po2[323]
 PIN po2[324]
  DIRECTION INPUT ;
  USE SIGNAL ;
  PORT
   LAYER M4 ;
   RECT 302.208000 813.132000 302.400000 813.156000 ;
  END
 END po2[324]
 PIN po2[325]
  DIRECTION INPUT ;
  USE SIGNAL ;
  PORT
   LAYER M4 ;
   RECT 302.208000 813.324000 302.400000 813.348000 ;
  END
 END po2[325]
 PIN po2[326]
  DIRECTION INPUT ;
  USE SIGNAL ;
  PORT
   LAYER M4 ;
   RECT 302.208000 813.516000 302.400000 813.540000 ;
  END
 END po2[326]
 PIN po2[327]
  DIRECTION INPUT ;
  USE SIGNAL ;
  PORT
   LAYER M4 ;
   RECT 302.208000 813.708000 302.400000 813.732000 ;
  END
 END po2[327]
 PIN pi2[0]
  DIRECTION OUTPUT ;
  USE SIGNAL ;
  PORT
   LAYER M4 ;
   RECT 302.208000 813.900000 302.400000 813.924000 ;
  END
 END pi2[0]
 PIN pi2[1]
  DIRECTION OUTPUT ;
  USE SIGNAL ;
  PORT
   LAYER M4 ;
   RECT 302.208000 814.092000 302.400000 814.116000 ;
  END
 END pi2[1]
 PIN pi2[2]
  DIRECTION OUTPUT ;
  USE SIGNAL ;
  PORT
   LAYER M4 ;
   RECT 302.208000 814.284000 302.400000 814.308000 ;
  END
 END pi2[2]
 PIN pi2[3]
  DIRECTION OUTPUT ;
  USE SIGNAL ;
  PORT
   LAYER M4 ;
   RECT 302.208000 814.476000 302.400000 814.500000 ;
  END
 END pi2[3]
 PIN pi2[4]
  DIRECTION OUTPUT ;
  USE SIGNAL ;
  PORT
   LAYER M4 ;
   RECT 302.208000 814.668000 302.400000 814.692000 ;
  END
 END pi2[4]
 PIN pi2[5]
  DIRECTION OUTPUT ;
  USE SIGNAL ;
  PORT
   LAYER M4 ;
   RECT 302.208000 814.860000 302.400000 814.884000 ;
  END
 END pi2[5]
 PIN pi2[6]
  DIRECTION OUTPUT ;
  USE SIGNAL ;
  PORT
   LAYER M4 ;
   RECT 302.208000 815.052000 302.400000 815.076000 ;
  END
 END pi2[6]
 PIN pi2[7]
  DIRECTION OUTPUT ;
  USE SIGNAL ;
  PORT
   LAYER M4 ;
   RECT 302.208000 815.244000 302.400000 815.268000 ;
  END
 END pi2[7]
 PIN pi2[8]
  DIRECTION OUTPUT ;
  USE SIGNAL ;
  PORT
   LAYER M4 ;
   RECT 302.208000 815.436000 302.400000 815.460000 ;
  END
 END pi2[8]
 PIN pi2[9]
  DIRECTION OUTPUT ;
  USE SIGNAL ;
  PORT
   LAYER M4 ;
   RECT 302.208000 815.628000 302.400000 815.652000 ;
  END
 END pi2[9]
 PIN pi2[10]
  DIRECTION OUTPUT ;
  USE SIGNAL ;
  PORT
   LAYER M4 ;
   RECT 302.208000 815.820000 302.400000 815.844000 ;
  END
 END pi2[10]
 PIN pi2[11]
  DIRECTION OUTPUT ;
  USE SIGNAL ;
  PORT
   LAYER M4 ;
   RECT 302.208000 816.012000 302.400000 816.036000 ;
  END
 END pi2[11]
 PIN pi2[12]
  DIRECTION OUTPUT ;
  USE SIGNAL ;
  PORT
   LAYER M4 ;
   RECT 302.208000 816.204000 302.400000 816.228000 ;
  END
 END pi2[12]
 PIN pi2[13]
  DIRECTION OUTPUT ;
  USE SIGNAL ;
  PORT
   LAYER M4 ;
   RECT 302.208000 816.396000 302.400000 816.420000 ;
  END
 END pi2[13]
 PIN pi2[14]
  DIRECTION OUTPUT ;
  USE SIGNAL ;
  PORT
   LAYER M4 ;
   RECT 302.208000 816.588000 302.400000 816.612000 ;
  END
 END pi2[14]
 PIN pi2[15]
  DIRECTION OUTPUT ;
  USE SIGNAL ;
  PORT
   LAYER M4 ;
   RECT 302.208000 816.780000 302.400000 816.804000 ;
  END
 END pi2[15]
 PIN pi2[16]
  DIRECTION OUTPUT ;
  USE SIGNAL ;
  PORT
   LAYER M4 ;
   RECT 302.208000 816.972000 302.400000 816.996000 ;
  END
 END pi2[16]
 PIN pi2[17]
  DIRECTION OUTPUT ;
  USE SIGNAL ;
  PORT
   LAYER M4 ;
   RECT 302.208000 817.164000 302.400000 817.188000 ;
  END
 END pi2[17]
 PIN pi2[18]
  DIRECTION OUTPUT ;
  USE SIGNAL ;
  PORT
   LAYER M4 ;
   RECT 302.208000 817.356000 302.400000 817.380000 ;
  END
 END pi2[18]
 PIN pi2[19]
  DIRECTION OUTPUT ;
  USE SIGNAL ;
  PORT
   LAYER M4 ;
   RECT 302.208000 817.548000 302.400000 817.572000 ;
  END
 END pi2[19]
 PIN pi2[20]
  DIRECTION OUTPUT ;
  USE SIGNAL ;
  PORT
   LAYER M4 ;
   RECT 302.208000 817.740000 302.400000 817.764000 ;
  END
 END pi2[20]
 PIN pi2[21]
  DIRECTION OUTPUT ;
  USE SIGNAL ;
  PORT
   LAYER M4 ;
   RECT 302.208000 817.932000 302.400000 817.956000 ;
  END
 END pi2[21]
 PIN pi2[22]
  DIRECTION OUTPUT ;
  USE SIGNAL ;
  PORT
   LAYER M4 ;
   RECT 302.208000 818.124000 302.400000 818.148000 ;
  END
 END pi2[22]
 PIN pi2[23]
  DIRECTION OUTPUT ;
  USE SIGNAL ;
  PORT
   LAYER M4 ;
   RECT 302.208000 818.316000 302.400000 818.340000 ;
  END
 END pi2[23]
 PIN pi2[24]
  DIRECTION OUTPUT ;
  USE SIGNAL ;
  PORT
   LAYER M4 ;
   RECT 302.208000 818.508000 302.400000 818.532000 ;
  END
 END pi2[24]
 PIN pi2[25]
  DIRECTION OUTPUT ;
  USE SIGNAL ;
  PORT
   LAYER M4 ;
   RECT 302.208000 818.700000 302.400000 818.724000 ;
  END
 END pi2[25]
 PIN pi2[26]
  DIRECTION OUTPUT ;
  USE SIGNAL ;
  PORT
   LAYER M4 ;
   RECT 302.208000 818.892000 302.400000 818.916000 ;
  END
 END pi2[26]
 PIN pi2[27]
  DIRECTION OUTPUT ;
  USE SIGNAL ;
  PORT
   LAYER M4 ;
   RECT 302.208000 819.084000 302.400000 819.108000 ;
  END
 END pi2[27]
 PIN pi2[28]
  DIRECTION OUTPUT ;
  USE SIGNAL ;
  PORT
   LAYER M4 ;
   RECT 302.208000 819.276000 302.400000 819.300000 ;
  END
 END pi2[28]
 PIN pi2[29]
  DIRECTION OUTPUT ;
  USE SIGNAL ;
  PORT
   LAYER M4 ;
   RECT 302.208000 819.468000 302.400000 819.492000 ;
  END
 END pi2[29]
 PIN pi2[30]
  DIRECTION OUTPUT ;
  USE SIGNAL ;
  PORT
   LAYER M4 ;
   RECT 302.208000 819.660000 302.400000 819.684000 ;
  END
 END pi2[30]
 PIN pi2[31]
  DIRECTION OUTPUT ;
  USE SIGNAL ;
  PORT
   LAYER M4 ;
   RECT 302.208000 819.852000 302.400000 819.876000 ;
  END
 END pi2[31]
 PIN pi2[32]
  DIRECTION OUTPUT ;
  USE SIGNAL ;
  PORT
   LAYER M4 ;
   RECT 302.208000 820.044000 302.400000 820.068000 ;
  END
 END pi2[32]
 PIN pi2[33]
  DIRECTION OUTPUT ;
  USE SIGNAL ;
  PORT
   LAYER M4 ;
   RECT 302.208000 820.236000 302.400000 820.260000 ;
  END
 END pi2[33]
 PIN pi2[34]
  DIRECTION OUTPUT ;
  USE SIGNAL ;
  PORT
   LAYER M4 ;
   RECT 302.208000 820.428000 302.400000 820.452000 ;
  END
 END pi2[34]
 PIN pi2[35]
  DIRECTION OUTPUT ;
  USE SIGNAL ;
  PORT
   LAYER M4 ;
   RECT 302.208000 820.620000 302.400000 820.644000 ;
  END
 END pi2[35]
 PIN pi2[36]
  DIRECTION OUTPUT ;
  USE SIGNAL ;
  PORT
   LAYER M4 ;
   RECT 302.208000 820.812000 302.400000 820.836000 ;
  END
 END pi2[36]
 PIN pi2[37]
  DIRECTION OUTPUT ;
  USE SIGNAL ;
  PORT
   LAYER M4 ;
   RECT 302.208000 821.004000 302.400000 821.028000 ;
  END
 END pi2[37]
 PIN pi2[38]
  DIRECTION OUTPUT ;
  USE SIGNAL ;
  PORT
   LAYER M4 ;
   RECT 302.208000 821.196000 302.400000 821.220000 ;
  END
 END pi2[38]
 PIN pi2[39]
  DIRECTION OUTPUT ;
  USE SIGNAL ;
  PORT
   LAYER M4 ;
   RECT 302.208000 821.388000 302.400000 821.412000 ;
  END
 END pi2[39]
 PIN pi2[40]
  DIRECTION OUTPUT ;
  USE SIGNAL ;
  PORT
   LAYER M4 ;
   RECT 302.208000 821.580000 302.400000 821.604000 ;
  END
 END pi2[40]
 PIN pi2[41]
  DIRECTION OUTPUT ;
  USE SIGNAL ;
  PORT
   LAYER M4 ;
   RECT 302.208000 821.772000 302.400000 821.796000 ;
  END
 END pi2[41]
 PIN pi2[42]
  DIRECTION OUTPUT ;
  USE SIGNAL ;
  PORT
   LAYER M4 ;
   RECT 302.208000 821.964000 302.400000 821.988000 ;
  END
 END pi2[42]
 PIN pi2[43]
  DIRECTION OUTPUT ;
  USE SIGNAL ;
  PORT
   LAYER M4 ;
   RECT 302.208000 822.156000 302.400000 822.180000 ;
  END
 END pi2[43]
 PIN pi2[44]
  DIRECTION OUTPUT ;
  USE SIGNAL ;
  PORT
   LAYER M4 ;
   RECT 302.208000 822.348000 302.400000 822.372000 ;
  END
 END pi2[44]
 PIN pi2[45]
  DIRECTION OUTPUT ;
  USE SIGNAL ;
  PORT
   LAYER M4 ;
   RECT 302.208000 822.540000 302.400000 822.564000 ;
  END
 END pi2[45]
 PIN pi2[46]
  DIRECTION OUTPUT ;
  USE SIGNAL ;
  PORT
   LAYER M4 ;
   RECT 302.208000 822.732000 302.400000 822.756000 ;
  END
 END pi2[46]
 PIN pi2[47]
  DIRECTION OUTPUT ;
  USE SIGNAL ;
  PORT
   LAYER M4 ;
   RECT 302.208000 822.924000 302.400000 822.948000 ;
  END
 END pi2[47]
 PIN pi2[48]
  DIRECTION OUTPUT ;
  USE SIGNAL ;
  PORT
   LAYER M4 ;
   RECT 302.208000 823.116000 302.400000 823.140000 ;
  END
 END pi2[48]
 PIN pi2[49]
  DIRECTION OUTPUT ;
  USE SIGNAL ;
  PORT
   LAYER M4 ;
   RECT 302.208000 823.308000 302.400000 823.332000 ;
  END
 END pi2[49]
 PIN pi2[50]
  DIRECTION OUTPUT ;
  USE SIGNAL ;
  PORT
   LAYER M4 ;
   RECT 302.208000 823.500000 302.400000 823.524000 ;
  END
 END pi2[50]
 PIN pi2[51]
  DIRECTION OUTPUT ;
  USE SIGNAL ;
  PORT
   LAYER M4 ;
   RECT 302.208000 823.692000 302.400000 823.716000 ;
  END
 END pi2[51]
 PIN pi2[52]
  DIRECTION OUTPUT ;
  USE SIGNAL ;
  PORT
   LAYER M4 ;
   RECT 302.208000 823.884000 302.400000 823.908000 ;
  END
 END pi2[52]
 PIN pi2[53]
  DIRECTION OUTPUT ;
  USE SIGNAL ;
  PORT
   LAYER M4 ;
   RECT 302.208000 824.076000 302.400000 824.100000 ;
  END
 END pi2[53]
 PIN pi2[54]
  DIRECTION OUTPUT ;
  USE SIGNAL ;
  PORT
   LAYER M4 ;
   RECT 302.208000 824.268000 302.400000 824.292000 ;
  END
 END pi2[54]
 PIN pi2[55]
  DIRECTION OUTPUT ;
  USE SIGNAL ;
  PORT
   LAYER M4 ;
   RECT 302.208000 824.460000 302.400000 824.484000 ;
  END
 END pi2[55]
 PIN pi2[56]
  DIRECTION OUTPUT ;
  USE SIGNAL ;
  PORT
   LAYER M4 ;
   RECT 302.208000 824.652000 302.400000 824.676000 ;
  END
 END pi2[56]
 PIN pi2[57]
  DIRECTION OUTPUT ;
  USE SIGNAL ;
  PORT
   LAYER M4 ;
   RECT 302.208000 824.844000 302.400000 824.868000 ;
  END
 END pi2[57]
 PIN pi2[58]
  DIRECTION OUTPUT ;
  USE SIGNAL ;
  PORT
   LAYER M4 ;
   RECT 302.208000 825.036000 302.400000 825.060000 ;
  END
 END pi2[58]
 PIN pi2[59]
  DIRECTION OUTPUT ;
  USE SIGNAL ;
  PORT
   LAYER M4 ;
   RECT 302.208000 825.228000 302.400000 825.252000 ;
  END
 END pi2[59]
 PIN pi2[60]
  DIRECTION OUTPUT ;
  USE SIGNAL ;
  PORT
   LAYER M4 ;
   RECT 302.208000 825.420000 302.400000 825.444000 ;
  END
 END pi2[60]
 PIN pi2[61]
  DIRECTION OUTPUT ;
  USE SIGNAL ;
  PORT
   LAYER M4 ;
   RECT 302.208000 825.612000 302.400000 825.636000 ;
  END
 END pi2[61]
 PIN pi2[62]
  DIRECTION OUTPUT ;
  USE SIGNAL ;
  PORT
   LAYER M4 ;
   RECT 302.208000 825.804000 302.400000 825.828000 ;
  END
 END pi2[62]
 PIN pi2[63]
  DIRECTION OUTPUT ;
  USE SIGNAL ;
  PORT
   LAYER M4 ;
   RECT 302.208000 825.996000 302.400000 826.020000 ;
  END
 END pi2[63]
 PIN pi2[64]
  DIRECTION OUTPUT ;
  USE SIGNAL ;
  PORT
   LAYER M4 ;
   RECT 302.208000 826.188000 302.400000 826.212000 ;
  END
 END pi2[64]
 PIN pi2[65]
  DIRECTION OUTPUT ;
  USE SIGNAL ;
  PORT
   LAYER M4 ;
   RECT 302.208000 826.380000 302.400000 826.404000 ;
  END
 END pi2[65]
 PIN pi2[66]
  DIRECTION OUTPUT ;
  USE SIGNAL ;
  PORT
   LAYER M4 ;
   RECT 302.208000 826.572000 302.400000 826.596000 ;
  END
 END pi2[66]
 PIN pi2[67]
  DIRECTION OUTPUT ;
  USE SIGNAL ;
  PORT
   LAYER M4 ;
   RECT 302.208000 826.764000 302.400000 826.788000 ;
  END
 END pi2[67]
 PIN pi2[68]
  DIRECTION OUTPUT ;
  USE SIGNAL ;
  PORT
   LAYER M4 ;
   RECT 302.208000 826.956000 302.400000 826.980000 ;
  END
 END pi2[68]
 PIN pi2[69]
  DIRECTION OUTPUT ;
  USE SIGNAL ;
  PORT
   LAYER M4 ;
   RECT 302.208000 827.148000 302.400000 827.172000 ;
  END
 END pi2[69]
 PIN pi2[70]
  DIRECTION OUTPUT ;
  USE SIGNAL ;
  PORT
   LAYER M4 ;
   RECT 302.208000 827.340000 302.400000 827.364000 ;
  END
 END pi2[70]
 PIN pi2[71]
  DIRECTION OUTPUT ;
  USE SIGNAL ;
  PORT
   LAYER M4 ;
   RECT 302.208000 827.532000 302.400000 827.556000 ;
  END
 END pi2[71]
 PIN pi2[72]
  DIRECTION OUTPUT ;
  USE SIGNAL ;
  PORT
   LAYER M4 ;
   RECT 302.208000 827.724000 302.400000 827.748000 ;
  END
 END pi2[72]
 PIN pi2[73]
  DIRECTION OUTPUT ;
  USE SIGNAL ;
  PORT
   LAYER M4 ;
   RECT 302.208000 827.916000 302.400000 827.940000 ;
  END
 END pi2[73]
 PIN pi2[74]
  DIRECTION OUTPUT ;
  USE SIGNAL ;
  PORT
   LAYER M4 ;
   RECT 302.208000 828.108000 302.400000 828.132000 ;
  END
 END pi2[74]
 PIN pi2[75]
  DIRECTION OUTPUT ;
  USE SIGNAL ;
  PORT
   LAYER M4 ;
   RECT 302.208000 828.300000 302.400000 828.324000 ;
  END
 END pi2[75]
 PIN pi2[76]
  DIRECTION OUTPUT ;
  USE SIGNAL ;
  PORT
   LAYER M4 ;
   RECT 302.208000 828.492000 302.400000 828.516000 ;
  END
 END pi2[76]
 PIN pi2[77]
  DIRECTION OUTPUT ;
  USE SIGNAL ;
  PORT
   LAYER M4 ;
   RECT 302.208000 828.684000 302.400000 828.708000 ;
  END
 END pi2[77]
 PIN pi2[78]
  DIRECTION OUTPUT ;
  USE SIGNAL ;
  PORT
   LAYER M4 ;
   RECT 302.208000 828.876000 302.400000 828.900000 ;
  END
 END pi2[78]
 PIN pi2[79]
  DIRECTION OUTPUT ;
  USE SIGNAL ;
  PORT
   LAYER M4 ;
   RECT 302.208000 829.068000 302.400000 829.092000 ;
  END
 END pi2[79]
 PIN pi2[80]
  DIRECTION OUTPUT ;
  USE SIGNAL ;
  PORT
   LAYER M4 ;
   RECT 302.208000 829.260000 302.400000 829.284000 ;
  END
 END pi2[80]
 PIN pi2[81]
  DIRECTION OUTPUT ;
  USE SIGNAL ;
  PORT
   LAYER M4 ;
   RECT 302.208000 829.452000 302.400000 829.476000 ;
  END
 END pi2[81]
 PIN pi2[82]
  DIRECTION OUTPUT ;
  USE SIGNAL ;
  PORT
   LAYER M4 ;
   RECT 302.208000 829.644000 302.400000 829.668000 ;
  END
 END pi2[82]
 PIN pi2[83]
  DIRECTION OUTPUT ;
  USE SIGNAL ;
  PORT
   LAYER M4 ;
   RECT 302.208000 829.836000 302.400000 829.860000 ;
  END
 END pi2[83]
 PIN pi2[84]
  DIRECTION OUTPUT ;
  USE SIGNAL ;
  PORT
   LAYER M4 ;
   RECT 302.208000 830.028000 302.400000 830.052000 ;
  END
 END pi2[84]
 PIN pi2[85]
  DIRECTION OUTPUT ;
  USE SIGNAL ;
  PORT
   LAYER M4 ;
   RECT 302.208000 830.220000 302.400000 830.244000 ;
  END
 END pi2[85]
 PIN pi2[86]
  DIRECTION OUTPUT ;
  USE SIGNAL ;
  PORT
   LAYER M4 ;
   RECT 302.208000 830.412000 302.400000 830.436000 ;
  END
 END pi2[86]
 PIN pi2[87]
  DIRECTION OUTPUT ;
  USE SIGNAL ;
  PORT
   LAYER M4 ;
   RECT 302.208000 830.604000 302.400000 830.628000 ;
  END
 END pi2[87]
 PIN pi2[88]
  DIRECTION OUTPUT ;
  USE SIGNAL ;
  PORT
   LAYER M4 ;
   RECT 302.208000 830.796000 302.400000 830.820000 ;
  END
 END pi2[88]
 PIN pi2[89]
  DIRECTION OUTPUT ;
  USE SIGNAL ;
  PORT
   LAYER M4 ;
   RECT 302.208000 830.988000 302.400000 831.012000 ;
  END
 END pi2[89]
 PIN pi2[90]
  DIRECTION OUTPUT ;
  USE SIGNAL ;
  PORT
   LAYER M4 ;
   RECT 302.208000 831.180000 302.400000 831.204000 ;
  END
 END pi2[90]
 PIN pi2[91]
  DIRECTION OUTPUT ;
  USE SIGNAL ;
  PORT
   LAYER M4 ;
   RECT 302.208000 831.372000 302.400000 831.396000 ;
  END
 END pi2[91]
 PIN pi2[92]
  DIRECTION OUTPUT ;
  USE SIGNAL ;
  PORT
   LAYER M4 ;
   RECT 302.208000 831.564000 302.400000 831.588000 ;
  END
 END pi2[92]
 PIN pi2[93]
  DIRECTION OUTPUT ;
  USE SIGNAL ;
  PORT
   LAYER M4 ;
   RECT 302.208000 831.756000 302.400000 831.780000 ;
  END
 END pi2[93]
 PIN pi2[94]
  DIRECTION OUTPUT ;
  USE SIGNAL ;
  PORT
   LAYER M4 ;
   RECT 302.208000 831.948000 302.400000 831.972000 ;
  END
 END pi2[94]
 PIN pi2[95]
  DIRECTION OUTPUT ;
  USE SIGNAL ;
  PORT
   LAYER M4 ;
   RECT 302.208000 832.140000 302.400000 832.164000 ;
  END
 END pi2[95]
 PIN pi2[96]
  DIRECTION OUTPUT ;
  USE SIGNAL ;
  PORT
   LAYER M4 ;
   RECT 302.208000 832.332000 302.400000 832.356000 ;
  END
 END pi2[96]
 PIN pi2[97]
  DIRECTION OUTPUT ;
  USE SIGNAL ;
  PORT
   LAYER M4 ;
   RECT 302.208000 832.524000 302.400000 832.548000 ;
  END
 END pi2[97]
 PIN pi2[98]
  DIRECTION OUTPUT ;
  USE SIGNAL ;
  PORT
   LAYER M4 ;
   RECT 302.208000 832.716000 302.400000 832.740000 ;
  END
 END pi2[98]
 PIN pi2[99]
  DIRECTION OUTPUT ;
  USE SIGNAL ;
  PORT
   LAYER M4 ;
   RECT 302.208000 832.908000 302.400000 832.932000 ;
  END
 END pi2[99]
 PIN pi2[100]
  DIRECTION OUTPUT ;
  USE SIGNAL ;
  PORT
   LAYER M4 ;
   RECT 302.208000 833.100000 302.400000 833.124000 ;
  END
 END pi2[100]
 PIN pi2[101]
  DIRECTION OUTPUT ;
  USE SIGNAL ;
  PORT
   LAYER M4 ;
   RECT 302.208000 833.292000 302.400000 833.316000 ;
  END
 END pi2[101]
 PIN pi2[102]
  DIRECTION OUTPUT ;
  USE SIGNAL ;
  PORT
   LAYER M4 ;
   RECT 302.208000 833.484000 302.400000 833.508000 ;
  END
 END pi2[102]
 PIN pi2[103]
  DIRECTION OUTPUT ;
  USE SIGNAL ;
  PORT
   LAYER M4 ;
   RECT 302.208000 833.676000 302.400000 833.700000 ;
  END
 END pi2[103]
 PIN pi2[104]
  DIRECTION OUTPUT ;
  USE SIGNAL ;
  PORT
   LAYER M4 ;
   RECT 302.208000 833.868000 302.400000 833.892000 ;
  END
 END pi2[104]
 PIN pi2[105]
  DIRECTION OUTPUT ;
  USE SIGNAL ;
  PORT
   LAYER M4 ;
   RECT 302.208000 834.060000 302.400000 834.084000 ;
  END
 END pi2[105]
 PIN pi2[106]
  DIRECTION OUTPUT ;
  USE SIGNAL ;
  PORT
   LAYER M4 ;
   RECT 302.208000 834.252000 302.400000 834.276000 ;
  END
 END pi2[106]
 PIN pi2[107]
  DIRECTION OUTPUT ;
  USE SIGNAL ;
  PORT
   LAYER M4 ;
   RECT 302.208000 834.444000 302.400000 834.468000 ;
  END
 END pi2[107]
 PIN pi2[108]
  DIRECTION OUTPUT ;
  USE SIGNAL ;
  PORT
   LAYER M4 ;
   RECT 302.208000 834.636000 302.400000 834.660000 ;
  END
 END pi2[108]
 PIN pi2[109]
  DIRECTION OUTPUT ;
  USE SIGNAL ;
  PORT
   LAYER M4 ;
   RECT 302.208000 834.828000 302.400000 834.852000 ;
  END
 END pi2[109]
 PIN pi2[110]
  DIRECTION OUTPUT ;
  USE SIGNAL ;
  PORT
   LAYER M4 ;
   RECT 302.208000 835.020000 302.400000 835.044000 ;
  END
 END pi2[110]
 PIN pi2[111]
  DIRECTION OUTPUT ;
  USE SIGNAL ;
  PORT
   LAYER M4 ;
   RECT 302.208000 835.212000 302.400000 835.236000 ;
  END
 END pi2[111]
 PIN pi2[112]
  DIRECTION OUTPUT ;
  USE SIGNAL ;
  PORT
   LAYER M4 ;
   RECT 302.208000 835.404000 302.400000 835.428000 ;
  END
 END pi2[112]
 PIN pi2[113]
  DIRECTION OUTPUT ;
  USE SIGNAL ;
  PORT
   LAYER M4 ;
   RECT 302.208000 835.596000 302.400000 835.620000 ;
  END
 END pi2[113]
 PIN pi2[114]
  DIRECTION OUTPUT ;
  USE SIGNAL ;
  PORT
   LAYER M4 ;
   RECT 302.208000 835.788000 302.400000 835.812000 ;
  END
 END pi2[114]
 PIN pi2[115]
  DIRECTION OUTPUT ;
  USE SIGNAL ;
  PORT
   LAYER M4 ;
   RECT 302.208000 835.980000 302.400000 836.004000 ;
  END
 END pi2[115]
 PIN pi2[116]
  DIRECTION OUTPUT ;
  USE SIGNAL ;
  PORT
   LAYER M4 ;
   RECT 302.208000 836.172000 302.400000 836.196000 ;
  END
 END pi2[116]
 PIN pi2[117]
  DIRECTION OUTPUT ;
  USE SIGNAL ;
  PORT
   LAYER M4 ;
   RECT 302.208000 836.364000 302.400000 836.388000 ;
  END
 END pi2[117]
 PIN pi2[118]
  DIRECTION OUTPUT ;
  USE SIGNAL ;
  PORT
   LAYER M4 ;
   RECT 302.208000 836.556000 302.400000 836.580000 ;
  END
 END pi2[118]
 PIN pi2[119]
  DIRECTION OUTPUT ;
  USE SIGNAL ;
  PORT
   LAYER M4 ;
   RECT 302.208000 836.748000 302.400000 836.772000 ;
  END
 END pi2[119]
 PIN pi2[120]
  DIRECTION OUTPUT ;
  USE SIGNAL ;
  PORT
   LAYER M4 ;
   RECT 302.208000 836.940000 302.400000 836.964000 ;
  END
 END pi2[120]
 PIN pi2[121]
  DIRECTION OUTPUT ;
  USE SIGNAL ;
  PORT
   LAYER M4 ;
   RECT 302.208000 837.132000 302.400000 837.156000 ;
  END
 END pi2[121]
 PIN pi2[122]
  DIRECTION OUTPUT ;
  USE SIGNAL ;
  PORT
   LAYER M4 ;
   RECT 302.208000 837.324000 302.400000 837.348000 ;
  END
 END pi2[122]
 PIN pi2[123]
  DIRECTION OUTPUT ;
  USE SIGNAL ;
  PORT
   LAYER M4 ;
   RECT 302.208000 837.516000 302.400000 837.540000 ;
  END
 END pi2[123]
 PIN pi2[124]
  DIRECTION OUTPUT ;
  USE SIGNAL ;
  PORT
   LAYER M4 ;
   RECT 302.208000 837.708000 302.400000 837.732000 ;
  END
 END pi2[124]
 PIN pi2[125]
  DIRECTION OUTPUT ;
  USE SIGNAL ;
  PORT
   LAYER M4 ;
   RECT 302.208000 837.900000 302.400000 837.924000 ;
  END
 END pi2[125]
 PIN pi2[126]
  DIRECTION OUTPUT ;
  USE SIGNAL ;
  PORT
   LAYER M4 ;
   RECT 302.208000 838.092000 302.400000 838.116000 ;
  END
 END pi2[126]
 PIN pi2[127]
  DIRECTION OUTPUT ;
  USE SIGNAL ;
  PORT
   LAYER M4 ;
   RECT 302.208000 838.284000 302.400000 838.308000 ;
  END
 END pi2[127]
 PIN pi2[128]
  DIRECTION OUTPUT ;
  USE SIGNAL ;
  PORT
   LAYER M4 ;
   RECT 302.208000 838.476000 302.400000 838.500000 ;
  END
 END pi2[128]
 PIN pi2[129]
  DIRECTION OUTPUT ;
  USE SIGNAL ;
  PORT
   LAYER M4 ;
   RECT 302.208000 838.668000 302.400000 838.692000 ;
  END
 END pi2[129]
 PIN pi2[130]
  DIRECTION OUTPUT ;
  USE SIGNAL ;
  PORT
   LAYER M4 ;
   RECT 302.208000 838.860000 302.400000 838.884000 ;
  END
 END pi2[130]
 PIN pi2[131]
  DIRECTION OUTPUT ;
  USE SIGNAL ;
  PORT
   LAYER M4 ;
   RECT 302.208000 839.052000 302.400000 839.076000 ;
  END
 END pi2[131]
 PIN pi2[132]
  DIRECTION OUTPUT ;
  USE SIGNAL ;
  PORT
   LAYER M4 ;
   RECT 302.208000 839.244000 302.400000 839.268000 ;
  END
 END pi2[132]
 PIN pi2[133]
  DIRECTION OUTPUT ;
  USE SIGNAL ;
  PORT
   LAYER M4 ;
   RECT 302.208000 839.436000 302.400000 839.460000 ;
  END
 END pi2[133]
 PIN pi2[134]
  DIRECTION OUTPUT ;
  USE SIGNAL ;
  PORT
   LAYER M4 ;
   RECT 302.208000 839.628000 302.400000 839.652000 ;
  END
 END pi2[134]
 PIN pi2[135]
  DIRECTION OUTPUT ;
  USE SIGNAL ;
  PORT
   LAYER M4 ;
   RECT 302.208000 839.820000 302.400000 839.844000 ;
  END
 END pi2[135]
 PIN pi2[136]
  DIRECTION OUTPUT ;
  USE SIGNAL ;
  PORT
   LAYER M4 ;
   RECT 302.208000 840.012000 302.400000 840.036000 ;
  END
 END pi2[136]
 PIN pi2[137]
  DIRECTION OUTPUT ;
  USE SIGNAL ;
  PORT
   LAYER M4 ;
   RECT 302.208000 840.204000 302.400000 840.228000 ;
  END
 END pi2[137]
 PIN pi2[138]
  DIRECTION OUTPUT ;
  USE SIGNAL ;
  PORT
   LAYER M4 ;
   RECT 302.208000 840.396000 302.400000 840.420000 ;
  END
 END pi2[138]
 PIN pi2[139]
  DIRECTION OUTPUT ;
  USE SIGNAL ;
  PORT
   LAYER M4 ;
   RECT 302.208000 840.588000 302.400000 840.612000 ;
  END
 END pi2[139]
 PIN pi2[140]
  DIRECTION OUTPUT ;
  USE SIGNAL ;
  PORT
   LAYER M4 ;
   RECT 302.208000 840.780000 302.400000 840.804000 ;
  END
 END pi2[140]
 PIN pi2[141]
  DIRECTION OUTPUT ;
  USE SIGNAL ;
  PORT
   LAYER M4 ;
   RECT 302.208000 840.972000 302.400000 840.996000 ;
  END
 END pi2[141]
 PIN pi2[142]
  DIRECTION OUTPUT ;
  USE SIGNAL ;
  PORT
   LAYER M4 ;
   RECT 302.208000 841.164000 302.400000 841.188000 ;
  END
 END pi2[142]
 PIN pi2[143]
  DIRECTION OUTPUT ;
  USE SIGNAL ;
  PORT
   LAYER M4 ;
   RECT 302.208000 841.356000 302.400000 841.380000 ;
  END
 END pi2[143]
 PIN pi2[144]
  DIRECTION OUTPUT ;
  USE SIGNAL ;
  PORT
   LAYER M4 ;
   RECT 302.208000 841.548000 302.400000 841.572000 ;
  END
 END pi2[144]
 PIN pi2[145]
  DIRECTION OUTPUT ;
  USE SIGNAL ;
  PORT
   LAYER M4 ;
   RECT 302.208000 841.740000 302.400000 841.764000 ;
  END
 END pi2[145]
 PIN pi2[146]
  DIRECTION OUTPUT ;
  USE SIGNAL ;
  PORT
   LAYER M4 ;
   RECT 302.208000 841.932000 302.400000 841.956000 ;
  END
 END pi2[146]
 PIN pi2[147]
  DIRECTION OUTPUT ;
  USE SIGNAL ;
  PORT
   LAYER M4 ;
   RECT 302.208000 842.124000 302.400000 842.148000 ;
  END
 END pi2[147]
 PIN pi2[148]
  DIRECTION OUTPUT ;
  USE SIGNAL ;
  PORT
   LAYER M4 ;
   RECT 302.208000 842.316000 302.400000 842.340000 ;
  END
 END pi2[148]
 PIN pi2[149]
  DIRECTION OUTPUT ;
  USE SIGNAL ;
  PORT
   LAYER M4 ;
   RECT 302.208000 842.508000 302.400000 842.532000 ;
  END
 END pi2[149]
 PIN pi2[150]
  DIRECTION OUTPUT ;
  USE SIGNAL ;
  PORT
   LAYER M4 ;
   RECT 302.208000 842.700000 302.400000 842.724000 ;
  END
 END pi2[150]
 PIN pi2[151]
  DIRECTION OUTPUT ;
  USE SIGNAL ;
  PORT
   LAYER M4 ;
   RECT 302.208000 842.892000 302.400000 842.916000 ;
  END
 END pi2[151]
 PIN pi2[152]
  DIRECTION OUTPUT ;
  USE SIGNAL ;
  PORT
   LAYER M4 ;
   RECT 302.208000 843.084000 302.400000 843.108000 ;
  END
 END pi2[152]
 PIN pi2[153]
  DIRECTION OUTPUT ;
  USE SIGNAL ;
  PORT
   LAYER M4 ;
   RECT 302.208000 843.276000 302.400000 843.300000 ;
  END
 END pi2[153]
 PIN pi2[154]
  DIRECTION OUTPUT ;
  USE SIGNAL ;
  PORT
   LAYER M4 ;
   RECT 302.208000 843.468000 302.400000 843.492000 ;
  END
 END pi2[154]
 PIN pi2[155]
  DIRECTION OUTPUT ;
  USE SIGNAL ;
  PORT
   LAYER M4 ;
   RECT 302.208000 843.660000 302.400000 843.684000 ;
  END
 END pi2[155]
 PIN pi2[156]
  DIRECTION OUTPUT ;
  USE SIGNAL ;
  PORT
   LAYER M4 ;
   RECT 302.208000 843.852000 302.400000 843.876000 ;
  END
 END pi2[156]
 PIN pi2[157]
  DIRECTION OUTPUT ;
  USE SIGNAL ;
  PORT
   LAYER M4 ;
   RECT 302.208000 844.044000 302.400000 844.068000 ;
  END
 END pi2[157]
 PIN pi2[158]
  DIRECTION OUTPUT ;
  USE SIGNAL ;
  PORT
   LAYER M4 ;
   RECT 302.208000 844.236000 302.400000 844.260000 ;
  END
 END pi2[158]
 PIN pi2[159]
  DIRECTION OUTPUT ;
  USE SIGNAL ;
  PORT
   LAYER M4 ;
   RECT 302.208000 844.428000 302.400000 844.452000 ;
  END
 END pi2[159]
 PIN pi2[160]
  DIRECTION OUTPUT ;
  USE SIGNAL ;
  PORT
   LAYER M4 ;
   RECT 302.208000 844.620000 302.400000 844.644000 ;
  END
 END pi2[160]
 PIN pi2[161]
  DIRECTION OUTPUT ;
  USE SIGNAL ;
  PORT
   LAYER M4 ;
   RECT 302.208000 844.812000 302.400000 844.836000 ;
  END
 END pi2[161]
 PIN pi2[162]
  DIRECTION OUTPUT ;
  USE SIGNAL ;
  PORT
   LAYER M4 ;
   RECT 302.208000 845.004000 302.400000 845.028000 ;
  END
 END pi2[162]
 PIN pi2[163]
  DIRECTION OUTPUT ;
  USE SIGNAL ;
  PORT
   LAYER M4 ;
   RECT 302.208000 845.196000 302.400000 845.220000 ;
  END
 END pi2[163]
 PIN pi2[164]
  DIRECTION OUTPUT ;
  USE SIGNAL ;
  PORT
   LAYER M4 ;
   RECT 302.208000 845.388000 302.400000 845.412000 ;
  END
 END pi2[164]
 PIN pi2[165]
  DIRECTION OUTPUT ;
  USE SIGNAL ;
  PORT
   LAYER M4 ;
   RECT 302.208000 845.580000 302.400000 845.604000 ;
  END
 END pi2[165]
 PIN pi2[166]
  DIRECTION OUTPUT ;
  USE SIGNAL ;
  PORT
   LAYER M4 ;
   RECT 302.208000 845.772000 302.400000 845.796000 ;
  END
 END pi2[166]
 PIN pi2[167]
  DIRECTION OUTPUT ;
  USE SIGNAL ;
  PORT
   LAYER M4 ;
   RECT 302.208000 845.964000 302.400000 845.988000 ;
  END
 END pi2[167]
 PIN pi2[168]
  DIRECTION OUTPUT ;
  USE SIGNAL ;
  PORT
   LAYER M4 ;
   RECT 302.208000 846.156000 302.400000 846.180000 ;
  END
 END pi2[168]
 PIN pi2[169]
  DIRECTION OUTPUT ;
  USE SIGNAL ;
  PORT
   LAYER M4 ;
   RECT 302.208000 846.348000 302.400000 846.372000 ;
  END
 END pi2[169]
 PIN pi2[170]
  DIRECTION OUTPUT ;
  USE SIGNAL ;
  PORT
   LAYER M4 ;
   RECT 302.208000 846.540000 302.400000 846.564000 ;
  END
 END pi2[170]
 PIN pi2[171]
  DIRECTION OUTPUT ;
  USE SIGNAL ;
  PORT
   LAYER M4 ;
   RECT 302.208000 846.732000 302.400000 846.756000 ;
  END
 END pi2[171]
 PIN pi2[172]
  DIRECTION OUTPUT ;
  USE SIGNAL ;
  PORT
   LAYER M4 ;
   RECT 302.208000 846.924000 302.400000 846.948000 ;
  END
 END pi2[172]
 PIN pi2[173]
  DIRECTION OUTPUT ;
  USE SIGNAL ;
  PORT
   LAYER M4 ;
   RECT 302.208000 847.116000 302.400000 847.140000 ;
  END
 END pi2[173]
 PIN pi2[174]
  DIRECTION OUTPUT ;
  USE SIGNAL ;
  PORT
   LAYER M4 ;
   RECT 302.208000 847.308000 302.400000 847.332000 ;
  END
 END pi2[174]
 PIN pi2[175]
  DIRECTION OUTPUT ;
  USE SIGNAL ;
  PORT
   LAYER M4 ;
   RECT 302.208000 847.500000 302.400000 847.524000 ;
  END
 END pi2[175]
 PIN pi2[176]
  DIRECTION OUTPUT ;
  USE SIGNAL ;
  PORT
   LAYER M4 ;
   RECT 302.208000 847.692000 302.400000 847.716000 ;
  END
 END pi2[176]
 PIN pi2[177]
  DIRECTION OUTPUT ;
  USE SIGNAL ;
  PORT
   LAYER M4 ;
   RECT 302.208000 847.884000 302.400000 847.908000 ;
  END
 END pi2[177]
 PIN pi2[178]
  DIRECTION OUTPUT ;
  USE SIGNAL ;
  PORT
   LAYER M4 ;
   RECT 302.208000 848.076000 302.400000 848.100000 ;
  END
 END pi2[178]
 PIN pi2[179]
  DIRECTION OUTPUT ;
  USE SIGNAL ;
  PORT
   LAYER M4 ;
   RECT 302.208000 848.268000 302.400000 848.292000 ;
  END
 END pi2[179]
 PIN pi2[180]
  DIRECTION OUTPUT ;
  USE SIGNAL ;
  PORT
   LAYER M4 ;
   RECT 302.208000 848.460000 302.400000 848.484000 ;
  END
 END pi2[180]
 PIN pi2[181]
  DIRECTION OUTPUT ;
  USE SIGNAL ;
  PORT
   LAYER M4 ;
   RECT 302.208000 848.652000 302.400000 848.676000 ;
  END
 END pi2[181]
 PIN pi2[182]
  DIRECTION OUTPUT ;
  USE SIGNAL ;
  PORT
   LAYER M4 ;
   RECT 302.208000 848.844000 302.400000 848.868000 ;
  END
 END pi2[182]
 PIN pi2[183]
  DIRECTION OUTPUT ;
  USE SIGNAL ;
  PORT
   LAYER M4 ;
   RECT 302.208000 849.036000 302.400000 849.060000 ;
  END
 END pi2[183]
 PIN pi2[184]
  DIRECTION OUTPUT ;
  USE SIGNAL ;
  PORT
   LAYER M4 ;
   RECT 302.208000 849.228000 302.400000 849.252000 ;
  END
 END pi2[184]
 PIN pi2[185]
  DIRECTION OUTPUT ;
  USE SIGNAL ;
  PORT
   LAYER M4 ;
   RECT 302.208000 849.420000 302.400000 849.444000 ;
  END
 END pi2[185]
 PIN pi2[186]
  DIRECTION OUTPUT ;
  USE SIGNAL ;
  PORT
   LAYER M4 ;
   RECT 302.208000 849.612000 302.400000 849.636000 ;
  END
 END pi2[186]
 PIN pi2[187]
  DIRECTION OUTPUT ;
  USE SIGNAL ;
  PORT
   LAYER M4 ;
   RECT 302.208000 849.804000 302.400000 849.828000 ;
  END
 END pi2[187]
 PIN pi2[188]
  DIRECTION OUTPUT ;
  USE SIGNAL ;
  PORT
   LAYER M4 ;
   RECT 302.208000 849.996000 302.400000 850.020000 ;
  END
 END pi2[188]
 PIN pi2[189]
  DIRECTION OUTPUT ;
  USE SIGNAL ;
  PORT
   LAYER M4 ;
   RECT 302.208000 850.188000 302.400000 850.212000 ;
  END
 END pi2[189]
 PIN pi2[190]
  DIRECTION OUTPUT ;
  USE SIGNAL ;
  PORT
   LAYER M4 ;
   RECT 302.208000 850.380000 302.400000 850.404000 ;
  END
 END pi2[190]
 PIN pi2[191]
  DIRECTION OUTPUT ;
  USE SIGNAL ;
  PORT
   LAYER M4 ;
   RECT 302.208000 850.572000 302.400000 850.596000 ;
  END
 END pi2[191]
 PIN pi2[192]
  DIRECTION OUTPUT ;
  USE SIGNAL ;
  PORT
   LAYER M4 ;
   RECT 302.208000 850.764000 302.400000 850.788000 ;
  END
 END pi2[192]
 PIN pi2[193]
  DIRECTION OUTPUT ;
  USE SIGNAL ;
  PORT
   LAYER M4 ;
   RECT 302.208000 850.956000 302.400000 850.980000 ;
  END
 END pi2[193]
 PIN pi2[194]
  DIRECTION OUTPUT ;
  USE SIGNAL ;
  PORT
   LAYER M4 ;
   RECT 302.208000 851.148000 302.400000 851.172000 ;
  END
 END pi2[194]
 PIN pi2[195]
  DIRECTION OUTPUT ;
  USE SIGNAL ;
  PORT
   LAYER M4 ;
   RECT 302.208000 851.340000 302.400000 851.364000 ;
  END
 END pi2[195]
 PIN pi2[196]
  DIRECTION OUTPUT ;
  USE SIGNAL ;
  PORT
   LAYER M4 ;
   RECT 302.208000 851.532000 302.400000 851.556000 ;
  END
 END pi2[196]
 PIN pi2[197]
  DIRECTION OUTPUT ;
  USE SIGNAL ;
  PORT
   LAYER M4 ;
   RECT 302.208000 851.724000 302.400000 851.748000 ;
  END
 END pi2[197]
 PIN pi2[198]
  DIRECTION OUTPUT ;
  USE SIGNAL ;
  PORT
   LAYER M4 ;
   RECT 302.208000 851.916000 302.400000 851.940000 ;
  END
 END pi2[198]
 PIN pi2[199]
  DIRECTION OUTPUT ;
  USE SIGNAL ;
  PORT
   LAYER M4 ;
   RECT 302.208000 852.108000 302.400000 852.132000 ;
  END
 END pi2[199]
 PIN pi2[200]
  DIRECTION OUTPUT ;
  USE SIGNAL ;
  PORT
   LAYER M4 ;
   RECT 302.208000 852.300000 302.400000 852.324000 ;
  END
 END pi2[200]
 PIN pi2[201]
  DIRECTION OUTPUT ;
  USE SIGNAL ;
  PORT
   LAYER M4 ;
   RECT 302.208000 852.492000 302.400000 852.516000 ;
  END
 END pi2[201]
 PIN pi2[202]
  DIRECTION OUTPUT ;
  USE SIGNAL ;
  PORT
   LAYER M4 ;
   RECT 302.208000 852.684000 302.400000 852.708000 ;
  END
 END pi2[202]
 PIN pi2[203]
  DIRECTION OUTPUT ;
  USE SIGNAL ;
  PORT
   LAYER M4 ;
   RECT 302.208000 852.876000 302.400000 852.900000 ;
  END
 END pi2[203]
 PIN pi2[204]
  DIRECTION OUTPUT ;
  USE SIGNAL ;
  PORT
   LAYER M4 ;
   RECT 302.208000 853.068000 302.400000 853.092000 ;
  END
 END pi2[204]
 PIN pi2[205]
  DIRECTION OUTPUT ;
  USE SIGNAL ;
  PORT
   LAYER M4 ;
   RECT 302.208000 853.260000 302.400000 853.284000 ;
  END
 END pi2[205]
 PIN pi2[206]
  DIRECTION OUTPUT ;
  USE SIGNAL ;
  PORT
   LAYER M4 ;
   RECT 302.208000 853.452000 302.400000 853.476000 ;
  END
 END pi2[206]
 PIN pi2[207]
  DIRECTION OUTPUT ;
  USE SIGNAL ;
  PORT
   LAYER M4 ;
   RECT 302.208000 853.644000 302.400000 853.668000 ;
  END
 END pi2[207]
 PIN pi2[208]
  DIRECTION OUTPUT ;
  USE SIGNAL ;
  PORT
   LAYER M4 ;
   RECT 302.208000 853.836000 302.400000 853.860000 ;
  END
 END pi2[208]
 PIN pi2[209]
  DIRECTION OUTPUT ;
  USE SIGNAL ;
  PORT
   LAYER M4 ;
   RECT 302.208000 854.028000 302.400000 854.052000 ;
  END
 END pi2[209]
 PIN pi2[210]
  DIRECTION OUTPUT ;
  USE SIGNAL ;
  PORT
   LAYER M4 ;
   RECT 302.208000 854.220000 302.400000 854.244000 ;
  END
 END pi2[210]
 PIN pi2[211]
  DIRECTION OUTPUT ;
  USE SIGNAL ;
  PORT
   LAYER M4 ;
   RECT 302.208000 854.412000 302.400000 854.436000 ;
  END
 END pi2[211]
 PIN pi2[212]
  DIRECTION OUTPUT ;
  USE SIGNAL ;
  PORT
   LAYER M4 ;
   RECT 302.208000 854.604000 302.400000 854.628000 ;
  END
 END pi2[212]
 PIN pi2[213]
  DIRECTION OUTPUT ;
  USE SIGNAL ;
  PORT
   LAYER M4 ;
   RECT 302.208000 854.796000 302.400000 854.820000 ;
  END
 END pi2[213]
 PIN pi2[214]
  DIRECTION OUTPUT ;
  USE SIGNAL ;
  PORT
   LAYER M4 ;
   RECT 302.208000 854.988000 302.400000 855.012000 ;
  END
 END pi2[214]
 PIN pi2[215]
  DIRECTION OUTPUT ;
  USE SIGNAL ;
  PORT
   LAYER M4 ;
   RECT 302.208000 855.180000 302.400000 855.204000 ;
  END
 END pi2[215]
 PIN pi2[216]
  DIRECTION OUTPUT ;
  USE SIGNAL ;
  PORT
   LAYER M4 ;
   RECT 302.208000 855.372000 302.400000 855.396000 ;
  END
 END pi2[216]
 PIN pi2[217]
  DIRECTION OUTPUT ;
  USE SIGNAL ;
  PORT
   LAYER M4 ;
   RECT 302.208000 855.564000 302.400000 855.588000 ;
  END
 END pi2[217]
 PIN pi2[218]
  DIRECTION OUTPUT ;
  USE SIGNAL ;
  PORT
   LAYER M4 ;
   RECT 302.208000 855.756000 302.400000 855.780000 ;
  END
 END pi2[218]
 PIN pi2[219]
  DIRECTION OUTPUT ;
  USE SIGNAL ;
  PORT
   LAYER M4 ;
   RECT 302.208000 855.948000 302.400000 855.972000 ;
  END
 END pi2[219]
 PIN pi2[220]
  DIRECTION OUTPUT ;
  USE SIGNAL ;
  PORT
   LAYER M4 ;
   RECT 302.208000 856.140000 302.400000 856.164000 ;
  END
 END pi2[220]
 PIN pi2[221]
  DIRECTION OUTPUT ;
  USE SIGNAL ;
  PORT
   LAYER M4 ;
   RECT 302.208000 856.332000 302.400000 856.356000 ;
  END
 END pi2[221]
 PIN pi2[222]
  DIRECTION OUTPUT ;
  USE SIGNAL ;
  PORT
   LAYER M4 ;
   RECT 302.208000 856.524000 302.400000 856.548000 ;
  END
 END pi2[222]
 PIN pi2[223]
  DIRECTION OUTPUT ;
  USE SIGNAL ;
  PORT
   LAYER M4 ;
   RECT 302.208000 856.716000 302.400000 856.740000 ;
  END
 END pi2[223]
 PIN pi2[224]
  DIRECTION OUTPUT ;
  USE SIGNAL ;
  PORT
   LAYER M4 ;
   RECT 302.208000 856.908000 302.400000 856.932000 ;
  END
 END pi2[224]
 PIN pi2[225]
  DIRECTION OUTPUT ;
  USE SIGNAL ;
  PORT
   LAYER M4 ;
   RECT 302.208000 857.100000 302.400000 857.124000 ;
  END
 END pi2[225]
 PIN pi2[226]
  DIRECTION OUTPUT ;
  USE SIGNAL ;
  PORT
   LAYER M4 ;
   RECT 302.208000 857.292000 302.400000 857.316000 ;
  END
 END pi2[226]
 PIN pi2[227]
  DIRECTION OUTPUT ;
  USE SIGNAL ;
  PORT
   LAYER M4 ;
   RECT 302.208000 857.484000 302.400000 857.508000 ;
  END
 END pi2[227]
 PIN pi2[228]
  DIRECTION OUTPUT ;
  USE SIGNAL ;
  PORT
   LAYER M4 ;
   RECT 302.208000 857.676000 302.400000 857.700000 ;
  END
 END pi2[228]
 PIN pi2[229]
  DIRECTION OUTPUT ;
  USE SIGNAL ;
  PORT
   LAYER M4 ;
   RECT 302.208000 857.868000 302.400000 857.892000 ;
  END
 END pi2[229]
 PIN pi2[230]
  DIRECTION OUTPUT ;
  USE SIGNAL ;
  PORT
   LAYER M4 ;
   RECT 302.208000 858.060000 302.400000 858.084000 ;
  END
 END pi2[230]
 PIN pi2[231]
  DIRECTION OUTPUT ;
  USE SIGNAL ;
  PORT
   LAYER M4 ;
   RECT 302.208000 858.252000 302.400000 858.276000 ;
  END
 END pi2[231]
 PIN pi2[232]
  DIRECTION OUTPUT ;
  USE SIGNAL ;
  PORT
   LAYER M4 ;
   RECT 302.208000 858.444000 302.400000 858.468000 ;
  END
 END pi2[232]
 PIN pi2[233]
  DIRECTION OUTPUT ;
  USE SIGNAL ;
  PORT
   LAYER M4 ;
   RECT 302.208000 858.636000 302.400000 858.660000 ;
  END
 END pi2[233]
 PIN pi2[234]
  DIRECTION OUTPUT ;
  USE SIGNAL ;
  PORT
   LAYER M4 ;
   RECT 302.208000 858.828000 302.400000 858.852000 ;
  END
 END pi2[234]
 PIN pi2[235]
  DIRECTION OUTPUT ;
  USE SIGNAL ;
  PORT
   LAYER M4 ;
   RECT 302.208000 859.020000 302.400000 859.044000 ;
  END
 END pi2[235]
 PIN pi2[236]
  DIRECTION OUTPUT ;
  USE SIGNAL ;
  PORT
   LAYER M4 ;
   RECT 302.208000 859.212000 302.400000 859.236000 ;
  END
 END pi2[236]
 PIN pi2[237]
  DIRECTION OUTPUT ;
  USE SIGNAL ;
  PORT
   LAYER M4 ;
   RECT 302.208000 859.404000 302.400000 859.428000 ;
  END
 END pi2[237]
 PIN pi2[238]
  DIRECTION OUTPUT ;
  USE SIGNAL ;
  PORT
   LAYER M4 ;
   RECT 302.208000 859.596000 302.400000 859.620000 ;
  END
 END pi2[238]
 PIN pi2[239]
  DIRECTION OUTPUT ;
  USE SIGNAL ;
  PORT
   LAYER M4 ;
   RECT 302.208000 859.788000 302.400000 859.812000 ;
  END
 END pi2[239]
 PIN pi2[240]
  DIRECTION OUTPUT ;
  USE SIGNAL ;
  PORT
   LAYER M4 ;
   RECT 302.208000 859.980000 302.400000 860.004000 ;
  END
 END pi2[240]
 PIN pi2[241]
  DIRECTION OUTPUT ;
  USE SIGNAL ;
  PORT
   LAYER M4 ;
   RECT 302.208000 860.172000 302.400000 860.196000 ;
  END
 END pi2[241]
 PIN pi2[242]
  DIRECTION OUTPUT ;
  USE SIGNAL ;
  PORT
   LAYER M4 ;
   RECT 302.208000 860.364000 302.400000 860.388000 ;
  END
 END pi2[242]
 PIN pi2[243]
  DIRECTION OUTPUT ;
  USE SIGNAL ;
  PORT
   LAYER M4 ;
   RECT 302.208000 860.556000 302.400000 860.580000 ;
  END
 END pi2[243]
 PIN pi2[244]
  DIRECTION OUTPUT ;
  USE SIGNAL ;
  PORT
   LAYER M4 ;
   RECT 302.208000 860.748000 302.400000 860.772000 ;
  END
 END pi2[244]
 PIN pi2[245]
  DIRECTION OUTPUT ;
  USE SIGNAL ;
  PORT
   LAYER M4 ;
   RECT 302.208000 860.940000 302.400000 860.964000 ;
  END
 END pi2[245]
 PIN pi2[246]
  DIRECTION OUTPUT ;
  USE SIGNAL ;
  PORT
   LAYER M4 ;
   RECT 302.208000 861.132000 302.400000 861.156000 ;
  END
 END pi2[246]
 PIN pi2[247]
  DIRECTION OUTPUT ;
  USE SIGNAL ;
  PORT
   LAYER M4 ;
   RECT 302.208000 861.324000 302.400000 861.348000 ;
  END
 END pi2[247]
 PIN pi2[248]
  DIRECTION OUTPUT ;
  USE SIGNAL ;
  PORT
   LAYER M4 ;
   RECT 302.208000 861.516000 302.400000 861.540000 ;
  END
 END pi2[248]
 PIN pi2[249]
  DIRECTION OUTPUT ;
  USE SIGNAL ;
  PORT
   LAYER M4 ;
   RECT 302.208000 861.708000 302.400000 861.732000 ;
  END
 END pi2[249]
 PIN pi2[250]
  DIRECTION OUTPUT ;
  USE SIGNAL ;
  PORT
   LAYER M4 ;
   RECT 302.208000 861.900000 302.400000 861.924000 ;
  END
 END pi2[250]
 PIN pi2[251]
  DIRECTION OUTPUT ;
  USE SIGNAL ;
  PORT
   LAYER M4 ;
   RECT 302.208000 862.092000 302.400000 862.116000 ;
  END
 END pi2[251]
 PIN pi2[252]
  DIRECTION OUTPUT ;
  USE SIGNAL ;
  PORT
   LAYER M4 ;
   RECT 302.208000 862.284000 302.400000 862.308000 ;
  END
 END pi2[252]
 PIN pi2[253]
  DIRECTION OUTPUT ;
  USE SIGNAL ;
  PORT
   LAYER M4 ;
   RECT 302.208000 862.476000 302.400000 862.500000 ;
  END
 END pi2[253]
 PIN pi2[254]
  DIRECTION OUTPUT ;
  USE SIGNAL ;
  PORT
   LAYER M4 ;
   RECT 302.208000 862.668000 302.400000 862.692000 ;
  END
 END pi2[254]
 PIN pi2[255]
  DIRECTION OUTPUT ;
  USE SIGNAL ;
  PORT
   LAYER M4 ;
   RECT 302.208000 862.860000 302.400000 862.884000 ;
  END
 END pi2[255]
 PIN pi2[256]
  DIRECTION OUTPUT ;
  USE SIGNAL ;
  PORT
   LAYER M4 ;
   RECT 302.208000 863.052000 302.400000 863.076000 ;
  END
 END pi2[256]
 PIN pi2[257]
  DIRECTION OUTPUT ;
  USE SIGNAL ;
  PORT
   LAYER M4 ;
   RECT 302.208000 863.244000 302.400000 863.268000 ;
  END
 END pi2[257]
 PIN pi2[258]
  DIRECTION OUTPUT ;
  USE SIGNAL ;
  PORT
   LAYER M4 ;
   RECT 302.208000 863.436000 302.400000 863.460000 ;
  END
 END pi2[258]
 PIN pi2[259]
  DIRECTION OUTPUT ;
  USE SIGNAL ;
  PORT
   LAYER M4 ;
   RECT 302.208000 863.628000 302.400000 863.652000 ;
  END
 END pi2[259]
 PIN pi2[260]
  DIRECTION OUTPUT ;
  USE SIGNAL ;
  PORT
   LAYER M4 ;
   RECT 302.208000 863.820000 302.400000 863.844000 ;
  END
 END pi2[260]
 PIN pi2[261]
  DIRECTION OUTPUT ;
  USE SIGNAL ;
  PORT
   LAYER M4 ;
   RECT 302.208000 864.012000 302.400000 864.036000 ;
  END
 END pi2[261]
 PIN pi2[262]
  DIRECTION OUTPUT ;
  USE SIGNAL ;
  PORT
   LAYER M4 ;
   RECT 302.208000 864.204000 302.400000 864.228000 ;
  END
 END pi2[262]
 PIN pi2[263]
  DIRECTION OUTPUT ;
  USE SIGNAL ;
  PORT
   LAYER M4 ;
   RECT 302.208000 864.396000 302.400000 864.420000 ;
  END
 END pi2[263]
 PIN pi2[264]
  DIRECTION OUTPUT ;
  USE SIGNAL ;
  PORT
   LAYER M4 ;
   RECT 302.208000 864.588000 302.400000 864.612000 ;
  END
 END pi2[264]
 PIN pi2[265]
  DIRECTION OUTPUT ;
  USE SIGNAL ;
  PORT
   LAYER M4 ;
   RECT 302.208000 864.780000 302.400000 864.804000 ;
  END
 END pi2[265]
 PIN pi2[266]
  DIRECTION OUTPUT ;
  USE SIGNAL ;
  PORT
   LAYER M4 ;
   RECT 302.208000 864.972000 302.400000 864.996000 ;
  END
 END pi2[266]
 PIN pi2[267]
  DIRECTION OUTPUT ;
  USE SIGNAL ;
  PORT
   LAYER M4 ;
   RECT 302.208000 865.164000 302.400000 865.188000 ;
  END
 END pi2[267]
 PIN pi2[268]
  DIRECTION OUTPUT ;
  USE SIGNAL ;
  PORT
   LAYER M4 ;
   RECT 302.208000 865.356000 302.400000 865.380000 ;
  END
 END pi2[268]
 PIN pi2[269]
  DIRECTION OUTPUT ;
  USE SIGNAL ;
  PORT
   LAYER M4 ;
   RECT 302.208000 865.548000 302.400000 865.572000 ;
  END
 END pi2[269]
 PIN pi2[270]
  DIRECTION OUTPUT ;
  USE SIGNAL ;
  PORT
   LAYER M4 ;
   RECT 302.208000 865.740000 302.400000 865.764000 ;
  END
 END pi2[270]
 PIN pi2[271]
  DIRECTION OUTPUT ;
  USE SIGNAL ;
  PORT
   LAYER M4 ;
   RECT 302.208000 865.932000 302.400000 865.956000 ;
  END
 END pi2[271]
 PIN pi2[272]
  DIRECTION OUTPUT ;
  USE SIGNAL ;
  PORT
   LAYER M4 ;
   RECT 302.208000 866.124000 302.400000 866.148000 ;
  END
 END pi2[272]
 PIN pi2[273]
  DIRECTION OUTPUT ;
  USE SIGNAL ;
  PORT
   LAYER M4 ;
   RECT 302.208000 866.316000 302.400000 866.340000 ;
  END
 END pi2[273]
 PIN pi2[274]
  DIRECTION OUTPUT ;
  USE SIGNAL ;
  PORT
   LAYER M4 ;
   RECT 302.208000 866.508000 302.400000 866.532000 ;
  END
 END pi2[274]
 PIN pi2[275]
  DIRECTION OUTPUT ;
  USE SIGNAL ;
  PORT
   LAYER M4 ;
   RECT 302.208000 866.700000 302.400000 866.724000 ;
  END
 END pi2[275]
 PIN pi2[276]
  DIRECTION OUTPUT ;
  USE SIGNAL ;
  PORT
   LAYER M4 ;
   RECT 302.208000 866.892000 302.400000 866.916000 ;
  END
 END pi2[276]
 PIN pi2[277]
  DIRECTION OUTPUT ;
  USE SIGNAL ;
  PORT
   LAYER M4 ;
   RECT 302.208000 867.084000 302.400000 867.108000 ;
  END
 END pi2[277]
 PIN pi2[278]
  DIRECTION OUTPUT ;
  USE SIGNAL ;
  PORT
   LAYER M4 ;
   RECT 302.208000 867.276000 302.400000 867.300000 ;
  END
 END pi2[278]
 PIN pi2[279]
  DIRECTION OUTPUT ;
  USE SIGNAL ;
  PORT
   LAYER M4 ;
   RECT 302.208000 867.468000 302.400000 867.492000 ;
  END
 END pi2[279]
 PIN pi2[280]
  DIRECTION OUTPUT ;
  USE SIGNAL ;
  PORT
   LAYER M4 ;
   RECT 302.208000 867.660000 302.400000 867.684000 ;
  END
 END pi2[280]
 PIN pi2[281]
  DIRECTION OUTPUT ;
  USE SIGNAL ;
  PORT
   LAYER M4 ;
   RECT 302.208000 867.852000 302.400000 867.876000 ;
  END
 END pi2[281]
 PIN pi2[282]
  DIRECTION OUTPUT ;
  USE SIGNAL ;
  PORT
   LAYER M4 ;
   RECT 302.208000 868.044000 302.400000 868.068000 ;
  END
 END pi2[282]
 PIN pi2[283]
  DIRECTION OUTPUT ;
  USE SIGNAL ;
  PORT
   LAYER M4 ;
   RECT 302.208000 868.236000 302.400000 868.260000 ;
  END
 END pi2[283]
 PIN pi2[284]
  DIRECTION OUTPUT ;
  USE SIGNAL ;
  PORT
   LAYER M4 ;
   RECT 302.208000 868.428000 302.400000 868.452000 ;
  END
 END pi2[284]
 PIN pi2[285]
  DIRECTION OUTPUT ;
  USE SIGNAL ;
  PORT
   LAYER M4 ;
   RECT 302.208000 868.620000 302.400000 868.644000 ;
  END
 END pi2[285]
 PIN pi2[286]
  DIRECTION OUTPUT ;
  USE SIGNAL ;
  PORT
   LAYER M4 ;
   RECT 302.208000 868.812000 302.400000 868.836000 ;
  END
 END pi2[286]
 PIN pi2[287]
  DIRECTION OUTPUT ;
  USE SIGNAL ;
  PORT
   LAYER M4 ;
   RECT 302.208000 869.004000 302.400000 869.028000 ;
  END
 END pi2[287]
 PIN pi2[288]
  DIRECTION OUTPUT ;
  USE SIGNAL ;
  PORT
   LAYER M4 ;
   RECT 302.208000 869.196000 302.400000 869.220000 ;
  END
 END pi2[288]
 PIN fh2[0]
  DIRECTION OUTPUT ;
  USE SIGNAL ;
  PORT
   LAYER M4 ;
   RECT 302.208000 869.388000 302.400000 869.412000 ;
  END
 END fh2[0]
 PIN fh2[1]
  DIRECTION OUTPUT ;
  USE SIGNAL ;
  PORT
   LAYER M4 ;
   RECT 302.208000 869.580000 302.400000 869.604000 ;
  END
 END fh2[1]
 PIN fh2[2]
  DIRECTION OUTPUT ;
  USE SIGNAL ;
  PORT
   LAYER M4 ;
   RECT 302.208000 869.772000 302.400000 869.796000 ;
  END
 END fh2[2]
 PIN fh2[3]
  DIRECTION OUTPUT ;
  USE SIGNAL ;
  PORT
   LAYER M4 ;
   RECT 302.208000 869.964000 302.400000 869.988000 ;
  END
 END fh2[3]
 PIN rh2[0]
  DIRECTION OUTPUT ;
  USE SIGNAL ;
  PORT
   LAYER M4 ;
   RECT 302.208000 870.156000 302.400000 870.180000 ;
  END
 END rh2[0]
 PIN rh2[1]
  DIRECTION OUTPUT ;
  USE SIGNAL ;
  PORT
   LAYER M4 ;
   RECT 302.208000 870.348000 302.400000 870.372000 ;
  END
 END rh2[1]
 PIN rh2[2]
  DIRECTION OUTPUT ;
  USE SIGNAL ;
  PORT
   LAYER M4 ;
   RECT 302.208000 870.540000 302.400000 870.564000 ;
  END
 END rh2[2]
 PIN rh2[3]
  DIRECTION OUTPUT ;
  USE SIGNAL ;
  PORT
   LAYER M4 ;
   RECT 302.208000 870.732000 302.400000 870.756000 ;
  END
 END rh2[3]
 PIN po3[0]
  DIRECTION INPUT ;
  USE SIGNAL ;
  PORT
   LAYER M4 ;
   RECT 302.208000 870.924000 302.400000 870.948000 ;
  END
 END po3[0]
 PIN po3[1]
  DIRECTION INPUT ;
  USE SIGNAL ;
  PORT
   LAYER M4 ;
   RECT 302.208000 871.116000 302.400000 871.140000 ;
  END
 END po3[1]
 PIN po3[2]
  DIRECTION INPUT ;
  USE SIGNAL ;
  PORT
   LAYER M4 ;
   RECT 302.208000 871.308000 302.400000 871.332000 ;
  END
 END po3[2]
 PIN po3[3]
  DIRECTION INPUT ;
  USE SIGNAL ;
  PORT
   LAYER M4 ;
   RECT 302.208000 871.500000 302.400000 871.524000 ;
  END
 END po3[3]
 PIN po3[4]
  DIRECTION INPUT ;
  USE SIGNAL ;
  PORT
   LAYER M4 ;
   RECT 302.208000 871.692000 302.400000 871.716000 ;
  END
 END po3[4]
 PIN po3[5]
  DIRECTION INPUT ;
  USE SIGNAL ;
  PORT
   LAYER M4 ;
   RECT 302.208000 871.884000 302.400000 871.908000 ;
  END
 END po3[5]
 PIN po3[6]
  DIRECTION INPUT ;
  USE SIGNAL ;
  PORT
   LAYER M4 ;
   RECT 302.208000 872.076000 302.400000 872.100000 ;
  END
 END po3[6]
 PIN po3[7]
  DIRECTION INPUT ;
  USE SIGNAL ;
  PORT
   LAYER M4 ;
   RECT 302.208000 872.268000 302.400000 872.292000 ;
  END
 END po3[7]
 PIN po3[8]
  DIRECTION INPUT ;
  USE SIGNAL ;
  PORT
   LAYER M4 ;
   RECT 302.208000 872.460000 302.400000 872.484000 ;
  END
 END po3[8]
 PIN po3[9]
  DIRECTION INPUT ;
  USE SIGNAL ;
  PORT
   LAYER M4 ;
   RECT 302.208000 872.652000 302.400000 872.676000 ;
  END
 END po3[9]
 PIN po3[10]
  DIRECTION INPUT ;
  USE SIGNAL ;
  PORT
   LAYER M4 ;
   RECT 302.208000 872.844000 302.400000 872.868000 ;
  END
 END po3[10]
 PIN po3[11]
  DIRECTION INPUT ;
  USE SIGNAL ;
  PORT
   LAYER M4 ;
   RECT 302.208000 873.036000 302.400000 873.060000 ;
  END
 END po3[11]
 PIN po3[12]
  DIRECTION INPUT ;
  USE SIGNAL ;
  PORT
   LAYER M4 ;
   RECT 302.208000 873.228000 302.400000 873.252000 ;
  END
 END po3[12]
 PIN po3[13]
  DIRECTION INPUT ;
  USE SIGNAL ;
  PORT
   LAYER M4 ;
   RECT 302.208000 873.420000 302.400000 873.444000 ;
  END
 END po3[13]
 PIN po3[14]
  DIRECTION INPUT ;
  USE SIGNAL ;
  PORT
   LAYER M4 ;
   RECT 302.208000 873.612000 302.400000 873.636000 ;
  END
 END po3[14]
 PIN po3[15]
  DIRECTION INPUT ;
  USE SIGNAL ;
  PORT
   LAYER M4 ;
   RECT 302.208000 873.804000 302.400000 873.828000 ;
  END
 END po3[15]
 PIN po3[16]
  DIRECTION INPUT ;
  USE SIGNAL ;
  PORT
   LAYER M4 ;
   RECT 302.208000 873.996000 302.400000 874.020000 ;
  END
 END po3[16]
 PIN po3[17]
  DIRECTION INPUT ;
  USE SIGNAL ;
  PORT
   LAYER M4 ;
   RECT 302.208000 874.188000 302.400000 874.212000 ;
  END
 END po3[17]
 PIN po3[18]
  DIRECTION INPUT ;
  USE SIGNAL ;
  PORT
   LAYER M4 ;
   RECT 302.208000 874.380000 302.400000 874.404000 ;
  END
 END po3[18]
 PIN po3[19]
  DIRECTION INPUT ;
  USE SIGNAL ;
  PORT
   LAYER M4 ;
   RECT 302.208000 874.572000 302.400000 874.596000 ;
  END
 END po3[19]
 PIN po3[20]
  DIRECTION INPUT ;
  USE SIGNAL ;
  PORT
   LAYER M4 ;
   RECT 302.208000 874.764000 302.400000 874.788000 ;
  END
 END po3[20]
 PIN po3[21]
  DIRECTION INPUT ;
  USE SIGNAL ;
  PORT
   LAYER M4 ;
   RECT 302.208000 874.956000 302.400000 874.980000 ;
  END
 END po3[21]
 PIN po3[22]
  DIRECTION INPUT ;
  USE SIGNAL ;
  PORT
   LAYER M4 ;
   RECT 302.208000 875.148000 302.400000 875.172000 ;
  END
 END po3[22]
 PIN po3[23]
  DIRECTION INPUT ;
  USE SIGNAL ;
  PORT
   LAYER M4 ;
   RECT 302.208000 875.340000 302.400000 875.364000 ;
  END
 END po3[23]
 PIN po3[24]
  DIRECTION INPUT ;
  USE SIGNAL ;
  PORT
   LAYER M4 ;
   RECT 302.208000 875.532000 302.400000 875.556000 ;
  END
 END po3[24]
 PIN po3[25]
  DIRECTION INPUT ;
  USE SIGNAL ;
  PORT
   LAYER M4 ;
   RECT 302.208000 875.724000 302.400000 875.748000 ;
  END
 END po3[25]
 PIN po3[26]
  DIRECTION INPUT ;
  USE SIGNAL ;
  PORT
   LAYER M4 ;
   RECT 302.208000 875.916000 302.400000 875.940000 ;
  END
 END po3[26]
 PIN po3[27]
  DIRECTION INPUT ;
  USE SIGNAL ;
  PORT
   LAYER M4 ;
   RECT 302.208000 876.108000 302.400000 876.132000 ;
  END
 END po3[27]
 PIN po3[28]
  DIRECTION INPUT ;
  USE SIGNAL ;
  PORT
   LAYER M4 ;
   RECT 302.208000 876.300000 302.400000 876.324000 ;
  END
 END po3[28]
 PIN po3[29]
  DIRECTION INPUT ;
  USE SIGNAL ;
  PORT
   LAYER M4 ;
   RECT 302.208000 876.492000 302.400000 876.516000 ;
  END
 END po3[29]
 PIN po3[30]
  DIRECTION INPUT ;
  USE SIGNAL ;
  PORT
   LAYER M4 ;
   RECT 302.208000 876.684000 302.400000 876.708000 ;
  END
 END po3[30]
 PIN po3[31]
  DIRECTION INPUT ;
  USE SIGNAL ;
  PORT
   LAYER M4 ;
   RECT 302.208000 876.876000 302.400000 876.900000 ;
  END
 END po3[31]
 PIN po3[32]
  DIRECTION INPUT ;
  USE SIGNAL ;
  PORT
   LAYER M4 ;
   RECT 302.208000 877.068000 302.400000 877.092000 ;
  END
 END po3[32]
 PIN po3[33]
  DIRECTION INPUT ;
  USE SIGNAL ;
  PORT
   LAYER M4 ;
   RECT 302.208000 877.260000 302.400000 877.284000 ;
  END
 END po3[33]
 PIN po3[34]
  DIRECTION INPUT ;
  USE SIGNAL ;
  PORT
   LAYER M4 ;
   RECT 302.208000 877.452000 302.400000 877.476000 ;
  END
 END po3[34]
 PIN po3[35]
  DIRECTION INPUT ;
  USE SIGNAL ;
  PORT
   LAYER M4 ;
   RECT 302.208000 877.644000 302.400000 877.668000 ;
  END
 END po3[35]
 PIN po3[36]
  DIRECTION INPUT ;
  USE SIGNAL ;
  PORT
   LAYER M4 ;
   RECT 302.208000 877.836000 302.400000 877.860000 ;
  END
 END po3[36]
 PIN po3[37]
  DIRECTION INPUT ;
  USE SIGNAL ;
  PORT
   LAYER M4 ;
   RECT 302.208000 878.028000 302.400000 878.052000 ;
  END
 END po3[37]
 PIN po3[38]
  DIRECTION INPUT ;
  USE SIGNAL ;
  PORT
   LAYER M4 ;
   RECT 302.208000 878.220000 302.400000 878.244000 ;
  END
 END po3[38]
 PIN po3[39]
  DIRECTION INPUT ;
  USE SIGNAL ;
  PORT
   LAYER M4 ;
   RECT 302.208000 878.412000 302.400000 878.436000 ;
  END
 END po3[39]
 PIN po3[40]
  DIRECTION INPUT ;
  USE SIGNAL ;
  PORT
   LAYER M4 ;
   RECT 302.208000 878.604000 302.400000 878.628000 ;
  END
 END po3[40]
 PIN po3[41]
  DIRECTION INPUT ;
  USE SIGNAL ;
  PORT
   LAYER M4 ;
   RECT 302.208000 878.796000 302.400000 878.820000 ;
  END
 END po3[41]
 PIN po3[42]
  DIRECTION INPUT ;
  USE SIGNAL ;
  PORT
   LAYER M4 ;
   RECT 302.208000 878.988000 302.400000 879.012000 ;
  END
 END po3[42]
 PIN po3[43]
  DIRECTION INPUT ;
  USE SIGNAL ;
  PORT
   LAYER M4 ;
   RECT 302.208000 879.180000 302.400000 879.204000 ;
  END
 END po3[43]
 PIN po3[44]
  DIRECTION INPUT ;
  USE SIGNAL ;
  PORT
   LAYER M4 ;
   RECT 302.208000 879.372000 302.400000 879.396000 ;
  END
 END po3[44]
 PIN po3[45]
  DIRECTION INPUT ;
  USE SIGNAL ;
  PORT
   LAYER M4 ;
   RECT 302.208000 879.564000 302.400000 879.588000 ;
  END
 END po3[45]
 PIN po3[46]
  DIRECTION INPUT ;
  USE SIGNAL ;
  PORT
   LAYER M4 ;
   RECT 302.208000 879.756000 302.400000 879.780000 ;
  END
 END po3[46]
 PIN po3[47]
  DIRECTION INPUT ;
  USE SIGNAL ;
  PORT
   LAYER M4 ;
   RECT 302.208000 879.948000 302.400000 879.972000 ;
  END
 END po3[47]
 PIN po3[48]
  DIRECTION INPUT ;
  USE SIGNAL ;
  PORT
   LAYER M4 ;
   RECT 302.208000 880.140000 302.400000 880.164000 ;
  END
 END po3[48]
 PIN po3[49]
  DIRECTION INPUT ;
  USE SIGNAL ;
  PORT
   LAYER M4 ;
   RECT 302.208000 880.332000 302.400000 880.356000 ;
  END
 END po3[49]
 PIN po3[50]
  DIRECTION INPUT ;
  USE SIGNAL ;
  PORT
   LAYER M4 ;
   RECT 302.208000 880.524000 302.400000 880.548000 ;
  END
 END po3[50]
 PIN po3[51]
  DIRECTION INPUT ;
  USE SIGNAL ;
  PORT
   LAYER M4 ;
   RECT 302.208000 880.716000 302.400000 880.740000 ;
  END
 END po3[51]
 PIN po3[52]
  DIRECTION INPUT ;
  USE SIGNAL ;
  PORT
   LAYER M4 ;
   RECT 302.208000 880.908000 302.400000 880.932000 ;
  END
 END po3[52]
 PIN po3[53]
  DIRECTION INPUT ;
  USE SIGNAL ;
  PORT
   LAYER M4 ;
   RECT 302.208000 881.100000 302.400000 881.124000 ;
  END
 END po3[53]
 PIN po3[54]
  DIRECTION INPUT ;
  USE SIGNAL ;
  PORT
   LAYER M4 ;
   RECT 302.208000 881.292000 302.400000 881.316000 ;
  END
 END po3[54]
 PIN po3[55]
  DIRECTION INPUT ;
  USE SIGNAL ;
  PORT
   LAYER M4 ;
   RECT 302.208000 881.484000 302.400000 881.508000 ;
  END
 END po3[55]
 PIN po3[56]
  DIRECTION INPUT ;
  USE SIGNAL ;
  PORT
   LAYER M4 ;
   RECT 302.208000 881.676000 302.400000 881.700000 ;
  END
 END po3[56]
 PIN po3[57]
  DIRECTION INPUT ;
  USE SIGNAL ;
  PORT
   LAYER M4 ;
   RECT 302.208000 881.868000 302.400000 881.892000 ;
  END
 END po3[57]
 PIN po3[58]
  DIRECTION INPUT ;
  USE SIGNAL ;
  PORT
   LAYER M4 ;
   RECT 302.208000 882.060000 302.400000 882.084000 ;
  END
 END po3[58]
 PIN po3[59]
  DIRECTION INPUT ;
  USE SIGNAL ;
  PORT
   LAYER M4 ;
   RECT 302.208000 882.252000 302.400000 882.276000 ;
  END
 END po3[59]
 PIN po3[60]
  DIRECTION INPUT ;
  USE SIGNAL ;
  PORT
   LAYER M4 ;
   RECT 302.208000 882.444000 302.400000 882.468000 ;
  END
 END po3[60]
 PIN po3[61]
  DIRECTION INPUT ;
  USE SIGNAL ;
  PORT
   LAYER M4 ;
   RECT 302.208000 882.636000 302.400000 882.660000 ;
  END
 END po3[61]
 PIN po3[62]
  DIRECTION INPUT ;
  USE SIGNAL ;
  PORT
   LAYER M4 ;
   RECT 302.208000 882.828000 302.400000 882.852000 ;
  END
 END po3[62]
 PIN po3[63]
  DIRECTION INPUT ;
  USE SIGNAL ;
  PORT
   LAYER M4 ;
   RECT 302.208000 883.020000 302.400000 883.044000 ;
  END
 END po3[63]
 PIN po3[64]
  DIRECTION INPUT ;
  USE SIGNAL ;
  PORT
   LAYER M4 ;
   RECT 302.208000 883.212000 302.400000 883.236000 ;
  END
 END po3[64]
 PIN po3[65]
  DIRECTION INPUT ;
  USE SIGNAL ;
  PORT
   LAYER M4 ;
   RECT 302.208000 883.404000 302.400000 883.428000 ;
  END
 END po3[65]
 PIN po3[66]
  DIRECTION INPUT ;
  USE SIGNAL ;
  PORT
   LAYER M4 ;
   RECT 302.208000 883.596000 302.400000 883.620000 ;
  END
 END po3[66]
 PIN po3[67]
  DIRECTION INPUT ;
  USE SIGNAL ;
  PORT
   LAYER M4 ;
   RECT 302.208000 883.788000 302.400000 883.812000 ;
  END
 END po3[67]
 PIN po3[68]
  DIRECTION INPUT ;
  USE SIGNAL ;
  PORT
   LAYER M4 ;
   RECT 302.208000 883.980000 302.400000 884.004000 ;
  END
 END po3[68]
 PIN po3[69]
  DIRECTION INPUT ;
  USE SIGNAL ;
  PORT
   LAYER M4 ;
   RECT 302.208000 884.172000 302.400000 884.196000 ;
  END
 END po3[69]
 PIN po3[70]
  DIRECTION INPUT ;
  USE SIGNAL ;
  PORT
   LAYER M4 ;
   RECT 302.208000 884.364000 302.400000 884.388000 ;
  END
 END po3[70]
 PIN po3[71]
  DIRECTION INPUT ;
  USE SIGNAL ;
  PORT
   LAYER M4 ;
   RECT 302.208000 884.556000 302.400000 884.580000 ;
  END
 END po3[71]
 PIN po3[72]
  DIRECTION INPUT ;
  USE SIGNAL ;
  PORT
   LAYER M4 ;
   RECT 302.208000 884.748000 302.400000 884.772000 ;
  END
 END po3[72]
 PIN po3[73]
  DIRECTION INPUT ;
  USE SIGNAL ;
  PORT
   LAYER M4 ;
   RECT 302.208000 884.940000 302.400000 884.964000 ;
  END
 END po3[73]
 PIN po3[74]
  DIRECTION INPUT ;
  USE SIGNAL ;
  PORT
   LAYER M4 ;
   RECT 302.208000 885.132000 302.400000 885.156000 ;
  END
 END po3[74]
 PIN po3[75]
  DIRECTION INPUT ;
  USE SIGNAL ;
  PORT
   LAYER M4 ;
   RECT 302.208000 885.324000 302.400000 885.348000 ;
  END
 END po3[75]
 PIN po3[76]
  DIRECTION INPUT ;
  USE SIGNAL ;
  PORT
   LAYER M4 ;
   RECT 302.208000 885.516000 302.400000 885.540000 ;
  END
 END po3[76]
 PIN po3[77]
  DIRECTION INPUT ;
  USE SIGNAL ;
  PORT
   LAYER M4 ;
   RECT 302.208000 885.708000 302.400000 885.732000 ;
  END
 END po3[77]
 PIN po3[78]
  DIRECTION INPUT ;
  USE SIGNAL ;
  PORT
   LAYER M4 ;
   RECT 302.208000 885.900000 302.400000 885.924000 ;
  END
 END po3[78]
 PIN po3[79]
  DIRECTION INPUT ;
  USE SIGNAL ;
  PORT
   LAYER M4 ;
   RECT 302.208000 886.092000 302.400000 886.116000 ;
  END
 END po3[79]
 PIN po3[80]
  DIRECTION INPUT ;
  USE SIGNAL ;
  PORT
   LAYER M4 ;
   RECT 302.208000 886.284000 302.400000 886.308000 ;
  END
 END po3[80]
 PIN po3[81]
  DIRECTION INPUT ;
  USE SIGNAL ;
  PORT
   LAYER M4 ;
   RECT 302.208000 886.476000 302.400000 886.500000 ;
  END
 END po3[81]
 PIN po3[82]
  DIRECTION INPUT ;
  USE SIGNAL ;
  PORT
   LAYER M4 ;
   RECT 302.208000 886.668000 302.400000 886.692000 ;
  END
 END po3[82]
 PIN po3[83]
  DIRECTION INPUT ;
  USE SIGNAL ;
  PORT
   LAYER M4 ;
   RECT 302.208000 886.860000 302.400000 886.884000 ;
  END
 END po3[83]
 PIN po3[84]
  DIRECTION INPUT ;
  USE SIGNAL ;
  PORT
   LAYER M4 ;
   RECT 302.208000 887.052000 302.400000 887.076000 ;
  END
 END po3[84]
 PIN po3[85]
  DIRECTION INPUT ;
  USE SIGNAL ;
  PORT
   LAYER M4 ;
   RECT 302.208000 887.244000 302.400000 887.268000 ;
  END
 END po3[85]
 PIN po3[86]
  DIRECTION INPUT ;
  USE SIGNAL ;
  PORT
   LAYER M4 ;
   RECT 302.208000 887.436000 302.400000 887.460000 ;
  END
 END po3[86]
 PIN po3[87]
  DIRECTION INPUT ;
  USE SIGNAL ;
  PORT
   LAYER M4 ;
   RECT 302.208000 887.628000 302.400000 887.652000 ;
  END
 END po3[87]
 PIN po3[88]
  DIRECTION INPUT ;
  USE SIGNAL ;
  PORT
   LAYER M4 ;
   RECT 302.208000 887.820000 302.400000 887.844000 ;
  END
 END po3[88]
 PIN po3[89]
  DIRECTION INPUT ;
  USE SIGNAL ;
  PORT
   LAYER M4 ;
   RECT 302.208000 888.012000 302.400000 888.036000 ;
  END
 END po3[89]
 PIN po3[90]
  DIRECTION INPUT ;
  USE SIGNAL ;
  PORT
   LAYER M4 ;
   RECT 302.208000 888.204000 302.400000 888.228000 ;
  END
 END po3[90]
 PIN po3[91]
  DIRECTION INPUT ;
  USE SIGNAL ;
  PORT
   LAYER M4 ;
   RECT 302.208000 888.396000 302.400000 888.420000 ;
  END
 END po3[91]
 PIN po3[92]
  DIRECTION INPUT ;
  USE SIGNAL ;
  PORT
   LAYER M4 ;
   RECT 302.208000 888.588000 302.400000 888.612000 ;
  END
 END po3[92]
 PIN po3[93]
  DIRECTION INPUT ;
  USE SIGNAL ;
  PORT
   LAYER M4 ;
   RECT 302.208000 888.780000 302.400000 888.804000 ;
  END
 END po3[93]
 PIN po3[94]
  DIRECTION INPUT ;
  USE SIGNAL ;
  PORT
   LAYER M4 ;
   RECT 302.208000 888.972000 302.400000 888.996000 ;
  END
 END po3[94]
 PIN po3[95]
  DIRECTION INPUT ;
  USE SIGNAL ;
  PORT
   LAYER M4 ;
   RECT 302.208000 889.164000 302.400000 889.188000 ;
  END
 END po3[95]
 PIN po3[96]
  DIRECTION INPUT ;
  USE SIGNAL ;
  PORT
   LAYER M4 ;
   RECT 302.208000 889.356000 302.400000 889.380000 ;
  END
 END po3[96]
 PIN po3[97]
  DIRECTION INPUT ;
  USE SIGNAL ;
  PORT
   LAYER M4 ;
   RECT 302.208000 889.548000 302.400000 889.572000 ;
  END
 END po3[97]
 PIN po3[98]
  DIRECTION INPUT ;
  USE SIGNAL ;
  PORT
   LAYER M4 ;
   RECT 302.208000 889.740000 302.400000 889.764000 ;
  END
 END po3[98]
 PIN po3[99]
  DIRECTION INPUT ;
  USE SIGNAL ;
  PORT
   LAYER M4 ;
   RECT 302.208000 889.932000 302.400000 889.956000 ;
  END
 END po3[99]
 PIN po3[100]
  DIRECTION INPUT ;
  USE SIGNAL ;
  PORT
   LAYER M4 ;
   RECT 302.208000 890.124000 302.400000 890.148000 ;
  END
 END po3[100]
 PIN po3[101]
  DIRECTION INPUT ;
  USE SIGNAL ;
  PORT
   LAYER M4 ;
   RECT 302.208000 890.316000 302.400000 890.340000 ;
  END
 END po3[101]
 PIN po3[102]
  DIRECTION INPUT ;
  USE SIGNAL ;
  PORT
   LAYER M4 ;
   RECT 302.208000 890.508000 302.400000 890.532000 ;
  END
 END po3[102]
 PIN po3[103]
  DIRECTION INPUT ;
  USE SIGNAL ;
  PORT
   LAYER M4 ;
   RECT 302.208000 890.700000 302.400000 890.724000 ;
  END
 END po3[103]
 PIN po3[104]
  DIRECTION INPUT ;
  USE SIGNAL ;
  PORT
   LAYER M4 ;
   RECT 302.208000 890.892000 302.400000 890.916000 ;
  END
 END po3[104]
 PIN po3[105]
  DIRECTION INPUT ;
  USE SIGNAL ;
  PORT
   LAYER M4 ;
   RECT 302.208000 891.084000 302.400000 891.108000 ;
  END
 END po3[105]
 PIN po3[106]
  DIRECTION INPUT ;
  USE SIGNAL ;
  PORT
   LAYER M4 ;
   RECT 302.208000 891.276000 302.400000 891.300000 ;
  END
 END po3[106]
 PIN po3[107]
  DIRECTION INPUT ;
  USE SIGNAL ;
  PORT
   LAYER M4 ;
   RECT 302.208000 891.468000 302.400000 891.492000 ;
  END
 END po3[107]
 PIN po3[108]
  DIRECTION INPUT ;
  USE SIGNAL ;
  PORT
   LAYER M4 ;
   RECT 302.208000 891.660000 302.400000 891.684000 ;
  END
 END po3[108]
 PIN po3[109]
  DIRECTION INPUT ;
  USE SIGNAL ;
  PORT
   LAYER M4 ;
   RECT 302.208000 891.852000 302.400000 891.876000 ;
  END
 END po3[109]
 PIN po3[110]
  DIRECTION INPUT ;
  USE SIGNAL ;
  PORT
   LAYER M4 ;
   RECT 302.208000 892.044000 302.400000 892.068000 ;
  END
 END po3[110]
 PIN po3[111]
  DIRECTION INPUT ;
  USE SIGNAL ;
  PORT
   LAYER M4 ;
   RECT 302.208000 892.236000 302.400000 892.260000 ;
  END
 END po3[111]
 PIN po3[112]
  DIRECTION INPUT ;
  USE SIGNAL ;
  PORT
   LAYER M4 ;
   RECT 302.208000 892.428000 302.400000 892.452000 ;
  END
 END po3[112]
 PIN po3[113]
  DIRECTION INPUT ;
  USE SIGNAL ;
  PORT
   LAYER M4 ;
   RECT 302.208000 892.620000 302.400000 892.644000 ;
  END
 END po3[113]
 PIN po3[114]
  DIRECTION INPUT ;
  USE SIGNAL ;
  PORT
   LAYER M4 ;
   RECT 302.208000 892.812000 302.400000 892.836000 ;
  END
 END po3[114]
 PIN po3[115]
  DIRECTION INPUT ;
  USE SIGNAL ;
  PORT
   LAYER M4 ;
   RECT 302.208000 893.004000 302.400000 893.028000 ;
  END
 END po3[115]
 PIN po3[116]
  DIRECTION INPUT ;
  USE SIGNAL ;
  PORT
   LAYER M4 ;
   RECT 302.208000 893.196000 302.400000 893.220000 ;
  END
 END po3[116]
 PIN po3[117]
  DIRECTION INPUT ;
  USE SIGNAL ;
  PORT
   LAYER M4 ;
   RECT 302.208000 893.388000 302.400000 893.412000 ;
  END
 END po3[117]
 PIN po3[118]
  DIRECTION INPUT ;
  USE SIGNAL ;
  PORT
   LAYER M4 ;
   RECT 302.208000 893.580000 302.400000 893.604000 ;
  END
 END po3[118]
 PIN po3[119]
  DIRECTION INPUT ;
  USE SIGNAL ;
  PORT
   LAYER M4 ;
   RECT 302.208000 893.772000 302.400000 893.796000 ;
  END
 END po3[119]
 PIN po3[120]
  DIRECTION INPUT ;
  USE SIGNAL ;
  PORT
   LAYER M4 ;
   RECT 302.208000 893.964000 302.400000 893.988000 ;
  END
 END po3[120]
 PIN po3[121]
  DIRECTION INPUT ;
  USE SIGNAL ;
  PORT
   LAYER M4 ;
   RECT 302.208000 894.156000 302.400000 894.180000 ;
  END
 END po3[121]
 PIN po3[122]
  DIRECTION INPUT ;
  USE SIGNAL ;
  PORT
   LAYER M4 ;
   RECT 302.208000 894.348000 302.400000 894.372000 ;
  END
 END po3[122]
 PIN po3[123]
  DIRECTION INPUT ;
  USE SIGNAL ;
  PORT
   LAYER M4 ;
   RECT 302.208000 894.540000 302.400000 894.564000 ;
  END
 END po3[123]
 PIN po3[124]
  DIRECTION INPUT ;
  USE SIGNAL ;
  PORT
   LAYER M4 ;
   RECT 302.208000 894.732000 302.400000 894.756000 ;
  END
 END po3[124]
 PIN po3[125]
  DIRECTION INPUT ;
  USE SIGNAL ;
  PORT
   LAYER M4 ;
   RECT 302.208000 894.924000 302.400000 894.948000 ;
  END
 END po3[125]
 PIN po3[126]
  DIRECTION INPUT ;
  USE SIGNAL ;
  PORT
   LAYER M4 ;
   RECT 302.208000 895.116000 302.400000 895.140000 ;
  END
 END po3[126]
 PIN po3[127]
  DIRECTION INPUT ;
  USE SIGNAL ;
  PORT
   LAYER M4 ;
   RECT 302.208000 895.308000 302.400000 895.332000 ;
  END
 END po3[127]
 PIN po3[128]
  DIRECTION INPUT ;
  USE SIGNAL ;
  PORT
   LAYER M4 ;
   RECT 302.208000 895.500000 302.400000 895.524000 ;
  END
 END po3[128]
 PIN po3[129]
  DIRECTION INPUT ;
  USE SIGNAL ;
  PORT
   LAYER M4 ;
   RECT 302.208000 895.692000 302.400000 895.716000 ;
  END
 END po3[129]
 PIN po3[130]
  DIRECTION INPUT ;
  USE SIGNAL ;
  PORT
   LAYER M4 ;
   RECT 302.208000 895.884000 302.400000 895.908000 ;
  END
 END po3[130]
 PIN po3[131]
  DIRECTION INPUT ;
  USE SIGNAL ;
  PORT
   LAYER M4 ;
   RECT 302.208000 896.076000 302.400000 896.100000 ;
  END
 END po3[131]
 PIN po3[132]
  DIRECTION INPUT ;
  USE SIGNAL ;
  PORT
   LAYER M4 ;
   RECT 302.208000 896.268000 302.400000 896.292000 ;
  END
 END po3[132]
 PIN po3[133]
  DIRECTION INPUT ;
  USE SIGNAL ;
  PORT
   LAYER M4 ;
   RECT 302.208000 896.460000 302.400000 896.484000 ;
  END
 END po3[133]
 PIN po3[134]
  DIRECTION INPUT ;
  USE SIGNAL ;
  PORT
   LAYER M4 ;
   RECT 302.208000 896.652000 302.400000 896.676000 ;
  END
 END po3[134]
 PIN po3[135]
  DIRECTION INPUT ;
  USE SIGNAL ;
  PORT
   LAYER M4 ;
   RECT 302.208000 896.844000 302.400000 896.868000 ;
  END
 END po3[135]
 PIN po3[136]
  DIRECTION INPUT ;
  USE SIGNAL ;
  PORT
   LAYER M4 ;
   RECT 302.208000 897.036000 302.400000 897.060000 ;
  END
 END po3[136]
 PIN po3[137]
  DIRECTION INPUT ;
  USE SIGNAL ;
  PORT
   LAYER M4 ;
   RECT 302.208000 897.228000 302.400000 897.252000 ;
  END
 END po3[137]
 PIN po3[138]
  DIRECTION INPUT ;
  USE SIGNAL ;
  PORT
   LAYER M4 ;
   RECT 302.208000 897.420000 302.400000 897.444000 ;
  END
 END po3[138]
 PIN po3[139]
  DIRECTION INPUT ;
  USE SIGNAL ;
  PORT
   LAYER M4 ;
   RECT 302.208000 897.612000 302.400000 897.636000 ;
  END
 END po3[139]
 PIN po3[140]
  DIRECTION INPUT ;
  USE SIGNAL ;
  PORT
   LAYER M4 ;
   RECT 302.208000 897.804000 302.400000 897.828000 ;
  END
 END po3[140]
 PIN po3[141]
  DIRECTION INPUT ;
  USE SIGNAL ;
  PORT
   LAYER M4 ;
   RECT 302.208000 897.996000 302.400000 898.020000 ;
  END
 END po3[141]
 PIN po3[142]
  DIRECTION INPUT ;
  USE SIGNAL ;
  PORT
   LAYER M4 ;
   RECT 302.208000 898.188000 302.400000 898.212000 ;
  END
 END po3[142]
 PIN po3[143]
  DIRECTION INPUT ;
  USE SIGNAL ;
  PORT
   LAYER M4 ;
   RECT 302.208000 898.380000 302.400000 898.404000 ;
  END
 END po3[143]
 PIN po3[144]
  DIRECTION INPUT ;
  USE SIGNAL ;
  PORT
   LAYER M4 ;
   RECT 302.208000 898.572000 302.400000 898.596000 ;
  END
 END po3[144]
 PIN po3[145]
  DIRECTION INPUT ;
  USE SIGNAL ;
  PORT
   LAYER M4 ;
   RECT 302.208000 898.764000 302.400000 898.788000 ;
  END
 END po3[145]
 PIN po3[146]
  DIRECTION INPUT ;
  USE SIGNAL ;
  PORT
   LAYER M4 ;
   RECT 302.208000 898.956000 302.400000 898.980000 ;
  END
 END po3[146]
 PIN po3[147]
  DIRECTION INPUT ;
  USE SIGNAL ;
  PORT
   LAYER M4 ;
   RECT 302.208000 899.148000 302.400000 899.172000 ;
  END
 END po3[147]
 PIN po3[148]
  DIRECTION INPUT ;
  USE SIGNAL ;
  PORT
   LAYER M4 ;
   RECT 302.208000 899.340000 302.400000 899.364000 ;
  END
 END po3[148]
 PIN po3[149]
  DIRECTION INPUT ;
  USE SIGNAL ;
  PORT
   LAYER M4 ;
   RECT 302.208000 899.532000 302.400000 899.556000 ;
  END
 END po3[149]
 PIN po3[150]
  DIRECTION INPUT ;
  USE SIGNAL ;
  PORT
   LAYER M4 ;
   RECT 302.208000 899.724000 302.400000 899.748000 ;
  END
 END po3[150]
 PIN po3[151]
  DIRECTION INPUT ;
  USE SIGNAL ;
  PORT
   LAYER M4 ;
   RECT 302.208000 899.916000 302.400000 899.940000 ;
  END
 END po3[151]
 PIN po3[152]
  DIRECTION INPUT ;
  USE SIGNAL ;
  PORT
   LAYER M4 ;
   RECT 302.208000 900.108000 302.400000 900.132000 ;
  END
 END po3[152]
 PIN po3[153]
  DIRECTION INPUT ;
  USE SIGNAL ;
  PORT
   LAYER M4 ;
   RECT 302.208000 900.300000 302.400000 900.324000 ;
  END
 END po3[153]
 PIN po3[154]
  DIRECTION INPUT ;
  USE SIGNAL ;
  PORT
   LAYER M4 ;
   RECT 302.208000 900.492000 302.400000 900.516000 ;
  END
 END po3[154]
 PIN po3[155]
  DIRECTION INPUT ;
  USE SIGNAL ;
  PORT
   LAYER M4 ;
   RECT 302.208000 900.684000 302.400000 900.708000 ;
  END
 END po3[155]
 PIN po3[156]
  DIRECTION INPUT ;
  USE SIGNAL ;
  PORT
   LAYER M4 ;
   RECT 302.208000 900.876000 302.400000 900.900000 ;
  END
 END po3[156]
 PIN po3[157]
  DIRECTION INPUT ;
  USE SIGNAL ;
  PORT
   LAYER M4 ;
   RECT 302.208000 901.068000 302.400000 901.092000 ;
  END
 END po3[157]
 PIN po3[158]
  DIRECTION INPUT ;
  USE SIGNAL ;
  PORT
   LAYER M4 ;
   RECT 302.208000 901.260000 302.400000 901.284000 ;
  END
 END po3[158]
 PIN po3[159]
  DIRECTION INPUT ;
  USE SIGNAL ;
  PORT
   LAYER M4 ;
   RECT 302.208000 901.452000 302.400000 901.476000 ;
  END
 END po3[159]
 PIN po3[160]
  DIRECTION INPUT ;
  USE SIGNAL ;
  PORT
   LAYER M4 ;
   RECT 302.208000 901.644000 302.400000 901.668000 ;
  END
 END po3[160]
 PIN po3[161]
  DIRECTION INPUT ;
  USE SIGNAL ;
  PORT
   LAYER M4 ;
   RECT 302.208000 901.836000 302.400000 901.860000 ;
  END
 END po3[161]
 PIN po3[162]
  DIRECTION INPUT ;
  USE SIGNAL ;
  PORT
   LAYER M4 ;
   RECT 302.208000 902.028000 302.400000 902.052000 ;
  END
 END po3[162]
 PIN po3[163]
  DIRECTION INPUT ;
  USE SIGNAL ;
  PORT
   LAYER M4 ;
   RECT 302.208000 902.220000 302.400000 902.244000 ;
  END
 END po3[163]
 PIN po3[164]
  DIRECTION INPUT ;
  USE SIGNAL ;
  PORT
   LAYER M4 ;
   RECT 302.208000 902.412000 302.400000 902.436000 ;
  END
 END po3[164]
 PIN po3[165]
  DIRECTION INPUT ;
  USE SIGNAL ;
  PORT
   LAYER M4 ;
   RECT 302.208000 902.604000 302.400000 902.628000 ;
  END
 END po3[165]
 PIN po3[166]
  DIRECTION INPUT ;
  USE SIGNAL ;
  PORT
   LAYER M4 ;
   RECT 302.208000 902.796000 302.400000 902.820000 ;
  END
 END po3[166]
 PIN po3[167]
  DIRECTION INPUT ;
  USE SIGNAL ;
  PORT
   LAYER M4 ;
   RECT 302.208000 902.988000 302.400000 903.012000 ;
  END
 END po3[167]
 PIN po3[168]
  DIRECTION INPUT ;
  USE SIGNAL ;
  PORT
   LAYER M4 ;
   RECT 302.208000 903.180000 302.400000 903.204000 ;
  END
 END po3[168]
 PIN po3[169]
  DIRECTION INPUT ;
  USE SIGNAL ;
  PORT
   LAYER M4 ;
   RECT 302.208000 903.372000 302.400000 903.396000 ;
  END
 END po3[169]
 PIN po3[170]
  DIRECTION INPUT ;
  USE SIGNAL ;
  PORT
   LAYER M4 ;
   RECT 302.208000 903.564000 302.400000 903.588000 ;
  END
 END po3[170]
 PIN po3[171]
  DIRECTION INPUT ;
  USE SIGNAL ;
  PORT
   LAYER M4 ;
   RECT 302.208000 903.756000 302.400000 903.780000 ;
  END
 END po3[171]
 PIN po3[172]
  DIRECTION INPUT ;
  USE SIGNAL ;
  PORT
   LAYER M4 ;
   RECT 302.208000 903.948000 302.400000 903.972000 ;
  END
 END po3[172]
 PIN po3[173]
  DIRECTION INPUT ;
  USE SIGNAL ;
  PORT
   LAYER M4 ;
   RECT 302.208000 904.140000 302.400000 904.164000 ;
  END
 END po3[173]
 PIN po3[174]
  DIRECTION INPUT ;
  USE SIGNAL ;
  PORT
   LAYER M4 ;
   RECT 302.208000 904.332000 302.400000 904.356000 ;
  END
 END po3[174]
 PIN po3[175]
  DIRECTION INPUT ;
  USE SIGNAL ;
  PORT
   LAYER M4 ;
   RECT 302.208000 904.524000 302.400000 904.548000 ;
  END
 END po3[175]
 PIN po3[176]
  DIRECTION INPUT ;
  USE SIGNAL ;
  PORT
   LAYER M4 ;
   RECT 302.208000 904.716000 302.400000 904.740000 ;
  END
 END po3[176]
 PIN po3[177]
  DIRECTION INPUT ;
  USE SIGNAL ;
  PORT
   LAYER M4 ;
   RECT 302.208000 904.908000 302.400000 904.932000 ;
  END
 END po3[177]
 PIN po3[178]
  DIRECTION INPUT ;
  USE SIGNAL ;
  PORT
   LAYER M4 ;
   RECT 302.208000 905.100000 302.400000 905.124000 ;
  END
 END po3[178]
 PIN po3[179]
  DIRECTION INPUT ;
  USE SIGNAL ;
  PORT
   LAYER M4 ;
   RECT 302.208000 905.292000 302.400000 905.316000 ;
  END
 END po3[179]
 PIN po3[180]
  DIRECTION INPUT ;
  USE SIGNAL ;
  PORT
   LAYER M4 ;
   RECT 302.208000 905.484000 302.400000 905.508000 ;
  END
 END po3[180]
 PIN po3[181]
  DIRECTION INPUT ;
  USE SIGNAL ;
  PORT
   LAYER M4 ;
   RECT 302.208000 905.676000 302.400000 905.700000 ;
  END
 END po3[181]
 PIN po3[182]
  DIRECTION INPUT ;
  USE SIGNAL ;
  PORT
   LAYER M4 ;
   RECT 302.208000 905.868000 302.400000 905.892000 ;
  END
 END po3[182]
 PIN po3[183]
  DIRECTION INPUT ;
  USE SIGNAL ;
  PORT
   LAYER M4 ;
   RECT 302.208000 906.060000 302.400000 906.084000 ;
  END
 END po3[183]
 PIN po3[184]
  DIRECTION INPUT ;
  USE SIGNAL ;
  PORT
   LAYER M4 ;
   RECT 302.208000 906.252000 302.400000 906.276000 ;
  END
 END po3[184]
 PIN po3[185]
  DIRECTION INPUT ;
  USE SIGNAL ;
  PORT
   LAYER M4 ;
   RECT 302.208000 906.444000 302.400000 906.468000 ;
  END
 END po3[185]
 PIN po3[186]
  DIRECTION INPUT ;
  USE SIGNAL ;
  PORT
   LAYER M4 ;
   RECT 302.208000 906.636000 302.400000 906.660000 ;
  END
 END po3[186]
 PIN po3[187]
  DIRECTION INPUT ;
  USE SIGNAL ;
  PORT
   LAYER M4 ;
   RECT 302.208000 906.828000 302.400000 906.852000 ;
  END
 END po3[187]
 PIN po3[188]
  DIRECTION INPUT ;
  USE SIGNAL ;
  PORT
   LAYER M4 ;
   RECT 302.208000 907.020000 302.400000 907.044000 ;
  END
 END po3[188]
 PIN po3[189]
  DIRECTION INPUT ;
  USE SIGNAL ;
  PORT
   LAYER M4 ;
   RECT 302.208000 907.212000 302.400000 907.236000 ;
  END
 END po3[189]
 PIN po3[190]
  DIRECTION INPUT ;
  USE SIGNAL ;
  PORT
   LAYER M4 ;
   RECT 302.208000 907.404000 302.400000 907.428000 ;
  END
 END po3[190]
 PIN po3[191]
  DIRECTION INPUT ;
  USE SIGNAL ;
  PORT
   LAYER M4 ;
   RECT 302.208000 907.596000 302.400000 907.620000 ;
  END
 END po3[191]
 PIN po3[192]
  DIRECTION INPUT ;
  USE SIGNAL ;
  PORT
   LAYER M4 ;
   RECT 302.208000 907.788000 302.400000 907.812000 ;
  END
 END po3[192]
 PIN po3[193]
  DIRECTION INPUT ;
  USE SIGNAL ;
  PORT
   LAYER M4 ;
   RECT 302.208000 907.980000 302.400000 908.004000 ;
  END
 END po3[193]
 PIN po3[194]
  DIRECTION INPUT ;
  USE SIGNAL ;
  PORT
   LAYER M4 ;
   RECT 302.208000 908.172000 302.400000 908.196000 ;
  END
 END po3[194]
 PIN po3[195]
  DIRECTION INPUT ;
  USE SIGNAL ;
  PORT
   LAYER M4 ;
   RECT 302.208000 908.364000 302.400000 908.388000 ;
  END
 END po3[195]
 PIN po3[196]
  DIRECTION INPUT ;
  USE SIGNAL ;
  PORT
   LAYER M4 ;
   RECT 302.208000 908.556000 302.400000 908.580000 ;
  END
 END po3[196]
 PIN po3[197]
  DIRECTION INPUT ;
  USE SIGNAL ;
  PORT
   LAYER M4 ;
   RECT 302.208000 908.748000 302.400000 908.772000 ;
  END
 END po3[197]
 PIN po3[198]
  DIRECTION INPUT ;
  USE SIGNAL ;
  PORT
   LAYER M4 ;
   RECT 302.208000 908.940000 302.400000 908.964000 ;
  END
 END po3[198]
 PIN po3[199]
  DIRECTION INPUT ;
  USE SIGNAL ;
  PORT
   LAYER M4 ;
   RECT 302.208000 909.132000 302.400000 909.156000 ;
  END
 END po3[199]
 PIN po3[200]
  DIRECTION INPUT ;
  USE SIGNAL ;
  PORT
   LAYER M4 ;
   RECT 302.208000 909.324000 302.400000 909.348000 ;
  END
 END po3[200]
 PIN po3[201]
  DIRECTION INPUT ;
  USE SIGNAL ;
  PORT
   LAYER M4 ;
   RECT 302.208000 909.516000 302.400000 909.540000 ;
  END
 END po3[201]
 PIN po3[202]
  DIRECTION INPUT ;
  USE SIGNAL ;
  PORT
   LAYER M4 ;
   RECT 302.208000 909.708000 302.400000 909.732000 ;
  END
 END po3[202]
 PIN po3[203]
  DIRECTION INPUT ;
  USE SIGNAL ;
  PORT
   LAYER M4 ;
   RECT 302.208000 909.900000 302.400000 909.924000 ;
  END
 END po3[203]
 PIN po3[204]
  DIRECTION INPUT ;
  USE SIGNAL ;
  PORT
   LAYER M4 ;
   RECT 302.208000 910.092000 302.400000 910.116000 ;
  END
 END po3[204]
 PIN po3[205]
  DIRECTION INPUT ;
  USE SIGNAL ;
  PORT
   LAYER M4 ;
   RECT 302.208000 910.284000 302.400000 910.308000 ;
  END
 END po3[205]
 PIN po3[206]
  DIRECTION INPUT ;
  USE SIGNAL ;
  PORT
   LAYER M4 ;
   RECT 302.208000 910.476000 302.400000 910.500000 ;
  END
 END po3[206]
 PIN po3[207]
  DIRECTION INPUT ;
  USE SIGNAL ;
  PORT
   LAYER M4 ;
   RECT 302.208000 910.668000 302.400000 910.692000 ;
  END
 END po3[207]
 PIN po3[208]
  DIRECTION INPUT ;
  USE SIGNAL ;
  PORT
   LAYER M4 ;
   RECT 302.208000 910.860000 302.400000 910.884000 ;
  END
 END po3[208]
 PIN po3[209]
  DIRECTION INPUT ;
  USE SIGNAL ;
  PORT
   LAYER M4 ;
   RECT 302.208000 911.052000 302.400000 911.076000 ;
  END
 END po3[209]
 PIN po3[210]
  DIRECTION INPUT ;
  USE SIGNAL ;
  PORT
   LAYER M4 ;
   RECT 302.208000 911.244000 302.400000 911.268000 ;
  END
 END po3[210]
 PIN po3[211]
  DIRECTION INPUT ;
  USE SIGNAL ;
  PORT
   LAYER M4 ;
   RECT 302.208000 911.436000 302.400000 911.460000 ;
  END
 END po3[211]
 PIN po3[212]
  DIRECTION INPUT ;
  USE SIGNAL ;
  PORT
   LAYER M4 ;
   RECT 302.208000 911.628000 302.400000 911.652000 ;
  END
 END po3[212]
 PIN po3[213]
  DIRECTION INPUT ;
  USE SIGNAL ;
  PORT
   LAYER M4 ;
   RECT 302.208000 911.820000 302.400000 911.844000 ;
  END
 END po3[213]
 PIN po3[214]
  DIRECTION INPUT ;
  USE SIGNAL ;
  PORT
   LAYER M4 ;
   RECT 302.208000 912.012000 302.400000 912.036000 ;
  END
 END po3[214]
 PIN po3[215]
  DIRECTION INPUT ;
  USE SIGNAL ;
  PORT
   LAYER M4 ;
   RECT 302.208000 912.204000 302.400000 912.228000 ;
  END
 END po3[215]
 PIN po3[216]
  DIRECTION INPUT ;
  USE SIGNAL ;
  PORT
   LAYER M4 ;
   RECT 302.208000 912.396000 302.400000 912.420000 ;
  END
 END po3[216]
 PIN po3[217]
  DIRECTION INPUT ;
  USE SIGNAL ;
  PORT
   LAYER M4 ;
   RECT 302.208000 912.588000 302.400000 912.612000 ;
  END
 END po3[217]
 PIN po3[218]
  DIRECTION INPUT ;
  USE SIGNAL ;
  PORT
   LAYER M4 ;
   RECT 302.208000 912.780000 302.400000 912.804000 ;
  END
 END po3[218]
 PIN po3[219]
  DIRECTION INPUT ;
  USE SIGNAL ;
  PORT
   LAYER M4 ;
   RECT 302.208000 912.972000 302.400000 912.996000 ;
  END
 END po3[219]
 PIN po3[220]
  DIRECTION INPUT ;
  USE SIGNAL ;
  PORT
   LAYER M4 ;
   RECT 302.208000 913.164000 302.400000 913.188000 ;
  END
 END po3[220]
 PIN po3[221]
  DIRECTION INPUT ;
  USE SIGNAL ;
  PORT
   LAYER M4 ;
   RECT 302.208000 913.356000 302.400000 913.380000 ;
  END
 END po3[221]
 PIN po3[222]
  DIRECTION INPUT ;
  USE SIGNAL ;
  PORT
   LAYER M4 ;
   RECT 302.208000 913.548000 302.400000 913.572000 ;
  END
 END po3[222]
 PIN po3[223]
  DIRECTION INPUT ;
  USE SIGNAL ;
  PORT
   LAYER M4 ;
   RECT 302.208000 913.740000 302.400000 913.764000 ;
  END
 END po3[223]
 PIN po3[224]
  DIRECTION INPUT ;
  USE SIGNAL ;
  PORT
   LAYER M4 ;
   RECT 302.208000 913.932000 302.400000 913.956000 ;
  END
 END po3[224]
 PIN po3[225]
  DIRECTION INPUT ;
  USE SIGNAL ;
  PORT
   LAYER M4 ;
   RECT 302.208000 914.124000 302.400000 914.148000 ;
  END
 END po3[225]
 PIN po3[226]
  DIRECTION INPUT ;
  USE SIGNAL ;
  PORT
   LAYER M4 ;
   RECT 302.208000 914.316000 302.400000 914.340000 ;
  END
 END po3[226]
 PIN po3[227]
  DIRECTION INPUT ;
  USE SIGNAL ;
  PORT
   LAYER M4 ;
   RECT 302.208000 914.508000 302.400000 914.532000 ;
  END
 END po3[227]
 PIN po3[228]
  DIRECTION INPUT ;
  USE SIGNAL ;
  PORT
   LAYER M4 ;
   RECT 302.208000 914.700000 302.400000 914.724000 ;
  END
 END po3[228]
 PIN po3[229]
  DIRECTION INPUT ;
  USE SIGNAL ;
  PORT
   LAYER M4 ;
   RECT 302.208000 914.892000 302.400000 914.916000 ;
  END
 END po3[229]
 PIN po3[230]
  DIRECTION INPUT ;
  USE SIGNAL ;
  PORT
   LAYER M4 ;
   RECT 302.208000 915.084000 302.400000 915.108000 ;
  END
 END po3[230]
 PIN po3[231]
  DIRECTION INPUT ;
  USE SIGNAL ;
  PORT
   LAYER M4 ;
   RECT 302.208000 915.276000 302.400000 915.300000 ;
  END
 END po3[231]
 PIN po3[232]
  DIRECTION INPUT ;
  USE SIGNAL ;
  PORT
   LAYER M4 ;
   RECT 302.208000 915.468000 302.400000 915.492000 ;
  END
 END po3[232]
 PIN po3[233]
  DIRECTION INPUT ;
  USE SIGNAL ;
  PORT
   LAYER M4 ;
   RECT 302.208000 915.660000 302.400000 915.684000 ;
  END
 END po3[233]
 PIN po3[234]
  DIRECTION INPUT ;
  USE SIGNAL ;
  PORT
   LAYER M4 ;
   RECT 302.208000 915.852000 302.400000 915.876000 ;
  END
 END po3[234]
 PIN po3[235]
  DIRECTION INPUT ;
  USE SIGNAL ;
  PORT
   LAYER M4 ;
   RECT 302.208000 916.044000 302.400000 916.068000 ;
  END
 END po3[235]
 PIN po3[236]
  DIRECTION INPUT ;
  USE SIGNAL ;
  PORT
   LAYER M4 ;
   RECT 302.208000 916.236000 302.400000 916.260000 ;
  END
 END po3[236]
 PIN po3[237]
  DIRECTION INPUT ;
  USE SIGNAL ;
  PORT
   LAYER M4 ;
   RECT 302.208000 916.428000 302.400000 916.452000 ;
  END
 END po3[237]
 PIN po3[238]
  DIRECTION INPUT ;
  USE SIGNAL ;
  PORT
   LAYER M4 ;
   RECT 302.208000 916.620000 302.400000 916.644000 ;
  END
 END po3[238]
 PIN po3[239]
  DIRECTION INPUT ;
  USE SIGNAL ;
  PORT
   LAYER M4 ;
   RECT 302.208000 916.812000 302.400000 916.836000 ;
  END
 END po3[239]
 PIN po3[240]
  DIRECTION INPUT ;
  USE SIGNAL ;
  PORT
   LAYER M4 ;
   RECT 302.208000 917.004000 302.400000 917.028000 ;
  END
 END po3[240]
 PIN po3[241]
  DIRECTION INPUT ;
  USE SIGNAL ;
  PORT
   LAYER M4 ;
   RECT 302.208000 917.196000 302.400000 917.220000 ;
  END
 END po3[241]
 PIN po3[242]
  DIRECTION INPUT ;
  USE SIGNAL ;
  PORT
   LAYER M4 ;
   RECT 302.208000 917.388000 302.400000 917.412000 ;
  END
 END po3[242]
 PIN po3[243]
  DIRECTION INPUT ;
  USE SIGNAL ;
  PORT
   LAYER M4 ;
   RECT 302.208000 917.580000 302.400000 917.604000 ;
  END
 END po3[243]
 PIN po3[244]
  DIRECTION INPUT ;
  USE SIGNAL ;
  PORT
   LAYER M4 ;
   RECT 302.208000 917.772000 302.400000 917.796000 ;
  END
 END po3[244]
 PIN po3[245]
  DIRECTION INPUT ;
  USE SIGNAL ;
  PORT
   LAYER M4 ;
   RECT 302.208000 917.964000 302.400000 917.988000 ;
  END
 END po3[245]
 PIN po3[246]
  DIRECTION INPUT ;
  USE SIGNAL ;
  PORT
   LAYER M4 ;
   RECT 302.208000 918.156000 302.400000 918.180000 ;
  END
 END po3[246]
 PIN po3[247]
  DIRECTION INPUT ;
  USE SIGNAL ;
  PORT
   LAYER M4 ;
   RECT 302.208000 918.348000 302.400000 918.372000 ;
  END
 END po3[247]
 PIN po3[248]
  DIRECTION INPUT ;
  USE SIGNAL ;
  PORT
   LAYER M4 ;
   RECT 302.208000 918.540000 302.400000 918.564000 ;
  END
 END po3[248]
 PIN po3[249]
  DIRECTION INPUT ;
  USE SIGNAL ;
  PORT
   LAYER M4 ;
   RECT 302.208000 918.732000 302.400000 918.756000 ;
  END
 END po3[249]
 PIN po3[250]
  DIRECTION INPUT ;
  USE SIGNAL ;
  PORT
   LAYER M4 ;
   RECT 302.208000 918.924000 302.400000 918.948000 ;
  END
 END po3[250]
 PIN po3[251]
  DIRECTION INPUT ;
  USE SIGNAL ;
  PORT
   LAYER M4 ;
   RECT 302.208000 919.116000 302.400000 919.140000 ;
  END
 END po3[251]
 PIN po3[252]
  DIRECTION INPUT ;
  USE SIGNAL ;
  PORT
   LAYER M4 ;
   RECT 302.208000 919.308000 302.400000 919.332000 ;
  END
 END po3[252]
 PIN po3[253]
  DIRECTION INPUT ;
  USE SIGNAL ;
  PORT
   LAYER M4 ;
   RECT 302.208000 919.500000 302.400000 919.524000 ;
  END
 END po3[253]
 PIN po3[254]
  DIRECTION INPUT ;
  USE SIGNAL ;
  PORT
   LAYER M4 ;
   RECT 302.208000 919.692000 302.400000 919.716000 ;
  END
 END po3[254]
 PIN po3[255]
  DIRECTION INPUT ;
  USE SIGNAL ;
  PORT
   LAYER M4 ;
   RECT 302.208000 919.884000 302.400000 919.908000 ;
  END
 END po3[255]
 PIN po3[256]
  DIRECTION INPUT ;
  USE SIGNAL ;
  PORT
   LAYER M4 ;
   RECT 302.208000 920.076000 302.400000 920.100000 ;
  END
 END po3[256]
 PIN po3[257]
  DIRECTION INPUT ;
  USE SIGNAL ;
  PORT
   LAYER M4 ;
   RECT 302.208000 920.268000 302.400000 920.292000 ;
  END
 END po3[257]
 PIN po3[258]
  DIRECTION INPUT ;
  USE SIGNAL ;
  PORT
   LAYER M4 ;
   RECT 302.208000 920.460000 302.400000 920.484000 ;
  END
 END po3[258]
 PIN po3[259]
  DIRECTION INPUT ;
  USE SIGNAL ;
  PORT
   LAYER M4 ;
   RECT 302.208000 920.652000 302.400000 920.676000 ;
  END
 END po3[259]
 PIN po3[260]
  DIRECTION INPUT ;
  USE SIGNAL ;
  PORT
   LAYER M4 ;
   RECT 302.208000 920.844000 302.400000 920.868000 ;
  END
 END po3[260]
 PIN po3[261]
  DIRECTION INPUT ;
  USE SIGNAL ;
  PORT
   LAYER M4 ;
   RECT 302.208000 921.036000 302.400000 921.060000 ;
  END
 END po3[261]
 PIN po3[262]
  DIRECTION INPUT ;
  USE SIGNAL ;
  PORT
   LAYER M4 ;
   RECT 302.208000 921.228000 302.400000 921.252000 ;
  END
 END po3[262]
 PIN po3[263]
  DIRECTION INPUT ;
  USE SIGNAL ;
  PORT
   LAYER M4 ;
   RECT 302.208000 921.420000 302.400000 921.444000 ;
  END
 END po3[263]
 PIN po3[264]
  DIRECTION INPUT ;
  USE SIGNAL ;
  PORT
   LAYER M4 ;
   RECT 302.208000 921.612000 302.400000 921.636000 ;
  END
 END po3[264]
 PIN po3[265]
  DIRECTION INPUT ;
  USE SIGNAL ;
  PORT
   LAYER M4 ;
   RECT 302.208000 921.804000 302.400000 921.828000 ;
  END
 END po3[265]
 PIN po3[266]
  DIRECTION INPUT ;
  USE SIGNAL ;
  PORT
   LAYER M4 ;
   RECT 302.208000 921.996000 302.400000 922.020000 ;
  END
 END po3[266]
 PIN po3[267]
  DIRECTION INPUT ;
  USE SIGNAL ;
  PORT
   LAYER M4 ;
   RECT 302.208000 922.188000 302.400000 922.212000 ;
  END
 END po3[267]
 PIN po3[268]
  DIRECTION INPUT ;
  USE SIGNAL ;
  PORT
   LAYER M4 ;
   RECT 302.208000 922.380000 302.400000 922.404000 ;
  END
 END po3[268]
 PIN po3[269]
  DIRECTION INPUT ;
  USE SIGNAL ;
  PORT
   LAYER M4 ;
   RECT 302.208000 922.572000 302.400000 922.596000 ;
  END
 END po3[269]
 PIN po3[270]
  DIRECTION INPUT ;
  USE SIGNAL ;
  PORT
   LAYER M4 ;
   RECT 302.208000 922.764000 302.400000 922.788000 ;
  END
 END po3[270]
 PIN po3[271]
  DIRECTION INPUT ;
  USE SIGNAL ;
  PORT
   LAYER M4 ;
   RECT 302.208000 922.956000 302.400000 922.980000 ;
  END
 END po3[271]
 PIN po3[272]
  DIRECTION INPUT ;
  USE SIGNAL ;
  PORT
   LAYER M4 ;
   RECT 302.208000 923.148000 302.400000 923.172000 ;
  END
 END po3[272]
 PIN po3[273]
  DIRECTION INPUT ;
  USE SIGNAL ;
  PORT
   LAYER M4 ;
   RECT 302.208000 923.340000 302.400000 923.364000 ;
  END
 END po3[273]
 PIN po3[274]
  DIRECTION INPUT ;
  USE SIGNAL ;
  PORT
   LAYER M4 ;
   RECT 302.208000 923.532000 302.400000 923.556000 ;
  END
 END po3[274]
 PIN po3[275]
  DIRECTION INPUT ;
  USE SIGNAL ;
  PORT
   LAYER M4 ;
   RECT 302.208000 923.724000 302.400000 923.748000 ;
  END
 END po3[275]
 PIN po3[276]
  DIRECTION INPUT ;
  USE SIGNAL ;
  PORT
   LAYER M4 ;
   RECT 302.208000 923.916000 302.400000 923.940000 ;
  END
 END po3[276]
 PIN po3[277]
  DIRECTION INPUT ;
  USE SIGNAL ;
  PORT
   LAYER M4 ;
   RECT 302.208000 924.108000 302.400000 924.132000 ;
  END
 END po3[277]
 PIN po3[278]
  DIRECTION INPUT ;
  USE SIGNAL ;
  PORT
   LAYER M4 ;
   RECT 302.208000 924.300000 302.400000 924.324000 ;
  END
 END po3[278]
 PIN po3[279]
  DIRECTION INPUT ;
  USE SIGNAL ;
  PORT
   LAYER M4 ;
   RECT 302.208000 924.492000 302.400000 924.516000 ;
  END
 END po3[279]
 PIN po3[280]
  DIRECTION INPUT ;
  USE SIGNAL ;
  PORT
   LAYER M4 ;
   RECT 302.208000 924.684000 302.400000 924.708000 ;
  END
 END po3[280]
 PIN po3[281]
  DIRECTION INPUT ;
  USE SIGNAL ;
  PORT
   LAYER M4 ;
   RECT 302.208000 924.876000 302.400000 924.900000 ;
  END
 END po3[281]
 PIN po3[282]
  DIRECTION INPUT ;
  USE SIGNAL ;
  PORT
   LAYER M4 ;
   RECT 302.208000 925.068000 302.400000 925.092000 ;
  END
 END po3[282]
 PIN po3[283]
  DIRECTION INPUT ;
  USE SIGNAL ;
  PORT
   LAYER M4 ;
   RECT 302.208000 925.260000 302.400000 925.284000 ;
  END
 END po3[283]
 PIN po3[284]
  DIRECTION INPUT ;
  USE SIGNAL ;
  PORT
   LAYER M4 ;
   RECT 302.208000 925.452000 302.400000 925.476000 ;
  END
 END po3[284]
 PIN po3[285]
  DIRECTION INPUT ;
  USE SIGNAL ;
  PORT
   LAYER M4 ;
   RECT 302.208000 925.644000 302.400000 925.668000 ;
  END
 END po3[285]
 PIN po3[286]
  DIRECTION INPUT ;
  USE SIGNAL ;
  PORT
   LAYER M4 ;
   RECT 302.208000 925.836000 302.400000 925.860000 ;
  END
 END po3[286]
 PIN po3[287]
  DIRECTION INPUT ;
  USE SIGNAL ;
  PORT
   LAYER M4 ;
   RECT 302.208000 926.028000 302.400000 926.052000 ;
  END
 END po3[287]
 PIN po3[288]
  DIRECTION INPUT ;
  USE SIGNAL ;
  PORT
   LAYER M4 ;
   RECT 302.208000 926.220000 302.400000 926.244000 ;
  END
 END po3[288]
 PIN po3[289]
  DIRECTION INPUT ;
  USE SIGNAL ;
  PORT
   LAYER M4 ;
   RECT 302.208000 926.412000 302.400000 926.436000 ;
  END
 END po3[289]
 PIN po3[290]
  DIRECTION INPUT ;
  USE SIGNAL ;
  PORT
   LAYER M4 ;
   RECT 302.208000 926.604000 302.400000 926.628000 ;
  END
 END po3[290]
 PIN po3[291]
  DIRECTION INPUT ;
  USE SIGNAL ;
  PORT
   LAYER M4 ;
   RECT 302.208000 926.796000 302.400000 926.820000 ;
  END
 END po3[291]
 PIN po3[292]
  DIRECTION INPUT ;
  USE SIGNAL ;
  PORT
   LAYER M4 ;
   RECT 302.208000 926.988000 302.400000 927.012000 ;
  END
 END po3[292]
 PIN po3[293]
  DIRECTION INPUT ;
  USE SIGNAL ;
  PORT
   LAYER M4 ;
   RECT 302.208000 927.180000 302.400000 927.204000 ;
  END
 END po3[293]
 PIN po3[294]
  DIRECTION INPUT ;
  USE SIGNAL ;
  PORT
   LAYER M4 ;
   RECT 302.208000 927.372000 302.400000 927.396000 ;
  END
 END po3[294]
 PIN po3[295]
  DIRECTION INPUT ;
  USE SIGNAL ;
  PORT
   LAYER M4 ;
   RECT 302.208000 927.564000 302.400000 927.588000 ;
  END
 END po3[295]
 PIN po3[296]
  DIRECTION INPUT ;
  USE SIGNAL ;
  PORT
   LAYER M4 ;
   RECT 302.208000 927.756000 302.400000 927.780000 ;
  END
 END po3[296]
 PIN po3[297]
  DIRECTION INPUT ;
  USE SIGNAL ;
  PORT
   LAYER M4 ;
   RECT 302.208000 927.948000 302.400000 927.972000 ;
  END
 END po3[297]
 PIN po3[298]
  DIRECTION INPUT ;
  USE SIGNAL ;
  PORT
   LAYER M4 ;
   RECT 302.208000 928.140000 302.400000 928.164000 ;
  END
 END po3[298]
 PIN po3[299]
  DIRECTION INPUT ;
  USE SIGNAL ;
  PORT
   LAYER M4 ;
   RECT 302.208000 928.332000 302.400000 928.356000 ;
  END
 END po3[299]
 PIN po3[300]
  DIRECTION INPUT ;
  USE SIGNAL ;
  PORT
   LAYER M4 ;
   RECT 302.208000 928.524000 302.400000 928.548000 ;
  END
 END po3[300]
 PIN po3[301]
  DIRECTION INPUT ;
  USE SIGNAL ;
  PORT
   LAYER M4 ;
   RECT 302.208000 928.716000 302.400000 928.740000 ;
  END
 END po3[301]
 PIN po3[302]
  DIRECTION INPUT ;
  USE SIGNAL ;
  PORT
   LAYER M4 ;
   RECT 302.208000 928.908000 302.400000 928.932000 ;
  END
 END po3[302]
 PIN po3[303]
  DIRECTION INPUT ;
  USE SIGNAL ;
  PORT
   LAYER M4 ;
   RECT 302.208000 929.100000 302.400000 929.124000 ;
  END
 END po3[303]
 PIN po3[304]
  DIRECTION INPUT ;
  USE SIGNAL ;
  PORT
   LAYER M4 ;
   RECT 302.208000 929.292000 302.400000 929.316000 ;
  END
 END po3[304]
 PIN po3[305]
  DIRECTION INPUT ;
  USE SIGNAL ;
  PORT
   LAYER M4 ;
   RECT 302.208000 929.484000 302.400000 929.508000 ;
  END
 END po3[305]
 PIN po3[306]
  DIRECTION INPUT ;
  USE SIGNAL ;
  PORT
   LAYER M4 ;
   RECT 302.208000 929.676000 302.400000 929.700000 ;
  END
 END po3[306]
 PIN po3[307]
  DIRECTION INPUT ;
  USE SIGNAL ;
  PORT
   LAYER M4 ;
   RECT 302.208000 929.868000 302.400000 929.892000 ;
  END
 END po3[307]
 PIN po3[308]
  DIRECTION INPUT ;
  USE SIGNAL ;
  PORT
   LAYER M4 ;
   RECT 302.208000 930.060000 302.400000 930.084000 ;
  END
 END po3[308]
 PIN po3[309]
  DIRECTION INPUT ;
  USE SIGNAL ;
  PORT
   LAYER M4 ;
   RECT 302.208000 930.252000 302.400000 930.276000 ;
  END
 END po3[309]
 PIN po3[310]
  DIRECTION INPUT ;
  USE SIGNAL ;
  PORT
   LAYER M4 ;
   RECT 302.208000 930.444000 302.400000 930.468000 ;
  END
 END po3[310]
 PIN po3[311]
  DIRECTION INPUT ;
  USE SIGNAL ;
  PORT
   LAYER M4 ;
   RECT 302.208000 930.636000 302.400000 930.660000 ;
  END
 END po3[311]
 PIN po3[312]
  DIRECTION INPUT ;
  USE SIGNAL ;
  PORT
   LAYER M4 ;
   RECT 302.208000 930.828000 302.400000 930.852000 ;
  END
 END po3[312]
 PIN po3[313]
  DIRECTION INPUT ;
  USE SIGNAL ;
  PORT
   LAYER M4 ;
   RECT 302.208000 931.020000 302.400000 931.044000 ;
  END
 END po3[313]
 PIN po3[314]
  DIRECTION INPUT ;
  USE SIGNAL ;
  PORT
   LAYER M4 ;
   RECT 302.208000 931.212000 302.400000 931.236000 ;
  END
 END po3[314]
 PIN po3[315]
  DIRECTION INPUT ;
  USE SIGNAL ;
  PORT
   LAYER M4 ;
   RECT 302.208000 931.404000 302.400000 931.428000 ;
  END
 END po3[315]
 PIN po3[316]
  DIRECTION INPUT ;
  USE SIGNAL ;
  PORT
   LAYER M4 ;
   RECT 302.208000 931.596000 302.400000 931.620000 ;
  END
 END po3[316]
 PIN po3[317]
  DIRECTION INPUT ;
  USE SIGNAL ;
  PORT
   LAYER M4 ;
   RECT 302.208000 931.788000 302.400000 931.812000 ;
  END
 END po3[317]
 PIN po3[318]
  DIRECTION INPUT ;
  USE SIGNAL ;
  PORT
   LAYER M4 ;
   RECT 302.208000 931.980000 302.400000 932.004000 ;
  END
 END po3[318]
 PIN po3[319]
  DIRECTION INPUT ;
  USE SIGNAL ;
  PORT
   LAYER M4 ;
   RECT 302.208000 932.172000 302.400000 932.196000 ;
  END
 END po3[319]
 PIN po3[320]
  DIRECTION INPUT ;
  USE SIGNAL ;
  PORT
   LAYER M4 ;
   RECT 302.208000 932.364000 302.400000 932.388000 ;
  END
 END po3[320]
 PIN po3[321]
  DIRECTION INPUT ;
  USE SIGNAL ;
  PORT
   LAYER M4 ;
   RECT 302.208000 932.556000 302.400000 932.580000 ;
  END
 END po3[321]
 PIN po3[322]
  DIRECTION INPUT ;
  USE SIGNAL ;
  PORT
   LAYER M4 ;
   RECT 302.208000 932.748000 302.400000 932.772000 ;
  END
 END po3[322]
 PIN po3[323]
  DIRECTION INPUT ;
  USE SIGNAL ;
  PORT
   LAYER M4 ;
   RECT 302.208000 932.940000 302.400000 932.964000 ;
  END
 END po3[323]
 PIN po3[324]
  DIRECTION INPUT ;
  USE SIGNAL ;
  PORT
   LAYER M4 ;
   RECT 302.208000 933.132000 302.400000 933.156000 ;
  END
 END po3[324]
 PIN po3[325]
  DIRECTION INPUT ;
  USE SIGNAL ;
  PORT
   LAYER M4 ;
   RECT 302.208000 933.324000 302.400000 933.348000 ;
  END
 END po3[325]
 PIN po3[326]
  DIRECTION INPUT ;
  USE SIGNAL ;
  PORT
   LAYER M4 ;
   RECT 302.208000 933.516000 302.400000 933.540000 ;
  END
 END po3[326]
 PIN po3[327]
  DIRECTION INPUT ;
  USE SIGNAL ;
  PORT
   LAYER M4 ;
   RECT 302.208000 933.708000 302.400000 933.732000 ;
  END
 END po3[327]
 PIN pi3[0]
  DIRECTION OUTPUT ;
  USE SIGNAL ;
  PORT
   LAYER M4 ;
   RECT 302.208000 933.900000 302.400000 933.924000 ;
  END
 END pi3[0]
 PIN pi3[1]
  DIRECTION OUTPUT ;
  USE SIGNAL ;
  PORT
   LAYER M4 ;
   RECT 302.208000 934.092000 302.400000 934.116000 ;
  END
 END pi3[1]
 PIN pi3[2]
  DIRECTION OUTPUT ;
  USE SIGNAL ;
  PORT
   LAYER M4 ;
   RECT 302.208000 934.284000 302.400000 934.308000 ;
  END
 END pi3[2]
 PIN pi3[3]
  DIRECTION OUTPUT ;
  USE SIGNAL ;
  PORT
   LAYER M4 ;
   RECT 302.208000 934.476000 302.400000 934.500000 ;
  END
 END pi3[3]
 PIN pi3[4]
  DIRECTION OUTPUT ;
  USE SIGNAL ;
  PORT
   LAYER M4 ;
   RECT 302.208000 934.668000 302.400000 934.692000 ;
  END
 END pi3[4]
 PIN pi3[5]
  DIRECTION OUTPUT ;
  USE SIGNAL ;
  PORT
   LAYER M4 ;
   RECT 302.208000 934.860000 302.400000 934.884000 ;
  END
 END pi3[5]
 PIN pi3[6]
  DIRECTION OUTPUT ;
  USE SIGNAL ;
  PORT
   LAYER M4 ;
   RECT 302.208000 935.052000 302.400000 935.076000 ;
  END
 END pi3[6]
 PIN pi3[7]
  DIRECTION OUTPUT ;
  USE SIGNAL ;
  PORT
   LAYER M4 ;
   RECT 302.208000 935.244000 302.400000 935.268000 ;
  END
 END pi3[7]
 PIN pi3[8]
  DIRECTION OUTPUT ;
  USE SIGNAL ;
  PORT
   LAYER M4 ;
   RECT 302.208000 935.436000 302.400000 935.460000 ;
  END
 END pi3[8]
 PIN pi3[9]
  DIRECTION OUTPUT ;
  USE SIGNAL ;
  PORT
   LAYER M4 ;
   RECT 302.208000 935.628000 302.400000 935.652000 ;
  END
 END pi3[9]
 PIN pi3[10]
  DIRECTION OUTPUT ;
  USE SIGNAL ;
  PORT
   LAYER M4 ;
   RECT 302.208000 935.820000 302.400000 935.844000 ;
  END
 END pi3[10]
 PIN pi3[11]
  DIRECTION OUTPUT ;
  USE SIGNAL ;
  PORT
   LAYER M4 ;
   RECT 302.208000 936.012000 302.400000 936.036000 ;
  END
 END pi3[11]
 PIN pi3[12]
  DIRECTION OUTPUT ;
  USE SIGNAL ;
  PORT
   LAYER M4 ;
   RECT 302.208000 936.204000 302.400000 936.228000 ;
  END
 END pi3[12]
 PIN pi3[13]
  DIRECTION OUTPUT ;
  USE SIGNAL ;
  PORT
   LAYER M4 ;
   RECT 302.208000 936.396000 302.400000 936.420000 ;
  END
 END pi3[13]
 PIN pi3[14]
  DIRECTION OUTPUT ;
  USE SIGNAL ;
  PORT
   LAYER M4 ;
   RECT 302.208000 936.588000 302.400000 936.612000 ;
  END
 END pi3[14]
 PIN pi3[15]
  DIRECTION OUTPUT ;
  USE SIGNAL ;
  PORT
   LAYER M4 ;
   RECT 302.208000 936.780000 302.400000 936.804000 ;
  END
 END pi3[15]
 PIN pi3[16]
  DIRECTION OUTPUT ;
  USE SIGNAL ;
  PORT
   LAYER M4 ;
   RECT 302.208000 936.972000 302.400000 936.996000 ;
  END
 END pi3[16]
 PIN pi3[17]
  DIRECTION OUTPUT ;
  USE SIGNAL ;
  PORT
   LAYER M4 ;
   RECT 302.208000 937.164000 302.400000 937.188000 ;
  END
 END pi3[17]
 PIN pi3[18]
  DIRECTION OUTPUT ;
  USE SIGNAL ;
  PORT
   LAYER M4 ;
   RECT 302.208000 937.356000 302.400000 937.380000 ;
  END
 END pi3[18]
 PIN pi3[19]
  DIRECTION OUTPUT ;
  USE SIGNAL ;
  PORT
   LAYER M4 ;
   RECT 302.208000 937.548000 302.400000 937.572000 ;
  END
 END pi3[19]
 PIN pi3[20]
  DIRECTION OUTPUT ;
  USE SIGNAL ;
  PORT
   LAYER M4 ;
   RECT 302.208000 937.740000 302.400000 937.764000 ;
  END
 END pi3[20]
 PIN pi3[21]
  DIRECTION OUTPUT ;
  USE SIGNAL ;
  PORT
   LAYER M4 ;
   RECT 302.208000 937.932000 302.400000 937.956000 ;
  END
 END pi3[21]
 PIN pi3[22]
  DIRECTION OUTPUT ;
  USE SIGNAL ;
  PORT
   LAYER M4 ;
   RECT 302.208000 938.124000 302.400000 938.148000 ;
  END
 END pi3[22]
 PIN pi3[23]
  DIRECTION OUTPUT ;
  USE SIGNAL ;
  PORT
   LAYER M4 ;
   RECT 302.208000 938.316000 302.400000 938.340000 ;
  END
 END pi3[23]
 PIN pi3[24]
  DIRECTION OUTPUT ;
  USE SIGNAL ;
  PORT
   LAYER M4 ;
   RECT 302.208000 938.508000 302.400000 938.532000 ;
  END
 END pi3[24]
 PIN pi3[25]
  DIRECTION OUTPUT ;
  USE SIGNAL ;
  PORT
   LAYER M4 ;
   RECT 302.208000 938.700000 302.400000 938.724000 ;
  END
 END pi3[25]
 PIN pi3[26]
  DIRECTION OUTPUT ;
  USE SIGNAL ;
  PORT
   LAYER M4 ;
   RECT 302.208000 938.892000 302.400000 938.916000 ;
  END
 END pi3[26]
 PIN pi3[27]
  DIRECTION OUTPUT ;
  USE SIGNAL ;
  PORT
   LAYER M4 ;
   RECT 302.208000 939.084000 302.400000 939.108000 ;
  END
 END pi3[27]
 PIN pi3[28]
  DIRECTION OUTPUT ;
  USE SIGNAL ;
  PORT
   LAYER M4 ;
   RECT 302.208000 939.276000 302.400000 939.300000 ;
  END
 END pi3[28]
 PIN pi3[29]
  DIRECTION OUTPUT ;
  USE SIGNAL ;
  PORT
   LAYER M4 ;
   RECT 302.208000 939.468000 302.400000 939.492000 ;
  END
 END pi3[29]
 PIN pi3[30]
  DIRECTION OUTPUT ;
  USE SIGNAL ;
  PORT
   LAYER M4 ;
   RECT 302.208000 939.660000 302.400000 939.684000 ;
  END
 END pi3[30]
 PIN pi3[31]
  DIRECTION OUTPUT ;
  USE SIGNAL ;
  PORT
   LAYER M4 ;
   RECT 302.208000 939.852000 302.400000 939.876000 ;
  END
 END pi3[31]
 PIN pi3[32]
  DIRECTION OUTPUT ;
  USE SIGNAL ;
  PORT
   LAYER M4 ;
   RECT 302.208000 940.044000 302.400000 940.068000 ;
  END
 END pi3[32]
 PIN pi3[33]
  DIRECTION OUTPUT ;
  USE SIGNAL ;
  PORT
   LAYER M4 ;
   RECT 302.208000 940.236000 302.400000 940.260000 ;
  END
 END pi3[33]
 PIN pi3[34]
  DIRECTION OUTPUT ;
  USE SIGNAL ;
  PORT
   LAYER M4 ;
   RECT 302.208000 940.428000 302.400000 940.452000 ;
  END
 END pi3[34]
 PIN pi3[35]
  DIRECTION OUTPUT ;
  USE SIGNAL ;
  PORT
   LAYER M4 ;
   RECT 302.208000 940.620000 302.400000 940.644000 ;
  END
 END pi3[35]
 PIN pi3[36]
  DIRECTION OUTPUT ;
  USE SIGNAL ;
  PORT
   LAYER M4 ;
   RECT 302.208000 940.812000 302.400000 940.836000 ;
  END
 END pi3[36]
 PIN pi3[37]
  DIRECTION OUTPUT ;
  USE SIGNAL ;
  PORT
   LAYER M4 ;
   RECT 302.208000 941.004000 302.400000 941.028000 ;
  END
 END pi3[37]
 PIN pi3[38]
  DIRECTION OUTPUT ;
  USE SIGNAL ;
  PORT
   LAYER M4 ;
   RECT 302.208000 941.196000 302.400000 941.220000 ;
  END
 END pi3[38]
 PIN pi3[39]
  DIRECTION OUTPUT ;
  USE SIGNAL ;
  PORT
   LAYER M4 ;
   RECT 302.208000 941.388000 302.400000 941.412000 ;
  END
 END pi3[39]
 PIN pi3[40]
  DIRECTION OUTPUT ;
  USE SIGNAL ;
  PORT
   LAYER M4 ;
   RECT 302.208000 941.580000 302.400000 941.604000 ;
  END
 END pi3[40]
 PIN pi3[41]
  DIRECTION OUTPUT ;
  USE SIGNAL ;
  PORT
   LAYER M4 ;
   RECT 302.208000 941.772000 302.400000 941.796000 ;
  END
 END pi3[41]
 PIN pi3[42]
  DIRECTION OUTPUT ;
  USE SIGNAL ;
  PORT
   LAYER M4 ;
   RECT 302.208000 941.964000 302.400000 941.988000 ;
  END
 END pi3[42]
 PIN pi3[43]
  DIRECTION OUTPUT ;
  USE SIGNAL ;
  PORT
   LAYER M4 ;
   RECT 302.208000 942.156000 302.400000 942.180000 ;
  END
 END pi3[43]
 PIN pi3[44]
  DIRECTION OUTPUT ;
  USE SIGNAL ;
  PORT
   LAYER M4 ;
   RECT 302.208000 942.348000 302.400000 942.372000 ;
  END
 END pi3[44]
 PIN pi3[45]
  DIRECTION OUTPUT ;
  USE SIGNAL ;
  PORT
   LAYER M4 ;
   RECT 302.208000 942.540000 302.400000 942.564000 ;
  END
 END pi3[45]
 PIN pi3[46]
  DIRECTION OUTPUT ;
  USE SIGNAL ;
  PORT
   LAYER M4 ;
   RECT 302.208000 942.732000 302.400000 942.756000 ;
  END
 END pi3[46]
 PIN pi3[47]
  DIRECTION OUTPUT ;
  USE SIGNAL ;
  PORT
   LAYER M4 ;
   RECT 302.208000 942.924000 302.400000 942.948000 ;
  END
 END pi3[47]
 PIN pi3[48]
  DIRECTION OUTPUT ;
  USE SIGNAL ;
  PORT
   LAYER M4 ;
   RECT 302.208000 943.116000 302.400000 943.140000 ;
  END
 END pi3[48]
 PIN pi3[49]
  DIRECTION OUTPUT ;
  USE SIGNAL ;
  PORT
   LAYER M4 ;
   RECT 302.208000 943.308000 302.400000 943.332000 ;
  END
 END pi3[49]
 PIN pi3[50]
  DIRECTION OUTPUT ;
  USE SIGNAL ;
  PORT
   LAYER M4 ;
   RECT 302.208000 943.500000 302.400000 943.524000 ;
  END
 END pi3[50]
 PIN pi3[51]
  DIRECTION OUTPUT ;
  USE SIGNAL ;
  PORT
   LAYER M4 ;
   RECT 302.208000 943.692000 302.400000 943.716000 ;
  END
 END pi3[51]
 PIN pi3[52]
  DIRECTION OUTPUT ;
  USE SIGNAL ;
  PORT
   LAYER M4 ;
   RECT 302.208000 943.884000 302.400000 943.908000 ;
  END
 END pi3[52]
 PIN pi3[53]
  DIRECTION OUTPUT ;
  USE SIGNAL ;
  PORT
   LAYER M4 ;
   RECT 302.208000 944.076000 302.400000 944.100000 ;
  END
 END pi3[53]
 PIN pi3[54]
  DIRECTION OUTPUT ;
  USE SIGNAL ;
  PORT
   LAYER M4 ;
   RECT 302.208000 944.268000 302.400000 944.292000 ;
  END
 END pi3[54]
 PIN pi3[55]
  DIRECTION OUTPUT ;
  USE SIGNAL ;
  PORT
   LAYER M4 ;
   RECT 302.208000 944.460000 302.400000 944.484000 ;
  END
 END pi3[55]
 PIN pi3[56]
  DIRECTION OUTPUT ;
  USE SIGNAL ;
  PORT
   LAYER M4 ;
   RECT 302.208000 944.652000 302.400000 944.676000 ;
  END
 END pi3[56]
 PIN pi3[57]
  DIRECTION OUTPUT ;
  USE SIGNAL ;
  PORT
   LAYER M4 ;
   RECT 302.208000 944.844000 302.400000 944.868000 ;
  END
 END pi3[57]
 PIN pi3[58]
  DIRECTION OUTPUT ;
  USE SIGNAL ;
  PORT
   LAYER M4 ;
   RECT 302.208000 945.036000 302.400000 945.060000 ;
  END
 END pi3[58]
 PIN pi3[59]
  DIRECTION OUTPUT ;
  USE SIGNAL ;
  PORT
   LAYER M4 ;
   RECT 302.208000 945.228000 302.400000 945.252000 ;
  END
 END pi3[59]
 PIN pi3[60]
  DIRECTION OUTPUT ;
  USE SIGNAL ;
  PORT
   LAYER M4 ;
   RECT 302.208000 945.420000 302.400000 945.444000 ;
  END
 END pi3[60]
 PIN pi3[61]
  DIRECTION OUTPUT ;
  USE SIGNAL ;
  PORT
   LAYER M4 ;
   RECT 302.208000 945.612000 302.400000 945.636000 ;
  END
 END pi3[61]
 PIN pi3[62]
  DIRECTION OUTPUT ;
  USE SIGNAL ;
  PORT
   LAYER M4 ;
   RECT 302.208000 945.804000 302.400000 945.828000 ;
  END
 END pi3[62]
 PIN pi3[63]
  DIRECTION OUTPUT ;
  USE SIGNAL ;
  PORT
   LAYER M4 ;
   RECT 302.208000 945.996000 302.400000 946.020000 ;
  END
 END pi3[63]
 PIN pi3[64]
  DIRECTION OUTPUT ;
  USE SIGNAL ;
  PORT
   LAYER M4 ;
   RECT 302.208000 946.188000 302.400000 946.212000 ;
  END
 END pi3[64]
 PIN pi3[65]
  DIRECTION OUTPUT ;
  USE SIGNAL ;
  PORT
   LAYER M4 ;
   RECT 302.208000 946.380000 302.400000 946.404000 ;
  END
 END pi3[65]
 PIN pi3[66]
  DIRECTION OUTPUT ;
  USE SIGNAL ;
  PORT
   LAYER M4 ;
   RECT 302.208000 946.572000 302.400000 946.596000 ;
  END
 END pi3[66]
 PIN pi3[67]
  DIRECTION OUTPUT ;
  USE SIGNAL ;
  PORT
   LAYER M4 ;
   RECT 302.208000 946.764000 302.400000 946.788000 ;
  END
 END pi3[67]
 PIN pi3[68]
  DIRECTION OUTPUT ;
  USE SIGNAL ;
  PORT
   LAYER M4 ;
   RECT 302.208000 946.956000 302.400000 946.980000 ;
  END
 END pi3[68]
 PIN pi3[69]
  DIRECTION OUTPUT ;
  USE SIGNAL ;
  PORT
   LAYER M4 ;
   RECT 302.208000 947.148000 302.400000 947.172000 ;
  END
 END pi3[69]
 PIN pi3[70]
  DIRECTION OUTPUT ;
  USE SIGNAL ;
  PORT
   LAYER M4 ;
   RECT 302.208000 947.340000 302.400000 947.364000 ;
  END
 END pi3[70]
 PIN pi3[71]
  DIRECTION OUTPUT ;
  USE SIGNAL ;
  PORT
   LAYER M4 ;
   RECT 302.208000 947.532000 302.400000 947.556000 ;
  END
 END pi3[71]
 PIN pi3[72]
  DIRECTION OUTPUT ;
  USE SIGNAL ;
  PORT
   LAYER M4 ;
   RECT 302.208000 947.724000 302.400000 947.748000 ;
  END
 END pi3[72]
 PIN pi3[73]
  DIRECTION OUTPUT ;
  USE SIGNAL ;
  PORT
   LAYER M4 ;
   RECT 302.208000 947.916000 302.400000 947.940000 ;
  END
 END pi3[73]
 PIN pi3[74]
  DIRECTION OUTPUT ;
  USE SIGNAL ;
  PORT
   LAYER M4 ;
   RECT 302.208000 948.108000 302.400000 948.132000 ;
  END
 END pi3[74]
 PIN pi3[75]
  DIRECTION OUTPUT ;
  USE SIGNAL ;
  PORT
   LAYER M4 ;
   RECT 302.208000 948.300000 302.400000 948.324000 ;
  END
 END pi3[75]
 PIN pi3[76]
  DIRECTION OUTPUT ;
  USE SIGNAL ;
  PORT
   LAYER M4 ;
   RECT 302.208000 948.492000 302.400000 948.516000 ;
  END
 END pi3[76]
 PIN pi3[77]
  DIRECTION OUTPUT ;
  USE SIGNAL ;
  PORT
   LAYER M4 ;
   RECT 302.208000 948.684000 302.400000 948.708000 ;
  END
 END pi3[77]
 PIN pi3[78]
  DIRECTION OUTPUT ;
  USE SIGNAL ;
  PORT
   LAYER M4 ;
   RECT 302.208000 948.876000 302.400000 948.900000 ;
  END
 END pi3[78]
 PIN pi3[79]
  DIRECTION OUTPUT ;
  USE SIGNAL ;
  PORT
   LAYER M4 ;
   RECT 302.208000 949.068000 302.400000 949.092000 ;
  END
 END pi3[79]
 PIN pi3[80]
  DIRECTION OUTPUT ;
  USE SIGNAL ;
  PORT
   LAYER M4 ;
   RECT 302.208000 949.260000 302.400000 949.284000 ;
  END
 END pi3[80]
 PIN pi3[81]
  DIRECTION OUTPUT ;
  USE SIGNAL ;
  PORT
   LAYER M4 ;
   RECT 302.208000 949.452000 302.400000 949.476000 ;
  END
 END pi3[81]
 PIN pi3[82]
  DIRECTION OUTPUT ;
  USE SIGNAL ;
  PORT
   LAYER M4 ;
   RECT 302.208000 949.644000 302.400000 949.668000 ;
  END
 END pi3[82]
 PIN pi3[83]
  DIRECTION OUTPUT ;
  USE SIGNAL ;
  PORT
   LAYER M4 ;
   RECT 302.208000 949.836000 302.400000 949.860000 ;
  END
 END pi3[83]
 PIN pi3[84]
  DIRECTION OUTPUT ;
  USE SIGNAL ;
  PORT
   LAYER M4 ;
   RECT 302.208000 950.028000 302.400000 950.052000 ;
  END
 END pi3[84]
 PIN pi3[85]
  DIRECTION OUTPUT ;
  USE SIGNAL ;
  PORT
   LAYER M4 ;
   RECT 302.208000 950.220000 302.400000 950.244000 ;
  END
 END pi3[85]
 PIN pi3[86]
  DIRECTION OUTPUT ;
  USE SIGNAL ;
  PORT
   LAYER M4 ;
   RECT 302.208000 950.412000 302.400000 950.436000 ;
  END
 END pi3[86]
 PIN pi3[87]
  DIRECTION OUTPUT ;
  USE SIGNAL ;
  PORT
   LAYER M4 ;
   RECT 302.208000 950.604000 302.400000 950.628000 ;
  END
 END pi3[87]
 PIN pi3[88]
  DIRECTION OUTPUT ;
  USE SIGNAL ;
  PORT
   LAYER M4 ;
   RECT 302.208000 950.796000 302.400000 950.820000 ;
  END
 END pi3[88]
 PIN pi3[89]
  DIRECTION OUTPUT ;
  USE SIGNAL ;
  PORT
   LAYER M4 ;
   RECT 302.208000 950.988000 302.400000 951.012000 ;
  END
 END pi3[89]
 PIN pi3[90]
  DIRECTION OUTPUT ;
  USE SIGNAL ;
  PORT
   LAYER M4 ;
   RECT 302.208000 951.180000 302.400000 951.204000 ;
  END
 END pi3[90]
 PIN pi3[91]
  DIRECTION OUTPUT ;
  USE SIGNAL ;
  PORT
   LAYER M4 ;
   RECT 302.208000 951.372000 302.400000 951.396000 ;
  END
 END pi3[91]
 PIN pi3[92]
  DIRECTION OUTPUT ;
  USE SIGNAL ;
  PORT
   LAYER M4 ;
   RECT 302.208000 951.564000 302.400000 951.588000 ;
  END
 END pi3[92]
 PIN pi3[93]
  DIRECTION OUTPUT ;
  USE SIGNAL ;
  PORT
   LAYER M4 ;
   RECT 302.208000 951.756000 302.400000 951.780000 ;
  END
 END pi3[93]
 PIN pi3[94]
  DIRECTION OUTPUT ;
  USE SIGNAL ;
  PORT
   LAYER M4 ;
   RECT 302.208000 951.948000 302.400000 951.972000 ;
  END
 END pi3[94]
 PIN pi3[95]
  DIRECTION OUTPUT ;
  USE SIGNAL ;
  PORT
   LAYER M4 ;
   RECT 302.208000 952.140000 302.400000 952.164000 ;
  END
 END pi3[95]
 PIN pi3[96]
  DIRECTION OUTPUT ;
  USE SIGNAL ;
  PORT
   LAYER M4 ;
   RECT 302.208000 952.332000 302.400000 952.356000 ;
  END
 END pi3[96]
 PIN pi3[97]
  DIRECTION OUTPUT ;
  USE SIGNAL ;
  PORT
   LAYER M4 ;
   RECT 302.208000 952.524000 302.400000 952.548000 ;
  END
 END pi3[97]
 PIN pi3[98]
  DIRECTION OUTPUT ;
  USE SIGNAL ;
  PORT
   LAYER M4 ;
   RECT 302.208000 952.716000 302.400000 952.740000 ;
  END
 END pi3[98]
 PIN pi3[99]
  DIRECTION OUTPUT ;
  USE SIGNAL ;
  PORT
   LAYER M4 ;
   RECT 302.208000 952.908000 302.400000 952.932000 ;
  END
 END pi3[99]
 PIN pi3[100]
  DIRECTION OUTPUT ;
  USE SIGNAL ;
  PORT
   LAYER M4 ;
   RECT 302.208000 953.100000 302.400000 953.124000 ;
  END
 END pi3[100]
 PIN pi3[101]
  DIRECTION OUTPUT ;
  USE SIGNAL ;
  PORT
   LAYER M4 ;
   RECT 302.208000 953.292000 302.400000 953.316000 ;
  END
 END pi3[101]
 PIN pi3[102]
  DIRECTION OUTPUT ;
  USE SIGNAL ;
  PORT
   LAYER M4 ;
   RECT 302.208000 953.484000 302.400000 953.508000 ;
  END
 END pi3[102]
 PIN pi3[103]
  DIRECTION OUTPUT ;
  USE SIGNAL ;
  PORT
   LAYER M4 ;
   RECT 302.208000 953.676000 302.400000 953.700000 ;
  END
 END pi3[103]
 PIN pi3[104]
  DIRECTION OUTPUT ;
  USE SIGNAL ;
  PORT
   LAYER M4 ;
   RECT 302.208000 953.868000 302.400000 953.892000 ;
  END
 END pi3[104]
 PIN pi3[105]
  DIRECTION OUTPUT ;
  USE SIGNAL ;
  PORT
   LAYER M4 ;
   RECT 302.208000 954.060000 302.400000 954.084000 ;
  END
 END pi3[105]
 PIN pi3[106]
  DIRECTION OUTPUT ;
  USE SIGNAL ;
  PORT
   LAYER M4 ;
   RECT 302.208000 954.252000 302.400000 954.276000 ;
  END
 END pi3[106]
 PIN pi3[107]
  DIRECTION OUTPUT ;
  USE SIGNAL ;
  PORT
   LAYER M4 ;
   RECT 302.208000 954.444000 302.400000 954.468000 ;
  END
 END pi3[107]
 PIN pi3[108]
  DIRECTION OUTPUT ;
  USE SIGNAL ;
  PORT
   LAYER M4 ;
   RECT 302.208000 954.636000 302.400000 954.660000 ;
  END
 END pi3[108]
 PIN pi3[109]
  DIRECTION OUTPUT ;
  USE SIGNAL ;
  PORT
   LAYER M4 ;
   RECT 302.208000 954.828000 302.400000 954.852000 ;
  END
 END pi3[109]
 PIN pi3[110]
  DIRECTION OUTPUT ;
  USE SIGNAL ;
  PORT
   LAYER M4 ;
   RECT 302.208000 955.020000 302.400000 955.044000 ;
  END
 END pi3[110]
 PIN pi3[111]
  DIRECTION OUTPUT ;
  USE SIGNAL ;
  PORT
   LAYER M4 ;
   RECT 302.208000 955.212000 302.400000 955.236000 ;
  END
 END pi3[111]
 PIN pi3[112]
  DIRECTION OUTPUT ;
  USE SIGNAL ;
  PORT
   LAYER M4 ;
   RECT 302.208000 955.404000 302.400000 955.428000 ;
  END
 END pi3[112]
 PIN pi3[113]
  DIRECTION OUTPUT ;
  USE SIGNAL ;
  PORT
   LAYER M4 ;
   RECT 302.208000 955.596000 302.400000 955.620000 ;
  END
 END pi3[113]
 PIN pi3[114]
  DIRECTION OUTPUT ;
  USE SIGNAL ;
  PORT
   LAYER M4 ;
   RECT 302.208000 955.788000 302.400000 955.812000 ;
  END
 END pi3[114]
 PIN pi3[115]
  DIRECTION OUTPUT ;
  USE SIGNAL ;
  PORT
   LAYER M4 ;
   RECT 302.208000 955.980000 302.400000 956.004000 ;
  END
 END pi3[115]
 PIN pi3[116]
  DIRECTION OUTPUT ;
  USE SIGNAL ;
  PORT
   LAYER M4 ;
   RECT 302.208000 956.172000 302.400000 956.196000 ;
  END
 END pi3[116]
 PIN pi3[117]
  DIRECTION OUTPUT ;
  USE SIGNAL ;
  PORT
   LAYER M4 ;
   RECT 302.208000 956.364000 302.400000 956.388000 ;
  END
 END pi3[117]
 PIN pi3[118]
  DIRECTION OUTPUT ;
  USE SIGNAL ;
  PORT
   LAYER M4 ;
   RECT 302.208000 956.556000 302.400000 956.580000 ;
  END
 END pi3[118]
 PIN pi3[119]
  DIRECTION OUTPUT ;
  USE SIGNAL ;
  PORT
   LAYER M4 ;
   RECT 302.208000 956.748000 302.400000 956.772000 ;
  END
 END pi3[119]
 PIN pi3[120]
  DIRECTION OUTPUT ;
  USE SIGNAL ;
  PORT
   LAYER M4 ;
   RECT 302.208000 956.940000 302.400000 956.964000 ;
  END
 END pi3[120]
 PIN pi3[121]
  DIRECTION OUTPUT ;
  USE SIGNAL ;
  PORT
   LAYER M4 ;
   RECT 302.208000 957.132000 302.400000 957.156000 ;
  END
 END pi3[121]
 PIN pi3[122]
  DIRECTION OUTPUT ;
  USE SIGNAL ;
  PORT
   LAYER M4 ;
   RECT 302.208000 957.324000 302.400000 957.348000 ;
  END
 END pi3[122]
 PIN pi3[123]
  DIRECTION OUTPUT ;
  USE SIGNAL ;
  PORT
   LAYER M4 ;
   RECT 302.208000 957.516000 302.400000 957.540000 ;
  END
 END pi3[123]
 PIN pi3[124]
  DIRECTION OUTPUT ;
  USE SIGNAL ;
  PORT
   LAYER M4 ;
   RECT 302.208000 957.708000 302.400000 957.732000 ;
  END
 END pi3[124]
 PIN pi3[125]
  DIRECTION OUTPUT ;
  USE SIGNAL ;
  PORT
   LAYER M4 ;
   RECT 302.208000 957.900000 302.400000 957.924000 ;
  END
 END pi3[125]
 PIN pi3[126]
  DIRECTION OUTPUT ;
  USE SIGNAL ;
  PORT
   LAYER M4 ;
   RECT 302.208000 958.092000 302.400000 958.116000 ;
  END
 END pi3[126]
 PIN pi3[127]
  DIRECTION OUTPUT ;
  USE SIGNAL ;
  PORT
   LAYER M4 ;
   RECT 302.208000 958.284000 302.400000 958.308000 ;
  END
 END pi3[127]
 PIN pi3[128]
  DIRECTION OUTPUT ;
  USE SIGNAL ;
  PORT
   LAYER M4 ;
   RECT 302.208000 958.476000 302.400000 958.500000 ;
  END
 END pi3[128]
 PIN pi3[129]
  DIRECTION OUTPUT ;
  USE SIGNAL ;
  PORT
   LAYER M4 ;
   RECT 302.208000 958.668000 302.400000 958.692000 ;
  END
 END pi3[129]
 PIN pi3[130]
  DIRECTION OUTPUT ;
  USE SIGNAL ;
  PORT
   LAYER M4 ;
   RECT 302.208000 958.860000 302.400000 958.884000 ;
  END
 END pi3[130]
 PIN pi3[131]
  DIRECTION OUTPUT ;
  USE SIGNAL ;
  PORT
   LAYER M4 ;
   RECT 302.208000 959.052000 302.400000 959.076000 ;
  END
 END pi3[131]
 PIN pi3[132]
  DIRECTION OUTPUT ;
  USE SIGNAL ;
  PORT
   LAYER M4 ;
   RECT 302.208000 959.244000 302.400000 959.268000 ;
  END
 END pi3[132]
 PIN pi3[133]
  DIRECTION OUTPUT ;
  USE SIGNAL ;
  PORT
   LAYER M4 ;
   RECT 302.208000 959.436000 302.400000 959.460000 ;
  END
 END pi3[133]
 PIN pi3[134]
  DIRECTION OUTPUT ;
  USE SIGNAL ;
  PORT
   LAYER M4 ;
   RECT 302.208000 959.628000 302.400000 959.652000 ;
  END
 END pi3[134]
 PIN pi3[135]
  DIRECTION OUTPUT ;
  USE SIGNAL ;
  PORT
   LAYER M4 ;
   RECT 302.208000 959.820000 302.400000 959.844000 ;
  END
 END pi3[135]
 PIN pi3[136]
  DIRECTION OUTPUT ;
  USE SIGNAL ;
  PORT
   LAYER M4 ;
   RECT 302.208000 960.012000 302.400000 960.036000 ;
  END
 END pi3[136]
 PIN pi3[137]
  DIRECTION OUTPUT ;
  USE SIGNAL ;
  PORT
   LAYER M4 ;
   RECT 302.208000 960.204000 302.400000 960.228000 ;
  END
 END pi3[137]
 PIN pi3[138]
  DIRECTION OUTPUT ;
  USE SIGNAL ;
  PORT
   LAYER M4 ;
   RECT 302.208000 960.396000 302.400000 960.420000 ;
  END
 END pi3[138]
 PIN pi3[139]
  DIRECTION OUTPUT ;
  USE SIGNAL ;
  PORT
   LAYER M4 ;
   RECT 302.208000 960.588000 302.400000 960.612000 ;
  END
 END pi3[139]
 PIN pi3[140]
  DIRECTION OUTPUT ;
  USE SIGNAL ;
  PORT
   LAYER M4 ;
   RECT 302.208000 960.780000 302.400000 960.804000 ;
  END
 END pi3[140]
 PIN pi3[141]
  DIRECTION OUTPUT ;
  USE SIGNAL ;
  PORT
   LAYER M4 ;
   RECT 302.208000 960.972000 302.400000 960.996000 ;
  END
 END pi3[141]
 PIN pi3[142]
  DIRECTION OUTPUT ;
  USE SIGNAL ;
  PORT
   LAYER M4 ;
   RECT 302.208000 961.164000 302.400000 961.188000 ;
  END
 END pi3[142]
 PIN pi3[143]
  DIRECTION OUTPUT ;
  USE SIGNAL ;
  PORT
   LAYER M4 ;
   RECT 302.208000 961.356000 302.400000 961.380000 ;
  END
 END pi3[143]
 PIN pi3[144]
  DIRECTION OUTPUT ;
  USE SIGNAL ;
  PORT
   LAYER M4 ;
   RECT 302.208000 961.548000 302.400000 961.572000 ;
  END
 END pi3[144]
 PIN pi3[145]
  DIRECTION OUTPUT ;
  USE SIGNAL ;
  PORT
   LAYER M4 ;
   RECT 302.208000 961.740000 302.400000 961.764000 ;
  END
 END pi3[145]
 PIN pi3[146]
  DIRECTION OUTPUT ;
  USE SIGNAL ;
  PORT
   LAYER M4 ;
   RECT 302.208000 961.932000 302.400000 961.956000 ;
  END
 END pi3[146]
 PIN pi3[147]
  DIRECTION OUTPUT ;
  USE SIGNAL ;
  PORT
   LAYER M4 ;
   RECT 302.208000 962.124000 302.400000 962.148000 ;
  END
 END pi3[147]
 PIN pi3[148]
  DIRECTION OUTPUT ;
  USE SIGNAL ;
  PORT
   LAYER M4 ;
   RECT 302.208000 962.316000 302.400000 962.340000 ;
  END
 END pi3[148]
 PIN pi3[149]
  DIRECTION OUTPUT ;
  USE SIGNAL ;
  PORT
   LAYER M4 ;
   RECT 302.208000 962.508000 302.400000 962.532000 ;
  END
 END pi3[149]
 PIN pi3[150]
  DIRECTION OUTPUT ;
  USE SIGNAL ;
  PORT
   LAYER M4 ;
   RECT 302.208000 962.700000 302.400000 962.724000 ;
  END
 END pi3[150]
 PIN pi3[151]
  DIRECTION OUTPUT ;
  USE SIGNAL ;
  PORT
   LAYER M4 ;
   RECT 302.208000 962.892000 302.400000 962.916000 ;
  END
 END pi3[151]
 PIN pi3[152]
  DIRECTION OUTPUT ;
  USE SIGNAL ;
  PORT
   LAYER M4 ;
   RECT 302.208000 963.084000 302.400000 963.108000 ;
  END
 END pi3[152]
 PIN pi3[153]
  DIRECTION OUTPUT ;
  USE SIGNAL ;
  PORT
   LAYER M4 ;
   RECT 302.208000 963.276000 302.400000 963.300000 ;
  END
 END pi3[153]
 PIN pi3[154]
  DIRECTION OUTPUT ;
  USE SIGNAL ;
  PORT
   LAYER M4 ;
   RECT 302.208000 963.468000 302.400000 963.492000 ;
  END
 END pi3[154]
 PIN pi3[155]
  DIRECTION OUTPUT ;
  USE SIGNAL ;
  PORT
   LAYER M4 ;
   RECT 302.208000 963.660000 302.400000 963.684000 ;
  END
 END pi3[155]
 PIN pi3[156]
  DIRECTION OUTPUT ;
  USE SIGNAL ;
  PORT
   LAYER M4 ;
   RECT 302.208000 963.852000 302.400000 963.876000 ;
  END
 END pi3[156]
 PIN pi3[157]
  DIRECTION OUTPUT ;
  USE SIGNAL ;
  PORT
   LAYER M4 ;
   RECT 302.208000 964.044000 302.400000 964.068000 ;
  END
 END pi3[157]
 PIN pi3[158]
  DIRECTION OUTPUT ;
  USE SIGNAL ;
  PORT
   LAYER M4 ;
   RECT 302.208000 964.236000 302.400000 964.260000 ;
  END
 END pi3[158]
 PIN pi3[159]
  DIRECTION OUTPUT ;
  USE SIGNAL ;
  PORT
   LAYER M4 ;
   RECT 302.208000 964.428000 302.400000 964.452000 ;
  END
 END pi3[159]
 PIN pi3[160]
  DIRECTION OUTPUT ;
  USE SIGNAL ;
  PORT
   LAYER M4 ;
   RECT 302.208000 964.620000 302.400000 964.644000 ;
  END
 END pi3[160]
 PIN pi3[161]
  DIRECTION OUTPUT ;
  USE SIGNAL ;
  PORT
   LAYER M4 ;
   RECT 302.208000 964.812000 302.400000 964.836000 ;
  END
 END pi3[161]
 PIN pi3[162]
  DIRECTION OUTPUT ;
  USE SIGNAL ;
  PORT
   LAYER M4 ;
   RECT 302.208000 965.004000 302.400000 965.028000 ;
  END
 END pi3[162]
 PIN pi3[163]
  DIRECTION OUTPUT ;
  USE SIGNAL ;
  PORT
   LAYER M4 ;
   RECT 302.208000 965.196000 302.400000 965.220000 ;
  END
 END pi3[163]
 PIN pi3[164]
  DIRECTION OUTPUT ;
  USE SIGNAL ;
  PORT
   LAYER M4 ;
   RECT 302.208000 965.388000 302.400000 965.412000 ;
  END
 END pi3[164]
 PIN pi3[165]
  DIRECTION OUTPUT ;
  USE SIGNAL ;
  PORT
   LAYER M4 ;
   RECT 302.208000 965.580000 302.400000 965.604000 ;
  END
 END pi3[165]
 PIN pi3[166]
  DIRECTION OUTPUT ;
  USE SIGNAL ;
  PORT
   LAYER M4 ;
   RECT 302.208000 965.772000 302.400000 965.796000 ;
  END
 END pi3[166]
 PIN pi3[167]
  DIRECTION OUTPUT ;
  USE SIGNAL ;
  PORT
   LAYER M4 ;
   RECT 302.208000 965.964000 302.400000 965.988000 ;
  END
 END pi3[167]
 PIN pi3[168]
  DIRECTION OUTPUT ;
  USE SIGNAL ;
  PORT
   LAYER M4 ;
   RECT 302.208000 966.156000 302.400000 966.180000 ;
  END
 END pi3[168]
 PIN pi3[169]
  DIRECTION OUTPUT ;
  USE SIGNAL ;
  PORT
   LAYER M4 ;
   RECT 302.208000 966.348000 302.400000 966.372000 ;
  END
 END pi3[169]
 PIN pi3[170]
  DIRECTION OUTPUT ;
  USE SIGNAL ;
  PORT
   LAYER M4 ;
   RECT 302.208000 966.540000 302.400000 966.564000 ;
  END
 END pi3[170]
 PIN pi3[171]
  DIRECTION OUTPUT ;
  USE SIGNAL ;
  PORT
   LAYER M4 ;
   RECT 302.208000 966.732000 302.400000 966.756000 ;
  END
 END pi3[171]
 PIN pi3[172]
  DIRECTION OUTPUT ;
  USE SIGNAL ;
  PORT
   LAYER M4 ;
   RECT 302.208000 966.924000 302.400000 966.948000 ;
  END
 END pi3[172]
 PIN pi3[173]
  DIRECTION OUTPUT ;
  USE SIGNAL ;
  PORT
   LAYER M4 ;
   RECT 302.208000 967.116000 302.400000 967.140000 ;
  END
 END pi3[173]
 PIN pi3[174]
  DIRECTION OUTPUT ;
  USE SIGNAL ;
  PORT
   LAYER M4 ;
   RECT 302.208000 967.308000 302.400000 967.332000 ;
  END
 END pi3[174]
 PIN pi3[175]
  DIRECTION OUTPUT ;
  USE SIGNAL ;
  PORT
   LAYER M4 ;
   RECT 302.208000 967.500000 302.400000 967.524000 ;
  END
 END pi3[175]
 PIN pi3[176]
  DIRECTION OUTPUT ;
  USE SIGNAL ;
  PORT
   LAYER M4 ;
   RECT 302.208000 967.692000 302.400000 967.716000 ;
  END
 END pi3[176]
 PIN pi3[177]
  DIRECTION OUTPUT ;
  USE SIGNAL ;
  PORT
   LAYER M4 ;
   RECT 302.208000 967.884000 302.400000 967.908000 ;
  END
 END pi3[177]
 PIN pi3[178]
  DIRECTION OUTPUT ;
  USE SIGNAL ;
  PORT
   LAYER M4 ;
   RECT 302.208000 968.076000 302.400000 968.100000 ;
  END
 END pi3[178]
 PIN pi3[179]
  DIRECTION OUTPUT ;
  USE SIGNAL ;
  PORT
   LAYER M4 ;
   RECT 302.208000 968.268000 302.400000 968.292000 ;
  END
 END pi3[179]
 PIN pi3[180]
  DIRECTION OUTPUT ;
  USE SIGNAL ;
  PORT
   LAYER M4 ;
   RECT 302.208000 968.460000 302.400000 968.484000 ;
  END
 END pi3[180]
 PIN pi3[181]
  DIRECTION OUTPUT ;
  USE SIGNAL ;
  PORT
   LAYER M4 ;
   RECT 302.208000 968.652000 302.400000 968.676000 ;
  END
 END pi3[181]
 PIN pi3[182]
  DIRECTION OUTPUT ;
  USE SIGNAL ;
  PORT
   LAYER M4 ;
   RECT 302.208000 968.844000 302.400000 968.868000 ;
  END
 END pi3[182]
 PIN pi3[183]
  DIRECTION OUTPUT ;
  USE SIGNAL ;
  PORT
   LAYER M4 ;
   RECT 302.208000 969.036000 302.400000 969.060000 ;
  END
 END pi3[183]
 PIN pi3[184]
  DIRECTION OUTPUT ;
  USE SIGNAL ;
  PORT
   LAYER M4 ;
   RECT 302.208000 969.228000 302.400000 969.252000 ;
  END
 END pi3[184]
 PIN pi3[185]
  DIRECTION OUTPUT ;
  USE SIGNAL ;
  PORT
   LAYER M4 ;
   RECT 302.208000 969.420000 302.400000 969.444000 ;
  END
 END pi3[185]
 PIN pi3[186]
  DIRECTION OUTPUT ;
  USE SIGNAL ;
  PORT
   LAYER M4 ;
   RECT 302.208000 969.612000 302.400000 969.636000 ;
  END
 END pi3[186]
 PIN pi3[187]
  DIRECTION OUTPUT ;
  USE SIGNAL ;
  PORT
   LAYER M4 ;
   RECT 302.208000 969.804000 302.400000 969.828000 ;
  END
 END pi3[187]
 PIN pi3[188]
  DIRECTION OUTPUT ;
  USE SIGNAL ;
  PORT
   LAYER M4 ;
   RECT 302.208000 969.996000 302.400000 970.020000 ;
  END
 END pi3[188]
 PIN pi3[189]
  DIRECTION OUTPUT ;
  USE SIGNAL ;
  PORT
   LAYER M4 ;
   RECT 302.208000 970.188000 302.400000 970.212000 ;
  END
 END pi3[189]
 PIN pi3[190]
  DIRECTION OUTPUT ;
  USE SIGNAL ;
  PORT
   LAYER M4 ;
   RECT 302.208000 970.380000 302.400000 970.404000 ;
  END
 END pi3[190]
 PIN pi3[191]
  DIRECTION OUTPUT ;
  USE SIGNAL ;
  PORT
   LAYER M4 ;
   RECT 302.208000 970.572000 302.400000 970.596000 ;
  END
 END pi3[191]
 PIN pi3[192]
  DIRECTION OUTPUT ;
  USE SIGNAL ;
  PORT
   LAYER M4 ;
   RECT 302.208000 970.764000 302.400000 970.788000 ;
  END
 END pi3[192]
 PIN pi3[193]
  DIRECTION OUTPUT ;
  USE SIGNAL ;
  PORT
   LAYER M4 ;
   RECT 302.208000 970.956000 302.400000 970.980000 ;
  END
 END pi3[193]
 PIN pi3[194]
  DIRECTION OUTPUT ;
  USE SIGNAL ;
  PORT
   LAYER M4 ;
   RECT 302.208000 971.148000 302.400000 971.172000 ;
  END
 END pi3[194]
 PIN pi3[195]
  DIRECTION OUTPUT ;
  USE SIGNAL ;
  PORT
   LAYER M4 ;
   RECT 302.208000 971.340000 302.400000 971.364000 ;
  END
 END pi3[195]
 PIN pi3[196]
  DIRECTION OUTPUT ;
  USE SIGNAL ;
  PORT
   LAYER M4 ;
   RECT 302.208000 971.532000 302.400000 971.556000 ;
  END
 END pi3[196]
 PIN pi3[197]
  DIRECTION OUTPUT ;
  USE SIGNAL ;
  PORT
   LAYER M4 ;
   RECT 302.208000 971.724000 302.400000 971.748000 ;
  END
 END pi3[197]
 PIN pi3[198]
  DIRECTION OUTPUT ;
  USE SIGNAL ;
  PORT
   LAYER M4 ;
   RECT 302.208000 971.916000 302.400000 971.940000 ;
  END
 END pi3[198]
 PIN pi3[199]
  DIRECTION OUTPUT ;
  USE SIGNAL ;
  PORT
   LAYER M4 ;
   RECT 302.208000 972.108000 302.400000 972.132000 ;
  END
 END pi3[199]
 PIN pi3[200]
  DIRECTION OUTPUT ;
  USE SIGNAL ;
  PORT
   LAYER M4 ;
   RECT 302.208000 972.300000 302.400000 972.324000 ;
  END
 END pi3[200]
 PIN pi3[201]
  DIRECTION OUTPUT ;
  USE SIGNAL ;
  PORT
   LAYER M4 ;
   RECT 302.208000 972.492000 302.400000 972.516000 ;
  END
 END pi3[201]
 PIN pi3[202]
  DIRECTION OUTPUT ;
  USE SIGNAL ;
  PORT
   LAYER M4 ;
   RECT 302.208000 972.684000 302.400000 972.708000 ;
  END
 END pi3[202]
 PIN pi3[203]
  DIRECTION OUTPUT ;
  USE SIGNAL ;
  PORT
   LAYER M4 ;
   RECT 302.208000 972.876000 302.400000 972.900000 ;
  END
 END pi3[203]
 PIN pi3[204]
  DIRECTION OUTPUT ;
  USE SIGNAL ;
  PORT
   LAYER M4 ;
   RECT 302.208000 973.068000 302.400000 973.092000 ;
  END
 END pi3[204]
 PIN pi3[205]
  DIRECTION OUTPUT ;
  USE SIGNAL ;
  PORT
   LAYER M4 ;
   RECT 302.208000 973.260000 302.400000 973.284000 ;
  END
 END pi3[205]
 PIN pi3[206]
  DIRECTION OUTPUT ;
  USE SIGNAL ;
  PORT
   LAYER M4 ;
   RECT 302.208000 973.452000 302.400000 973.476000 ;
  END
 END pi3[206]
 PIN pi3[207]
  DIRECTION OUTPUT ;
  USE SIGNAL ;
  PORT
   LAYER M4 ;
   RECT 302.208000 973.644000 302.400000 973.668000 ;
  END
 END pi3[207]
 PIN pi3[208]
  DIRECTION OUTPUT ;
  USE SIGNAL ;
  PORT
   LAYER M4 ;
   RECT 302.208000 973.836000 302.400000 973.860000 ;
  END
 END pi3[208]
 PIN pi3[209]
  DIRECTION OUTPUT ;
  USE SIGNAL ;
  PORT
   LAYER M4 ;
   RECT 302.208000 974.028000 302.400000 974.052000 ;
  END
 END pi3[209]
 PIN pi3[210]
  DIRECTION OUTPUT ;
  USE SIGNAL ;
  PORT
   LAYER M4 ;
   RECT 302.208000 974.220000 302.400000 974.244000 ;
  END
 END pi3[210]
 PIN pi3[211]
  DIRECTION OUTPUT ;
  USE SIGNAL ;
  PORT
   LAYER M4 ;
   RECT 302.208000 974.412000 302.400000 974.436000 ;
  END
 END pi3[211]
 PIN pi3[212]
  DIRECTION OUTPUT ;
  USE SIGNAL ;
  PORT
   LAYER M4 ;
   RECT 302.208000 974.604000 302.400000 974.628000 ;
  END
 END pi3[212]
 PIN pi3[213]
  DIRECTION OUTPUT ;
  USE SIGNAL ;
  PORT
   LAYER M4 ;
   RECT 302.208000 974.796000 302.400000 974.820000 ;
  END
 END pi3[213]
 PIN pi3[214]
  DIRECTION OUTPUT ;
  USE SIGNAL ;
  PORT
   LAYER M4 ;
   RECT 302.208000 974.988000 302.400000 975.012000 ;
  END
 END pi3[214]
 PIN pi3[215]
  DIRECTION OUTPUT ;
  USE SIGNAL ;
  PORT
   LAYER M4 ;
   RECT 302.208000 975.180000 302.400000 975.204000 ;
  END
 END pi3[215]
 PIN pi3[216]
  DIRECTION OUTPUT ;
  USE SIGNAL ;
  PORT
   LAYER M4 ;
   RECT 302.208000 975.372000 302.400000 975.396000 ;
  END
 END pi3[216]
 PIN pi3[217]
  DIRECTION OUTPUT ;
  USE SIGNAL ;
  PORT
   LAYER M4 ;
   RECT 302.208000 975.564000 302.400000 975.588000 ;
  END
 END pi3[217]
 PIN pi3[218]
  DIRECTION OUTPUT ;
  USE SIGNAL ;
  PORT
   LAYER M4 ;
   RECT 302.208000 975.756000 302.400000 975.780000 ;
  END
 END pi3[218]
 PIN pi3[219]
  DIRECTION OUTPUT ;
  USE SIGNAL ;
  PORT
   LAYER M4 ;
   RECT 302.208000 975.948000 302.400000 975.972000 ;
  END
 END pi3[219]
 PIN pi3[220]
  DIRECTION OUTPUT ;
  USE SIGNAL ;
  PORT
   LAYER M4 ;
   RECT 302.208000 976.140000 302.400000 976.164000 ;
  END
 END pi3[220]
 PIN pi3[221]
  DIRECTION OUTPUT ;
  USE SIGNAL ;
  PORT
   LAYER M4 ;
   RECT 302.208000 976.332000 302.400000 976.356000 ;
  END
 END pi3[221]
 PIN pi3[222]
  DIRECTION OUTPUT ;
  USE SIGNAL ;
  PORT
   LAYER M4 ;
   RECT 302.208000 976.524000 302.400000 976.548000 ;
  END
 END pi3[222]
 PIN pi3[223]
  DIRECTION OUTPUT ;
  USE SIGNAL ;
  PORT
   LAYER M4 ;
   RECT 302.208000 976.716000 302.400000 976.740000 ;
  END
 END pi3[223]
 PIN pi3[224]
  DIRECTION OUTPUT ;
  USE SIGNAL ;
  PORT
   LAYER M4 ;
   RECT 302.208000 976.908000 302.400000 976.932000 ;
  END
 END pi3[224]
 PIN pi3[225]
  DIRECTION OUTPUT ;
  USE SIGNAL ;
  PORT
   LAYER M4 ;
   RECT 302.208000 977.100000 302.400000 977.124000 ;
  END
 END pi3[225]
 PIN pi3[226]
  DIRECTION OUTPUT ;
  USE SIGNAL ;
  PORT
   LAYER M4 ;
   RECT 302.208000 977.292000 302.400000 977.316000 ;
  END
 END pi3[226]
 PIN pi3[227]
  DIRECTION OUTPUT ;
  USE SIGNAL ;
  PORT
   LAYER M4 ;
   RECT 302.208000 977.484000 302.400000 977.508000 ;
  END
 END pi3[227]
 PIN pi3[228]
  DIRECTION OUTPUT ;
  USE SIGNAL ;
  PORT
   LAYER M4 ;
   RECT 302.208000 977.676000 302.400000 977.700000 ;
  END
 END pi3[228]
 PIN pi3[229]
  DIRECTION OUTPUT ;
  USE SIGNAL ;
  PORT
   LAYER M4 ;
   RECT 302.208000 977.868000 302.400000 977.892000 ;
  END
 END pi3[229]
 PIN pi3[230]
  DIRECTION OUTPUT ;
  USE SIGNAL ;
  PORT
   LAYER M4 ;
   RECT 302.208000 978.060000 302.400000 978.084000 ;
  END
 END pi3[230]
 PIN pi3[231]
  DIRECTION OUTPUT ;
  USE SIGNAL ;
  PORT
   LAYER M4 ;
   RECT 302.208000 978.252000 302.400000 978.276000 ;
  END
 END pi3[231]
 PIN pi3[232]
  DIRECTION OUTPUT ;
  USE SIGNAL ;
  PORT
   LAYER M4 ;
   RECT 302.208000 978.444000 302.400000 978.468000 ;
  END
 END pi3[232]
 PIN pi3[233]
  DIRECTION OUTPUT ;
  USE SIGNAL ;
  PORT
   LAYER M4 ;
   RECT 302.208000 978.636000 302.400000 978.660000 ;
  END
 END pi3[233]
 PIN pi3[234]
  DIRECTION OUTPUT ;
  USE SIGNAL ;
  PORT
   LAYER M4 ;
   RECT 302.208000 978.828000 302.400000 978.852000 ;
  END
 END pi3[234]
 PIN pi3[235]
  DIRECTION OUTPUT ;
  USE SIGNAL ;
  PORT
   LAYER M4 ;
   RECT 302.208000 979.020000 302.400000 979.044000 ;
  END
 END pi3[235]
 PIN pi3[236]
  DIRECTION OUTPUT ;
  USE SIGNAL ;
  PORT
   LAYER M4 ;
   RECT 302.208000 979.212000 302.400000 979.236000 ;
  END
 END pi3[236]
 PIN pi3[237]
  DIRECTION OUTPUT ;
  USE SIGNAL ;
  PORT
   LAYER M4 ;
   RECT 302.208000 979.404000 302.400000 979.428000 ;
  END
 END pi3[237]
 PIN pi3[238]
  DIRECTION OUTPUT ;
  USE SIGNAL ;
  PORT
   LAYER M4 ;
   RECT 302.208000 979.596000 302.400000 979.620000 ;
  END
 END pi3[238]
 PIN pi3[239]
  DIRECTION OUTPUT ;
  USE SIGNAL ;
  PORT
   LAYER M4 ;
   RECT 302.208000 979.788000 302.400000 979.812000 ;
  END
 END pi3[239]
 PIN pi3[240]
  DIRECTION OUTPUT ;
  USE SIGNAL ;
  PORT
   LAYER M4 ;
   RECT 302.208000 979.980000 302.400000 980.004000 ;
  END
 END pi3[240]
 PIN pi3[241]
  DIRECTION OUTPUT ;
  USE SIGNAL ;
  PORT
   LAYER M4 ;
   RECT 302.208000 980.172000 302.400000 980.196000 ;
  END
 END pi3[241]
 PIN pi3[242]
  DIRECTION OUTPUT ;
  USE SIGNAL ;
  PORT
   LAYER M4 ;
   RECT 302.208000 980.364000 302.400000 980.388000 ;
  END
 END pi3[242]
 PIN pi3[243]
  DIRECTION OUTPUT ;
  USE SIGNAL ;
  PORT
   LAYER M4 ;
   RECT 302.208000 980.556000 302.400000 980.580000 ;
  END
 END pi3[243]
 PIN pi3[244]
  DIRECTION OUTPUT ;
  USE SIGNAL ;
  PORT
   LAYER M4 ;
   RECT 302.208000 980.748000 302.400000 980.772000 ;
  END
 END pi3[244]
 PIN pi3[245]
  DIRECTION OUTPUT ;
  USE SIGNAL ;
  PORT
   LAYER M4 ;
   RECT 302.208000 980.940000 302.400000 980.964000 ;
  END
 END pi3[245]
 PIN pi3[246]
  DIRECTION OUTPUT ;
  USE SIGNAL ;
  PORT
   LAYER M4 ;
   RECT 302.208000 981.132000 302.400000 981.156000 ;
  END
 END pi3[246]
 PIN pi3[247]
  DIRECTION OUTPUT ;
  USE SIGNAL ;
  PORT
   LAYER M4 ;
   RECT 302.208000 981.324000 302.400000 981.348000 ;
  END
 END pi3[247]
 PIN pi3[248]
  DIRECTION OUTPUT ;
  USE SIGNAL ;
  PORT
   LAYER M4 ;
   RECT 302.208000 981.516000 302.400000 981.540000 ;
  END
 END pi3[248]
 PIN pi3[249]
  DIRECTION OUTPUT ;
  USE SIGNAL ;
  PORT
   LAYER M4 ;
   RECT 302.208000 981.708000 302.400000 981.732000 ;
  END
 END pi3[249]
 PIN pi3[250]
  DIRECTION OUTPUT ;
  USE SIGNAL ;
  PORT
   LAYER M4 ;
   RECT 302.208000 981.900000 302.400000 981.924000 ;
  END
 END pi3[250]
 PIN pi3[251]
  DIRECTION OUTPUT ;
  USE SIGNAL ;
  PORT
   LAYER M4 ;
   RECT 302.208000 982.092000 302.400000 982.116000 ;
  END
 END pi3[251]
 PIN pi3[252]
  DIRECTION OUTPUT ;
  USE SIGNAL ;
  PORT
   LAYER M4 ;
   RECT 302.208000 982.284000 302.400000 982.308000 ;
  END
 END pi3[252]
 PIN pi3[253]
  DIRECTION OUTPUT ;
  USE SIGNAL ;
  PORT
   LAYER M4 ;
   RECT 302.208000 982.476000 302.400000 982.500000 ;
  END
 END pi3[253]
 PIN pi3[254]
  DIRECTION OUTPUT ;
  USE SIGNAL ;
  PORT
   LAYER M4 ;
   RECT 302.208000 982.668000 302.400000 982.692000 ;
  END
 END pi3[254]
 PIN pi3[255]
  DIRECTION OUTPUT ;
  USE SIGNAL ;
  PORT
   LAYER M4 ;
   RECT 302.208000 982.860000 302.400000 982.884000 ;
  END
 END pi3[255]
 PIN pi3[256]
  DIRECTION OUTPUT ;
  USE SIGNAL ;
  PORT
   LAYER M4 ;
   RECT 302.208000 983.052000 302.400000 983.076000 ;
  END
 END pi3[256]
 PIN pi3[257]
  DIRECTION OUTPUT ;
  USE SIGNAL ;
  PORT
   LAYER M4 ;
   RECT 302.208000 983.244000 302.400000 983.268000 ;
  END
 END pi3[257]
 PIN pi3[258]
  DIRECTION OUTPUT ;
  USE SIGNAL ;
  PORT
   LAYER M4 ;
   RECT 302.208000 983.436000 302.400000 983.460000 ;
  END
 END pi3[258]
 PIN pi3[259]
  DIRECTION OUTPUT ;
  USE SIGNAL ;
  PORT
   LAYER M4 ;
   RECT 302.208000 983.628000 302.400000 983.652000 ;
  END
 END pi3[259]
 PIN pi3[260]
  DIRECTION OUTPUT ;
  USE SIGNAL ;
  PORT
   LAYER M4 ;
   RECT 302.208000 983.820000 302.400000 983.844000 ;
  END
 END pi3[260]
 PIN pi3[261]
  DIRECTION OUTPUT ;
  USE SIGNAL ;
  PORT
   LAYER M4 ;
   RECT 302.208000 984.012000 302.400000 984.036000 ;
  END
 END pi3[261]
 PIN pi3[262]
  DIRECTION OUTPUT ;
  USE SIGNAL ;
  PORT
   LAYER M4 ;
   RECT 302.208000 984.204000 302.400000 984.228000 ;
  END
 END pi3[262]
 PIN pi3[263]
  DIRECTION OUTPUT ;
  USE SIGNAL ;
  PORT
   LAYER M4 ;
   RECT 302.208000 984.396000 302.400000 984.420000 ;
  END
 END pi3[263]
 PIN pi3[264]
  DIRECTION OUTPUT ;
  USE SIGNAL ;
  PORT
   LAYER M4 ;
   RECT 302.208000 984.588000 302.400000 984.612000 ;
  END
 END pi3[264]
 PIN pi3[265]
  DIRECTION OUTPUT ;
  USE SIGNAL ;
  PORT
   LAYER M4 ;
   RECT 302.208000 984.780000 302.400000 984.804000 ;
  END
 END pi3[265]
 PIN pi3[266]
  DIRECTION OUTPUT ;
  USE SIGNAL ;
  PORT
   LAYER M4 ;
   RECT 302.208000 984.972000 302.400000 984.996000 ;
  END
 END pi3[266]
 PIN pi3[267]
  DIRECTION OUTPUT ;
  USE SIGNAL ;
  PORT
   LAYER M4 ;
   RECT 302.208000 985.164000 302.400000 985.188000 ;
  END
 END pi3[267]
 PIN pi3[268]
  DIRECTION OUTPUT ;
  USE SIGNAL ;
  PORT
   LAYER M4 ;
   RECT 302.208000 985.356000 302.400000 985.380000 ;
  END
 END pi3[268]
 PIN pi3[269]
  DIRECTION OUTPUT ;
  USE SIGNAL ;
  PORT
   LAYER M4 ;
   RECT 302.208000 985.548000 302.400000 985.572000 ;
  END
 END pi3[269]
 PIN pi3[270]
  DIRECTION OUTPUT ;
  USE SIGNAL ;
  PORT
   LAYER M4 ;
   RECT 302.208000 985.740000 302.400000 985.764000 ;
  END
 END pi3[270]
 PIN pi3[271]
  DIRECTION OUTPUT ;
  USE SIGNAL ;
  PORT
   LAYER M4 ;
   RECT 302.208000 985.932000 302.400000 985.956000 ;
  END
 END pi3[271]
 PIN pi3[272]
  DIRECTION OUTPUT ;
  USE SIGNAL ;
  PORT
   LAYER M4 ;
   RECT 302.208000 986.124000 302.400000 986.148000 ;
  END
 END pi3[272]
 PIN pi3[273]
  DIRECTION OUTPUT ;
  USE SIGNAL ;
  PORT
   LAYER M4 ;
   RECT 302.208000 986.316000 302.400000 986.340000 ;
  END
 END pi3[273]
 PIN pi3[274]
  DIRECTION OUTPUT ;
  USE SIGNAL ;
  PORT
   LAYER M4 ;
   RECT 302.208000 986.508000 302.400000 986.532000 ;
  END
 END pi3[274]
 PIN pi3[275]
  DIRECTION OUTPUT ;
  USE SIGNAL ;
  PORT
   LAYER M4 ;
   RECT 302.208000 986.700000 302.400000 986.724000 ;
  END
 END pi3[275]
 PIN pi3[276]
  DIRECTION OUTPUT ;
  USE SIGNAL ;
  PORT
   LAYER M4 ;
   RECT 302.208000 986.892000 302.400000 986.916000 ;
  END
 END pi3[276]
 PIN pi3[277]
  DIRECTION OUTPUT ;
  USE SIGNAL ;
  PORT
   LAYER M4 ;
   RECT 302.208000 987.084000 302.400000 987.108000 ;
  END
 END pi3[277]
 PIN pi3[278]
  DIRECTION OUTPUT ;
  USE SIGNAL ;
  PORT
   LAYER M4 ;
   RECT 302.208000 987.276000 302.400000 987.300000 ;
  END
 END pi3[278]
 PIN pi3[279]
  DIRECTION OUTPUT ;
  USE SIGNAL ;
  PORT
   LAYER M4 ;
   RECT 302.208000 987.468000 302.400000 987.492000 ;
  END
 END pi3[279]
 PIN pi3[280]
  DIRECTION OUTPUT ;
  USE SIGNAL ;
  PORT
   LAYER M4 ;
   RECT 302.208000 987.660000 302.400000 987.684000 ;
  END
 END pi3[280]
 PIN pi3[281]
  DIRECTION OUTPUT ;
  USE SIGNAL ;
  PORT
   LAYER M4 ;
   RECT 302.208000 987.852000 302.400000 987.876000 ;
  END
 END pi3[281]
 PIN pi3[282]
  DIRECTION OUTPUT ;
  USE SIGNAL ;
  PORT
   LAYER M4 ;
   RECT 302.208000 988.044000 302.400000 988.068000 ;
  END
 END pi3[282]
 PIN pi3[283]
  DIRECTION OUTPUT ;
  USE SIGNAL ;
  PORT
   LAYER M4 ;
   RECT 302.208000 988.236000 302.400000 988.260000 ;
  END
 END pi3[283]
 PIN pi3[284]
  DIRECTION OUTPUT ;
  USE SIGNAL ;
  PORT
   LAYER M4 ;
   RECT 302.208000 988.428000 302.400000 988.452000 ;
  END
 END pi3[284]
 PIN pi3[285]
  DIRECTION OUTPUT ;
  USE SIGNAL ;
  PORT
   LAYER M4 ;
   RECT 302.208000 988.620000 302.400000 988.644000 ;
  END
 END pi3[285]
 PIN pi3[286]
  DIRECTION OUTPUT ;
  USE SIGNAL ;
  PORT
   LAYER M4 ;
   RECT 302.208000 988.812000 302.400000 988.836000 ;
  END
 END pi3[286]
 PIN pi3[287]
  DIRECTION OUTPUT ;
  USE SIGNAL ;
  PORT
   LAYER M4 ;
   RECT 302.208000 989.004000 302.400000 989.028000 ;
  END
 END pi3[287]
 PIN pi3[288]
  DIRECTION OUTPUT ;
  USE SIGNAL ;
  PORT
   LAYER M4 ;
   RECT 302.208000 989.196000 302.400000 989.220000 ;
  END
 END pi3[288]
 PIN fh3[0]
  DIRECTION OUTPUT ;
  USE SIGNAL ;
  PORT
   LAYER M4 ;
   RECT 302.208000 989.388000 302.400000 989.412000 ;
  END
 END fh3[0]
 PIN fh3[1]
  DIRECTION OUTPUT ;
  USE SIGNAL ;
  PORT
   LAYER M4 ;
   RECT 302.208000 989.580000 302.400000 989.604000 ;
  END
 END fh3[1]
 PIN fh3[2]
  DIRECTION OUTPUT ;
  USE SIGNAL ;
  PORT
   LAYER M4 ;
   RECT 302.208000 989.772000 302.400000 989.796000 ;
  END
 END fh3[2]
 PIN fh3[3]
  DIRECTION OUTPUT ;
  USE SIGNAL ;
  PORT
   LAYER M4 ;
   RECT 302.208000 989.964000 302.400000 989.988000 ;
  END
 END fh3[3]
 PIN rh3[0]
  DIRECTION OUTPUT ;
  USE SIGNAL ;
  PORT
   LAYER M4 ;
   RECT 302.208000 990.156000 302.400000 990.180000 ;
  END
 END rh3[0]
 PIN rh3[1]
  DIRECTION OUTPUT ;
  USE SIGNAL ;
  PORT
   LAYER M4 ;
   RECT 302.208000 990.348000 302.400000 990.372000 ;
  END
 END rh3[1]
 PIN rh3[2]
  DIRECTION OUTPUT ;
  USE SIGNAL ;
  PORT
   LAYER M4 ;
   RECT 302.208000 990.540000 302.400000 990.564000 ;
  END
 END rh3[2]
 PIN rh3[3]
  DIRECTION OUTPUT ;
  USE SIGNAL ;
  PORT
   LAYER M4 ;
   RECT 302.208000 990.732000 302.400000 990.756000 ;
  END
 END rh3[3]
 PIN VDD
  DIRECTION INOUT ;
  USE POWER ;
  PORT
   LAYER M6 ;
   RECT 4.32 4.32 298.08 4.608 ;
  END
 END VDD
 PIN VSS
  DIRECTION INOUT ;
  USE GROUND ;
  PORT
   LAYER M6 ;
   RECT 4.32 6.72 298.08 7.008 ;
  END
 END VSS
 OBS
  LAYER M1 ;
   RECT 0.4 0.4 302 1500.8 ;
  LAYER M2 ;
   RECT 0.4 0.4 302 1500.8 ;
  LAYER M3 ;
   RECT 0.4 0.4 302 1500.8 ;
  LAYER M4 ;
   RECT 0.4 0.4 302 1500.8 ;
  LAYER M5 ;
   RECT 0.4 0.4 302 1500.8 ;
  LAYER M6 ;
   RECT 0.4 0.4 302 1500.8 ;
  LAYER M7 ;
   RECT 0.4 0.4 302 4.224 ;
   RECT 0.4 4.704 302 6.624 ;
   RECT 0.4 7.104 302 1500.8 ;
 END
END qkd_hbm3e_phy_pc4
END LIBRARY
